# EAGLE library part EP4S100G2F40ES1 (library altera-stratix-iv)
EP4S100G2F40ES1 edit this description Auto generated by make-symbol-device-package-bsdl.ulp Rev. 29 Source: EP4S100G2F40ES1.bsd

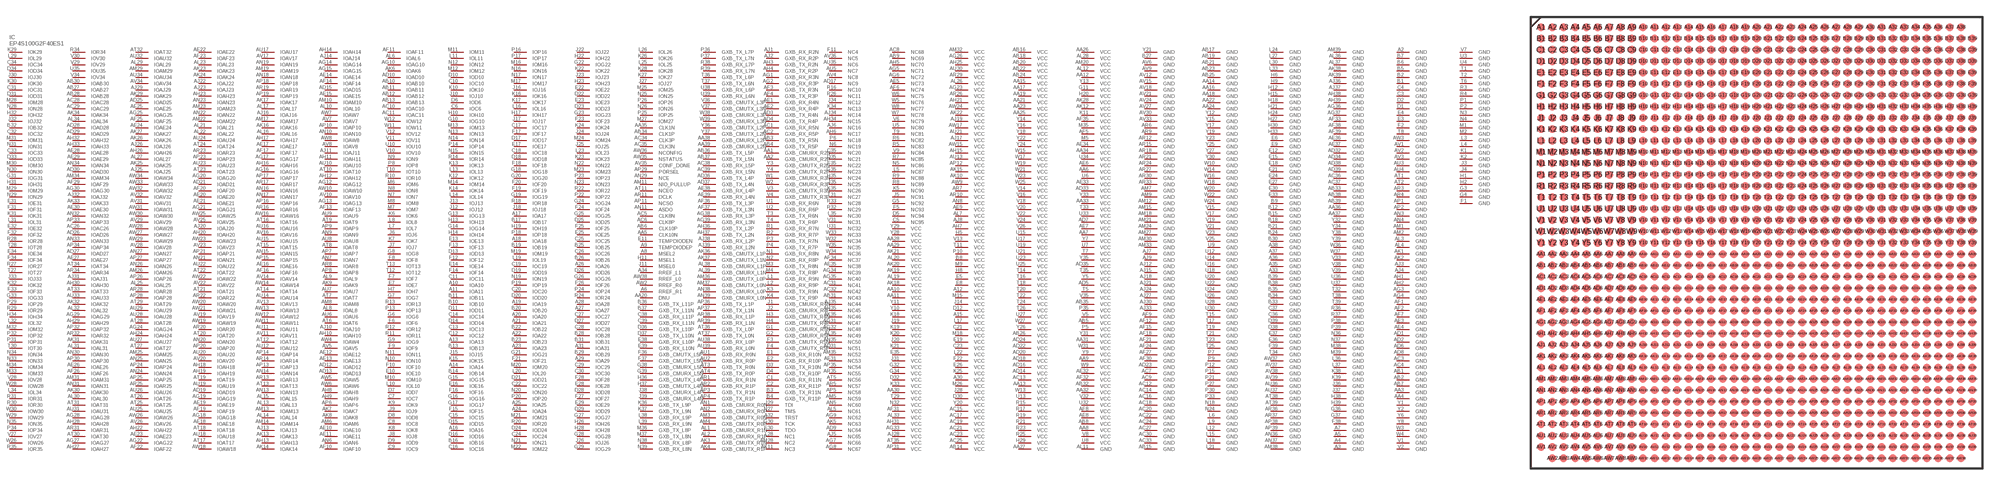
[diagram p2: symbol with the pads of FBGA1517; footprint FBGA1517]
Designator prefix IC

## EP4S100G2F40ES1 (MPN: EP4S100G2F40C2ES1; OC_FARNELL: unknown; OC_NEWARK: 52R2079)  [FBGA1517]
A2  GND  pwr
A3  GND  pwr
A4  GND  pwr
A5  GND  pwr
A6  RREF_R1  pas
A7  GND  pwr
A8  MSEL2  in
A9  TEMPDIODEP  in
A10  IOA10
A11  IOA11
A12  VCC  pwr
A13  IOA13
A14  IOA14
A15  VCC  pwr
A16  IOA16
A17  IOA17
A18  IOA18
A19  IOA19
A20  IOA20
A21  IOA21
A22  IOA22
A23  IOA23
A24  IOA24
A25  IOA25
A26  IOA26
A27  IOA27
A28  IOA28
A29  IOA29
A30  VCC  pwr
A31  IOA31
A32  TRST  in
A33  GND  pwr
A34  RREF_L1  pas
A35  GND  pwr
A36  GND  pwr
A37  GND  pwr
A38  GND  pwr
AA1  GXB_CMURX_R2N  pas
AA2  GXB_CMURX_R2P  pas
AA3  GND  pwr
AA4  GND  pwr
AA5  CLK10N  in
AA6  VCC  pwr
AA7  VCC  pwr
AA8  VCC  pwr
AA9  VCC  pwr
AA10  VCC  pwr
AA11  VCC  pwr
AA12  VCC  pwr
AA13  VCC  pwr
AA14  GND  pwr
AA15  VCC  pwr
AA16  GND  pwr
AA17  VCC  pwr
AA18  GND  pwr
AA19  VCC  pwr
AA20  DNU  pas
AA21  VCC  pwr
AA22  GND  pwr
AA23  VCC  pwr
AA24  GND  pwr
AA25  VCC  pwr
AA26  VCC  pwr
AA27  VCC  pwr
AA28  VCC  pwr
AA29  VCC  pwr
AA30  VCC  pwr
AA31  VCC  pwr
AA32  VCC  pwr
AA33  VCC  pwr
AA34  VCC  pwr
AA35  CLK1N  in
AA36  GND  pwr
AA37  GND  pwr
AA38  GXB_CMURX_L2P  pas
AA39  GXB_CMURX_L2N  pas
AB1  GND  pwr
AB2  GND  pwr
AB3  GXB_TX_R5N  pas
AB4  GXB_TX_R5P  pas
AB5  VCC  pwr
AB6  CLK10P  in
AB7  GND  pwr
AB8  VCC  pwr
AB9  NC69  pas
AB10  IOAB10
AB11  IOAB11
AB12  IOAB12
AB13  IOAB13
AB14  VCC  pwr
AB15  GND  pwr
AB16  VCC  pwr
AB17  GND  pwr
AB18  VCC  pwr
AB19  GND  pwr
AB20  VCC  pwr
AB21  GND  pwr
AB22  VCC  pwr
AB23  GND  pwr
AB24  VCC  pwr
AB25  GND  pwr
AB26  VCC  pwr
AB27  IOAB27
AB28  IOAB28
AB30  IOAB30
AB31  NC43  pas
AB32  VCC  pwr
AB33  GND  pwr
AB34  CLK1P  in
AB35  VCC  pwr
AB36  GXB_TX_L5P  pas
AB37  GXB_TX_L5N  pas
AB38  GND  pwr
AB39  GND  pwr
AC1  GXB_RX_R5N  pas
AC2  GXB_RX_R5P  pas
AC3  GND  pwr
AC4  GND  pwr
AC5  CLK8N  in
AC6  CLK8P  in
AC7  GND  pwr
AC8  NC68  pas
AC9  GND  pwr
AC10  IOAC10
AC11  IOAC11
AC12  GND  pwr
AC13  VCC  pwr
AC14  GND  pwr
AC15  VCC  pwr
AC16  GND  pwr
AC17  VCC  pwr
AC18  GND  pwr
AC19  VCC  pwr
AC20  GND  pwr
AC21  VCC  pwr
AC22  GND  pwr
AC23  VCC  pwr
AC24  GND  pwr
AC25  VCC  pwr
AC26  IOAC26
AC27  GND  pwr
AC28  IOAC28
AC29  IOAC29
AC30  GND  pwr
AC31  NC41  pas
AC32  NC42  pas
AC33  GND  pwr
AC34  CLK3P  in
AC35  CLK3N  in
AC36  GND  pwr
AC37  GND  pwr
AC38  GXB_RX_L5P  pas
AC39  GXB_RX_L5N  pas
AD1  GND  pwr
AD2  GND  pwr
AD3  GXB_TX_R4N  pas
AD4  GXB_TX_R4P  pas
AD5  VCC  pwr
AD6  GND  pwr
AD7  VCC  pwr
AD8  GND  pwr
AD9  NC64  pas
AD10  IOAD10
AD12  IOAD12
AD13  IOAD13
AD14  VCC  pwr
AD15  IOAD15
AD16  VCC  pwr
AD17  NC9  pas
AD18  VCC  pwr
AD19  IOAD19
AD20  VCC  pwr
AD21  IOAD21
AD22  VCC  pwr
AD23  GND  pwr
AD24  VCC  pwr
AD25  IOAD25
AD26  IOAD26
AD27  IOAD27
AD28  IOAD28
AD29  IOAD29
AD30  IOAD30
AD31  NC51  pas
AD32  GND  pwr
AD33  VCC  pwr
AD34  GND  pwr
AD35  VCC  pwr
AD36  GXB_TX_L4P  pas
AD37  GXB_TX_L4N  pas
AD38  GND  pwr
AD39  GND  pwr
AE1  GXB_RX_R4N  pas
AE2  GXB_RX_R4P  pas
AE3  GND  pwr
AE4  GND  pwr
AE5  NC73  pas
AE6  VCC  pwr
AE7  VCC  pwr
AE8  VCC  pwr
AE9  VCC  pwr
AE10  IOAE10
AE11  IOAE11
AE12  IOAE12
AE13  IOAE13
AE14  IOAE14
AE15  IOAE15
AE16  IOAE16
AE17  IOAE17
AE18  IOAE18
AE19  IOAE19
AE20  IOAE20
AE21  IOAE21
AE22  IOAE22
AE23  IOAE23
AE24  IOAE24
AE25  IOAE25
AE26  IOAE26
AE27  IOAE27
AE28  IOAE28
AE29  IOAE29
AE30  IOAE30
AE31  NC53  pas
AE32  VCC  pwr
AE33  VCC  pwr
AE34  VCC  pwr
AE35  NC38  pas
AE36  GND  pwr
AE37  GND  pwr
AE38  GXB_RX_L4P  pas
AE39  GXB_RX_L4N  pas
AF1  GND  pwr
AF2  GND  pwr
AF3  GXB_TX_R3N  pas
AF4  GXB_TX_R3P  pas
AF5  VCC  pwr
AF6  NC74  pas
AF7  GND  pwr
AF8  VCC  pwr
AF9  GND  pwr
AF10  IOAF10
AF11  IOAF11
AF12  GND  pwr
AF13  IOAF13
AF14  IOAF14
AF15  GND  pwr
AF16  IOAF16
AF17  IOAF17
AF18  GND  pwr
AF19  IOAF19
AF20  IOAF20
AF21  GND  pwr
AF22  IOAF22
AF23  IOAF23
AF24  GND  pwr
AF25  IOAF25
AF26  IOAF26
AF27  GND  pwr
AF29  IOAF29
AF30  GND  pwr
AF31  VCC  pwr
AF32  VCC  pwr
AF33  GND  pwr
AF34  NC37  pas
AF35  VCC  pwr
AF36  GXB_TX_L3P  pas
AF37  GXB_TX_L3N  pas
AF38  GND  pwr
AF39  GND  pwr
AG1  GXB_RX_R3N  pas
AG2  GXB_RX_R3P  pas
AG3  GND  pwr
AG4  GND  pwr
AG5  NC71  pas
AG6  NC72  pas
AG7  NC66  pas
AG8  NC67  pas
AG9  NC62  pas
AG10  IOAG10
AG12  IOAG12
AG13  IOAG13
AG14  IOAG14
AG15  IOAG15
AG16  IOAG16
AG17  IOAG17
AG18  IOAG18
AG19  IOAG19
AG20  IOAG20
AG21  IOAG21
AG22  IOAG22
AG23  VCC  pwr
AG24  IOAG24
AG25  IOAG25
AG26  VCC  pwr
AG27  IOAG27
AG28  IOAG28
AG29  IOAG29
AG30  IOAG30
AG31  NC47  pas
AG32  NC48  pas
AG33  VCC  pwr
AG34  NC39  pas
AG35  NC40  pas
AG36  GND  pwr
AG37  GND  pwr
AG38  GXB_RX_L3P  pas
AG39  GXB_RX_L3N  pas
AH1  GND  pwr
AH2  GND  pwr
AH3  GXB_TX_R2N  pas
AH4  GXB_TX_R2P  pas
AH5  NC70  pas
AH6  NC17  pas
AH7  VCC  pwr
AH8  IOAH8
AH9  IOAH9
AH10  IOAH10
AH11  IOAH11
AH12  IOAH12
AH13  IOAH13
AH14  IOAH14
AH15  VCC  pwr
AH16  IOAH16
AH17  IOAH17
AH18  IOAH18
AH19  IOAH19
AH20  IOAH20
AH21  VCC  pwr
AH22  IOAH22
AH23  IOAH23
AH24  IOAH24
AH25  VCC  pwr
AH26  IOAH26
AH27  IOAH27
AH28  IOAH28
AH29  IOAH29
AH30  IOAH30
AH31  VCC  pwr
AH32  IOAH32
AH33  IOAH33
AH34  NC15  pas
AH35  NC45  pas
AH36  GXB_TX_L2P  pas
AH37  GXB_TX_L2N  pas
AH38  GND  pwr
AH39  GND  pwr
AJ1  GXB_RX_R2N  pas
AJ2  GXB_RX_R2P  pas
AJ3  GND  pwr
AJ4  GND  pwr
AJ5  NC65  pas
AJ6  NC16  pas
AJ7  GND  pwr
AJ8  VCC  pwr
AJ9  GND  pwr
AJ10  IOAJ10
AJ11  IOAJ11
AJ12  GND  pwr
AJ13  IOAJ13
AJ14  IOAJ14
AJ15  GND  pwr
AJ16  IOAJ16
AJ17  VCC  pwr
AJ18  GND  pwr
AJ19  VCC  pwr
AJ20  IOAJ20
AJ21  GND  pwr
AJ22  IOAJ22
AJ23  IOAJ23
AJ24  GND  pwr
AJ25  IOAJ25
AJ26  IOAJ26
AJ27  GND  pwr
AJ28  VCC  pwr
AJ29  IOAJ29
AJ30  GND  pwr
AJ31  IOAJ31
AJ32  IOAJ32
AJ33  GND  pwr
AJ34  NC14  pas
AJ35  NC44  pas
AJ36  GND  pwr
AJ37  GND  pwr
AJ38  GXB_RX_L2P  pas
AJ39  GXB_RX_L2N  pas
AK1  GND  pwr
AK2  GND  pwr
AK3  GXB_CMUTX_R1N  pas
AK4  GXB_CMUTX_R1P  pas
AK5  NC63  pas
AK6  IOAK6
AK7  IOAK7
AK8  IOAK8
AK9  IOAK9
AK10  VCC  pwr
AK11  NC3  pas
AK12  VCC  pwr
AK13  IOAK13
AK14  IOAK14
AK15  VCC  pwr
AK16  IOAK16
AK17  IOAK17
AK18  VCC  pwr
AK19  VCC  pwr
AK20  VCC  pwr
AK21  VCC  pwr
AK22  VCC  pwr
AK23  IOAK23
AK24  IOAK24
AK25  IOAK25
AK26  IOAK26
AK27  IOAK27
AK28  VCC  pwr
AK29  IOAK29
AK30  IOAK30
AK31  IOAK31
AK32  IOAK32
AK33  IOAK33
AK34  IOAK34
AK35  NC46  pas
AK36  GXB_CMUTX_L1P  pas
AK37  GXB_CMUTX_L1N  pas
AK38  GND  pwr
AK39  GND  pwr
AL1  GXB_CMURX_R1N  pas
AL2  GXB_CMURX_R1P  pas
AL3  GND  pwr
AL4  GND  pwr
AL5  NC61  pas
AL6  IOAL6
AL7  VCC  pwr
AL8  IOAL8
AL9  IOAL9
AL10  IOAL10
AL11  GND  pwr
AL12  VCC  pwr
AL13  IOAL13
AL14  IOAL14
AL15  IOAL15
AL16  IOAL16
AL17  IOAL17
AL19  VCC  pwr
AL20  VCC  pwr
AL21  IOAL21
AL22  IOAL22
AL23  IOAL23
AL25  IOAL25
AL26  VCC  pwr
AL27  IOAL27
AL28  VCC  pwr
AL29  IOAL29
AL30  IOAL30
AL31  IOAL31
AL32  IOAL32
AL33  VCC  pwr
AL34  IOAL34
AL35  NC49  pas
AL36  GND  pwr
AL37  GND  pwr
AL38  GXB_CMURX_L1P  pas
AL39  GXB_CMURX_L1N  pas
AM1  GND  pwr
AM2  GND  pwr
AM3  GXB_CMUTX_R0N  pas
AM4  GXB_CMUTX_R0P  pas
AM5  NC59  pas
AM6  IOAM6
AM7  GND  pwr
AM8  IOAM8
AM9  GND  pwr
AM10  IOAM10
AM11  NIO_PULLUP  in
AM12  GND  pwr
AM13  IOAM13
AM14  IOAM14
AM15  GND  pwr
AM17  IOAM17
AM18  GND  pwr
AM19  IOAM19
AM20  VCC  pwr
AM21  GND  pwr
AM22  IOAM22
AM23  IOAM23
AM24  GND  pwr
AM25  IOAM25
AM26  IOAM26
AM27  GND  pwr
AM28  NC2  pas
AM29  IOAM29
AM30  GND  pwr
AM31  IOAM31
AM32  VCC  pwr
AM33  GND  pwr
AM34  IOAM34
AM35  NC52  pas
AM36  GXB_CMUTX_L0P  pas
AM37  GXB_CMUTX_L0N  pas
AM38  GND  pwr
AM39  GND  pwr
AN1  GXB_CMURX_R0N  pas
AN2  GXB_CMURX_R0P  pas
AN3  GND  pwr
AN4  GND  pwr
AN5  NC60  pas
AN6  IOAN6
AN7  IOAN7
AN8  VCC  pwr
AN9  IOAN9
AN10  IOAN10
AN11  ASDO  in
AN13  IOAN13
AN14  IOAN14
AN15  IOAN15
AN16  IOAN16
AN17  IOAN17
AN18  IOAN18
AN19  IOAN19
AN20  IOAN20
AN21  IOAN21
AN22  IOAN22
AN23  IOAN23
AN24  IOAN24
AN25  IOAN25
AN26  IOAN26
AN27  IOAN27
AN29  NCE  in
AN30  IOAN30
AN31  IOAN31
AN32  IOAN32
AN33  IOAN33
AN34  IOAN34
AN35  NC50  pas
AN36  GND  pwr
AN37  GND  pwr
AN38  GXB_CMURX_L0P  pas
AN39  GXB_CMURX_L0N  pas
AP1  GND  pwr
AP2  GND  pwr
AP3  GXB_TX_R1N  pas
AP4  GXB_TX_R1P  pas
AP5  NC58  pas
AP6  IOAP6
AP7  IOAP7
AP8  IOAP8
AP9  IOAP9
AP10  IOAP10
AP11  NCSO  in
AP12  VCC  pwr
AP13  IOAP13
AP14  IOAP14
AP15  IOAP15
AP16  IOAP16
AP17  IOAP17
AP18  IOAP18
AP19  IOAP19
AP20  IOAP20
AP21  IOAP21
AP23  IOAP23
AP24  IOAP24
AP25  IOAP25
AP26  IOAP26
AP27  IOAP27
AP28  IOAP28
AP29  PORSEL  in
AP30  IOAP30
AP31  VCC  pwr
AP32  IOAP32
AP33  IOAP33
AP34  IOAP34
AP35  NC54  pas
AP36  GXB_TX_L1P  pas
AP37  GXB_TX_L1N  pas
AP38  GND  pwr
AP39  GND  pwr
AR1  GXB_RX_R1N  pas
AR2  GXB_RX_R1P  pas
AR3  GND  pwr
AR4  GND  pwr
AR5  NC57  pas
AR6  GND  pwr
AR7  VCC  pwr
AR8  IOAR8
AR9  GND  pwr
AR10  VCC  pwr
AR11  DCLK  in
AR12  GND  pwr
AR13  IOAR13
AR14  IOAR14
AR15  GND  pwr
AR16  IOAR16
AR17  IOAR17
AR18  GND  pwr
AR19  IOAR19
AR20  IOAR20
AR21  GND  pwr
AR22  IOAR22
AR23  IOAR23
AR24  GND  pwr
AR25  IOAR25
AR26  VCC  pwr
AR27  GND  pwr
AR28  IOAR28
AR29  VCC  pwr
AR30  GND  pwr
AR31  IOAR31
AR32  IOAR32
AR33  GND  pwr
AR34  IOAR34
AR35  NC55  pas
AR36  GND  pwr
AR37  GND  pwr
AR38  GXB_RX_L1P  pas
AR39  GXB_RX_L1N  pas
AT1  GND  pwr
AT2  GND  pwr
AT3  GXB_TX_R0N  pas
AT4  GXB_TX_R0P  pas
AT5  NC56  pas
AT6  IOAT6
AT7  IOAT7
AT8  IOAT8
AT9  IOAT9
AT10  IOAT10
AT11  NCEO  in
AT12  IOAT12
AT13  IOAT13
AT14  IOAT14
AT15  IOAT15
AT16  IOAT16
AT17  IOAT17
AT18  IOAT18
AT19  IOAT19
AT20  IOAT20
AT21  IOAT21
AT22  IOAT22
AT23  IOAT23
AT24  IOAT24
AT25  IOAT25
AT26  IOAT26
AT27  IOAT27
AT28  IOAT28
AT29  IOAT29
AT30  IOAT30
AT31  IOAT31
AT32  IOAT32
AT33  IOAT33
AT34  IOAT34
AT35  VCC  pwr
AT36  GXB_TX_L0P  pas
AT37  GXB_TX_L0N  pas
AT38  GND  pwr
AT39  GND  pwr
AU1  GXB_RX_R0N  pas
AU2  GXB_RX_R0P  pas
AU3  GND  pwr
AU4  GND  pwr
AU5  NC7  pas
AU6  IOAU6
AU7  IOAU7
AU8  IOAU8
AU9  IOAU9
AU10  IOAU10
AU11  IOAU11
AU12  IOAU12
AU13  VCC  pwr
AU14  IOAU14
AU15  IOAU15
AU16  IOAU16
AU17  IOAU17
AU18  IOAU18
AU19  IOAU19
AU20  IOAU20
AU21  VCC  pwr
AU22  IOAU22
AU23  IOAU23
AU24  IOAU24
AU25  IOAU25
AU26  IOAU26
AU27  IOAU27
AU28  IOAU28
AU29  IOAU29
AU30  VCC  pwr
AU31  IOAU31
AU32  IOAU32
AU33  IOAU33
AU34  IOAU34
AU35  NC6  pas
AU36  GND  pwr
AU37  GND  pwr
AU38  GXB_RX_L0P  pas
AU39  GXB_RX_L0N  pas
AV1  GND  pwr
AV2  GND  pwr
AV3  GND  pwr
AV4  NC8  pas
AV5  IOAV5
AV6  GND  pwr
AV7  IOAV7
AV8  IOAV8
AV9  GND  pwr
AV10  IOAV10
AV11  IOAV11
AV12  GND  pwr
AV13  IOAV13
AV14  IOAV14
AV15  GND  pwr
AV16  IOAV16
AV17  IOAV17
AV18  GND  pwr
AV19  IOAV19
AV20  IOAV20
AV21  GND  pwr
AV22  IOAV22
AV23  IOAV23
AV24  GND  pwr
AV25  IOAV25
AV26  IOAV26
AV27  GND  pwr
AV28  IOAV28
AV29  IOAV29
AV30  GND  pwr
AV31  IOAV31
AV32  IOAV32
AV33  GND  pwr
AV34  IOAV34
AV35  CONF_DONE  in
AV36  NC5  pas
AV37  GND  pwr
AV38  GND  pwr
AV39  GND  pwr
AW2  RREF_R0  pas
AW3  GND  pwr
AW4  IOAW4
AW5  IOAW5
AW6  IOAW6
AW7  IOAW7
AW8  IOAW8
AW9  VCC  pwr
AW10  IOAW10
AW11  IOAW11
AW12  IOAW12
AW13  IOAW13
AW14  IOAW14
AW15  VCC  pwr
AW16  IOAW16
AW17  VCC  pwr
AW18  IOAW18
AW19  IOAW19
AW20  IOAW20
AW21  IOAW21
AW22  IOAW22
AW23  IOAW23
AW24  VCC  pwr
AW25  IOAW25
AW26  IOAW26
AW27  IOAW27
AW28  IOAW28
AW29  IOAW29
AW30  IOAW30
AW31  IOAW31
AW32  IOAW32
AW33  IOAW33
AW34  IOAW34
AW35  NSTATUS  in
AW36  NCONFIG  in
AW37  GND  pwr
AW38  RREF_L0  pas
B1  GND  pwr
B2  GND  pwr
B3  GXB_TX_R11N  pas
B4  GXB_TX_R11P  pas
B5  GND  pwr
B6  GND  pwr
B7  GND  pwr
B8  VCC  pwr
B9  GND  pwr
B10  IOB10
B11  IOB11
B12  GND  pwr
B13  IOB13
B14  IOB14
B15  GND  pwr
B16  IOB16
B17  IOB17
B18  GND  pwr
B19  IOB19
B20  IOB20
B21  GND  pwr
B22  IOB22
B23  IOB23
B24  GND  pwr
B25  IOB25
B26  IOB26
B27  GND  pwr
B28  IOB28
B29  IOB29
B30  GND  pwr
B31  IOB31
B32  IOB32
B33  GND  pwr
B34  GND  pwr
B35  GND  pwr
B36  GXB_TX_L11P  pas
B37  GXB_TX_L11N  pas
B38  GND  pwr
B39  GND  pwr
C1  GXB_RX_R11N  pas
C2  GXB_RX_R11P  pas
C3  GND  pwr
C4  GND  pwr
C5  NC95  pas
C6  IOC6
C7  IOC7
C8  IOC8
C9  IOC9
C10  IOC10
C11  IOC11
C12  IOC12
C13  IOC13
C14  IOC14
C15  IOC15
C16  IOC16
C17  IOC17
C18  IOC18
C19  IOC19
C20  IOC20
C21  VCC  pwr
C22  IOC22
C23  VCC  pwr
C24  IOC24
C25  IOC25
C26  IOC26
C27  IOC27
C28  IOC28
C29  IOC29
C30  IOC30
C31  IOC31
C32  IOC32
C33  IOC33
C34  IOC34
C35  NC20  pas
C36  GND  pwr
C37  GND  pwr
C38  GXB_RX_L11P  pas
C39  GXB_RX_L11N  pas
D1  GND  pwr
D2  GND  pwr
D3  GXB_TX_R10N  pas
D4  GXB_TX_R10P  pas
D5  NC94  pas
D6  IOD6
D7  IOD7
D8  IOD8
D9  IOD9
D10  IOD10
D11  IOD11
D12  VCC  pwr
D13  IOD13
D14  IOD14
D15  IOD15
D16  IOD16
D17  IOD17
D18  IOD18
D19  IOD19
D20  IOD20
D21  IOD21
D22  IOD22
D23  IOD23
D24  IOD24
D25  IOD25
D26  IOD26
D27  IOD27
D28  IOD28
D29  IOD29
D30  VCC  pwr
D31  IOD31
D32  VCC  pwr
D33  IOD33
D34  IOD34
D35  NC21  pas
D36  GXB_TX_L10P  pas
D37  GXB_TX_L10N  pas
D38  GND  pwr
D39  GND  pwr
E1  GXB_RX_R10N  pas
E2  GXB_RX_R10P  pas
E3  GND  pwr
E4  GND  pwr
E5  VCC  pwr
E6  GND  pwr
E7  IOE7
E8  VCC  pwr
E9  GND  pwr
E10  IOE10
E11  TEMPDIODEN  in
E12  GND  pwr
E13  IOE13
E14  IOE14
E15  GND  pwr
E16  IOE16
E17  IOE17
E18  GND  pwr
E19  VCC  pwr
E21  GND  pwr
E22  IOE22
E23  IOE23
E24  GND  pwr
E25  IOE25
E26  VCC  pwr
E27  GND  pwr
E28  IOE28
E29  IOE29
E30  GND  pwr
E31  IOE31
E32  IOE32
E33  GND  pwr
E34  IOE34
E35  VCC  pwr
E36  GND  pwr
E37  GND  pwr
E38  GXB_RX_L10P  pas
E39  GXB_RX_L10N  pas
F1  GND  pwr
F2  GND  pwr
F3  GXB_CMUTX_R5N  pas
F4  GXB_CMUTX_R5P  pas
F5  NC93  pas
F6  IOF6
F7  IOF7
F8  IOF8
F9  IOF9
F10  IOF10
F11  NC4  pas
F12  IOF12
F13  IOF13
F14  IOF14
F15  IOF15
F16  IOF16
F17  IOF17
F18  IOF18
F19  IOF19
F20  IOF20
F21  IOF21
F22  VCC  pwr
F23  IOF23
F24  IOF24
F25  IOF25
F26  IOF26
F27  IOF27
F28  IOF28
F30  TDO  out
F31  IOF31
F32  IOF32
F33  IOF33
F34  IOF34
F35  NC22  pas
F36  GXB_CMUTX_L5P  pas
F37  GXB_CMUTX_L5N  pas
F38  GND  pwr
F39  GND  pwr
G1  GXB_CMURX_R5N  pas
G2  GXB_CMURX_R5P  pas
G3  GND  pwr
G4  GND  pwr
G5  NC92  pas
G6  IOG6
G7  IOG7
G8  IOG8
G9  IOG9
G10  IOG10
G11  VCC  pwr
G13  IOG13
G14  IOG14
G15  IOG15
G16  IOG16
G17  IOG17
G18  IOG18
G19  IOG19
G20  IOG20
G21  IOG21
G22  IOG22
G23  IOG23
G24  IOG24
G25  IOG25
G26  IOG26
G27  IOG27
G28  IOG28
G29  IOG29
G30  TCK  in
G31  IOG31
G32  VCC  pwr
G33  IOG33
G34  VCC  pwr
G35  NC23  pas
G36  GND  pwr
G37  GND  pwr
G38  GXB_CMURX_L5P  pas
G39  GXB_CMURX_L5N  pas
H1  GND  pwr
H2  GND  pwr
H3  GXB_CMUTX_R4N  pas
H4  GXB_CMUTX_R4P  pas
H5  VCC  pwr
H6  GND  pwr
H7  IOH7
H8  VCC  pwr
H9  GND  pwr
H10  IOH10
H11  MSEL1  in
H12  GND  pwr
H13  IOH13
H14  IOH14
H15  GND  pwr
H17  IOH17
H18  GND  pwr
H19  IOH19
H20  VCC  pwr
H21  GND  pwr
H22  IOH22
H23  IOH23
H24  GND  pwr
H26  IOH26
H27  GND  pwr
H28  IOH28
H29  VCC  pwr
H30  GND  pwr
H31  IOH31
H32  IOH32
H33  GND  pwr
H34  IOH34
H35  NC24  pas
H36  GXB_CMUTX_L4P  pas
H37  GXB_CMUTX_L4N  pas
H38  GND  pwr
H39  GND  pwr
J1  GXB_CMURX_R4N  pas
J2  GXB_CMURX_R4P  pas
J3  GND  pwr
J4  GND  pwr
J5  NC91  pas
J6  IOJ6
J7  IOJ7
J8  IOJ8
J9  IOJ9
J10  IOJ10
J11  MSEL0  in
J12  IOJ12
J13  IOJ13
J14  VCC  pwr
J15  IOJ15
J16  IOJ16
J17  IOJ17
J18  IOJ18
J19  VCC  pwr
J20  VCC  pwr
J22  IOJ22
J23  IOJ23
J24  IOJ24
J25  IOJ25
J26  IOJ26
J27  IOJ27
J28  VCC  pwr
J29  TDI  in
J30  IOJ30
J31  VCC  pwr
J32  IOJ32
J33  IOJ33
J34  NC12  pas
J35  NC25  pas
J36  GND  pwr
J37  GND  pwr
J38  GXB_CMURX_L4P  pas
J39  GXB_CMURX_L4N  pas
K1  GND  pwr
K2  GND  pwr
K3  GXB_TX_R9N  pas
K4  GXB_TX_R9P  pas
K5  NC90  pas
K6  IOK6
K7  IOK7
K8  IOK8
K9  IOK9
K10  IOK10
K11  VCC  pwr
K12  IOK12
K13  IOK13
K14  IOK14
K15  IOK15
K16  IOK16
K17  IOK17
K18  VCC  pwr
K19  VCC  pwr
K20  VCC  pwr
K21  VCC  pwr
K22  IOK22
K23  IOK23
K24  IOK24
K25  VCC  pwr
K26  IOK26
K27  IOK27
K28  IOK28
K29  IOK29
K30  IOK30
K31  IOK31
K32  IOK32
K33  VCC  pwr
K34  NC13  pas
K35  NC26  pas
K36  GXB_TX_L9P  pas
K37  GXB_TX_L9N  pas
K38  GND  pwr
K39  GND  pwr
L1  GXB_RX_R9N  pas
L2  GXB_RX_R9P  pas
L3  GND  pwr
L4  GND  pwr
L5  NC87  pas
L6  GND  pwr
L7  IOL7
L8  IOL8
L9  GND  pwr
L10  IOL10
L11  IOL11
L12  GND  pwr
L13  IOL13
L14  IOL14
L15  GND  pwr
L16  IOL16
L17  VCC  pwr
L18  GND  pwr
L19  IOL19
L20  IOL20
L21  GND  pwr
L22  VCC  pwr
L23  IOL23
L24  GND  pwr
L25  IOL25
L26  IOL26
L27  GND  pwr
L28  NC1  pas
L29  IOL29
L30  GND  pwr
L31  IOL31
L32  IOL32
L33  GND  pwr
L34  IOL34
L35  NC30  pas
L36  GND  pwr
L37  GND  pwr
L38  GXB_RX_L9P  pas
L39  GXB_RX_L9N  pas
M1  GND  pwr
M2  GND  pwr
M3  GXB_TX_R8N  pas
M4  GXB_TX_R8P  pas
M5  VCC  pwr
M6  IOM6
M7  IOM7
M8  IOM8
M9  VCC  pwr
M10  IOM10
M11  IOM11
M12  IOM12
M13  IOM13
M14  IOM14
M15  VCC  pwr
M16  IOM16
M17  IOM17
M18  VCC  pwr
M19  IOM19
M20  IOM20
M21  IOM21
M22  IOM22
M23  IOM23
M24  IOM24
M25  IOM25
M26  VCC  pwr
M27  IOM27
M28  IOM28
M29  IOM29
M30  IOM30
M31  IOM31
M32  IOM32
M33  IOM33
M34  IOM34
M35  VCC  pwr
M36  GXB_TX_L8P  pas
M37  GXB_TX_L8N  pas
M38  GND  pwr
M39  GND  pwr
N1  GXB_RX_R8N  pas
N2  GXB_RX_R8P  pas
N3  GND  pwr
N4  GND  pwr
N5  NC86  pas
N6  NC19  pas
N7  ION7
N8  ION8
N9  ION9
N10  ION10
N11  ION11
N12  ION12
N13  ION13
N14  ION14
N15  ION15
N16  ION16
N17  ION17
N18  GND  pwr
N19  ION19
N20  ION20
N21  ION21
N22  ION22
N23  ION23
N24  GND  pwr
N25  ION25
N26  ION26
N27  TMS  in
N28  ION28
N29  ION29
N30  ION30
N31  ION31
N32  VCC  pwr
N33  ION33
N34  ION34
N35  ION35
N36  GND  pwr
N37  GND  pwr
N38  GXB_RX_L8P  pas
N39  GXB_RX_L8N  pas
P1  GND  pwr
P2  GND  pwr
P3  GXB_TX_R7N  pas
P4  GXB_TX_R7P  pas
P5  VCC  pwr
P6  NC18  pas
P7  GND  pwr
P8  IOP8
P9  GND  pwr
P10  VCC  pwr
P12  GND  pwr
P13  IOP13
P14  IOP14
P15  GND  pwr
P16  IOP16
P17  IOP17
P18  IOP18
P19  IOP19
P20  IOP20
P21  GND  pwr
P22  IOP22
P23  IOP23
P24  IOP24
P25  IOP25
P26  IOP26
P27  GND  pwr
P29  IOP29
P30  GND  pwr
P31  IOP31
P32  IOP32
P33  GND  pwr
P34  IOP34
P35  VCC  pwr
P36  GXB_TX_L7P  pas
P37  GXB_TX_L7N  pas
P38  GND  pwr
P39  GND  pwr
R1  GXB_RX_R7N  pas
R2  GXB_RX_R7P  pas
R3  GND  pwr
R4  GND  pwr
R5  NC83  pas
R6  NC82  pas
R7  NC85  pas
R8  NC89  pas
R9  NC88  pas
R10  IOR10
R11  IOR11
R12  IOR12
R13  IOR13
R14  IOR14
R15  VCC  pwr
R16  NC10  pas
R17  VCC  pwr
R18  IOR18
R19  VCC  pwr
R20  IOR20
R21  VCC  pwr
R22  IOR22
R23  VCC  pwr
R24  IOR24
R25  VCC  pwr
R26  NC11  pas
R27  IOR27
R28  IOR28
R29  IOR29
R30  IOR30
R31  IOR31
R32  NC29  pas
R33  NC28  pas
R34  IOR34
R35  IOR35
R36  GND  pwr
R37  GND  pwr
R38  GXB_RX_L7P  pas
R39  GXB_RX_L7N  pas
T1  GND  pwr
T2  GND  pwr
T3  GXB_TX_R6N  pas
T4  GXB_TX_R6P  pas
T5  VCC  pwr
T6  GND  pwr
T7  VCC  pwr
T8  GND  pwr
T9  NC81  pas
T10  IOT10
T11  VCC  pwr
T12  IOT12
T13  IOT13
T14  VCC  pwr
T15  GND  pwr
T16  VCC  pwr
T17  GND  pwr
T18  VCC  pwr
T19  GND  pwr
T20  VCC  pwr
T21  GND  pwr
T22  VCC  pwr
T23  GND  pwr
T24  VCC  pwr
T25  GND  pwr
T26  VCC  pwr
T27  IOT27
T28  IOT28
T29  VCC  pwr
T30  IOT30
T31  NC27  pas
T32  GND  pwr
T33  VCC  pwr
T34  GND  pwr
T35  VCC  pwr
T36  GXB_TX_L6P  pas
T37  GXB_TX_L6N  pas
T38  GND  pwr
T39  GND  pwr
U1  GXB_RX_R6N  pas
U2  GXB_RX_R6P  pas
U3  GND  pwr
U4  GND  pwr
U5  NC80  pas
U6  VCC  pwr
U7  VCC  pwr
U8  VCC  pwr
U9  GND  pwr
U10  IOU10
U12  GND  pwr
U13  VCC  pwr
U14  GND  pwr
U15  VCC  pwr
U16  GND  pwr
U17  VCC  pwr
U18  GND  pwr
U19  VCC  pwr
U20  GND  pwr
U21  VCC  pwr
U22  GND  pwr
U23  VCC  pwr
U24  GND  pwr
U25  VCC  pwr
U26  GND  pwr
U27  VCC  pwr
U28  GND  pwr
U30  GND  pwr
U31  NC32  pas
U32  VCC  pwr
U33  VCC  pwr
U34  VCC  pwr
U35  IOU35
U36  GND  pwr
U37  GND  pwr
U38  GXB_RX_L6P  pas
U39  GXB_RX_L6N  pas
V1  GND  pwr
V2  GND  pwr
V3  GXB_CMUTX_R3N  pas
V4  GXB_CMUTX_R3P  pas
V5  VCC  pwr
V6  NC79  pas
V7  GND  pwr
V8  VCC  pwr
V9  NC84  pas
V10  IOV10
V11  IOV11
V12  IOV12
V13  VCC  pwr
V14  VCC  pwr
V15  GND  pwr
V16  VCC  pwr
V17  GND  pwr
V18  VCC  pwr
V19  GND  pwr
V20  VCC  pwr
V21  GND  pwr
V22  VCC  pwr
V23  GND  pwr
V24  VCC  pwr
V25  GND  pwr
V26  VCC  pwr
V27  IOV27
V28  IOV28
V29  IOV29
V30  IOV30
V31  NC31  pas
V32  VCC  pwr
V33  GND  pwr
V34  IOV34
V35  VCC  pwr
V36  GXB_CMUTX_L3P  pas
V37  GXB_CMUTX_L3N  pas
V38  GND  pwr
V39  GND  pwr
W1  GXB_CMURX_R3N  pas
W2  GXB_CMURX_R3P  pas
W3  GND  pwr
W4  GND  pwr
W5  NC76  pas
W6  NC75  pas
W7  NC78  pas
W8  NC77  pas
W9  VCC  pwr
W10  GND  pwr
W11  IOW11
W12  IOW12
W13  VCC  pwr
W14  GND  pwr
W15  VCC  pwr
W16  GND  pwr
W17  VCC  pwr
W18  GND  pwr
W19  VCC  pwr
W20  GND  pwr
W21  VCC  pwr
W22  GND  pwr
W23  VCC  pwr
W24  GND  pwr
W25  VCC  pwr
W26  IOW26
W27  VCC  pwr
W28  IOW28
W29  IOW29
W30  IOW30
W31  VCC  pwr
W32  NC34  pas
W33  NC33  pas
W34  NC36  pas
W35  NC35  pas
W36  GND  pwr
W37  GND  pwr
W38  GXB_CMURX_L3P  pas
W39  GXB_CMURX_L3N  pas
Y1  GND  pwr
Y2  GND  pwr
Y3  GXB_CMUTX_R2N  pas
Y4  GXB_CMUTX_R2P  pas
Y5  VCC  pwr
Y6  GND  pwr
Y7  VCC  pwr
Y8  GND  pwr
Y9  VCC  pwr
Y10  VCC  pwr
Y11  VCC  pwr
Y12  GND  pwr
Y13  VCC  pwr
Y14  VCC  pwr
Y15  GND  pwr
Y16  VCC  pwr
Y17  GND  pwr
Y18  VCC  pwr
Y19  GND  pwr
Y20  VCC  pwr
Y21  GND  pwr
Y22  VCC  pwr
Y23  GND  pwr
Y24  VCC  pwr
Y25  GND  pwr
Y26  VCC  pwr
Y27  GND  pwr
Y28  VCC  pwr
Y29  VCC  pwr
Y30  GND  pwr
Y31  VCC  pwr
Y32  GND  pwr
Y33  VCC  pwr
Y34  GND  pwr
Y35  VCC  pwr
Y36  GXB_CMUTX_L2P  pas
Y37  GXB_CMUTX_L2N  pas
Y38  GND  pwr
Y39  GND  pwr

## Footprint FBGA1517 (pad centres in mm)
1517-Pin FineLine Ball-Grid Array (FBGA), Option 1 ? Flip Chip Auto generated by make-symbol-device-package-bsdl.ulp Rev. 29 Source: EP4S40G2F40ES1.bsd http://www.altera.com .. dspkg.pdf
smd 0.7 x 0.7: A1 -19,19; A2 -18,19; A3 -17,19; A4 -16,19; A5 -15,19; A6 -14,19; A7 -13,19; A8 -12,19; A9 -11,19; A10 -10,19; A11 -9,19; A12 -8,19; A13 -7,19; A14 -6,19; A15 -5,19; A16 -4,19; A17 -3,19; A18 -2,19; A19 -1,19; A20 0,19; A21 1,19; A22 2,19; A23 3,19; A24 4,19; A25 5,19; A26 6,19; A27 7,19; A28 8,19; A29 9,19; A30 10,19; A31 11,19; A32 12,19; A33 13,19; A34 14,19; A35 15,19; A36 16,19; A37 17,19; A38 18,19; AA1 -19,-1; AA2 -18,-1; AA3 -17,-1; AA4 -16,-1; AA5 -15,-1; AA6 -14,-1; AA7 -13,-1; AA8 -12,-1; AA9 -11,-1; AA10 -10,-1; AA11 -9,-1; AA12 -8,-1; AA13 -7,-1; AA14 -6,-1; AA15 -5,-1; AA16 -4,-1; AA17 -3,-1; AA18 -2,-1; AA19 -1,-1; AA20 0,-1; AA21 1,-1; AA22 2,-1; AA23 3,-1; AA24 4,-1; AA25 5,-1; AA26 6,-1; AA27 7,-1; AA28 8,-1; AA29 9,-1; AA30 10,-1; AA31 11,-1; AA32 12,-1; AA33 13,-1; AA34 14,-1; AA35 15,-1; AA36 16,-1; AA37 17,-1; AA38 18,-1; AA39 19,-1; AB1 -19,-2; AB2 -18,-2; AB3 -17,-2; AB4 -16,-2; AB5 -15,-2; AB6 -14,-2; AB7 -13,-2; AB8 -12,-2; AB9 -11,-2; AB10 -10,-2; AB11 -9,-2; AB12 -8,-2; AB13 -7,-2; AB14 -6,-2; AB15 -5,-2; AB16 -4,-2; AB17 -3,-2; AB18 -2,-2; AB19 -1,-2; AB20 0,-2; AB21 1,-2; AB22 2,-2; AB23 3,-2; AB24 4,-2; AB25 5,-2; AB26 6,-2; AB27 7,-2; AB28 8,-2; AB29 9,-2; AB30 10,-2; AB31 11,-2; AB32 12,-2; AB33 13,-2; AB34 14,-2; AB35 15,-2; AB36 16,-2; AB37 17,-2; AB38 18,-2; AB39 19,-2; AC1 -19,-3; AC2 -18,-3; AC3 -17,-3; AC4 -16,-3; AC5 -15,-3; AC6 -14,-3; AC7 -13,-3; AC8 -12,-3; AC9 -11,-3; AC10 -10,-3; AC11 -9,-3; AC12 -8,-3; AC13 -7,-3; AC14 -6,-3; AC15 -5,-3; AC16 -4,-3; AC17 -3,-3; AC18 -2,-3; AC19 -1,-3; AC20 0,-3; AC21 1,-3; AC22 2,-3; AC23 3,-3; AC24 4,-3; AC25 5,-3; AC26 6,-3; AC27 7,-3; AC28 8,-3; AC29 9,-3; AC30 10,-3; AC31 11,-3; AC32 12,-3; AC33 13,-3; AC34 14,-3; AC35 15,-3; AC36 16,-3; AC37 17,-3; AC38 18,-3; AC39 19,-3; AD1 -19,-4; AD2 -18,-4; AD3 -17,-4; AD4 -16,-4; AD5 -15,-4; AD6 -14,-4; AD7 -13,-4; AD8 -12,-4; AD9 -11,-4; AD10 -10,-4; AD11 -9,-4; AD12 -8,-4; AD13 -7,-4; AD14 -6,-4; AD15 -5,-4; AD16 -4,-4; AD17 -3,-4; AD18 -2,-4; AD19 -1,-4; AD20 0,-4; AD21 1,-4; AD22 2,-4; AD23 3,-4; AD24 4,-4; AD25 5,-4; AD26 6,-4; AD27 7,-4; AD28 8,-4; AD29 9,-4; AD30 10,-4; AD31 11,-4; AD32 12,-4; AD33 13,-4; AD34 14,-4; AD35 15,-4; AD36 16,-4; AD37 17,-4; AD38 18,-4; AD39 19,-4; AE1 -19,-5; AE2 -18,-5; AE3 -17,-5; AE4 -16,-5; AE5 -15,-5; AE6 -14,-5; AE7 -13,-5; AE8 -12,-5; AE9 -11,-5; AE10 -10,-5; AE11 -9,-5; AE12 -8,-5; AE13 -7,-5; AE14 -6,-5; AE15 -5,-5; AE16 -4,-5; AE17 -3,-5; AE18 -2,-5; AE19 -1,-5; AE20 0,-5; AE21 1,-5; AE22 2,-5; AE23 3,-5; AE24 4,-5; AE25 5,-5; AE26 6,-5; AE27 7,-5; AE28 8,-5; AE29 9,-5; AE30 10,-5; AE31 11,-5; AE32 12,-5; AE33 13,-5; AE34 14,-5; AE35 15,-5; AE36 16,-5; AE37 17,-5; AE38 18,-5; AE39 19,-5; AF1 -19,-6; AF2 -18,-6; AF3 -17,-6; AF4 -16,-6; AF5 -15,-6; AF6 -14,-6; AF7 -13,-6; AF8 -12,-6; AF9 -11,-6; AF10 -10,-6; AF11 -9,-6; AF12 -8,-6; AF13 -7,-6; AF14 -6,-6; AF15 -5,-6; AF16 -4,-6; AF17 -3,-6; AF18 -2,-6; AF19 -1,-6; AF20 0,-6; AF21 1,-6; AF22 2,-6; AF23 3,-6; AF24 4,-6; AF25 5,-6; AF26 6,-6; AF27 7,-6; AF28 8,-6; AF29 9,-6; AF30 10,-6; AF31 11,-6; AF32 12,-6; AF33 13,-6; AF34 14,-6; AF35 15,-6; AF36 16,-6; AF37 17,-6; AF38 18,-6; AF39 19,-6; AG1 -19,-7; AG2 -18,-7; AG3 -17,-7; AG4 -16,-7; AG5 -15,-7; AG6 -14,-7; AG7 -13,-7; AG8 -12,-7; AG9 -11,-7; AG10 -10,-7; AG11 -9,-7; AG12 -8,-7; AG13 -7,-7; AG14 -6,-7; AG15 -5,-7; AG16 -4,-7; AG17 -3,-7; AG18 -2,-7; AG19 -1,-7; AG20 0,-7; AG21 1,-7; AG22 2,-7; AG23 3,-7; AG24 4,-7; AG25 5,-7; AG26 6,-7; AG27 7,-7; AG28 8,-7; AG29 9,-7; AG30 10,-7; AG31 11,-7; AG32 12,-7; AG33 13,-7; AG34 14,-7; AG35 15,-7; AG36 16,-7; AG37 17,-7; AG38 18,-7; AG39 19,-7; AH1 -19,-8; AH2 -18,-8; AH3 -17,-8; AH4 -16,-8; AH5 -15,-8; AH6 -14,-8; AH7 -13,-8; AH8 -12,-8; AH9 -11,-8; AH10 -10,-8; AH11 -9,-8; AH12 -8,-8; AH13 -7,-8; AH14 -6,-8; AH15 -5,-8; AH16 -4,-8; AH17 -3,-8; AH18 -2,-8; AH19 -1,-8; AH20 0,-8; AH21 1,-8; AH22 2,-8; AH23 3,-8; AH24 4,-8; AH25 5,-8; AH26 6,-8; AH27 7,-8; AH28 8,-8; AH29 9,-8; AH30 10,-8; AH31 11,-8; AH32 12,-8; AH33 13,-8; AH34 14,-8; AH35 15,-8; AH36 16,-8; AH37 17,-8; AH38 18,-8; AH39 19,-8; AJ1 -19,-9; AJ2 -18,-9; AJ3 -17,-9; AJ4 -16,-9; AJ5 -15,-9; AJ6 -14,-9; AJ7 -13,-9; AJ8 -12,-9; AJ9 -11,-9; AJ10 -10,-9; AJ11 -9,-9; AJ12 -8,-9; AJ13 -7,-9; AJ14 -6,-9; AJ15 -5,-9; AJ16 -4,-9; AJ17 -3,-9; AJ18 -2,-9; AJ19 -1,-9; AJ20 0,-9; AJ21 1,-9; AJ22 2,-9; AJ23 3,-9; AJ24 4,-9; AJ25 5,-9; AJ26 6,-9; AJ27 7,-9; AJ28 8,-9; AJ29 9,-9; AJ30 10,-9; AJ31 11,-9; AJ32 12,-9; AJ33 13,-9; AJ34 14,-9; AJ35 15,-9; AJ36 16,-9; AJ37 17,-9; AJ38 18,-9; AJ39 19,-9; AK1 -19,-10; AK2 -18,-10; AK3 -17,-10; AK4 -16,-10; AK5 -15,-10; AK6 -14,-10; AK7 -13,-10; AK8 -12,-10; AK9 -11,-10; AK10 -10,-10; AK11 -9,-10; AK12 -8,-10; AK13 -7,-10; AK14 -6,-10; AK15 -5,-10; AK16 -4,-10; AK17 -3,-10; AK18 -2,-10; AK19 -1,-10; AK20 0,-10; AK21 1,-10; AK22 2,-10; AK23 3,-10; AK24 4,-10; AK25 5,-10; AK26 6,-10; AK27 7,-10; AK28 8,-10; AK29 9,-10; AK30 10,-10; AK31 11,-10; AK32 12,-10; AK33 13,-10; AK34 14,-10; AK35 15,-10; AK36 16,-10; AK37 17,-10; AK38 18,-10; AK39 19,-10; AL1 -19,-11; AL2 -18,-11; AL3 -17,-11; AL4 -16,-11; AL5 -15,-11; AL6 -14,-11; AL7 -13,-11; AL8 -12,-11; AL9 -11,-11; AL10 -10,-11; AL11 -9,-11; AL12 -8,-11; AL13 -7,-11; AL14 -6,-11; AL15 -5,-11; AL16 -4,-11; AL17 -3,-11; AL18 -2,-11; AL19 -1,-11; AL20 0,-11; AL21 1,-11; AL22 2,-11; AL23 3,-11; AL24 4,-11; AL25 5,-11; AL26 6,-11; AL27 7,-11; AL28 8,-11; AL29 9,-11; AL30 10,-11; AL31 11,-11; AL32 12,-11; AL33 13,-11; AL34 14,-11; AL35 15,-11; AL36 16,-11; AL37 17,-11; AL38 18,-11; AL39 19,-11; AM1 -19,-12; AM2 -18,-12; AM3 -17,-12; AM4 -16,-12; AM5 -15,-12; AM6 -14,-12; AM7 -13,-12; AM8 -12,-12; AM9 -11,-12; AM10 -10,-12; AM11 -9,-12; AM12 -8,-12; AM13 -7,-12; AM14 -6,-12; AM15 -5,-12; AM16 -4,-12; AM17 -3,-12; AM18 -2,-12; AM19 -1,-12; AM20 0,-12; AM21 1,-12; AM22 2,-12; AM23 3,-12; AM24 4,-12; AM25 5,-12; AM26 6,-12; AM27 7,-12; AM28 8,-12; AM29 9,-12; AM30 10,-12; AM31 11,-12; AM32 12,-12; AM33 13,-12; AM34 14,-12; AM35 15,-12; AM36 16,-12; AM37 17,-12; AM38 18,-12; AM39 19,-12; AN1 -19,-13; AN2 -18,-13; AN3 -17,-13; AN4 -16,-13; AN5 -15,-13; AN6 -14,-13; AN7 -13,-13; AN8 -12,-13; AN9 -11,-13; AN10 -10,-13; AN11 -9,-13; AN12 -8,-13; AN13 -7,-13; AN14 -6,-13; AN15 -5,-13; AN16 -4,-13; AN17 -3,-13; AN18 -2,-13; AN19 -1,-13; AN20 0,-13; AN21 1,-13; AN22 2,-13; AN23 3,-13; AN24 4,-13; AN25 5,-13; AN26 6,-13; AN27 7,-13; AN28 8,-13; AN29 9,-13; AN30 10,-13; AN31 11,-13; AN32 12,-13; AN33 13,-13; AN34 14,-13; AN35 15,-13; AN36 16,-13; AN37 17,-13; AN38 18,-13; AN39 19,-13; AP1 -19,-14; AP2 -18,-14; AP3 -17,-14; AP4 -16,-14; AP5 -15,-14; AP6 -14,-14; AP7 -13,-14; AP8 -12,-14; AP9 -11,-14; AP10 -10,-14; AP11 -9,-14; AP12 -8,-14; AP13 -7,-14; AP14 -6,-14; AP15 -5,-14; AP16 -4,-14; AP17 -3,-14; AP18 -2,-14; AP19 -1,-14; AP20 0,-14; AP21 1,-14; AP22 2,-14; AP23 3,-14; AP24 4,-14; AP25 5,-14; AP26 6,-14; AP27 7,-14; AP28 8,-14; AP29 9,-14; AP30 10,-14; AP31 11,-14; AP32 12,-14; AP33 13,-14; AP34 14,-14; AP35 15,-14; AP36 16,-14; AP37 17,-14; AP38 18,-14; AP39 19,-14; AR1 -19,-15; AR2 -18,-15; AR3 -17,-15; AR4 -16,-15; AR5 -15,-15; AR6 -14,-15; AR7 -13,-15; AR8 -12,-15; AR9 -11,-15; AR10 -10,-15; AR11 -9,-15; AR12 -8,-15; AR13 -7,-15; AR14 -6,-15; AR15 -5,-15; AR16 -4,-15; AR17 -3,-15; AR18 -2,-15; AR19 -1,-15; AR20 0,-15; AR21 1,-15; AR22 2,-15; AR23 3,-15; AR24 4,-15; AR25 5,-15; AR26 6,-15; AR27 7,-15; AR28 8,-15; AR29 9,-15; AR30 10,-15; AR31 11,-15; AR32 12,-15; AR33 13,-15; AR34 14,-15; AR35 15,-15; AR36 16,-15; AR37 17,-15; AR38 18,-15; AR39 19,-15; AT1 -19,-16; AT2 -18,-16; AT3 -17,-16; AT4 -16,-16; AT5 -15,-16; AT6 -14,-16; AT7 -13,-16; AT8 -12,-16; AT9 -11,-16; AT10 -10,-16; AT11 -9,-16; AT12 -8,-16; AT13 -7,-16; AT14 -6,-16; AT15 -5,-16; AT16 -4,-16; AT17 -3,-16; AT18 -2,-16; AT19 -1,-16; AT20 0,-16; AT21 1,-16; AT22 2,-16; AT23 3,-16; AT24 4,-16; AT25 5,-16; AT26 6,-16; AT27 7,-16; AT28 8,-16; AT29 9,-16; AT30 10,-16; AT31 11,-16; AT32 12,-16; AT33 13,-16; AT34 14,-16; AT35 15,-16; AT36 16,-16; AT37 17,-16; AT38 18,-16; AT39 19,-16; AU1 -19,-17; AU2 -18,-17; AU3 -17,-17; AU4 -16,-17; AU5 -15,-17; AU6 -14,-17; AU7 -13,-17; AU8 -12,-17; AU9 -11,-17; AU10 -10,-17; AU11 -9,-17; AU12 -8,-17; AU13 -7,-17; AU14 -6,-17; AU15 -5,-17; AU16 -4,-17; AU17 -3,-17; AU18 -2,-17; AU19 -1,-17; AU20 0,-17; AU21 1,-17; AU22 2,-17; AU23 3,-17; AU24 4,-17; AU25 5,-17; AU26 6,-17; AU27 7,-17; AU28 8,-17; AU29 9,-17; AU30 10,-17; AU31 11,-17; AU32 12,-17; AU33 13,-17; AU34 14,-17; AU35 15,-17; AU36 16,-17; AU37 17,-17; AU38 18,-17; AU39 19,-17; AV1 -19,-18; AV2 -18,-18; AV3 -17,-18; AV4 -16,-18; AV5 -15,-18; AV6 -14,-18; AV7 -13,-18; AV8 -12,-18; AV9 -11,-18; AV10 -10,-18; AV11 -9,-18; AV12 -8,-18; AV13 -7,-18; AV14 -6,-18; AV15 -5,-18; AV16 -4,-18; AV17 -3,-18; AV18 -2,-18; AV19 -1,-18; AV20 0,-18; AV21 1,-18; AV22 2,-18; AV23 3,-18; AV24 4,-18; AV25 5,-18; AV26 6,-18; AV27 7,-18; AV28 8,-18; AV29 9,-18; AV30 10,-18; AV31 11,-18; AV32 12,-18; AV33 13,-18; AV34 14,-18; AV35 15,-18; AV36 16,-18; AV37 17,-18; AV38 18,-18; AV39 19,-18; AW2 -18,-19; AW3 -17,-19; AW4 -16,-19; AW5 -15,-19; AW6 -14,-19; AW7 -13,-19; AW8 -12,-19; AW9 -11,-19; AW10 -10,-19; AW11 -9,-19; AW12 -8,-19; AW13 -7,-19; AW14 -6,-19; AW15 -5,-19; AW16 -4,-19; AW17 -3,-19; AW18 -2,-19; AW19 -1,-19; AW20 0,-19; AW21 1,-19; AW22 2,-19; AW23 3,-19; AW24 4,-19; AW25 5,-19; AW26 6,-19; AW27 7,-19; AW28 8,-19; AW29 9,-19; AW30 10,-19; AW31 11,-19; AW32 12,-19; AW33 13,-19; AW34 14,-19; AW35 15,-19; AW36 16,-19; AW37 17,-19; AW38 18,-19; B1 -19,18; B2 -18,18; B3 -17,18; B4 -16,18; B5 -15,18; B6 -14,18; B7 -13,18; B8 -12,18; B9 -11,18; B10 -10,18; B11 -9,18; B12 -8,18; B13 -7,18; B14 -6,18; B15 -5,18; B16 -4,18; B17 -3,18; B18 -2,18; B19 -1,18; B20 0,18; B21 1,18; B22 2,18; B23 3,18; B24 4,18; B25 5,18; B26 6,18; B27 7,18; B28 8,18; B29 9,18; B30 10,18; B31 11,18; B32 12,18; B33 13,18; B34 14,18; B35 15,18; B36 16,18; B37 17,18; B38 18,18; B39 19,18; C1 -19,17; C2 -18,17; C3 -17,17; C4 -16,17; C5 -15,17; C6 -14,17; C7 -13,17; C8 -12,17; C9 -11,17; C10 -10,17; C11 -9,17; C12 -8,17; C13 -7,17; C14 -6,17; C15 -5,17; C16 -4,17; C17 -3,17; C18 -2,17; C19 -1,17; C20 0,17; C21 1,17; C22 2,17; C23 3,17; C24 4,17; C25 5,17; C26 6,17; C27 7,17; C28 8,17; C29 9,17; C30 10,17; C31 11,17; C32 12,17; C33 13,17; C34 14,17; C35 15,17; C36 16,17; C37 17,17; C38 18,17; C39 19,17; D1 -19,16; D2 -18,16; D3 -17,16; D4 -16,16; D5 -15,16; D6 -14,16; D7 -13,16; D8 -12,16; D9 -11,16; D10 -10,16; D11 -9,16; D12 -8,16; D13 -7,16; D14 -6,16; D15 -5,16; D16 -4,16; D17 -3,16; D18 -2,16; D19 -1,16; D20 0,16; D21 1,16; D22 2,16; D23 3,16; D24 4,16; D25 5,16; D26 6,16; D27 7,16; D28 8,16; D29 9,16; D30 10,16; D31 11,16; D32 12,16; D33 13,16; D34 14,16; D35 15,16; D36 16,16; D37 17,16; D38 18,16; D39 19,16; E1 -19,15; E2 -18,15; E3 -17,15; E4 -16,15; E5 -15,15; E6 -14,15; E7 -13,15; E8 -12,15; E9 -11,15; E10 -10,15; E11 -9,15; E12 -8,15; E13 -7,15; E14 -6,15; E15 -5,15; E16 -4,15; E17 -3,15; E18 -2,15; E19 -1,15; E20 0,15; E21 1,15; E22 2,15; E23 3,15; E24 4,15; E25 5,15; E26 6,15; E27 7,15; E28 8,15; E29 9,15; E30 10,15; E31 11,15; E32 12,15; E33 13,15; E34 14,15; E35 15,15; E36 16,15; E37 17,15; E38 18,15; E39 19,15; F1 -19,14; F2 -18,14; F3 -17,14; F4 -16,14; F5 -15,14; F6 -14,14; F7 -13,14; F8 -12,14; F9 -11,14; F10 -10,14; F11 -9,14; F12 -8,14; F13 -7,14; F14 -6,14; F15 -5,14; F16 -4,14; F17 -3,14; F18 -2,14; F19 -1,14; F20 0,14; F21 1,14; F22 2,14; F23 3,14; F24 4,14; F25 5,14; F26 6,14; F27 7,14; F28 8,14; F29 9,14; F30 10,14; F31 11,14; F32 12,14; F33 13,14; F34 14,14; F35 15,14; F36 16,14; F37 17,14; F38 18,14; F39 19,14; G1 -19,13; G2 -18,13; G3 -17,13; G4 -16,13; G5 -15,13; G6 -14,13; G7 -13,13; G8 -12,13; G9 -11,13; G10 -10,13; G11 -9,13; G12 -8,13; G13 -7,13; G14 -6,13; G15 -5,13; G16 -4,13; G17 -3,13; G18 -2,13; G19 -1,13; G20 0,13; G21 1,13; G22 2,13; G23 3,13; G24 4,13; G25 5,13; G26 6,13; G27 7,13; G28 8,13; G29 9,13; G30 10,13; G31 11,13; G32 12,13; G33 13,13; G34 14,13; G35 15,13; G36 16,13; G37 17,13; G38 18,13; G39 19,13; H1 -19,12; H2 -18,12; H3 -17,12; H4 -16,12; H5 -15,12; H6 -14,12; H7 -13,12; H8 -12,12; H9 -11,12; H10 -10,12; H11 -9,12; H12 -8,12; H13 -7,12; H14 -6,12; H15 -5,12; H16 -4,12; H17 -3,12; H18 -2,12; H19 -1,12; H20 0,12; H21 1,12; H22 2,12; H23 3,12; H24 4,12; H25 5,12; H26 6,12; H27 7,12; H28 8,12; H29 9,12; H30 10,12; H31 11,12; H32 12,12; H33 13,12; H34 14,12; H35 15,12; H36 16,12; H37 17,12; H38 18,12; H39 19,12; J1 -19,11; J2 -18,11; J3 -17,11; J4 -16,11; J5 -15,11; J6 -14,11; J7 -13,11; J8 -12,11; J9 -11,11; J10 -10,11; J11 -9,11; J12 -8,11; J13 -7,11; J14 -6,11; J15 -5,11; J16 -4,11; J17 -3,11; J18 -2,11; J19 -1,11; J20 0,11; J21 1,11; J22 2,11; J23 3,11; J24 4,11; J25 5,11; J26 6,11; J27 7,11; J28 8,11; J29 9,11; J30 10,11; J31 11,11; J32 12,11; J33 13,11; J34 14,11; J35 15,11; J36 16,11; J37 17,11; J38 18,11; J39 19,11; K1 -19,10; K2 -18,10; K3 -17,10; K4 -16,10; K5 -15,10; K6 -14,10; K7 -13,10; K8 -12,10; K9 -11,10; K10 -10,10; K11 -9,10; K12 -8,10; K13 -7,10; K14 -6,10; K15 -5,10; K16 -4,10; K17 -3,10; K18 -2,10; K19 -1,10; K20 0,10; K21 1,10; K22 2,10; K23 3,10; K24 4,10; K25 5,10; K26 6,10; K27 7,10; K28 8,10; K29 9,10; K30 10,10; K31 11,10; K32 12,10; K33 13,10; K34 14,10; K35 15,10; K36 16,10; K37 17,10; K38 18,10; K39 19,10; L1 -19,9; L2 -18,9; L3 -17,9; L4 -16,9; L5 -15,9; L6 -14,9; L7 -13,9; L8 -12,9; L9 -11,9; L10 -10,9; L11 -9,9; L12 -8,9; L13 -7,9; L14 -6,9; L15 -5,9; L16 -4,9; L17 -3,9; L18 -2,9; L19 -1,9; L20 0,9; L21 1,9; L22 2,9; L23 3,9; L24 4,9; L25 5,9; L26 6,9; L27 7,9; L28 8,9; L29 9,9; L30 10,9; L31 11,9; L32 12,9; L33 13,9; L34 14,9; L35 15,9; L36 16,9; L37 17,9; L38 18,9; L39 19,9; M1 -19,8; M2 -18,8; M3 -17,8; M4 -16,8; M5 -15,8; M6 -14,8; M7 -13,8; M8 -12,8; M9 -11,8; M10 -10,8; M11 -9,8; M12 -8,8; M13 -7,8; M14 -6,8; M15 -5,8; M16 -4,8; M17 -3,8; M18 -2,8; M19 -1,8; M20 0,8; M21 1,8; M22 2,8; M23 3,8; M24 4,8; M25 5,8; M26 6,8; M27 7,8; M28 8,8; M29 9,8; M30 10,8; M31 11,8; M32 12,8; M33 13,8; M34 14,8; M35 15,8; M36 16,8; M37 17,8; M38 18,8; M39 19,8; N1 -19,7; N2 -18,7; N3 -17,7; N4 -16,7; N5 -15,7; N6 -14,7; N7 -13,7; N8 -12,7; N9 -11,7; N10 -10,7; N11 -9,7; N12 -8,7; N13 -7,7; N14 -6,7; N15 -5,7; N16 -4,7; N17 -3,7; N18 -2,7; N19 -1,7; N20 0,7; N21 1,7; N22 2,7; N23 3,7; N24 4,7; N25 5,7; N26 6,7; N27 7,7; N28 8,7; N29 9,7; N30 10,7; N31 11,7; N32 12,7; N33 13,7; N34 14,7; N35 15,7; N36 16,7; N37 17,7; N38 18,7; N39 19,7; P1 -19,6; P2 -18,6; P3 -17,6; P4 -16,6; P5 -15,6; P6 -14,6; P7 -13,6; P8 -12,6; P9 -11,6; P10 -10,6; P11 -9,6; P12 -8,6; P13 -7,6; P14 -6,6; P15 -5,6; P16 -4,6; P17 -3,6; P18 -2,6; P19 -1,6; P20 0,6; P21 1,6; P22 2,6; P23 3,6; P24 4,6; P25 5,6; P26 6,6; P27 7,6; P28 8,6; P29 9,6; P30 10,6; P31 11,6; P32 12,6; P33 13,6; P34 14,6; P35 15,6; P36 16,6; P37 17,6; P38 18,6; P39 19,6; R1 -19,5; R2 -18,5; R3 -17,5; R4 -16,5; R5 -15,5; R6 -14,5; R7 -13,5; R8 -12,5; R9 -11,5; R10 -10,5; R11 -9,5; R12 -8,5; R13 -7,5; R14 -6,5; R15 -5,5; R16 -4,5; R17 -3,5; R18 -2,5; R19 -1,5; R20 0,5; R21 1,5; R22 2,5; R23 3,5; R24 4,5; R25 5,5; R26 6,5; R27 7,5; R28 8,5; R29 9,5; R30 10,5; R31 11,5; R32 12,5; R33 13,5; R34 14,5; R35 15,5; R36 16,5; R37 17,5; R38 18,5; R39 19,5; T1 -19,4; T2 -18,4; T3 -17,4; T4 -16,4; T5 -15,4; T6 -14,4; T7 -13,4; T8 -12,4; T9 -11,4; T10 -10,4; T11 -9,4; T12 -8,4; T13 -7,4; T14 -6,4; T15 -5,4; T16 -4,4; T17 -3,4; T18 -2,4; T19 -1,4; T20 0,4; T21 1,4; T22 2,4; T23 3,4; T24 4,4; T25 5,4; T26 6,4; T27 7,4; T28 8,4; T29 9,4; T30 10,4; T31 11,4; T32 12,4; T33 13,4; T34 14,4; T35 15,4; T36 16,4; T37 17,4; T38 18,4; T39 19,4; U1 -19,3; U2 -18,3; U3 -17,3; U4 -16,3; U5 -15,3; U6 -14,3; U7 -13,3; U8 -12,3; U9 -11,3; U10 -10,3; U11 -9,3; U12 -8,3; U13 -7,3; U14 -6,3; U15 -5,3; U16 -4,3; U17 -3,3; U18 -2,3; U19 -1,3; U20 0,3; U21 1,3; U22 2,3; U23 3,3; U24 4,3; U25 5,3; U26 6,3; U27 7,3; U28 8,3; U29 9,3; U30 10,3; U31 11,3; U32 12,3; U33 13,3; U34 14,3; U35 15,3; U36 16,3; U37 17,3; U38 18,3; U39 19,3; V1 -19,2; V2 -18,2; V3 -17,2; V4 -16,2; V5 -15,2; V6 -14,2; V7 -13,2; V8 -12,2; V9 -11,2; V10 -10,2; V11 -9,2; V12 -8,2; V13 -7,2; V14 -6,2; V15 -5,2; V16 -4,2; V17 -3,2; V18 -2,2; V19 -1,2; V20 0,2; V21 1,2; V22 2,2; V23 3,2; V24 4,2; V25 5,2; V26 6,2; V27 7,2; V28 8,2; V29 9,2; V30 10,2; V31 11,2; V32 12,2; V33 13,2; V34 14,2; V35 15,2; V36 16,2; V37 17,2; V38 18,2; V39 19,2; W1 -19,1; W2 -18,1; W3 -17,1; W4 -16,1; W5 -15,1; W6 -14,1; W7 -13,1; W8 -12,1; W9 -11,1; W10 -10,1; W11 -9,1; W12 -8,1; W13 -7,1; W14 -6,1; W15 -5,1; W16 -4,1; W17 -3,1; W18 -2,1; W19 -1,1; W20 0,1; W21 1,1; W22 2,1; W23 3,1; W24 4,1; W25 5,1; W26 6,1; W27 7,1; W28 8,1; W29 9,1; W30 10,1; W31 11,1; W32 12,1; W33 13,1; W34 14,1; W35 15,1; W36 16,1; W37 17,1; W38 18,1; W39 19,1; Y1 -19,0; Y2 -18,0; Y3 -17,0; Y4 -16,0; Y5 -15,0; Y6 -14,0; Y7 -13,0; Y8 -12,0; Y9 -11,0; Y10 -10,0; Y11 -9,0; Y12 -8,0; Y13 -7,0; Y14 -6,0; Y15 -5,0; Y16 -4,0; Y17 -3,0; Y18 -2,0; Y19 -1,0; Y20 0,0; Y21 1,0; Y22 2,0; Y23 3,0; Y24 4,0; Y25 5,0; Y26 6,0; Y27 7,0; Y28 8,0; Y29 9,0; Y30 10,0; Y31 11,0; Y32 12,0; Y33 13,0; Y34 14,0; Y35 15,0; Y36 16,0; Y37 17,0; Y38 18,0; Y39 19,0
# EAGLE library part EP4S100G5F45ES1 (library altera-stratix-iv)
EP4S100G5F45ES1 Auto generated by make-symbol-device-package-bsdl.ulp Rev. 29 Source: EP4S100G5F45ES1.bsd

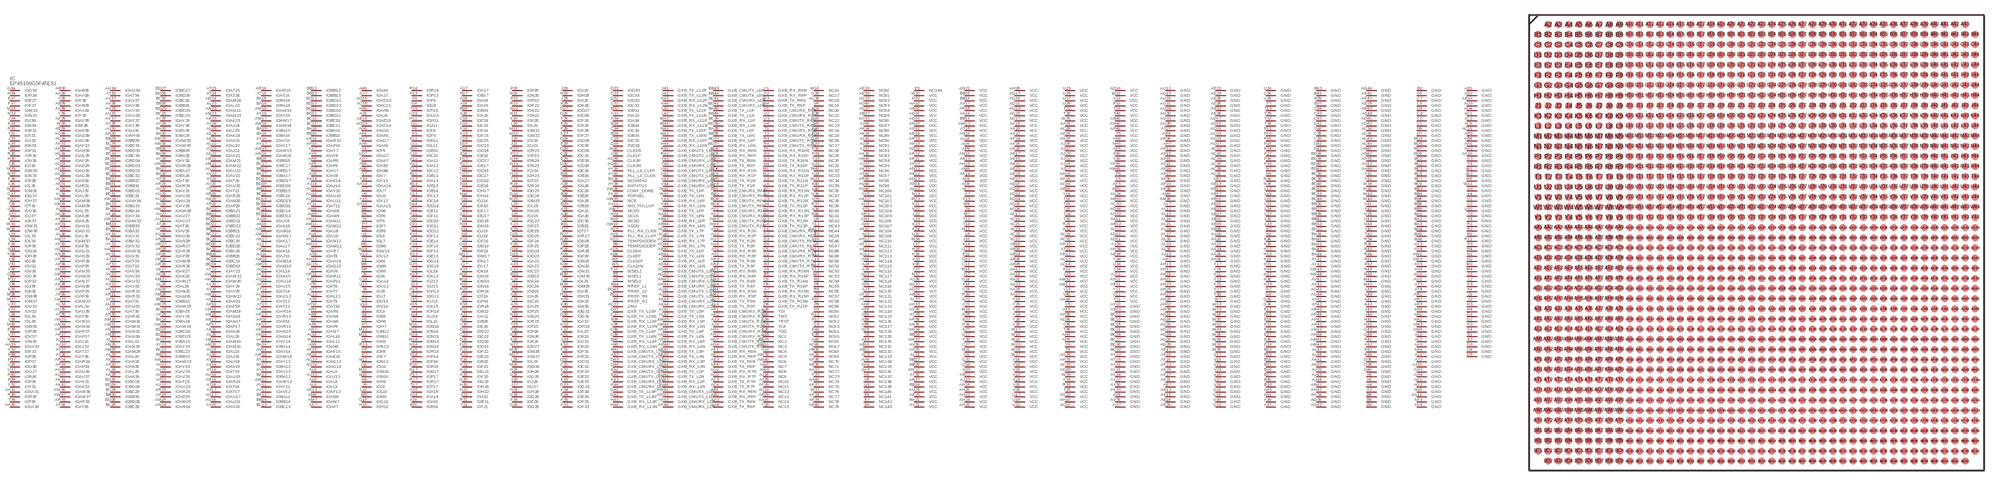
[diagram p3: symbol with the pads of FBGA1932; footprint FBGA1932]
Designator prefix IC

## EP4S100G5F45ES1 (OC_FARNELL: unknown; OC_NEWARK: unknown)  [FBGA1932]
A2  GND  pwr
A3  GXB_CMUTX_R7N  pas
A4  GND  pwr
A5  GXB_RX_R14N  pas
A6  GND  pwr
A7  GXB_RX_R15N  pas
A8  GND  pwr
A9  MSEL0  in
A10  NC4  pas
A11  IOA11
A12  IOA12
A13  IOA13
A14  IOA14
A15  IOA15
A16  IOA16
A17  IOA17
A18  IOA18
A19  IOA19
A20  IOA20
A21  IOA21
A22  IOA22
A23  IOA23
A24  IOA24
A25  IOA25
A26  IOA26
A27  IOA27
A28  IOA28
A29  IOA29
A30  IOA30
A31  IOA31
A32  IOA32
A33  VCC  pwr
A34  IOA34
A35  NC1  pas
A36  TDI  in
A37  GND  pwr
A38  GXB_RX_L15N  pas
A39  GND  pwr
A40  GXB_RX_L14N  pas
A41  GND  pwr
A42  GXB_CMUTX_L7N  pas
A43  GND  pwr
AA1  GND  pwr
AA2  GND  pwr
AA3  GXB_TX_R8N  pas
AA4  GXB_TX_R8P  pas
AA5  NC136  pas
AA6  IOAA6
AA7  IOAA7
AA8  NC134  pas
AA9  NC135  pas
AA10  GND  pwr
AA11  VCC  pwr
AA12  NC44  pas
AA13  VCC  pwr
AA14  IOAA14
AA15  IOAA15
AA16  NC14  pas
AA17  VCC  pwr
AA18  GND  pwr
AA19  VCC  pwr
AA20  GND  pwr
AA21  VCC  pwr
AA22  GND  pwr
AA23  VCC  pwr
AA24  GND  pwr
AA25  VCC  pwr
AA26  GND  pwr
AA27  VCC  pwr
AA28  GND  pwr
AA29  VCC  pwr
AA30  IOAA30
AA31  IOAA31
AA32  VCC  pwr
AA33  IOAA33
AA34  VCC  pwr
AA35  GND  pwr
AA36  NC69  pas
AA37  NC72  pas
AA38  IOAA38
AA39  IOAA39
AA40  NC74  pas
AA41  GXB_TX_L8P  pas
AA42  GXB_TX_L8N  pas
AA43  GND  pwr
AA44  GND  pwr
AB1  GXB_RX_R8N  pas
AB2  GXB_RX_R8P  pas
AB3  GND  pwr
AB4  GND  pwr
AB5  VCC  pwr
AB6  IOAB6
AB7  GND  pwr
AB8  NC126  pas
AB9  NC127  pas
AB10  NC131  pas
AB11  NC132  pas
AB12  VCC  pwr
AB13  GND  pwr
AB14  VCC  pwr
AB15  GND  pwr
AB16  VCC  pwr
AB17  GND  pwr
AB18  VCC  pwr
AB19  GND  pwr
AB20  VCC  pwr
AB21  GND  pwr
AB22  VCC  pwr
AB23  GND  pwr
AB24  VCC  pwr
AB25  GND  pwr
AB26  VCC  pwr
AB27  GND  pwr
AB28  VCC  pwr
AB29  NC13  pas
AB30  IOAB30
AB31  VCC  pwr
AB32  GND  pwr
AB33  VCC  pwr
AB34  VCC  pwr
AB35  GND  pwr
AB36  NC68  pas
AB37  NC85  pas
AB38  GND  pwr
AB39  IOAB39
AB40  VCC  pwr
AB41  GND  pwr
AB42  GND  pwr
AB43  GXB_RX_L8P  pas
AB44  GXB_RX_L8N  pas
AC1  GND  pwr
AC2  GND  pwr
AC3  GXB_TX_R7N  pas
AC4  GXB_TX_R7P  pas
AC5  NC133  pas
AC6  NC20  pas
AC7  VCC  pwr
AC8  NC128  pas
AC9  GND  pwr
AC10  VCC  pwr
AC11  GND  pwr
AC12  VCC  pwr
AC13  VCC  pwr
AC14  VCC  pwr
AC15  IOAC15
AC16  NC12  pas
AC17  VCC  pwr
AC18  GND  pwr
AC19  VCC  pwr
AC20  GND  pwr
AC21  VCC  pwr
AC22  DNU  pas
AC23  VCC  pwr
AC24  GND  pwr
AC25  VCC  pwr
AC26  GND  pwr
AC27  VCC  pwr
AC28  GND  pwr
AC29  VCC  pwr
AC30  GND  pwr
AC31  VCC  pwr
AC32  VCC  pwr
AC33  VCC  pwr
AC34  GND  pwr
AC35  VCC  pwr
AC36  GND  pwr
AC37  NC84  pas
AC38  IOAC38
AC39  NC18  pas
AC40  NC67  pas
AC41  GXB_TX_L7P  pas
AC42  GXB_TX_L7N  pas
AC43  GND  pwr
AC44  GND  pwr
AD1  GXB_RX_R7N  pas
AD2  GXB_RX_R7P  pas
AD3  GND  pwr
AD4  GND  pwr
AD5  CLK8N  in
AD6  CLK8P  in
AD7  IOAD7
AD8  VCC  pwr
AD9  VCC  pwr
AD10  VCC  pwr
AD11  VCC  pwr
AD12  VCC  pwr
AD13  VCC  pwr
AD14  IOAD14
AD15  IOAD15
AD16  VCC  pwr
AD17  GND  pwr
AD18  VCC  pwr
AD19  GND  pwr
AD20  VCC  pwr
AD21  GND  pwr
AD22  VCC  pwr
AD23  GND  pwr
AD24  VCC  pwr
AD25  GND  pwr
AD26  VCC  pwr
AD27  GND  pwr
AD28  VCC  pwr
AD29  IOAD29
AD30  IOAD30
AD31  VCC  pwr
AD32  VCC  pwr
AD33  VCC  pwr
AD34  VCC  pwr
AD35  VCC  pwr
AD36  VCC  pwr
AD37  VCC  pwr
AD38  IOAD38
AD39  CLK3P  in
AD40  CLK3N  in
AD41  GND  pwr
AD42  GND  pwr
AD43  GXB_RX_L7P  pas
AD44  GXB_RX_L7N  pas
AE1  GND  pwr
AE2  GND  pwr
AE3  GXB_TX_R6N  pas
AE4  GXB_TX_R6P  pas
AE5  NC130  pas
AE6  IOAE6
AE7  GND  pwr
AE8  NC124  pas
AE9  NC125  pas
AE10  GND  pwr
AE11  VCC  pwr
AE12  VCC  pwr
AE13  GND  pwr
AE14  IOAE14
AE15  GND  pwr
AE16  IOAE16
AE17  VCC  pwr
AE18  GND  pwr
AE19  VCC  pwr
AE20  GND  pwr
AE21  VCC  pwr
AE22  GND  pwr
AE23  VCC  pwr
AE24  GND  pwr
AE25  VCC  pwr
AE26  GND  pwr
AE27  VCC  pwr
AE28  GND  pwr
AE29  VCC  pwr
AE30  IOAE30
AE31  IOAE31
AE32  GND  pwr
AE33  NC81  pas
AE34  VCC  pwr
AE35  GND  pwr
AE36  NC71  pas
AE38  GND  pwr
AE39  IOAE39
AE40  NC79  pas
AE41  GXB_TX_L6P  pas
AE42  GXB_TX_L6N  pas
AE43  GND  pwr
AE44  GND  pwr
AF1  GXB_RX_R6N  pas
AF2  GXB_RX_R6P  pas
AF3  GND  pwr
AF4  GND  pwr
AF5  VCC  pwr
AF6  IOAF6
AF8  VCC  pwr
AF9  NC119  pas
AF10  NC121  pas
AF11  NC122  pas
AF12  NC111  pas
AF13  IOAF13
AF14  VCC  pwr
AF15  IOAF15
AF16  VCC  pwr
AF17  GND  pwr
AF18  VCC  pwr
AF19  GND  pwr
AF20  VCC  pwr
AF21  GND  pwr
AF22  VCC  pwr
AF23  GND  pwr
AF24  VCC  pwr
AF25  GND  pwr
AF26  VCC  pwr
AF27  GND  pwr
AF28  VCC  pwr
AF29  NC11  pas
AF30  IOAF30
AF31  GND  pwr
AF32  IOAF32
AF33  NC80  pas
AF34  NC77  pas
AF35  NC78  pas
AF36  NC70  pas
AF37  NC75  pas
AF38  IOAF38
AF39  IOAF39
AF40  VCC  pwr
AF41  GND  pwr
AF42  GND  pwr
AF43  GXB_RX_L6P  pas
AF44  GXB_RX_L6N  pas
AG1  GND  pwr
AG2  GND  pwr
AG3  GXB_CMUTX_R3N  pas
AG4  GXB_CMUTX_R3P  pas
AG5  NC117  pas
AG6  IOAG6
AG7  IOAG7
AG8  NC118  pas
AG9  GND  pwr
AG10  VCC  pwr
AG11  GND  pwr
AG13  IOAG13
AG14  IOAG14
AG15  IOAG15
AG16  GND  pwr
AG17  VCC  pwr
AG18  GND  pwr
AG19  VCC  pwr
AG20  GND  pwr
AG21  VCC  pwr
AG22  GND  pwr
AG23  VCC  pwr
AG24  GND  pwr
AG25  VCC  pwr
AG26  GND  pwr
AG27  VCC  pwr
AG28  GND  pwr
AG29  VCC  pwr
AG31  IOAG31
AG32  IOAG32
AG33  NC82  pas
AG34  GND  pwr
AG35  VCC  pwr
AG36  GND  pwr
AG37  VCC  pwr
AG38  IOAG38
AG39  IOAG39
AG40  NC83  pas
AG41  GXB_CMUTX_L3P  pas
AG42  GXB_CMUTX_L3N  pas
AG43  GND  pwr
AG44  GND  pwr
AH1  GXB_CMURX_R3N  pas
AH2  GXB_CMURX_R3P  pas
AH3  GND  pwr
AH4  GND  pwr
AH5  VCC  pwr
AH6  IOAH6
AH7  GND  pwr
AH8  NC123  pas
AH9  VCC  pwr
AH10  VCC  pwr
AH11  VCC  pwr
AH12  NC110  pas
AH13  GND  pwr
AH14  IOAH14
AH15  VCC  pwr
AH16  VCC  pwr
AH17  GND  pwr
AH18  VCC  pwr
AH19  GND  pwr
AH20  VCC  pwr
AH21  GND  pwr
AH22  VCC  pwr
AH23  GND  pwr
AH24  VCC  pwr
AH25  GND  pwr
AH26  VCC  pwr
AH27  GND  pwr
AH28  VCC  pwr
AH29  GND  pwr
AH30  IOAH30
AH31  IOAH31
AH32  GND  pwr
AH33  VCC  pwr
AH34  VCC  pwr
AH35  VCC  pwr
AH36  VCC  pwr
AH37  NC86  pas
AH38  GND  pwr
AH39  IOAH39
AH40  VCC  pwr
AH41  GND  pwr
AH42  GND  pwr
AH43  GXB_CMURX_L3P  pas
AH44  GXB_CMURX_L3N  pas
AJ1  GND  pwr
AJ2  GND  pwr
AJ3  GXB_CMUTX_R2N  pas
AJ4  GXB_CMUTX_R2P  pas
AJ5  NC120  pas
AJ6  IOAJ6
AJ7  IOAJ7
AJ8  NC115  pas
AJ9  NC116  pas
AJ10  GND  pwr
AJ11  VCC  pwr
AJ12  NC113  pas
AJ13  IOAJ13
AJ14  IOAJ14
AJ15  GND  pwr
AJ16  IOAJ16
AJ17  VCC  pwr
AJ18  IOAJ18
AJ19  VCC  pwr
AJ20  IOAJ20
AJ21  VCC  pwr
AJ22  IOAJ22
AJ23  VCC  pwr
AJ24  IOAJ24
AJ25  VCC  pwr
AJ26  NC9  pas
AJ27  VCC  pwr
AJ28  NC10  pas
AJ29  VCC  pwr
AJ30  IOAJ30
AJ31  IOAJ31
AJ32  IOAJ32
AJ33  NC95  pas
AJ34  VCC  pwr
AJ35  GND  pwr
AJ36  NC91  pas
AJ37  NC92  pas
AJ38  VCC  pwr
AJ39  IOAJ39
AJ40  NC87  pas
AJ41  GXB_CMUTX_L2P  pas
AJ42  GXB_CMUTX_L2N  pas
AJ43  GND  pwr
AJ44  GND  pwr
AK1  GXB_CMURX_R2N  pas
AK2  GXB_CMURX_R2P  pas
AK3  GND  pwr
AK4  GND  pwr
AK5  VCC  pwr
AK6  IOAK6
AK7  IOAK7
AK8  NC114  pas
AK9  NC107  pas
AK10  NC108  pas
AK11  NC112  pas
AK12  NC102  pas
AK13  VCC  pwr
AK14  IOAK14
AK15  IOAK15
AK16  IOAK16
AK17  IOAK17
AK18  IOAK18
AK19  VCC  pwr
AK20  IOAK20
AK21  IOAK21
AK22  IOAK22
AK23  IOAK23
AK24  IOAK24
AK25  VCC  pwr
AK26  IOAK26
AK27  IOAK27
AK28  IOAK28
AK29  IOAK29
AK30  IOAK30
AK31  IOAK31
AK32  IOAK32
AK33  NC96  pas
AK34  NC88  pas
AK35  NC89  pas
AK36  NC93  pas
AK38  IOAK38
AK39  IOAK39
AK40  VCC  pwr
AK41  GND  pwr
AK42  GND  pwr
AK43  GXB_CMURX_L2P  pas
AK44  GXB_CMURX_L2N  pas
AL1  GND  pwr
AL2  GND  pwr
AL3  GXB_TX_R5N  pas
AL4  GXB_TX_R5P  pas
AL5  NC109  pas
AL6  IOAL6
AL7  GND  pwr
AL8  IOAL8
AL9  IOAL9
AL10  IOAL10
AL11  IOAL11
AL12  GND  pwr
AL13  IOAL13
AL14  IOAL14
AL15  GND  pwr
AL16  VCC  pwr
AL17  IOAL17
AL18  GND  pwr
AL19  IOAL19
AL20  IOAL20
AL21  GND  pwr
AL22  IOAL22
AL23  IOAL23
AL24  GND  pwr
AL25  IOAL25
AL26  IOAL26
AL27  GND  pwr
AL28  IOAL28
AL29  IOAL29
AL30  GND  pwr
AL31  VCC  pwr
AL32  IOAL32
AL33  GND  pwr
AL34  IOAL34
AL35  IOAL35
AL36  IOAL36
AL37  VCC  pwr
AL38  GND  pwr
AL39  IOAL39
AL40  NC90  pas
AL41  GXB_TX_L5P  pas
AL42  GXB_TX_L5N  pas
AL43  GND  pwr
AL44  GND  pwr
AM1  GXB_RX_R5N  pas
AM2  GXB_RX_R5P  pas
AM3  GND  pwr
AM4  GND  pwr
AM5  VCC  pwr
AM6  IOAM6
AM7  IOAM7
AM8  VCC  pwr
AM9  GND  pwr
AM11  IOAM11
AM12  IOAM12
AM13  VCC  pwr
AM14  IOAM14
AM15  IOAM15
AM16  IOAM16
AM17  IOAM17
AM18  IOAM18
AM19  IOAM19
AM20  IOAM20
AM21  IOAM21
AM22  IOAM22
AM23  IOAM23
AM24  IOAM24
AM25  IOAM25
AM26  IOAM26
AM27  IOAM27
AM28  IOAM28
AM29  IOAM29
AM30  IOAM30
AM31  IOAM31
AM32  VCC  pwr
AM33  IOAM33
AM34  VCC  pwr
AM35  IOAM35
AM36  GND  pwr
AM37  IOAM37
AM38  IOAM38
AM39  IOAM39
AM40  VCC  pwr
AM41  GND  pwr
AM42  GND  pwr
AM43  GXB_RX_L5P  pas
AM44  GXB_RX_L5N  pas
AN1  GND  pwr
AN2  GND  pwr
AN3  GXB_TX_R4N  pas
AN4  GXB_TX_R4P  pas
AN5  NC106  pas
AN6  IOAN6
AN7  IOAN7
AN8  IOAN8
AN9  IOAN9
AN10  VCC  pwr
AN11  IOAN11
AN12  IOAN12
AN13  VCC  pwr
AN14  IOAN14
AN15  IOAN15
AN16  VCC  pwr
AN17  IOAN17
AN18  IOAN18
AN19  IOAN19
AN20  IOAN20
AN21  VCC  pwr
AN23  IOAN23
AN24  IOAN24
AN26  IOAN26
AN27  VCC  pwr
AN28  IOAN28
AN29  IOAN29
AN30  IOAN30
AN31  IOAN31
AN32  VCC  pwr
AN33  IOAN33
AN34  IOAN34
AN35  IOAN35
AN36  VCC  pwr
AN37  IOAN37
AN38  IOAN38
AN39  IOAN39
AN40  NC94  pas
AN41  GXB_TX_L4P  pas
AN42  GXB_TX_L4N  pas
AN43  GND  pwr
AN44  GND  pwr
AP1  GXB_RX_R4N  pas
AP2  GXB_RX_R4P  pas
AP3  GND  pwr
AP4  GND  pwr
AP5  VCC  pwr
AP6  IOAP6
AP7  GND  pwr
AP8  VCC  pwr
AP9  IOAP9
AP10  IOAP10
AP11  IOAP11
AP12  GND  pwr
AP13  VCC  pwr
AP15  GND  pwr
AP16  IOAP16
AP17  IOAP17
AP18  GND  pwr
AP19  IOAP19
AP20  IOAP20
AP21  GND  pwr
AP22  VCC  pwr
AP23  VCC  pwr
AP24  GND  pwr
AP25  IOAP25
AP27  GND  pwr
AP28  IOAP28
AP29  VCC  pwr
AP30  GND  pwr
AP32  VCC  pwr
AP33  GND  pwr
AP34  IOAP34
AP35  IOAP35
AP36  IOAP36
AP37  IOAP37
AP38  GND  pwr
AP39  IOAP39
AP40  VCC  pwr
AP41  GND  pwr
AP42  GND  pwr
AP43  GXB_RX_L4P  pas
AP44  GXB_RX_L4N  pas
AR1  GND  pwr
AR2  GND  pwr
AR3  GXB_TX_R3N  pas
AR4  GXB_TX_R3P  pas
AR5  NC105  pas
AR6  IOAR6
AR7  IOAR7
AR8  IOAR8
AR9  GND  pwr
AR10  IOAR10
AR11  IOAR11
AR12  VCC  pwr
AR13  IOAR13
AR14  IOAR14
AR15  IOAR15
AR16  IOAR16
AR18  VCC  pwr
AR19  IOAR19
AR20  IOAR20
AR21  VCC  pwr
AR22  VCC  pwr
AR23  VCC  pwr
AR24  VCC  pwr
AR25  IOAR25
AR26  IOAR26
AR27  IOAR27
AR28  IOAR28
AR29  IOAR29
AR30  IOAR30
AR31  IOAR31
AR32  IOAR32
AR33  VCC  pwr
AR34  IOAR34
AR35  IOAR35
AR36  GND  pwr
AR37  IOAR37
AR38  VCC  pwr
AR39  IOAR39
AR40  NC98  pas
AR41  GXB_TX_L3P  pas
AR42  GXB_TX_L3N  pas
AR43  GND  pwr
AR44  GND  pwr
AT1  GXB_RX_R3N  pas
AT2  GXB_RX_R3P  pas
AT3  GND  pwr
AT4  GND  pwr
AT5  NC104  pas
AT6  IOAT6
AT7  IOAT7
AT8  IOAT8
AT9  IOAT9
AT10  IOAT10
AT11  IOAT11
AT12  IOAT12
AT13  IOAT13
AT14  IOAT14
AT15  VCC  pwr
AT16  IOAT16
AT17  IOAT17
AT18  IOAT18
AT19  IOAT19
AT20  IOAT20
AT21  IOAT21
AT22  VCC  pwr
AT23  IOAT23
AT24  IOAT24
AT25  IOAT25
AT26  IOAT26
AT27  GND  pwr
AT28  VCC  pwr
AT29  IOAT29
AT30  IOAT30
AT31  IOAT31
AT32  IOAT32
AT33  IOAT33
AT34  IOAT34
AT35  VCC  pwr
AT36  IOAT36
AT37  IOAT37
AT38  IOAT38
AT39  IOAT39
AT40  NC97  pas
AT41  GND  pwr
AT42  GND  pwr
AT43  GXB_RX_L3P  pas
AT44  GXB_RX_L3N  pas
AU1  GND  pwr
AU2  GND  pwr
AU3  GXB_TX_R2N  pas
AU4  GXB_TX_R2P  pas
AU5  NC103  pas
AU6  VCC  pwr
AU7  GND  pwr
AU8  IOAU8
AU9  IOAU9
AU10  IOAU10
AU11  IOAU11
AU12  GND  pwr
AU13  IOAU13
AU14  IOAU14
AU15  GND  pwr
AU16  IOAU16
AU17  IOAU17
AU18  GND  pwr
AU19  IOAU19
AU20  IOAU20
AU21  GND  pwr
AU22  IOAU22
AU23  IOAU23
AU24  GND  pwr
AU25  VCC  pwr
AU26  IOAU26
AU27  IOAU27
AU28  IOAU28
AU29  IOAU29
AU30  GND  pwr
AU31  IOAU31
AU32  IOAU32
AU33  GND  pwr
AU34  IOAU34
AU35  IOAU35
AU36  IOAU36
AU37  IOAU37
AU38  GND  pwr
AU39  IOAU39
AU40  NC100  pas
AU41  GXB_TX_L2P  pas
AU42  GXB_TX_L2N  pas
AU43  GND  pwr
AU44  GND  pwr
AV1  GXB_RX_R2N  pas
AV2  GXB_RX_R2P  pas
AV3  GND  pwr
AV4  GND  pwr
AV5  NC101  pas
AV6  IOAV6
AV7  IOAV7
AV8  IOAV8
AV9  GND  pwr
AV10  IOAV10
AV11  NIO_PULLUP  in
AV12  IOAV12
AV13  IOAV13
AV14  IOAV14
AV15  IOAV15
AV16  IOAV16
AV17  VCC  pwr
AV18  IOAV18
AV19  IOAV19
AV20  IOAV20
AV21  VCC  pwr
AV22  IOAV22
AV23  IOAV23
AV24  IOAV24
AV25  IOAV25
AV26  IOAV26
AV27  IOAV27
AV28  IOAV28
AV29  IOAV29
AV30  VCC  pwr
AV31  IOAV31
AV32  IOAV32
AV33  IOAV33
AV34  IOAV34
AV35  IOAV35
AV36  GND  pwr
AV37  IOAV37
AV38  IOAV38
AV39  VCC  pwr
AV40  NC99  pas
AV41  GND  pwr
AV42  GND  pwr
AV43  GXB_RX_L2P  pas
AV44  GXB_RX_L2N  pas
AW1  GND  pwr
AW2  GND  pwr
AW3  GXB_CMUTX_R1N  pas
AW4  GXB_CMUTX_R1P  pas
AW5  NC8  pas
AW6  NC7  pas
AW7  NCEO  in
AW8  IOAW8
AW9  IOAW9
AW10  ASDO  in
AW11  NC3  pas
AW12  IOAW12
AW13  VCC  pwr
AW14  IOAW14
AW15  IOAW15
AW16  IOAW16
AW17  IOAW17
AW18  IOAW18
AW19  IOAW19
AW20  IOAW20
AW21  IOAW21
AW22  IOAW22
AW23  IOAW23
AW24  IOAW24
AW25  IOAW25
AW26  IOAW26
AW27  VCC  pwr
AW28  IOAW28
AW29  IOAW29
AW30  IOAW30
AW31  IOAW31
AW32  VCC  pwr
AW33  IOAW33
AW34  IOAW34
AW35  NCE  in
AW36  IOAW36
AW37  IOAW37
AW38  CONF_DONE  in
AW39  NC5  pas
AW40  NC6  pas
AW41  GXB_CMUTX_L1P  pas
AW42  GXB_CMUTX_L1N  pas
AW43  GND  pwr
AW44  GND  pwr
AY1  GXB_CMURX_R1N  pas
AY2  GXB_CMURX_R1P  pas
AY3  GND  pwr
AY4  GND  pwr
AY5  PLL_R4_CLKN  in
AY6  PLL_R4_CLKP  in
AY7  IOAY7
AY8  IOAY8
AY9  DCLK  in
AY10  GND  pwr
AY11  IOAY11
AY12  GND  pwr
AY13  IOAY13
AY14  IOAY14
AY15  GND  pwr
AY16  IOAY16
AY17  IOAY17
AY18  GND  pwr
AY19  IOAY19
AY20  IOAY20
AY21  GND  pwr
AY22  IOAY22
AY23  IOAY23
AY24  GND  pwr
AY25  IOAY25
AY26  IOAY26
AY27  GND  pwr
AY28  IOAY28
AY29  IOAY29
AY30  GND  pwr
AY31  IOAY31
AY32  IOAY32
AY33  GND  pwr
AY34  IOAY34
AY35  PORSEL  in
AY36  NSTATUS  in
AY37  IOAY37
AY38  IOAY38
AY39  PLL_L4_CLKP  in
AY40  PLL_L4_CLKN  in
AY41  GND  pwr
AY42  GND  pwr
AY43  GXB_CMURX_L1P  pas
AY44  GXB_CMURX_L1N  pas
B1  RREF_R1  pas
B2  GND  pwr
B3  GXB_CMUTX_R7P  pas
B4  GND  pwr
B5  GXB_RX_R14P  pas
B6  GND  pwr
B7  GXB_RX_R15P  pas
B8  GND  pwr
B9  TEMPDIODEP  in
B10  IOB10
B11  IOB11
B12  GND  pwr
B13  IOB13
B14  IOB14
B15  GND  pwr
B16  IOB16
B17  IOB17
B18  GND  pwr
B19  IOB19
B20  IOB20
B21  GND  pwr
B22  IOB22
B23  IOB23
B24  GND  pwr
B25  IOB25
B26  IOB26
B27  GND  pwr
B28  IOB28
B29  IOB29
B30  GND  pwr
B31  IOB31
B32  IOB32
B33  GND  pwr
B34  IOB34
B35  IOB35
B36  TMS  in
B37  GND  pwr
B38  GXB_RX_L15P  pas
B39  GND  pwr
B40  GXB_RX_L14P  pas
B41  GND  pwr
B42  GXB_CMUTX_L7P  pas
B43  GND  pwr
B44  RREF_L1  pas
BA1  GND  pwr
BA2  GND  pwr
BA3  GND  pwr
BA4  GND  pwr
BA5  GXB_TX_R1P  pas
BA6  GND  pwr
BA7  GXB_TX_R0P  pas
BA8  GND  pwr
BA9  NCSO  in
BA10  IOBA10
BA11  IOBA11
BA12  IOBA12
BA13  IOBA13
BA14  IOBA14
BA15  IOBA15
BA16  IOBA16
BA17  IOBA17
BA18  IOBA18
BA19  IOBA19
BA20  IOBA20
BA21  VCC  pwr
BA22  IOBA22
BA23  IOBA23
BA24  IOBA24
BA25  IOBA25
BA26  IOBA26
BA27  IOBA27
BA28  IOBA28
BA29  IOBA29
BA30  IOBA30
BA31  IOBA31
BA32  IOBA32
BA33  IOBA33
BA34  IOBA34
BA35  NC2  pas
BA36  NCONFIG  in
BA37  GND  pwr
BA38  GXB_TX_L0P  pas
BA39  GND  pwr
BA40  GXB_TX_L1P  pas
BA41  GND  pwr
BA42  GND  pwr
BA43  GND  pwr
BA44  GND  pwr
BB1  GXB_CMURX_R0N  pas
BB2  GXB_CMURX_R0P  pas
BB3  GND  pwr
BB4  GND  pwr
BB5  GXB_TX_R1N  pas
BB6  GND  pwr
BB7  GXB_TX_R0N  pas
BB8  GND  pwr
BB9  GND  pwr
BB10  IOBB10
BB11  VCC  pwr
BB12  IOBB12
BB13  IOBB13
BB14  IOBB14
BB15  IOBB15
BB16  VCC  pwr
BB17  IOBB17
BB18  IOBB18
BB19  VCC  pwr
BB20  IOBB20
BB21  IOBB21
BB22  IOBB22
BB23  IOBB23
BB24  VCC  pwr
BB25  IOBB25
BB26  IOBB26
BB27  VCC  pwr
BB28  IOBB28
BB29  VCC  pwr
BB30  IOBB30
BB31  IOBB31
BB32  IOBB32
BB33  IOBB33
BB34  VCC  pwr
BB35  IOBB35
BB36  GND  pwr
BB37  GND  pwr
BB38  GXB_TX_L0N  pas
BB39  GND  pwr
BB40  GXB_TX_L1N  pas
BB41  GND  pwr
BB42  GND  pwr
BB43  GXB_CMUTX_L0P  pas
BB44  GXB_CMUTX_L0N  pas
BC1  GND  pwr
BC2  GND  pwr
BC3  GND  pwr
BC4  GXB_CMUTX_R0P  pas
BC5  GND  pwr
BC6  GXB_RX_R1P  pas
BC7  GND  pwr
BC8  GXB_RX_R0P  pas
BC9  GND  pwr
BC10  IOBC10
BC11  IOBC11
BC12  GND  pwr
BC13  IOBC13
BC14  IOBC14
BC15  GND  pwr
BC16  IOBC16
BC17  IOBC17
BC18  GND  pwr
BC19  IOBC19
BC20  IOBC20
BC21  GND  pwr
BC22  IOBC22
BC23  IOBC23
BC24  GND  pwr
BC25  IOBC25
BC26  IOBC26
BC27  GND  pwr
BC28  IOBC28
BC29  IOBC29
BC30  GND  pwr
BC31  IOBC31
BC32  IOBC32
BC33  GND  pwr
BC34  IOBC34
BC35  IOBC35
BC36  GND  pwr
BC37  GXB_RX_L0P  pas
BC38  GND  pwr
BC39  GXB_RX_L1P  pas
BC40  GND  pwr
BC41  GXB_CMURX_L0P  pas
BC42  GND  pwr
BC43  GND  pwr
BC44  GND  pwr
BD2  RREF_R0  pas
BD3  GND  pwr
BD4  GXB_CMUTX_R0N  pas
BD5  GND  pwr
BD6  GXB_RX_R1N  pas
BD7  GND  pwr
BD8  GXB_RX_R0N  pas
BD9  GND  pwr
BD10  IOBD10
BD11  IOBD11
BD12  IOBD12
BD13  IOBD13
BD14  IOBD14
BD15  IOBD15
BD16  IOBD16
BD17  IOBD17
BD18  IOBD18
BD19  IOBD19
BD20  IOBD20
BD21  IOBD21
BD22  IOBD22
BD23  IOBD23
BD24  IOBD24
BD25  IOBD25
BD26  IOBD26
BD27  IOBD27
BD28  IOBD28
BD29  IOBD29
BD30  IOBD30
BD31  IOBD31
BD32  IOBD32
BD33  IOBD33
BD34  IOBD34
BD35  IOBD35
BD36  GND  pwr
BD37  GXB_RX_L0N  pas
BD38  GND  pwr
BD39  GXB_RX_L1N  pas
BD40  GND  pwr
BD41  GXB_CMURX_L0N  pas
BD42  GND  pwr
BD43  RREF_L0  pas
C1  GND  pwr
C2  GND  pwr
C3  GND  pwr
C4  GND  pwr
C5  GND  pwr
C6  GXB_TX_R14N  pas
C7  GND  pwr
C8  GXB_TX_R15N  pas
C9  GND  pwr
C10  IOC10
C11  VCC  pwr
C12  IOC12
C13  IOC13
C14  IOC14
C15  IOC15
C16  VCC  pwr
C17  IOC17
C18  IOC18
C19  IOC19
C20  IOC20
C21  VCC  pwr
C22  IOC22
C23  IOC23
C24  IOC24
C25  IOC25
C26  IOC26
C27  VCC  pwr
C28  IOC28
C29  IOC29
C30  IOC30
C31  IOC31
C32  IOC32
C33  IOC33
C34  IOC34
C35  IOC35
C36  GND  pwr
C37  GXB_TX_L15N  pas
C38  GND  pwr
C39  GXB_TX_L14N  pas
C40  GND  pwr
C41  GND  pwr
C42  GND  pwr
C43  GND  pwr
C44  GND  pwr
D1  GXB_CMURX_R7N  pas
D2  GXB_CMURX_R7P  pas
D3  GND  pwr
D4  GND  pwr
D5  GND  pwr
D6  GXB_TX_R14P  pas
D7  GND  pwr
D8  GXB_TX_R15P  pas
D9  GND  pwr
D10  IOD10
D11  IOD11
D12  IOD12
D13  VCC  pwr
D14  IOD14
D15  IOD15
D16  IOD16
D17  IOD17
D18  IOD18
D19  IOD19
D20  IOD20
D21  IOD21
D22  IOD22
D23  IOD23
D24  IOD24
D25  IOD25
D26  IOD26
D27  IOD27
D28  IOD28
D29  IOD29
D30  IOD30
D31  IOD31
D32  IOD32
D33  IOD33
D34  VCC  pwr
D35  IOD35
D36  GND  pwr
D37  GXB_TX_L15P  pas
D38  GND  pwr
D39  GXB_TX_L14P  pas
D40  GND  pwr
D41  GND  pwr
D42  GND  pwr
D43  GXB_CMURX_L7P  pas
D44  GXB_CMURX_L7N  pas
E1  GND  pwr
E2  GND  pwr
E3  GXB_CMUTX_R6N  pas
E4  GXB_CMUTX_R6P  pas
E5  NC144  pas
E6  NC143  pas
E7  NC142  pas
E8  NC141  pas
E9  MSEL1  in
E10  VCC  pwr
E11  IOE11
E12  GND  pwr
E13  IOE13
E14  IOE14
E15  GND  pwr
E16  IOE16
E17  IOE17
E18  GND  pwr
E19  IOE19
E20  IOE20
E21  GND  pwr
E22  IOE22
E23  VCC  pwr
E24  GND  pwr
E25  IOE25
E26  IOE26
E27  GND  pwr
E28  IOE28
E29  IOE29
E30  GND  pwr
E31  IOE31
E32  IOE32
E33  GND  pwr
E34  IOE34
E35  IOE35
E36  TDO  out
E37  IOE37
E38  NC21  pas
E39  NC65  pas
E40  NC64  pas
E41  GXB_CMUTX_L6P  pas
E42  GXB_CMUTX_L6N  pas
E43  GND  pwr
E44  GND  pwr
F1  GXB_CMURX_R6N  pas
F2  GXB_CMURX_R6P  pas
F3  GND  pwr
F4  GND  pwr
F5  IOF5
F6  IOF6
F7  IOF7
F8  IOF8
F9  IOF9
F10  MSEL2  in
F11  IOF11
F12  IOF12
F13  IOF13
F14  IOF14
F15  IOF15
F16  IOF16
F17  IOF17
F18  VCC  pwr
F19  IOF19
F20  IOF20
F21  IOF21
F22  IOF22
F23  IOF23
F24  IOF24
F25  IOF25
F26  IOF26
F27  IOF27
F28  IOF28
F29  IOF29
F30  VCC  pwr
F31  IOF31
F32  IOF32
F33  IOF33
F34  IOF34
F35  IOF35
F36  TRST  in
F37  IOF37
F38  IOF38
F39  IOF39
F40  NC24  pas
F41  GND  pwr
F42  GND  pwr
F43  GXB_CMURX_L6P  pas
F44  GXB_CMURX_L6N  pas
G1  GND  pwr
G2  GND  pwr
G3  GXB_TX_R13N  pas
G4  GXB_TX_R13P  pas
G5  NC63  pas
G6  IOG6
G7  GND  pwr
G8  IOG8
G9  GND  pwr
G10  IOG10
G11  TEMPDIODEN  in
G12  IOG12
G13  VCC  pwr
G14  IOG14
G15  IOG15
G16  VCC  pwr
G17  IOG17
G18  IOG18
G19  IOG19
G20  IOG20
G21  IOG21
G22  VCC  pwr
G23  IOG23
G24  IOG24
G25  IOG25
G26  IOG26
G27  VCC  pwr
G28  IOG28
G29  IOG29
G30  IOG30
G31  IOG31
G32  VCC  pwr
G33  IOG33
G34  IOG34
G35  TCK  in
G36  GND  pwr
G37  IOG37
G38  GND  pwr
G39  IOG39
G40  NC26  pas
G41  GXB_TX_L13P  pas
G42  GXB_TX_L13N  pas
G43  GND  pwr
G44  GND  pwr
H1  GXB_RX_R13N  pas
H2  GXB_RX_R13P  pas
H3  GND  pwr
H4  GND  pwr
H5  NC60  pas
H6  IOH6
H7  IOH7
H8  IOH8
H9  IOH9
H10  IOH10
H11  IOH11
H12  GND  pwr
H13  IOH13
H14  IOH14
H15  GND  pwr
H16  IOH16
H17  IOH17
H18  GND  pwr
H19  IOH19
H20  IOH20
H21  GND  pwr
H22  IOH22
H23  IOH23
H24  GND  pwr
H25  VCC  pwr
H26  IOH26
H27  GND  pwr
H28  IOH28
H29  IOH29
H30  GND  pwr
H31  IOH31
H32  IOH32
H33  GND  pwr
H34  IOH34
H35  VCC  pwr
H36  IOH36
H37  IOH37
H38  IOH38
H39  VCC  pwr
H40  NC22  pas
H41  GND  pwr
H42  GND  pwr
H43  GXB_RX_L13P  pas
H44  GXB_RX_L13N  pas
J1  GND  pwr
J2  GND  pwr
J3  GXB_TX_R12N  pas
J4  GXB_TX_R12P  pas
J5  NC57  pas
J6  IOJ6
J7  IOJ7
J8  IOJ8
J9  IOJ9
J10  VCC  pwr
J11  IOJ11
J12  IOJ12
J13  IOJ13
J14  IOJ14
J15  IOJ15
J16  IOJ16
J17  VCC  pwr
J18  IOJ18
J19  IOJ19
J20  IOJ20
J21  IOJ21
J22  IOJ22
J23  VCC  pwr
J24  IOJ24
J25  IOJ25
J26  IOJ26
J27  IOJ27
J28  IOJ28
J29  IOJ29
J30  IOJ30
J31  VCC  pwr
J32  IOJ32
J33  IOJ33
J34  IOJ34
J35  IOJ35
J36  IOJ36
J37  IOJ37
J38  IOJ38
J39  IOJ39
J40  NC23  pas
J41  GXB_TX_L12P  pas
J42  GXB_TX_L12N  pas
J43  GND  pwr
J44  GND  pwr
K1  GXB_RX_R12N  pas
K2  GXB_RX_R12P  pas
K3  GND  pwr
K4  GND  pwr
K5  NC140  pas
K6  IOK6
K7  GND  pwr
K8  IOK8
K9  GND  pwr
K11  IOK11
K12  VCC  pwr
K13  IOK13
K14  VCC  pwr
K15  IOK15
K16  IOK16
K17  IOK17
K18  IOK18
K19  IOK19
K20  IOK20
K21  VCC  pwr
K22  VCC  pwr
K23  VCC  pwr
K24  VCC  pwr
K25  IOK25
K26  IOK26
K27  VCC  pwr
K28  IOK28
K29  IOK29
K30  IOK30
K31  IOK31
K32  IOK32
K33  VCC  pwr
K34  IOK34
K35  IOK35
K36  GND  pwr
K37  IOK37
K38  GND  pwr
K39  IOK39
K40  NC35  pas
K41  GND  pwr
K42  GND  pwr
K43  GXB_RX_L12P  pas
K44  GXB_RX_L12N  pas
L1  GND  pwr
L2  GND  pwr
L3  GXB_TX_R11N  pas
L4  GXB_TX_R11P  pas
L5  NC50  pas
L6  IOL6
L7  IOL7
L8  VCC  pwr
L9  IOL9
L10  IOL10
L11  IOL11
L12  GND  pwr
L13  VCC  pwr
L14  IOL14
L15  GND  pwr
L16  IOL16
L17  IOL17
L18  GND  pwr
L20  IOL20
L21  GND  pwr
L22  VCC  pwr
L23  VCC  pwr
L24  GND  pwr
L25  IOL25
L26  IOL26
L27  GND  pwr
L29  IOL29
L30  GND  pwr
L32  IOL32
L33  GND  pwr
L34  IOL34
L35  IOL35
L36  IOL36
L37  VCC  pwr
L38  IOL38
L39  IOL39
L40  NC36  pas
L41  GXB_TX_L11P  pas
L42  GXB_TX_L11N  pas
L43  GND  pwr
L44  GND  pwr
M1  GXB_RX_R11N  pas
M2  GXB_RX_R11P  pas
M3  GND  pwr
M4  GND  pwr
M5  NC53  pas
M6  IOM6
M7  VCC  pwr
M8  IOM8
M9  IOM9
M10  IOM10
M11  IOM11
M12  IOM12
M13  VCC  pwr
M14  IOM14
M16  IOM16
M17  IOM17
M18  VCC  pwr
M19  IOM19
M21  IOM21
M22  IOM22
M24  VCC  pwr
M25  IOM25
M26  IOM26
M27  IOM27
M28  IOM28
M29  IOM29
M30  IOM30
M31  VCC  pwr
M32  VCC  pwr
M33  IOM33
M34  VCC  pwr
M35  IOM35
M36  IOM36
M37  IOM37
M38  IOM38
M39  IOM39
M40  NC32  pas
M41  GND  pwr
M42  GND  pwr
M43  GXB_RX_L11P  pas
M44  GXB_RX_L11N  pas
N1  GND  pwr
N2  GND  pwr
N3  GXB_TX_R10N  pas
N4  GXB_TX_R10P  pas
N5  NC54  pas
N6  ION6
N7  GND  pwr
N8  ION8
N9  GND  pwr
N10  ION10
N11  VCC  pwr
N12  ION12
N13  VCC  pwr
N14  ION14
N15  ION15
N16  ION16
N17  ION17
N18  ION18
N19  ION19
N20  ION20
N21  ION21
N22  ION22
N23  ION23
N24  ION24
N25  ION25
N26  ION26
N27  ION27
N28  ION28
N29  ION29
N30  ION30
N31  ION31
N32  VCC  pwr
N33  ION33
N34  ION34
N35  ION35
N36  GND  pwr
N37  VCC  pwr
N38  GND  pwr
N39  ION39
N40  NC41  pas
N41  GXB_TX_L10P  pas
N42  GXB_TX_L10N  pas
N43  GND  pwr
N44  GND  pwr
P1  GXB_RX_R10N  pas
P2  GXB_RX_R10P  pas
P3  GND  pwr
P4  GND  pwr
P5  VCC  pwr
P6  IOP6
P7  IOP7
P8  NC55  pas
P9  NC59  pas
P10  NC58  pas
P11  NC62  pas
P12  GND  pwr
P13  IOP13
P14  IOP14
P15  GND  pwr
P16  IOP16
P17  IOP17
P18  GND  pwr
P19  IOP19
P20  IOP20
P21  GND  pwr
P22  IOP22
P23  IOP23
P24  GND  pwr
P25  IOP25
P26  IOP26
P27  GND  pwr
P28  IOP28
P29  IOP29
P30  GND  pwr
P31  IOP31
P32  IOP32
P33  GND  pwr
P34  NC25  pas
P35  NC29  pas
P36  NC28  pas
P37  IOP37
P38  IOP38
P39  IOP39
P40  VCC  pwr
P41  GND  pwr
P42  GND  pwr
P43  GXB_RX_L10P  pas
P44  GXB_RX_L10N  pas
R1  GND  pwr
R2  GND  pwr
R3  GXB_CMUTX_R5N  pas
R4  GXB_CMUTX_R5P  pas
R5  NC45  pas
R6  IOR6
R8  NC56  pas
R9  GND  pwr
R10  VCC  pwr
R11  GND  pwr
R12  NC61  pas
R13  IOR13
R14  IOR14
R15  IOR15
R16  IOR16
R17  IOR17
R18  IOR18
R19  IOR19
R20  VCC  pwr
R21  IOR21
R22  IOR22
R23  IOR23
R24  IOR24
R25  IOR25
R26  VCC  pwr
R27  IOR27
R28  IOR28
R29  VCC  pwr
R30  IOR30
R31  IOR31
R33  NC27  pas
R34  GND  pwr
R35  VCC  pwr
R36  GND  pwr
R37  NC39  pas
R38  IOR38
R39  IOR39
R40  IOR40
R41  GXB_CMUTX_L5P  pas
R42  GXB_CMUTX_L5N  pas
R43  GND  pwr
R44  GND  pwr
T1  GXB_CMURX_R5N  pas
T2  GXB_CMURX_R5P  pas
T3  GND  pwr
T4  GND  pwr
T5  VCC  pwr
T6  IOT6
T7  GND  pwr
T8  VCC  pwr
T9  VCC  pwr
T10  VCC  pwr
T11  VCC  pwr
T12  VCC  pwr
T13  GND  pwr
T14  VCC  pwr
T15  IOT15
T16  VCC  pwr
T17  IOT17
T18  VCC  pwr
T19  IOT19
T20  VCC  pwr
T21  IOT21
T22  VCC  pwr
T23  IOT23
T24  VCC  pwr
T25  IOT25
T26  VCC  pwr
T27  IOT27
T28  VCC  pwr
T29  GND  pwr
T30  IOT30
T31  IOT31
T32  GND  pwr
T33  NC30  pas
T34  VCC  pwr
T35  VCC  pwr
T36  VCC  pwr
T37  VCC  pwr
T38  GND  pwr
T39  IOT39
T40  VCC  pwr
T41  GND  pwr
T42  GND  pwr
T43  GXB_CMURX_L5P  pas
T44  GXB_CMURX_L5N  pas
U1  GND  pwr
U2  GND  pwr
U3  GXB_CMUTX_R4N  pas
U4  GXB_CMUTX_R4P  pas
U5  NC139  pas
U6  IOU6
U7  IOU7
U8  NC42  pas
U9  NC137  pas
U10  GND  pwr
U11  VCC  pwr
U12  NC51  pas
U13  IOU13
U14  IOU14
U15  IOU15
U16  GND  pwr
U17  VCC  pwr
U18  GND  pwr
U19  VCC  pwr
U20  GND  pwr
U21  VCC  pwr
U22  GND  pwr
U23  VCC  pwr
U24  GND  pwr
U25  VCC  pwr
U26  GND  pwr
U27  VCC  pwr
U28  GND  pwr
U29  VCC  pwr
U30  IOU30
U31  VCC  pwr
U32  IOU32
U33  NC31  pas
U34  VCC  pwr
U35  GND  pwr
U36  NC37  pas
U37  IOU37
U38  IOU38
U39  NC17  pas
U40  NC66  pas
U41  GXB_CMUTX_L4P  pas
U42  GXB_CMUTX_L4N  pas
U43  GND  pwr
U44  GND  pwr
V1  GXB_CMURX_R4N  pas
V2  GXB_CMURX_R4P  pas
V3  GND  pwr
V4  GND  pwr
V5  VCC  pwr
V6  NC19  pas
V7  IOV7
V8  NC138  pas
V9  NC47  pas
V10  NC46  pas
V11  NC49  pas
V12  NC52  pas
V13  IOV13
V14  IOV14
V15  IOV15
V16  VCC  pwr
V17  GND  pwr
V18  VCC  pwr
V19  GND  pwr
V20  VCC  pwr
V21  GND  pwr
V22  VCC  pwr
V23  GND  pwr
V24  VCC  pwr
V25  GND  pwr
V26  VCC  pwr
V27  GND  pwr
V28  VCC  pwr
V29  GND  pwr
V30  IOV30
V31  IOV31
V32  IOV32
V33  VCC  pwr
V34  NC33  pas
V35  NC38  pas
V36  NC40  pas
V37  IOV37
V38  VCC  pwr
V39  CLK1P  in
V40  VCC  pwr
V41  GND  pwr
V42  GND  pwr
V43  GXB_CMURX_L4P  pas
V44  GXB_CMURX_L4N  pas
W1  GND  pwr
W2  GND  pwr
W3  GXB_TX_R9N  pas
W4  GXB_TX_R9P  pas
W5  CLK10N  in
W6  CLK10P  in
W7  GND  pwr
W8  VCC  pwr
W9  GND  pwr
W10  VCC  pwr
W11  GND  pwr
W12  NC48  pas
W13  GND  pwr
W14  IOW14
W15  GND  pwr
W16  NC16  pas
W17  VCC  pwr
W18  GND  pwr
W19  VCC  pwr
W20  GND  pwr
W21  VCC  pwr
W22  GND  pwr
W23  VCC  pwr
W24  GND  pwr
W25  VCC  pwr
W26  GND  pwr
W27  VCC  pwr
W28  GND  pwr
W29  VCC  pwr
W30  IOW30
W31  IOW31
W32  GND  pwr
W33  NC34  pas
W34  GND  pwr
W35  VCC  pwr
W36  GND  pwr
W37  NC76  pas
W38  IOW38
W39  GND  pwr
W40  CLK1N  in
W41  GXB_TX_L9P  pas
W42  GXB_TX_L9N  pas
W43  GND  pwr
W44  GND  pwr
Y1  GXB_RX_R9N  pas
Y2  GXB_RX_R9P  pas
Y3  GND  pwr
Y4  GND  pwr
Y5  VCC  pwr
Y6  IOY6
Y7  VCC  pwr
Y8  NC129  pas
Y9  VCC  pwr
Y10  VCC  pwr
Y11  VCC  pwr
Y12  NC43  pas
Y13  VCC  pwr
Y14  IOY14
Y15  IOY15
Y16  VCC  pwr
Y17  GND  pwr
Y18  VCC  pwr
Y19  GND  pwr
Y20  VCC  pwr
Y21  GND  pwr
Y22  VCC  pwr
Y23  GND  pwr
Y24  VCC  pwr
Y25  GND  pwr
Y26  VCC  pwr
Y27  GND  pwr
Y28  VCC  pwr
Y29  NC15  pas
Y30  GND  pwr
Y31  IOY31
Y32  IOY32
Y34  VCC  pwr
Y35  VCC  pwr
Y36  VCC  pwr
Y37  NC73  pas
Y38  IOY38
Y39  IOY39
Y40  VCC  pwr
Y41  GND  pwr
Y42  GND  pwr
Y43  GXB_RX_L9P  pas
Y44  GXB_RX_L9N  pas

## Footprint FBGA1932 (pad centres in mm)
1932-Pin FineLine Ball-Grid Array (FBGA) - Flip Chip Auto generated by make-symbol-device-package-bsdl.ulp Rev. 29 Source: EP4S100G5F45ES1.bsd http://www.altera.com .. dspkg.pdf
smd 0.7 x 0.7: A2 -20.5,21.5; A3 -19.5,21.5; A4 -18.5,21.5; A5 -17.5,21.5; A6 -16.5,21.5; A7 -15.5,21.5; A8 -14.5,21.5; A9 -13.5,21.5; A10 -12.5,21.5; A11 -11.5,21.5; A12 -10.5,21.5; A13 -9.5,21.5; A14 -8.5,21.5; A15 -7.5,21.5; A16 -6.5,21.5; A17 -5.5,21.5; A18 -4.5,21.5; A19 -3.5,21.5; A20 -2.5,21.5; A21 -1.5,21.5; A22 -0.5,21.5; A23 0.5,21.5; A24 1.5,21.5; A25 2.5,21.5; A26 3.5,21.5; A27 4.5,21.5; A28 5.5,21.5; A29 6.5,21.5; A30 7.5,21.5; A31 8.5,21.5; A32 9.5,21.5; A33 10.5,21.5; A34 11.5,21.5; A35 12.5,21.5; A36 13.5,21.5; A37 14.5,21.5; A38 15.5,21.5; A39 16.5,21.5; A40 17.5,21.5; A41 18.5,21.5; A42 19.5,21.5; A43 20.5,21.5; AA1 -21.5,1.5; AA2 -20.5,1.5; AA3 -19.5,1.5; AA4 -18.5,1.5; AA5 -17.5,1.5; AA6 -16.5,1.5; AA7 -15.5,1.5; AA8 -14.5,1.5; AA9 -13.5,1.5; AA10 -12.5,1.5; AA11 -11.5,1.5; AA12 -10.5,1.5; AA13 -9.5,1.5; AA14 -8.5,1.5; AA15 -7.5,1.5; AA16 -6.5,1.5; AA17 -5.5,1.5; AA18 -4.5,1.5; AA19 -3.5,1.5; AA20 -2.5,1.5; AA21 -1.5,1.5; AA22 -0.5,1.5; AA23 0.5,1.5; AA24 1.5,1.5; AA25 2.5,1.5; AA26 3.5,1.5; AA27 4.5,1.5; AA28 5.5,1.5; AA29 6.5,1.5; AA30 7.5,1.5; AA31 8.5,1.5; AA32 9.5,1.5; AA33 10.5,1.5; AA34 11.5,1.5; AA35 12.5,1.5; AA36 13.5,1.5; AA37 14.5,1.5; AA38 15.5,1.5; AA39 16.5,1.5; AA40 17.5,1.5; AA41 18.5,1.5; AA42 19.5,1.5; AA43 20.5,1.5; AA44 21.5,1.5; AB1 -21.5,0.5; AB2 -20.5,0.5; AB3 -19.5,0.5; AB4 -18.5,0.5; AB5 -17.5,0.5; AB6 -16.5,0.5; AB7 -15.5,0.5; AB8 -14.5,0.5; AB9 -13.5,0.5; AB10 -12.5,0.5; AB11 -11.5,0.5; AB12 -10.5,0.5; AB13 -9.5,0.5; AB14 -8.5,0.5; AB15 -7.5,0.5; AB16 -6.5,0.5; AB17 -5.5,0.5; AB18 -4.5,0.5; AB19 -3.5,0.5; AB20 -2.5,0.5; AB21 -1.5,0.5; AB22 -0.5,0.5; AB23 0.5,0.5; AB24 1.5,0.5; AB25 2.5,0.5; AB26 3.5,0.5; AB27 4.5,0.5; AB28 5.5,0.5; AB29 6.5,0.5; AB30 7.5,0.5; AB31 8.5,0.5; AB32 9.5,0.5; AB33 10.5,0.5; AB34 11.5,0.5; AB35 12.5,0.5; AB36 13.5,0.5; AB37 14.5,0.5; AB38 15.5,0.5; AB39 16.5,0.5; AB40 17.5,0.5; AB41 18.5,0.5; AB42 19.5,0.5; AB43 20.5,0.5; AB44 21.5,0.5; AC1 -21.5,-0.5; AC2 -20.5,-0.5; AC3 -19.5,-0.5; AC4 -18.5,-0.5; AC5 -17.5,-0.5; AC6 -16.5,-0.5; AC7 -15.5,-0.5; AC8 -14.5,-0.5; AC9 -13.5,-0.5; AC10 -12.5,-0.5; AC11 -11.5,-0.5; AC12 -10.5,-0.5; AC13 -9.5,-0.5; AC14 -8.5,-0.5; AC15 -7.5,-0.5; AC16 -6.5,-0.5; AC17 -5.5,-0.5; AC18 -4.5,-0.5; AC19 -3.5,-0.5; AC20 -2.5,-0.5; AC21 -1.5,-0.5; AC22 -0.5,-0.5; AC23 0.5,-0.5; AC24 1.5,-0.5; AC25 2.5,-0.5; AC26 3.5,-0.5; AC27 4.5,-0.5; AC28 5.5,-0.5; AC29 6.5,-0.5; AC30 7.5,-0.5; AC31 8.5,-0.5; AC32 9.5,-0.5; AC33 10.5,-0.5; AC34 11.5,-0.5; AC35 12.5,-0.5; AC36 13.5,-0.5; AC37 14.5,-0.5; AC38 15.5,-0.5; AC39 16.5,-0.5; AC40 17.5,-0.5; AC41 18.5,-0.5; AC42 19.5,-0.5; AC43 20.5,-0.5; AC44 21.5,-0.5; AD1 -21.5,-1.5; AD2 -20.5,-1.5; AD3 -19.5,-1.5; AD4 -18.5,-1.5; AD5 -17.5,-1.5; AD6 -16.5,-1.5; AD7 -15.5,-1.5; AD8 -14.5,-1.5; AD9 -13.5,-1.5; AD10 -12.5,-1.5; AD11 -11.5,-1.5; AD12 -10.5,-1.5; AD13 -9.5,-1.5; AD14 -8.5,-1.5; AD15 -7.5,-1.5; AD16 -6.5,-1.5; AD17 -5.5,-1.5; AD18 -4.5,-1.5; AD19 -3.5,-1.5; AD20 -2.5,-1.5; AD21 -1.5,-1.5; AD22 -0.5,-1.5; AD23 0.5,-1.5; AD24 1.5,-1.5; AD25 2.5,-1.5; AD26 3.5,-1.5; AD27 4.5,-1.5; AD28 5.5,-1.5; AD29 6.5,-1.5; AD30 7.5,-1.5; AD31 8.5,-1.5; AD32 9.5,-1.5; AD33 10.5,-1.5; AD34 11.5,-1.5; AD35 12.5,-1.5; AD36 13.5,-1.5; AD37 14.5,-1.5; AD38 15.5,-1.5; AD39 16.5,-1.5; AD40 17.5,-1.5; AD41 18.5,-1.5; AD42 19.5,-1.5; AD43 20.5,-1.5; AD44 21.5,-1.5; AE1 -21.5,-2.5; AE2 -20.5,-2.5; AE3 -19.5,-2.5; AE4 -18.5,-2.5; AE5 -17.5,-2.5; AE6 -16.5,-2.5; AE7 -15.5,-2.5; AE8 -14.5,-2.5; AE9 -13.5,-2.5; AE10 -12.5,-2.5; AE11 -11.5,-2.5; AE12 -10.5,-2.5; AE13 -9.5,-2.5; AE14 -8.5,-2.5; AE15 -7.5,-2.5; AE16 -6.5,-2.5; AE17 -5.5,-2.5; AE18 -4.5,-2.5; AE19 -3.5,-2.5; AE20 -2.5,-2.5; AE21 -1.5,-2.5; AE22 -0.5,-2.5; AE23 0.5,-2.5; AE24 1.5,-2.5; AE25 2.5,-2.5; AE26 3.5,-2.5; AE27 4.5,-2.5; AE28 5.5,-2.5; AE29 6.5,-2.5; AE30 7.5,-2.5; AE31 8.5,-2.5; AE32 9.5,-2.5; AE33 10.5,-2.5; AE34 11.5,-2.5; AE35 12.5,-2.5; AE36 13.5,-2.5; AE37 14.5,-2.5; AE38 15.5,-2.5; AE39 16.5,-2.5; AE40 17.5,-2.5; AE41 18.5,-2.5; AE42 19.5,-2.5; AE43 20.5,-2.5; AE44 21.5,-2.5; AF1 -21.5,-3.5; AF2 -20.5,-3.5; AF3 -19.5,-3.5; AF4 -18.5,-3.5; AF5 -17.5,-3.5; AF6 -16.5,-3.5; AF7 -15.5,-3.5; AF8 -14.5,-3.5; AF9 -13.5,-3.5; AF10 -12.5,-3.5; AF11 -11.5,-3.5; AF12 -10.5,-3.5; AF13 -9.5,-3.5; AF14 -8.5,-3.5; AF15 -7.5,-3.5; AF16 -6.5,-3.5; AF17 -5.5,-3.5; AF18 -4.5,-3.5; AF19 -3.5,-3.5; AF20 -2.5,-3.5; AF21 -1.5,-3.5; AF22 -0.5,-3.5; AF23 0.5,-3.5; AF24 1.5,-3.5; AF25 2.5,-3.5; AF26 3.5,-3.5; AF27 4.5,-3.5; AF28 5.5,-3.5; AF29 6.5,-3.5; AF30 7.5,-3.5; AF31 8.5,-3.5; AF32 9.5,-3.5; AF33 10.5,-3.5; AF34 11.5,-3.5; AF35 12.5,-3.5; AF36 13.5,-3.5; AF37 14.5,-3.5; AF38 15.5,-3.5; AF39 16.5,-3.5; AF40 17.5,-3.5; AF41 18.5,-3.5; AF42 19.5,-3.5; AF43 20.5,-3.5; AF44 21.5,-3.5; AG1 -21.5,-4.5; AG2 -20.5,-4.5; AG3 -19.5,-4.5; AG4 -18.5,-4.5; AG5 -17.5,-4.5; AG6 -16.5,-4.5; AG7 -15.5,-4.5; AG8 -14.5,-4.5; AG9 -13.5,-4.5; AG10 -12.5,-4.5; AG11 -11.5,-4.5; AG12 -10.5,-4.5; AG13 -9.5,-4.5; AG14 -8.5,-4.5; AG15 -7.5,-4.5; AG16 -6.5,-4.5; AG17 -5.5,-4.5; AG18 -4.5,-4.5; AG19 -3.5,-4.5; AG20 -2.5,-4.5; AG21 -1.5,-4.5; AG22 -0.5,-4.5; AG23 0.5,-4.5; AG24 1.5,-4.5; AG25 2.5,-4.5; AG26 3.5,-4.5; AG27 4.5,-4.5; AG28 5.5,-4.5; AG29 6.5,-4.5; AG30 7.5,-4.5; AG31 8.5,-4.5; AG32 9.5,-4.5; AG33 10.5,-4.5; AG34 11.5,-4.5; AG35 12.5,-4.5; AG36 13.5,-4.5; AG37 14.5,-4.5; AG38 15.5,-4.5; AG39 16.5,-4.5; AG40 17.5,-4.5; AG41 18.5,-4.5; AG42 19.5,-4.5; AG43 20.5,-4.5; AG44 21.5,-4.5; AH1 -21.5,-5.5; AH2 -20.5,-5.5; AH3 -19.5,-5.5; AH4 -18.5,-5.5; AH5 -17.5,-5.5; AH6 -16.5,-5.5; AH7 -15.5,-5.5; AH8 -14.5,-5.5; AH9 -13.5,-5.5; AH10 -12.5,-5.5; AH11 -11.5,-5.5; AH12 -10.5,-5.5; AH13 -9.5,-5.5; AH14 -8.5,-5.5; AH15 -7.5,-5.5; AH16 -6.5,-5.5; AH17 -5.5,-5.5; AH18 -4.5,-5.5; AH19 -3.5,-5.5; AH20 -2.5,-5.5; AH21 -1.5,-5.5; AH22 -0.5,-5.5; AH23 0.5,-5.5; AH24 1.5,-5.5; AH25 2.5,-5.5; AH26 3.5,-5.5; AH27 4.5,-5.5; AH28 5.5,-5.5; AH29 6.5,-5.5; AH30 7.5,-5.5; AH31 8.5,-5.5; AH32 9.5,-5.5; AH33 10.5,-5.5; AH34 11.5,-5.5; AH35 12.5,-5.5; AH36 13.5,-5.5; AH37 14.5,-5.5; AH38 15.5,-5.5; AH39 16.5,-5.5; AH40 17.5,-5.5; AH41 18.5,-5.5; AH42 19.5,-5.5; AH43 20.5,-5.5; AH44 21.5,-5.5; AJ1 -21.5,-6.5; AJ2 -20.5,-6.5; AJ3 -19.5,-6.5; AJ4 -18.5,-6.5; AJ5 -17.5,-6.5; AJ6 -16.5,-6.5; AJ7 -15.5,-6.5; AJ8 -14.5,-6.5; AJ9 -13.5,-6.5; AJ10 -12.5,-6.5; AJ11 -11.5,-6.5; AJ12 -10.5,-6.5; AJ13 -9.5,-6.5; AJ14 -8.5,-6.5; AJ15 -7.5,-6.5; AJ16 -6.5,-6.5; AJ17 -5.5,-6.5; AJ18 -4.5,-6.5; AJ19 -3.5,-6.5; AJ20 -2.5,-6.5; AJ21 -1.5,-6.5; AJ22 -0.5,-6.5; AJ23 0.5,-6.5; AJ24 1.5,-6.5; AJ25 2.5,-6.5; AJ26 3.5,-6.5; AJ27 4.5,-6.5; AJ28 5.5,-6.5; AJ29 6.5,-6.5; AJ30 7.5,-6.5; AJ31 8.5,-6.5; AJ32 9.5,-6.5; AJ33 10.5,-6.5; AJ34 11.5,-6.5; AJ35 12.5,-6.5; AJ36 13.5,-6.5; AJ37 14.5,-6.5; AJ38 15.5,-6.5; AJ39 16.5,-6.5; AJ40 17.5,-6.5; AJ41 18.5,-6.5; AJ42 19.5,-6.5; AJ43 20.5,-6.5; AJ44 21.5,-6.5; AK1 -21.5,-7.5; AK2 -20.5,-7.5; AK3 -19.5,-7.5; AK4 -18.5,-7.5; AK5 -17.5,-7.5; AK6 -16.5,-7.5; AK7 -15.5,-7.5; AK8 -14.5,-7.5; AK9 -13.5,-7.5; AK10 -12.5,-7.5; AK11 -11.5,-7.5; AK12 -10.5,-7.5; AK13 -9.5,-7.5; AK14 -8.5,-7.5; AK15 -7.5,-7.5; AK16 -6.5,-7.5; AK17 -5.5,-7.5; AK18 -4.5,-7.5; AK19 -3.5,-7.5; AK20 -2.5,-7.5; AK21 -1.5,-7.5; AK22 -0.5,-7.5; AK23 0.5,-7.5; AK24 1.5,-7.5; AK25 2.5,-7.5; AK26 3.5,-7.5; AK27 4.5,-7.5; AK28 5.5,-7.5; AK29 6.5,-7.5; AK30 7.5,-7.5; AK31 8.5,-7.5; AK32 9.5,-7.5; AK33 10.5,-7.5; AK34 11.5,-7.5; AK35 12.5,-7.5; AK36 13.5,-7.5; AK37 14.5,-7.5; AK38 15.5,-7.5; AK39 16.5,-7.5; AK40 17.5,-7.5; AK41 18.5,-7.5; AK42 19.5,-7.5; AK43 20.5,-7.5; AK44 21.5,-7.5; AL1 -21.5,-8.5; AL2 -20.5,-8.5; AL3 -19.5,-8.5; AL4 -18.5,-8.5; AL5 -17.5,-8.5; AL6 -16.5,-8.5; AL7 -15.5,-8.5; AL8 -14.5,-8.5; AL9 -13.5,-8.5; AL10 -12.5,-8.5; AL11 -11.5,-8.5; AL12 -10.5,-8.5; AL13 -9.5,-8.5; AL14 -8.5,-8.5; AL15 -7.5,-8.5; AL16 -6.5,-8.5; AL17 -5.5,-8.5; AL18 -4.5,-8.5; AL19 -3.5,-8.5; AL20 -2.5,-8.5; AL21 -1.5,-8.5; AL22 -0.5,-8.5; AL23 0.5,-8.5; AL24 1.5,-8.5; AL25 2.5,-8.5; AL26 3.5,-8.5; AL27 4.5,-8.5; AL28 5.5,-8.5; AL29 6.5,-8.5; AL30 7.5,-8.5; AL31 8.5,-8.5; AL32 9.5,-8.5; AL33 10.5,-8.5; AL34 11.5,-8.5; AL35 12.5,-8.5; AL36 13.5,-8.5; AL37 14.5,-8.5; AL38 15.5,-8.5; AL39 16.5,-8.5; AL40 17.5,-8.5; AL41 18.5,-8.5; AL42 19.5,-8.5; AL43 20.5,-8.5; AL44 21.5,-8.5; AM1 -21.5,-9.5; AM2 -20.5,-9.5; AM3 -19.5,-9.5; AM4 -18.5,-9.5; AM5 -17.5,-9.5; AM6 -16.5,-9.5; AM7 -15.5,-9.5; AM8 -14.5,-9.5; AM9 -13.5,-9.5; AM10 -12.5,-9.5; AM11 -11.5,-9.5; AM12 -10.5,-9.5; AM13 -9.5,-9.5; AM14 -8.5,-9.5; AM15 -7.5,-9.5; AM16 -6.5,-9.5; AM17 -5.5,-9.5; AM18 -4.5,-9.5; AM19 -3.5,-9.5; AM20 -2.5,-9.5; AM21 -1.5,-9.5; AM22 -0.5,-9.5; AM23 0.5,-9.5; AM24 1.5,-9.5; AM25 2.5,-9.5; AM26 3.5,-9.5; AM27 4.5,-9.5; AM28 5.5,-9.5; AM29 6.5,-9.5; AM30 7.5,-9.5; AM31 8.5,-9.5; AM32 9.5,-9.5; AM33 10.5,-9.5; AM34 11.5,-9.5; AM35 12.5,-9.5; AM36 13.5,-9.5; AM37 14.5,-9.5; AM38 15.5,-9.5; AM39 16.5,-9.5; AM40 17.5,-9.5; AM41 18.5,-9.5; AM42 19.5,-9.5; AM43 20.5,-9.5; AM44 21.5,-9.5; AN1 -21.5,-10.5; AN2 -20.5,-10.5; AN3 -19.5,-10.5; AN4 -18.5,-10.5; AN5 -17.5,-10.5; AN6 -16.5,-10.5; AN7 -15.5,-10.5; AN8 -14.5,-10.5; AN9 -13.5,-10.5; AN10 -12.5,-10.5; AN11 -11.5,-10.5; AN12 -10.5,-10.5; AN13 -9.5,-10.5; AN14 -8.5,-10.5; AN15 -7.5,-10.5; AN16 -6.5,-10.5; AN17 -5.5,-10.5; AN18 -4.5,-10.5; AN19 -3.5,-10.5; AN20 -2.5,-10.5; AN21 -1.5,-10.5; AN22 -0.5,-10.5; AN23 0.5,-10.5; AN24 1.5,-10.5; AN25 2.5,-10.5; AN26 3.5,-10.5; AN27 4.5,-10.5; AN28 5.5,-10.5; AN29 6.5,-10.5; AN30 7.5,-10.5; AN31 8.5,-10.5; AN32 9.5,-10.5; AN33 10.5,-10.5; AN34 11.5,-10.5; AN35 12.5,-10.5; AN36 13.5,-10.5; AN37 14.5,-10.5; AN38 15.5,-10.5; AN39 16.5,-10.5; AN40 17.5,-10.5; AN41 18.5,-10.5; AN42 19.5,-10.5; AN43 20.5,-10.5; AN44 21.5,-10.5; AP1 -21.5,-11.5; AP2 -20.5,-11.5; AP3 -19.5,-11.5; AP4 -18.5,-11.5; AP5 -17.5,-11.5; AP6 -16.5,-11.5; AP7 -15.5,-11.5; AP8 -14.5,-11.5; AP9 -13.5,-11.5; AP10 -12.5,-11.5; AP11 -11.5,-11.5; AP12 -10.5,-11.5; AP13 -9.5,-11.5; AP14 -8.5,-11.5; AP15 -7.5,-11.5; AP16 -6.5,-11.5; AP17 -5.5,-11.5; AP18 -4.5,-11.5; AP19 -3.5,-11.5; AP20 -2.5,-11.5; AP21 -1.5,-11.5; AP22 -0.5,-11.5; AP23 0.5,-11.5; AP24 1.5,-11.5; AP25 2.5,-11.5; AP26 3.5,-11.5; AP27 4.5,-11.5; AP28 5.5,-11.5; AP29 6.5,-11.5; AP30 7.5,-11.5; AP31 8.5,-11.5; AP32 9.5,-11.5; AP33 10.5,-11.5; AP34 11.5,-11.5; AP35 12.5,-11.5; AP36 13.5,-11.5; AP37 14.5,-11.5; AP38 15.5,-11.5; AP39 16.5,-11.5; AP40 17.5,-11.5; AP41 18.5,-11.5; AP42 19.5,-11.5; AP43 20.5,-11.5; AP44 21.5,-11.5; AR1 -21.5,-12.5; AR2 -20.5,-12.5; AR3 -19.5,-12.5; AR4 -18.5,-12.5; AR5 -17.5,-12.5; AR6 -16.5,-12.5; AR7 -15.5,-12.5; AR8 -14.5,-12.5; AR9 -13.5,-12.5; AR10 -12.5,-12.5; AR11 -11.5,-12.5; AR12 -10.5,-12.5; AR13 -9.5,-12.5; AR14 -8.5,-12.5; AR15 -7.5,-12.5; AR16 -6.5,-12.5; AR17 -5.5,-12.5; AR18 -4.5,-12.5; AR19 -3.5,-12.5; AR20 -2.5,-12.5; AR21 -1.5,-12.5; AR22 -0.5,-12.5; AR23 0.5,-12.5; AR24 1.5,-12.5; AR25 2.5,-12.5; AR26 3.5,-12.5; AR27 4.5,-12.5; AR28 5.5,-12.5; AR29 6.5,-12.5; AR30 7.5,-12.5; AR31 8.5,-12.5; AR32 9.5,-12.5; AR33 10.5,-12.5; AR34 11.5,-12.5; AR35 12.5,-12.5; AR36 13.5,-12.5; AR37 14.5,-12.5; AR38 15.5,-12.5; AR39 16.5,-12.5; AR40 17.5,-12.5; AR41 18.5,-12.5; AR42 19.5,-12.5; AR43 20.5,-12.5; AR44 21.5,-12.5; AT1 -21.5,-13.5; AT2 -20.5,-13.5; AT3 -19.5,-13.5; AT4 -18.5,-13.5; AT5 -17.5,-13.5; AT6 -16.5,-13.5; AT7 -15.5,-13.5; AT8 -14.5,-13.5; AT9 -13.5,-13.5; AT10 -12.5,-13.5; AT11 -11.5,-13.5; AT12 -10.5,-13.5; AT13 -9.5,-13.5; AT14 -8.5,-13.5; AT15 -7.5,-13.5; AT16 -6.5,-13.5; AT17 -5.5,-13.5; AT18 -4.5,-13.5; AT19 -3.5,-13.5; AT20 -2.5,-13.5; AT21 -1.5,-13.5; AT22 -0.5,-13.5; AT23 0.5,-13.5; AT24 1.5,-13.5; AT25 2.5,-13.5; AT26 3.5,-13.5; AT27 4.5,-13.5; AT28 5.5,-13.5; AT29 6.5,-13.5; AT30 7.5,-13.5; AT31 8.5,-13.5; AT32 9.5,-13.5; AT33 10.5,-13.5; AT34 11.5,-13.5; AT35 12.5,-13.5; AT36 13.5,-13.5; AT37 14.5,-13.5; AT38 15.5,-13.5; AT39 16.5,-13.5; AT40 17.5,-13.5; AT41 18.5,-13.5; AT42 19.5,-13.5; AT43 20.5,-13.5; AT44 21.5,-13.5; AU1 -21.5,-14.5; AU2 -20.5,-14.5; AU3 -19.5,-14.5; AU4 -18.5,-14.5; AU5 -17.5,-14.5; AU6 -16.5,-14.5; AU7 -15.5,-14.5; AU8 -14.5,-14.5; AU9 -13.5,-14.5; AU10 -12.5,-14.5; AU11 -11.5,-14.5; AU12 -10.5,-14.5; AU13 -9.5,-14.5; AU14 -8.5,-14.5; AU15 -7.5,-14.5; AU16 -6.5,-14.5; AU17 -5.5,-14.5; AU18 -4.5,-14.5; AU19 -3.5,-14.5; AU20 -2.5,-14.5; AU21 -1.5,-14.5; AU22 -0.5,-14.5; AU23 0.5,-14.5; AU24 1.5,-14.5; AU25 2.5,-14.5; AU26 3.5,-14.5; AU27 4.5,-14.5; AU28 5.5,-14.5; AU29 6.5,-14.5; AU30 7.5,-14.5; AU31 8.5,-14.5; AU32 9.5,-14.5; AU33 10.5,-14.5; AU34 11.5,-14.5; AU35 12.5,-14.5; AU36 13.5,-14.5; AU37 14.5,-14.5; AU38 15.5,-14.5; AU39 16.5,-14.5; AU40 17.5,-14.5; AU41 18.5,-14.5; AU42 19.5,-14.5; AU43 20.5,-14.5; AU44 21.5,-14.5; AV1 -21.5,-15.5; AV2 -20.5,-15.5; AV3 -19.5,-15.5; AV4 -18.5,-15.5; AV5 -17.5,-15.5; AV6 -16.5,-15.5; AV7 -15.5,-15.5; AV8 -14.5,-15.5; AV9 -13.5,-15.5; AV10 -12.5,-15.5; AV11 -11.5,-15.5; AV12 -10.5,-15.5; AV13 -9.5,-15.5; AV14 -8.5,-15.5; AV15 -7.5,-15.5; AV16 -6.5,-15.5; AV17 -5.5,-15.5; AV18 -4.5,-15.5; AV19 -3.5,-15.5; AV20 -2.5,-15.5; AV21 -1.5,-15.5; AV22 -0.5,-15.5; AV23 0.5,-15.5; AV24 1.5,-15.5; AV25 2.5,-15.5; AV26 3.5,-15.5; AV27 4.5,-15.5; AV28 5.5,-15.5; AV29 6.5,-15.5; AV30 7.5,-15.5; AV31 8.5,-15.5; AV32 9.5,-15.5; AV33 10.5,-15.5; AV34 11.5,-15.5; AV35 12.5,-15.5; AV36 13.5,-15.5; AV37 14.5,-15.5; AV38 15.5,-15.5; AV39 16.5,-15.5; AV40 17.5,-15.5; AV41 18.5,-15.5; AV42 19.5,-15.5; AV43 20.5,-15.5; AV44 21.5,-15.5; AW1 -21.5,-16.5; AW2 -20.5,-16.5; AW3 -19.5,-16.5; AW4 -18.5,-16.5; AW5 -17.5,-16.5; AW6 -16.5,-16.5; AW7 -15.5,-16.5; AW8 -14.5,-16.5; AW9 -13.5,-16.5; AW10 -12.5,-16.5; AW11 -11.5,-16.5; AW12 -10.5,-16.5; AW13 -9.5,-16.5; AW14 -8.5,-16.5; AW15 -7.5,-16.5; AW16 -6.5,-16.5; AW17 -5.5,-16.5; AW18 -4.5,-16.5; AW19 -3.5,-16.5; AW20 -2.5,-16.5; AW21 -1.5,-16.5; AW22 -0.5,-16.5; AW23 0.5,-16.5; AW24 1.5,-16.5; AW25 2.5,-16.5; AW26 3.5,-16.5; AW27 4.5,-16.5; AW28 5.5,-16.5; AW29 6.5,-16.5; AW30 7.5,-16.5; AW31 8.5,-16.5; AW32 9.5,-16.5; AW33 10.5,-16.5; AW34 11.5,-16.5; AW35 12.5,-16.5; AW36 13.5,-16.5; AW37 14.5,-16.5; AW38 15.5,-16.5; AW39 16.5,-16.5; AW40 17.5,-16.5; AW41 18.5,-16.5; AW42 19.5,-16.5; AW43 20.5,-16.5; AW44 21.5,-16.5; AY1 -21.5,-17.5; AY2 -20.5,-17.5; AY3 -19.5,-17.5; AY4 -18.5,-17.5; AY5 -17.5,-17.5; AY6 -16.5,-17.5; AY7 -15.5,-17.5; AY8 -14.5,-17.5; AY9 -13.5,-17.5; AY10 -12.5,-17.5; AY11 -11.5,-17.5; AY12 -10.5,-17.5; AY13 -9.5,-17.5; AY14 -8.5,-17.5; AY15 -7.5,-17.5; AY16 -6.5,-17.5; AY17 -5.5,-17.5; AY18 -4.5,-17.5; AY19 -3.5,-17.5; AY20 -2.5,-17.5; AY21 -1.5,-17.5; AY22 -0.5,-17.5; AY23 0.5,-17.5; AY24 1.5,-17.5; AY25 2.5,-17.5; AY26 3.5,-17.5; AY27 4.5,-17.5; AY28 5.5,-17.5; AY29 6.5,-17.5; AY30 7.5,-17.5; AY31 8.5,-17.5; AY32 9.5,-17.5; AY33 10.5,-17.5; AY34 11.5,-17.5; AY35 12.5,-17.5; AY36 13.5,-17.5; AY37 14.5,-17.5; AY38 15.5,-17.5; AY39 16.5,-17.5; AY40 17.5,-17.5; AY41 18.5,-17.5; AY42 19.5,-17.5; AY43 20.5,-17.5; AY44 21.5,-17.5; B1 -21.5,20.5; B2 -20.5,20.5; B3 -19.5,20.5; B4 -18.5,20.5; B5 -17.5,20.5; B6 -16.5,20.5; B7 -15.5,20.5; B8 -14.5,20.5; B9 -13.5,20.5; B10 -12.5,20.5; B11 -11.5,20.5; B12 -10.5,20.5; B13 -9.5,20.5; B14 -8.5,20.5; B15 -7.5,20.5; B16 -6.5,20.5; B17 -5.5,20.5; B18 -4.5,20.5; B19 -3.5,20.5; B20 -2.5,20.5; B21 -1.5,20.5; B22 -0.5,20.5; B23 0.5,20.5; B24 1.5,20.5; B25 2.5,20.5; B26 3.5,20.5; B27 4.5,20.5; B28 5.5,20.5; B29 6.5,20.5; B30 7.5,20.5; B31 8.5,20.5; B32 9.5,20.5; B33 10.5,20.5; B34 11.5,20.5; B35 12.5,20.5; B36 13.5,20.5; B37 14.5,20.5; B38 15.5,20.5; B39 16.5,20.5; B40 17.5,20.5; B41 18.5,20.5; B42 19.5,20.5; B43 20.5,20.5; B44 21.5,20.5; BA1 -21.5,-18.5; BA2 -20.5,-18.5; BA3 -19.5,-18.5; BA4 -18.5,-18.5; BA5 -17.5,-18.5; BA6 -16.5,-18.5; BA7 -15.5,-18.5; BA8 -14.5,-18.5; BA9 -13.5,-18.5; BA10 -12.5,-18.5; BA11 -11.5,-18.5; BA12 -10.5,-18.5; BA13 -9.5,-18.5; BA14 -8.5,-18.5; BA15 -7.5,-18.5; BA16 -6.5,-18.5; BA17 -5.5,-18.5; BA18 -4.5,-18.5; BA19 -3.5,-18.5; BA20 -2.5,-18.5; BA21 -1.5,-18.5; BA22 -0.5,-18.5; BA23 0.5,-18.5; BA24 1.5,-18.5; BA25 2.5,-18.5; BA26 3.5,-18.5; BA27 4.5,-18.5; BA28 5.5,-18.5; BA29 6.5,-18.5; BA30 7.5,-18.5; BA31 8.5,-18.5; BA32 9.5,-18.5; BA33 10.5,-18.5; BA34 11.5,-18.5; BA35 12.5,-18.5; BA36 13.5,-18.5; BA37 14.5,-18.5; BA38 15.5,-18.5; BA39 16.5,-18.5; BA40 17.5,-18.5; BA41 18.5,-18.5; BA42 19.5,-18.5; BA43 20.5,-18.5; BA44 21.5,-18.5; BB1 -21.5,-19.5; BB2 -20.5,-19.5; BB3 -19.5,-19.5; BB4 -18.5,-19.5; BB5 -17.5,-19.5; BB6 -16.5,-19.5; BB7 -15.5,-19.5; BB8 -14.5,-19.5; BB9 -13.5,-19.5; BB10 -12.5,-19.5; BB11 -11.5,-19.5; BB12 -10.5,-19.5; BB13 -9.5,-19.5; BB14 -8.5,-19.5; BB15 -7.5,-19.5; BB16 -6.5,-19.5; BB17 -5.5,-19.5; BB18 -4.5,-19.5; BB19 -3.5,-19.5; BB20 -2.5,-19.5; BB21 -1.5,-19.5; BB22 -0.5,-19.5; BB23 0.5,-19.5; BB24 1.5,-19.5; BB25 2.5,-19.5; BB26 3.5,-19.5; BB27 4.5,-19.5; BB28 5.5,-19.5; BB29 6.5,-19.5; BB30 7.5,-19.5; BB31 8.5,-19.5; BB32 9.5,-19.5; BB33 10.5,-19.5; BB34 11.5,-19.5; BB35 12.5,-19.5; BB36 13.5,-19.5; BB37 14.5,-19.5; BB38 15.5,-19.5; BB39 16.5,-19.5; BB40 17.5,-19.5; BB41 18.5,-19.5; BB42 19.5,-19.5; BB43 20.5,-19.5; BB44 21.5,-19.5; BC1 -21.5,-20.5; BC2 -20.5,-20.5; BC3 -19.5,-20.5; BC4 -18.5,-20.5; BC5 -17.5,-20.5; BC6 -16.5,-20.5; BC7 -15.5,-20.5; BC8 -14.5,-20.5; BC9 -13.5,-20.5; BC10 -12.5,-20.5; BC11 -11.5,-20.5; BC12 -10.5,-20.5; BC13 -9.5,-20.5; BC14 -8.5,-20.5; BC15 -7.5,-20.5; BC16 -6.5,-20.5; BC17 -5.5,-20.5; BC18 -4.5,-20.5; BC19 -3.5,-20.5; BC20 -2.5,-20.5; BC21 -1.5,-20.5; BC22 -0.5,-20.5; BC23 0.5,-20.5; BC24 1.5,-20.5; BC25 2.5,-20.5; BC26 3.5,-20.5; BC27 4.5,-20.5; BC28 5.5,-20.5; BC29 6.5,-20.5; BC30 7.5,-20.5; BC31 8.5,-20.5; BC32 9.5,-20.5; BC33 10.5,-20.5; BC34 11.5,-20.5; BC35 12.5,-20.5; BC36 13.5,-20.5; BC37 14.5,-20.5; BC38 15.5,-20.5; BC39 16.5,-20.5; BC40 17.5,-20.5; BC41 18.5,-20.5; BC42 19.5,-20.5; BC43 20.5,-20.5; BC44 21.5,-20.5; BD2 -20.5,-21.5; BD3 -19.5,-21.5; BD4 -18.5,-21.5; BD5 -17.5,-21.5; BD6 -16.5,-21.5; BD7 -15.5,-21.5; BD8 -14.5,-21.5; BD9 -13.5,-21.5; BD10 -12.5,-21.5; BD11 -11.5,-21.5; BD12 -10.5,-21.5; BD13 -9.5,-21.5; BD14 -8.5,-21.5; BD15 -7.5,-21.5; BD16 -6.5,-21.5; BD17 -5.5,-21.5; BD18 -4.5,-21.5; BD19 -3.5,-21.5; BD20 -2.5,-21.5; BD21 -1.5,-21.5; BD22 -0.5,-21.5; BD23 0.5,-21.5; BD24 1.5,-21.5; BD25 2.5,-21.5; BD26 3.5,-21.5; BD27 4.5,-21.5; BD28 5.5,-21.5; BD29 6.5,-21.5; BD30 7.5,-21.5; BD31 8.5,-21.5; BD32 9.5,-21.5; BD33 10.5,-21.5; BD34 11.5,-21.5; BD35 12.5,-21.5; BD36 13.5,-21.5; BD37 14.5,-21.5; BD38 15.5,-21.5; BD39 16.5,-21.5; BD40 17.5,-21.5; BD41 18.5,-21.5; BD42 19.5,-21.5; BD43 20.5,-21.5; C1 -21.5,19.5; C2 -20.5,19.5; C3 -19.5,19.5; C4 -18.5,19.5; C5 -17.5,19.5; C6 -16.5,19.5; C7 -15.5,19.5; C8 -14.5,19.5; C9 -13.5,19.5; C10 -12.5,19.5; C11 -11.5,19.5; C12 -10.5,19.5; C13 -9.5,19.5; C14 -8.5,19.5; C15 -7.5,19.5; C16 -6.5,19.5; C17 -5.5,19.5; C18 -4.5,19.5; C19 -3.5,19.5; C20 -2.5,19.5; C21 -1.5,19.5; C22 -0.5,19.5; C23 0.5,19.5; C24 1.5,19.5; C25 2.5,19.5; C26 3.5,19.5; C27 4.5,19.5; C28 5.5,19.5; C29 6.5,19.5; C30 7.5,19.5; C31 8.5,19.5; C32 9.5,19.5; C33 10.5,19.5; C34 11.5,19.5; C35 12.5,19.5; C36 13.5,19.5; C37 14.5,19.5; C38 15.5,19.5; C39 16.5,19.5; C40 17.5,19.5; C41 18.5,19.5; C42 19.5,19.5; C43 20.5,19.5; C44 21.5,19.5; D1 -21.5,18.5; D2 -20.5,18.5; D3 -19.5,18.5; D4 -18.5,18.5; D5 -17.5,18.5; D6 -16.5,18.5; D7 -15.5,18.5; D8 -14.5,18.5; D9 -13.5,18.5; D10 -12.5,18.5; D11 -11.5,18.5; D12 -10.5,18.5; D13 -9.5,18.5; D14 -8.5,18.5; D15 -7.5,18.5; D16 -6.5,18.5; D17 -5.5,18.5; D18 -4.5,18.5; D19 -3.5,18.5; D20 -2.5,18.5; D21 -1.5,18.5; D22 -0.5,18.5; D23 0.5,18.5; D24 1.5,18.5; D25 2.5,18.5; D26 3.5,18.5; D27 4.5,18.5; D28 5.5,18.5; D29 6.5,18.5; D30 7.5,18.5; D31 8.5,18.5; D32 9.5,18.5; D33 10.5,18.5; D34 11.5,18.5; D35 12.5,18.5; D36 13.5,18.5; D37 14.5,18.5; D38 15.5,18.5; D39 16.5,18.5; D40 17.5,18.5; D41 18.5,18.5; D42 19.5,18.5; D43 20.5,18.5; D44 21.5,18.5; E1 -21.5,17.5; E2 -20.5,17.5; E3 -19.5,17.5; E4 -18.5,17.5; E5 -17.5,17.5; E6 -16.5,17.5; E7 -15.5,17.5; E8 -14.5,17.5; E9 -13.5,17.5; E10 -12.5,17.5; E11 -11.5,17.5; E12 -10.5,17.5; E13 -9.5,17.5; E14 -8.5,17.5; E15 -7.5,17.5; E16 -6.5,17.5; E17 -5.5,17.5; E18 -4.5,17.5; E19 -3.5,17.5; E20 -2.5,17.5; E21 -1.5,17.5; E22 -0.5,17.5; E23 0.5,17.5; E24 1.5,17.5; E25 2.5,17.5; E26 3.5,17.5; E27 4.5,17.5; E28 5.5,17.5; E29 6.5,17.5; E30 7.5,17.5; E31 8.5,17.5; E32 9.5,17.5; E33 10.5,17.5; E34 11.5,17.5; E35 12.5,17.5; E36 13.5,17.5; E37 14.5,17.5; E38 15.5,17.5; E39 16.5,17.5; E40 17.5,17.5; E41 18.5,17.5; E42 19.5,17.5; E43 20.5,17.5; E44 21.5,17.5; F1 -21.5,16.5; F2 -20.5,16.5; F3 -19.5,16.5; F4 -18.5,16.5; F5 -17.5,16.5; F6 -16.5,16.5; F7 -15.5,16.5; F8 -14.5,16.5; F9 -13.5,16.5; F10 -12.5,16.5; F11 -11.5,16.5; F12 -10.5,16.5; F13 -9.5,16.5; F14 -8.5,16.5; F15 -7.5,16.5; F16 -6.5,16.5; F17 -5.5,16.5; F18 -4.5,16.5; F19 -3.5,16.5; F20 -2.5,16.5; F21 -1.5,16.5; F22 -0.5,16.5; F23 0.5,16.5; F24 1.5,16.5; F25 2.5,16.5; F26 3.5,16.5; F27 4.5,16.5; F28 5.5,16.5; F29 6.5,16.5; F30 7.5,16.5; F31 8.5,16.5; F32 9.5,16.5; F33 10.5,16.5; F34 11.5,16.5; F35 12.5,16.5; F36 13.5,16.5; F37 14.5,16.5; F38 15.5,16.5; F39 16.5,16.5; F40 17.5,16.5; F41 18.5,16.5; F42 19.5,16.5; F43 20.5,16.5; F44 21.5,16.5; G1 -21.5,15.5; G2 -20.5,15.5; G3 -19.5,15.5; G4 -18.5,15.5; G5 -17.5,15.5; G6 -16.5,15.5; G7 -15.5,15.5; G8 -14.5,15.5; G9 -13.5,15.5; G10 -12.5,15.5; G11 -11.5,15.5; G12 -10.5,15.5; G13 -9.5,15.5; G14 -8.5,15.5; G15 -7.5,15.5; G16 -6.5,15.5; G17 -5.5,15.5; G18 -4.5,15.5; G19 -3.5,15.5; G20 -2.5,15.5; G21 -1.5,15.5; G22 -0.5,15.5; G23 0.5,15.5; G24 1.5,15.5; G25 2.5,15.5; G26 3.5,15.5; G27 4.5,15.5; G28 5.5,15.5; G29 6.5,15.5; G30 7.5,15.5; G31 8.5,15.5; G32 9.5,15.5; G33 10.5,15.5; G34 11.5,15.5; G35 12.5,15.5; G36 13.5,15.5; G37 14.5,15.5; G38 15.5,15.5; G39 16.5,15.5; G40 17.5,15.5; G41 18.5,15.5; G42 19.5,15.5; G43 20.5,15.5; G44 21.5,15.5; H1 -21.5,14.5; H2 -20.5,14.5; H3 -19.5,14.5; H4 -18.5,14.5; H5 -17.5,14.5; H6 -16.5,14.5; H7 -15.5,14.5; H8 -14.5,14.5; H9 -13.5,14.5; H10 -12.5,14.5; H11 -11.5,14.5; H12 -10.5,14.5; H13 -9.5,14.5; H14 -8.5,14.5; H15 -7.5,14.5; H16 -6.5,14.5; H17 -5.5,14.5; H18 -4.5,14.5; H19 -3.5,14.5; H20 -2.5,14.5; H21 -1.5,14.5; H22 -0.5,14.5; H23 0.5,14.5; H24 1.5,14.5; H25 2.5,14.5; H26 3.5,14.5; H27 4.5,14.5; H28 5.5,14.5; H29 6.5,14.5; H30 7.5,14.5; H31 8.5,14.5; H32 9.5,14.5; H33 10.5,14.5; H34 11.5,14.5; H35 12.5,14.5; H36 13.5,14.5; H37 14.5,14.5; H38 15.5,14.5; H39 16.5,14.5; H40 17.5,14.5; H41 18.5,14.5; H42 19.5,14.5; H43 20.5,14.5; H44 21.5,14.5; J1 -21.5,13.5; J2 -20.5,13.5; J3 -19.5,13.5; J4 -18.5,13.5; J5 -17.5,13.5; J6 -16.5,13.5; J7 -15.5,13.5; J8 -14.5,13.5; J9 -13.5,13.5; J10 -12.5,13.5; J11 -11.5,13.5; J12 -10.5,13.5; J13 -9.5,13.5; J14 -8.5,13.5; J15 -7.5,13.5; J16 -6.5,13.5; J17 -5.5,13.5; J18 -4.5,13.5; J19 -3.5,13.5; J20 -2.5,13.5; J21 -1.5,13.5; J22 -0.5,13.5; J23 0.5,13.5; J24 1.5,13.5; J25 2.5,13.5; J26 3.5,13.5; J27 4.5,13.5; J28 5.5,13.5; J29 6.5,13.5; J30 7.5,13.5; J31 8.5,13.5; J32 9.5,13.5; J33 10.5,13.5; J34 11.5,13.5; J35 12.5,13.5; J36 13.5,13.5; J37 14.5,13.5; J38 15.5,13.5; J39 16.5,13.5; J40 17.5,13.5; J41 18.5,13.5; J42 19.5,13.5; J43 20.5,13.5; J44 21.5,13.5; K1 -21.5,12.5; K2 -20.5,12.5; K3 -19.5,12.5; K4 -18.5,12.5; K5 -17.5,12.5; K6 -16.5,12.5; K7 -15.5,12.5; K8 -14.5,12.5; K9 -13.5,12.5; K10 -12.5,12.5; K11 -11.5,12.5; K12 -10.5,12.5; K13 -9.5,12.5; K14 -8.5,12.5; K15 -7.5,12.5; K16 -6.5,12.5; K17 -5.5,12.5; K18 -4.5,12.5; K19 -3.5,12.5; K20 -2.5,12.5; K21 -1.5,12.5; K22 -0.5,12.5; K23 0.5,12.5; K24 1.5,12.5; K25 2.5,12.5; K26 3.5,12.5; K27 4.5,12.5; K28 5.5,12.5; K29 6.5,12.5; K30 7.5,12.5; K31 8.5,12.5; K32 9.5,12.5; K33 10.5,12.5; K34 11.5,12.5; K35 12.5,12.5; K36 13.5,12.5; K37 14.5,12.5; K38 15.5,12.5; K39 16.5,12.5; K40 17.5,12.5; K41 18.5,12.5; K42 19.5,12.5; K43 20.5,12.5; K44 21.5,12.5; L1 -21.5,11.5; L2 -20.5,11.5; L3 -19.5,11.5; L4 -18.5,11.5; L5 -17.5,11.5; L6 -16.5,11.5; L7 -15.5,11.5; L8 -14.5,11.5; L9 -13.5,11.5; L10 -12.5,11.5; L11 -11.5,11.5; L12 -10.5,11.5; L13 -9.5,11.5; L14 -8.5,11.5; L15 -7.5,11.5; L16 -6.5,11.5; L17 -5.5,11.5; L18 -4.5,11.5; L19 -3.5,11.5; L20 -2.5,11.5; L21 -1.5,11.5; L22 -0.5,11.5; L23 0.5,11.5; L24 1.5,11.5; L25 2.5,11.5; L26 3.5,11.5; L27 4.5,11.5; L28 5.5,11.5; L29 6.5,11.5; L30 7.5,11.5; L31 8.5,11.5; L32 9.5,11.5; L33 10.5,11.5; L34 11.5,11.5; L35 12.5,11.5; L36 13.5,11.5; L37 14.5,11.5; L38 15.5,11.5; L39 16.5,11.5; L40 17.5,11.5; L41 18.5,11.5; L42 19.5,11.5; L43 20.5,11.5; L44 21.5,11.5; M1 -21.5,10.5; M2 -20.5,10.5; M3 -19.5,10.5; M4 -18.5,10.5; M5 -17.5,10.5; M6 -16.5,10.5; M7 -15.5,10.5; M8 -14.5,10.5; M9 -13.5,10.5; M10 -12.5,10.5; M11 -11.5,10.5; M12 -10.5,10.5; M13 -9.5,10.5; M14 -8.5,10.5; M15 -7.5,10.5; M16 -6.5,10.5; M17 -5.5,10.5; M18 -4.5,10.5; M19 -3.5,10.5; M20 -2.5,10.5; M21 -1.5,10.5; M22 -0.5,10.5; M23 0.5,10.5; M24 1.5,10.5; M25 2.5,10.5; M26 3.5,10.5; M27 4.5,10.5; M28 5.5,10.5; M29 6.5,10.5; M30 7.5,10.5; M31 8.5,10.5; M32 9.5,10.5; M33 10.5,10.5; M34 11.5,10.5; M35 12.5,10.5; M36 13.5,10.5; M37 14.5,10.5; M38 15.5,10.5; M39 16.5,10.5; M40 17.5,10.5; M41 18.5,10.5; M42 19.5,10.5; M43 20.5,10.5; M44 21.5,10.5; N1 -21.5,9.5; N2 -20.5,9.5; N3 -19.5,9.5; N4 -18.5,9.5; N5 -17.5,9.5; N6 -16.5,9.5; N7 -15.5,9.5; N8 -14.5,9.5; N9 -13.5,9.5; N10 -12.5,9.5; N11 -11.5,9.5; N12 -10.5,9.5; N13 -9.5,9.5; N14 -8.5,9.5; N15 -7.5,9.5; N16 -6.5,9.5; N17 -5.5,9.5; N18 -4.5,9.5; N19 -3.5,9.5; N20 -2.5,9.5; N21 -1.5,9.5; N22 -0.5,9.5; N23 0.5,9.5; N24 1.5,9.5; N25 2.5,9.5; N26 3.5,9.5; N27 4.5,9.5; N28 5.5,9.5; N29 6.5,9.5; N30 7.5,9.5; N31 8.5,9.5; N32 9.5,9.5; N33 10.5,9.5; N34 11.5,9.5; N35 12.5,9.5; N36 13.5,9.5; N37 14.5,9.5; N38 15.5,9.5; N39 16.5,9.5; N40 17.5,9.5; N41 18.5,9.5; N42 19.5,9.5; N43 20.5,9.5; N44 21.5,9.5; P1 -21.5,8.5; P2 -20.5,8.5; P3 -19.5,8.5; P4 -18.5,8.5; P5 -17.5,8.5; P6 -16.5,8.5; P7 -15.5,8.5; P8 -14.5,8.5; P9 -13.5,8.5; P10 -12.5,8.5; P11 -11.5,8.5; P12 -10.5,8.5; P13 -9.5,8.5; P14 -8.5,8.5; P15 -7.5,8.5; P16 -6.5,8.5; P17 -5.5,8.5; P18 -4.5,8.5; P19 -3.5,8.5; P20 -2.5,8.5; P21 -1.5,8.5; P22 -0.5,8.5; P23 0.5,8.5; P24 1.5,8.5; P25 2.5,8.5; P26 3.5,8.5; P27 4.5,8.5; P28 5.5,8.5; P29 6.5,8.5; P30 7.5,8.5; P31 8.5,8.5; P32 9.5,8.5; P33 10.5,8.5; P34 11.5,8.5; P35 12.5,8.5; P36 13.5,8.5; P37 14.5,8.5; P38 15.5,8.5; P39 16.5,8.5; P40 17.5,8.5; P41 18.5,8.5; P42 19.5,8.5; P43 20.5,8.5; P44 21.5,8.5; R1 -21.5,7.5; R2 -20.5,7.5; R3 -19.5,7.5; R4 -18.5,7.5; R5 -17.5,7.5; R6 -16.5,7.5; R7 -15.5,7.5; R8 -14.5,7.5; R9 -13.5,7.5; R10 -12.5,7.5; R11 -11.5,7.5; R12 -10.5,7.5; R13 -9.5,7.5; R14 -8.5,7.5; R15 -7.5,7.5; R16 -6.5,7.5; R17 -5.5,7.5; R18 -4.5,7.5; R19 -3.5,7.5; R20 -2.5,7.5; R21 -1.5,7.5; R22 -0.5,7.5; R23 0.5,7.5; R24 1.5,7.5; R25 2.5,7.5; R26 3.5,7.5; R27 4.5,7.5; R28 5.5,7.5; R29 6.5,7.5; R30 7.5,7.5; R31 8.5,7.5; R32 9.5,7.5; R33 10.5,7.5; R34 11.5,7.5; R35 12.5,7.5; R36 13.5,7.5; R37 14.5,7.5; R38 15.5,7.5; R39 16.5,7.5; R40 17.5,7.5; R41 18.5,7.5; R42 19.5,7.5; R43 20.5,7.5; R44 21.5,7.5; T1 -21.5,6.5; T2 -20.5,6.5; T3 -19.5,6.5; T4 -18.5,6.5; T5 -17.5,6.5; T6 -16.5,6.5; T7 -15.5,6.5; T8 -14.5,6.5; T9 -13.5,6.5; T10 -12.5,6.5; T11 -11.5,6.5; T12 -10.5,6.5; T13 -9.5,6.5; T14 -8.5,6.5; T15 -7.5,6.5; T16 -6.5,6.5; T17 -5.5,6.5; T18 -4.5,6.5; T19 -3.5,6.5; T20 -2.5,6.5; T21 -1.5,6.5; T22 -0.5,6.5; T23 0.5,6.5; T24 1.5,6.5; T25 2.5,6.5; T26 3.5,6.5; T27 4.5,6.5; T28 5.5,6.5; T29 6.5,6.5; T30 7.5,6.5; T31 8.5,6.5; T32 9.5,6.5; T33 10.5,6.5; T34 11.5,6.5; T35 12.5,6.5; T36 13.5,6.5; T37 14.5,6.5; T38 15.5,6.5; T39 16.5,6.5; T40 17.5,6.5; T41 18.5,6.5; T42 19.5,6.5; T43 20.5,6.5; T44 21.5,6.5; U1 -21.5,5.5; U2 -20.5,5.5; U3 -19.5,5.5; U4 -18.5,5.5; U5 -17.5,5.5; U6 -16.5,5.5; U7 -15.5,5.5; U8 -14.5,5.5; U9 -13.5,5.5; U10 -12.5,5.5; U11 -11.5,5.5; U12 -10.5,5.5; U13 -9.5,5.5; U14 -8.5,5.5; U15 -7.5,5.5; U16 -6.5,5.5; U17 -5.5,5.5; U18 -4.5,5.5; U19 -3.5,5.5; U20 -2.5,5.5; U21 -1.5,5.5; U22 -0.5,5.5; U23 0.5,5.5; U24 1.5,5.5; U25 2.5,5.5; U26 3.5,5.5; U27 4.5,5.5; U28 5.5,5.5; U29 6.5,5.5; U30 7.5,5.5; U31 8.5,5.5; U32 9.5,5.5; U33 10.5,5.5; U34 11.5,5.5; U35 12.5,5.5; U36 13.5,5.5; U37 14.5,5.5; U38 15.5,5.5; U39 16.5,5.5; U40 17.5,5.5; U41 18.5,5.5; U42 19.5,5.5; U43 20.5,5.5; U44 21.5,5.5; V1 -21.5,4.5; V2 -20.5,4.5; V3 -19.5,4.5; V4 -18.5,4.5; V5 -17.5,4.5; V6 -16.5,4.5; V7 -15.5,4.5; V8 -14.5,4.5; V9 -13.5,4.5; V10 -12.5,4.5; V11 -11.5,4.5; V12 -10.5,4.5; V13 -9.5,4.5; V14 -8.5,4.5; V15 -7.5,4.5; V16 -6.5,4.5; V17 -5.5,4.5; V18 -4.5,4.5; V19 -3.5,4.5; V20 -2.5,4.5; V21 -1.5,4.5; V22 -0.5,4.5; V23 0.5,4.5; V24 1.5,4.5; V25 2.5,4.5; V26 3.5,4.5; V27 4.5,4.5; V28 5.5,4.5; V29 6.5,4.5; V30 7.5,4.5; V31 8.5,4.5; V32 9.5,4.5; V33 10.5,4.5; V34 11.5,4.5; V35 12.5,4.5; V36 13.5,4.5; V37 14.5,4.5; V38 15.5,4.5; V39 16.5,4.5; V40 17.5,4.5; V41 18.5,4.5; V42 19.5,4.5; V43 20.5,4.5; V44 21.5,4.5; W1 -21.5,3.5; W2 -20.5,3.5; W3 -19.5,3.5; W4 -18.5,3.5; W5 -17.5,3.5; W6 -16.5,3.5; W7 -15.5,3.5; W8 -14.5,3.5; W9 -13.5,3.5; W10 -12.5,3.5; W11 -11.5,3.5; W12 -10.5,3.5; W13 -9.5,3.5; W14 -8.5,3.5; W15 -7.5,3.5; W16 -6.5,3.5; W17 -5.5,3.5; W18 -4.5,3.5; W19 -3.5,3.5; W20 -2.5,3.5; W21 -1.5,3.5; W22 -0.5,3.5; W23 0.5,3.5; W24 1.5,3.5; W25 2.5,3.5; W26 3.5,3.5; W27 4.5,3.5; W28 5.5,3.5; W29 6.5,3.5; W30 7.5,3.5; W31 8.5,3.5; W32 9.5,3.5; W33 10.5,3.5; W34 11.5,3.5; W35 12.5,3.5; W36 13.5,3.5; W37 14.5,3.5; W38 15.5,3.5; W39 16.5,3.5; W40 17.5,3.5; W41 18.5,3.5; W42 19.5,3.5; W43 20.5,3.5; W44 21.5,3.5; Y1 -21.5,2.5; Y2 -20.5,2.5; Y3 -19.5,2.5; Y4 -18.5,2.5; Y5 -17.5,2.5; Y6 -16.5,2.5; Y7 -15.5,2.5; Y8 -14.5,2.5; Y9 -13.5,2.5; Y10 -12.5,2.5; Y11 -11.5,2.5; Y12 -10.5,2.5; Y13 -9.5,2.5; Y14 -8.5,2.5; Y15 -7.5,2.5; Y16 -6.5,2.5; Y17 -5.5,2.5; Y18 -4.5,2.5; Y19 -3.5,2.5; Y20 -2.5,2.5; Y21 -1.5,2.5; Y22 -0.5,2.5; Y23 0.5,2.5; Y24 1.5,2.5; Y25 2.5,2.5; Y26 3.5,2.5; Y27 4.5,2.5; Y28 5.5,2.5; Y29 6.5,2.5; Y30 7.5,2.5; Y31 8.5,2.5; Y32 9.5,2.5; Y33 10.5,2.5; Y34 11.5,2.5; Y35 12.5,2.5; Y36 13.5,2.5; Y37 14.5,2.5; Y38 15.5,2.5; Y39 16.5,2.5; Y40 17.5,2.5; Y41 18.5,2.5; Y42 19.5,2.5; Y43 20.5,2.5; Y44 21.5,2.5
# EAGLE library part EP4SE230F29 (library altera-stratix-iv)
EP4SE230F29 Auto generated by make-symbol-device-package-bsdl.ulp Rev. 29 Source: EP4SE230F29.bsd

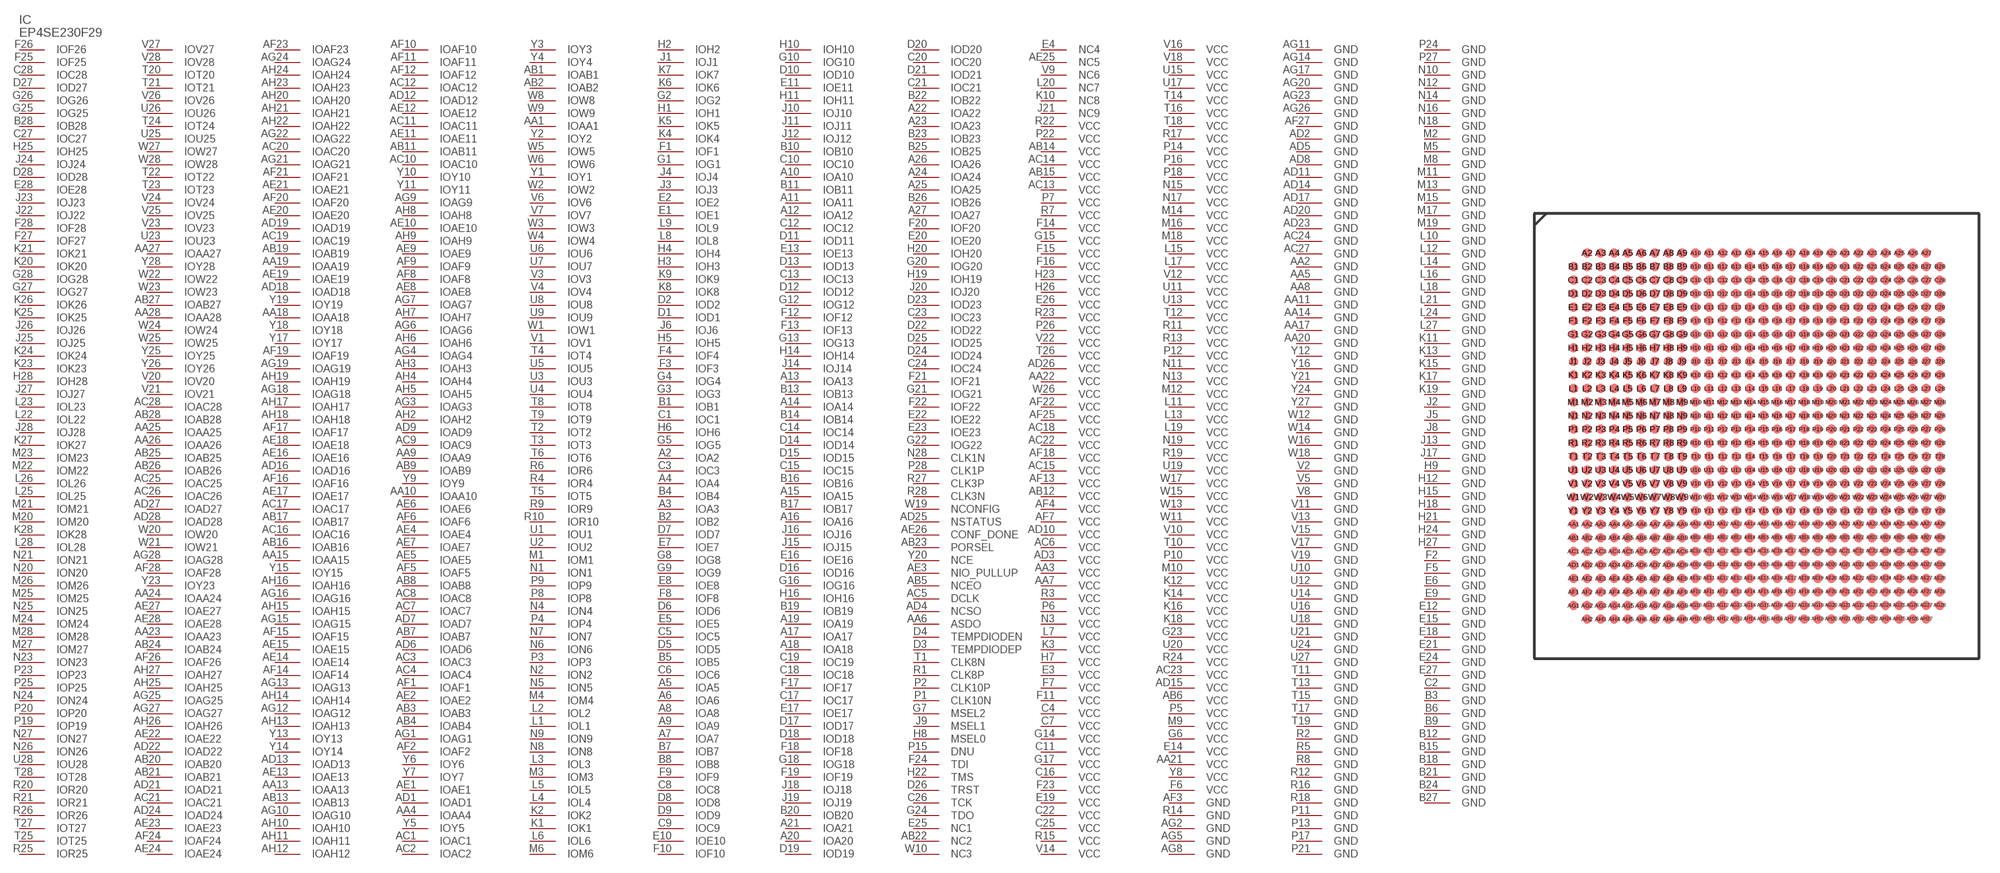
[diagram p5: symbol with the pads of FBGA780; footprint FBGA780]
Designator prefix IC

## EP4SE230F29 (MPN: EP4SE230F29C2; OC_FARNELL: unknown; OC_NEWARK: 52R1671)  [FBGA780]
A2  IOA2
A3  IOA3
A4  IOA4
A5  IOA5
A6  IOA6
A7  IOA7
A8  IOA8
A9  IOA9
A10  IOA10
A11  IOA11
A12  IOA12
A13  IOA13
A14  IOA14
A15  IOA15
A16  IOA16
A17  IOA17
A18  IOA18
A19  IOA19
A20  IOA20
A21  IOA21
A22  IOA22
A23  IOA23
A24  IOA24
A25  IOA25
A26  IOA26
A27  IOA27
AA1  IOAA1
AA2  GND  pwr
AA3  VCC  pwr
AA4  IOAA4
AA5  GND  pwr
AA6  ASDO  in
AA7  VCC  pwr
AA8  GND  pwr
AA9  IOAA9
AA10  IOAA10
AA11  GND  pwr
AA13  IOAA13
AA14  GND  pwr
AA15  IOAA15
AA17  GND  pwr
AA18  IOAA18
AA19  IOAA19
AA20  GND  pwr
AA21  VCC  pwr
AA22  VCC  pwr
AA23  IOAA23
AA24  IOAA24
AA25  IOAA25
AA26  IOAA26
AA27  IOAA27
AA28  IOAA28
AB1  IOAB1
AB2  IOAB2
AB3  IOAB3
AB4  IOAB4
AB5  NCEO  in
AB6  VCC  pwr
AB7  IOAB7
AB8  IOAB8
AB9  IOAB9
AB11  IOAB11
AB12  VCC  pwr
AB13  IOAB13
AB14  VCC  pwr
AB15  VCC  pwr
AB16  IOAB16
AB17  IOAB17
AB19  IOAB19
AB20  IOAB20
AB21  IOAB21
AB22  NC2  pas
AB23  PORSEL  in
AB24  IOAB24
AB25  IOAB25
AB26  IOAB26
AB27  IOAB27
AB28  IOAB28
AC1  IOAC1
AC2  IOAC2
AC3  IOAC3
AC4  IOAC4
AC5  DCLK  in
AC6  VCC  pwr
AC7  IOAC7
AC8  IOAC8
AC9  IOAC9
AC10  IOAC10
AC11  IOAC11
AC12  IOAC12
AC13  VCC  pwr
AC14  VCC  pwr
AC15  VCC  pwr
AC16  IOAC16
AC17  IOAC17
AC18  VCC  pwr
AC19  IOAC19
AC20  IOAC20
AC21  IOAC21
AC22  VCC  pwr
AC23  VCC  pwr
AC24  GND  pwr
AC25  IOAC25
AC26  IOAC26
AC27  GND  pwr
AC28  IOAC28
AD1  IOAD1
AD2  GND  pwr
AD3  VCC  pwr
AD4  NCSO  in
AD5  GND  pwr
AD6  IOAD6
AD7  IOAD7
AD8  GND  pwr
AD9  IOAD9
AD10  VCC  pwr
AD11  GND  pwr
AD12  IOAD12
AD13  IOAD13
AD14  GND  pwr
AD15  VCC  pwr
AD16  IOAD16
AD17  GND  pwr
AD18  IOAD18
AD19  IOAD19
AD20  GND  pwr
AD21  IOAD21
AD22  IOAD22
AD23  GND  pwr
AD24  IOAD24
AD25  NSTATUS  in
AD26  VCC  pwr
AD27  IOAD27
AD28  IOAD28
AE1  IOAE1
AE2  IOAE2
AE3  NIO_PULLUP  in
AE4  IOAE4
AE5  IOAE5
AE6  IOAE6
AE7  IOAE7
AE8  IOAE8
AE9  IOAE9
AE10  IOAE10
AE11  IOAE11
AE12  IOAE12
AE13  IOAE13
AE14  IOAE14
AE15  IOAE15
AE16  IOAE16
AE17  IOAE17
AE18  IOAE18
AE19  IOAE19
AE20  IOAE20
AE21  IOAE21
AE22  IOAE22
AE23  IOAE23
AE24  IOAE24
AE25  NC5  pas
AE26  CONF_DONE  in
AE27  IOAE27
AE28  IOAE28
AF1  IOAF1
AF2  IOAF2
AF3  GND  pwr
AF4  VCC  pwr
AF5  IOAF5
AF6  IOAF6
AF7  VCC  pwr
AF8  IOAF8
AF9  IOAF9
AF10  IOAF10
AF11  IOAF11
AF12  IOAF12
AF13  VCC  pwr
AF14  IOAF14
AF15  IOAF15
AF16  IOAF16
AF17  IOAF17
AF18  VCC  pwr
AF19  IOAF19
AF20  IOAF20
AF21  IOAF21
AF22  VCC  pwr
AF23  IOAF23
AF24  IOAF24
AF25  VCC  pwr
AF26  IOAF26
AF27  GND  pwr
AF28  IOAF28
AG1  IOAG1
AG2  GND  pwr
AG3  IOAG3
AG4  IOAG4
AG5  GND  pwr
AG6  IOAG6
AG7  IOAG7
AG8  GND  pwr
AG9  IOAG9
AG10  IOAG10
AG11  GND  pwr
AG12  IOAG12
AG13  IOAG13
AG14  GND  pwr
AG15  IOAG15
AG16  IOAG16
AG17  GND  pwr
AG18  IOAG18
AG19  IOAG19
AG20  GND  pwr
AG21  IOAG21
AG22  IOAG22
AG23  GND  pwr
AG24  IOAG24
AG25  IOAG25
AG26  GND  pwr
AG27  IOAG27
AG28  IOAG28
AH2  IOAH2
AH3  IOAH3
AH4  IOAH4
AH5  IOAH5
AH6  IOAH6
AH7  IOAH7
AH8  IOAH8
AH9  IOAH9
AH10  IOAH10
AH11  IOAH11
AH12  IOAH12
AH13  IOAH13
AH14  IOAH14
AH15  IOAH15
AH16  IOAH16
AH17  IOAH17
AH18  IOAH18
AH19  IOAH19
AH20  IOAH20
AH21  IOAH21
AH22  IOAH22
AH23  IOAH23
AH24  IOAH24
AH25  IOAH25
AH26  IOAH26
AH27  IOAH27
B1  IOB1
B2  IOB2
B3  GND  pwr
B4  IOB4
B5  IOB5
B6  GND  pwr
B7  IOB7
B8  IOB8
B9  GND  pwr
B10  IOB10
B11  IOB11
B12  GND  pwr
B13  IOB13
B14  IOB14
B15  GND  pwr
B16  IOB16
B17  IOB17
B18  GND  pwr
B19  IOB19
B20  IOB20
B21  GND  pwr
B22  IOB22
B23  IOB23
B24  GND  pwr
B25  IOB25
B26  IOB26
B27  GND  pwr
B28  IOB28
C1  IOC1
C2  GND  pwr
C3  IOC3
C4  VCC  pwr
C5  IOC5
C6  IOC6
C7  VCC  pwr
C8  IOC8
C9  IOC9
C10  IOC10
C11  VCC  pwr
C12  IOC12
C13  IOC13
C14  IOC14
C15  IOC15
C16  VCC  pwr
C17  IOC17
C18  IOC18
C19  IOC19
C20  IOC20
C21  IOC21
C22  VCC  pwr
C23  IOC23
C24  IOC24
C25  VCC  pwr
C26  TCK  in
C27  IOC27
C28  IOC28
D1  IOD1
D2  IOD2
D3  TEMPDIODEP  in
D4  TEMPDIODEN  in
D5  IOD5
D6  IOD6
D7  IOD7
D8  IOD8
D9  IOD9
D10  IOD10
D11  IOD11
D12  IOD12
D13  IOD13
D14  IOD14
D15  IOD15
D16  IOD16
D17  IOD17
D18  IOD18
D19  IOD19
D20  IOD20
D21  IOD21
D22  IOD22
D23  IOD23
D24  IOD24
D25  IOD25
D26  TRST  in
D27  IOD27
D28  IOD28
E1  IOE1
E2  IOE2
E3  VCC  pwr
E4  NC4  pas
E5  IOE5
E6  GND  pwr
E7  IOE7
E8  IOE8
E9  GND  pwr
E10  IOE10
E11  IOE11
E12  GND  pwr
E13  IOE13
E14  VCC  pwr
E15  GND  pwr
E16  IOE16
E17  IOE17
E18  GND  pwr
E19  VCC  pwr
E20  IOE20
E21  GND  pwr
E22  IOE22
E23  IOE23
E24  GND  pwr
E25  NC1  pas
E26  VCC  pwr
E27  GND  pwr
E28  IOE28
F1  IOF1
F2  GND  pwr
F3  IOF3
F4  IOF4
F5  GND  pwr
F6  VCC  pwr
F7  VCC  pwr
F8  IOF8
F9  IOF9
F10  IOF10
F11  VCC  pwr
F12  IOF12
F13  IOF13
F14  VCC  pwr
F15  VCC  pwr
F16  VCC  pwr
F17  IOF17
F18  IOF18
F19  IOF19
F20  IOF20
F21  IOF21
F22  IOF22
F23  VCC  pwr
F24  TDI  in
F25  IOF25
F26  IOF26
F27  IOF27
F28  IOF28
G1  IOG1
G2  IOG2
G3  IOG3
G4  IOG4
G5  IOG5
G6  VCC  pwr
G7  MSEL2  in
G8  IOG8
G9  IOG9
G10  IOG10
G12  IOG12
G13  IOG13
G14  VCC  pwr
G15  VCC  pwr
G16  IOG16
G17  VCC  pwr
G18  IOG18
G20  IOG20
G21  IOG21
G22  IOG22
G23  VCC  pwr
G24  TDO  out
G25  IOG25
G26  IOG26
G27  IOG27
G28  IOG28
H1  IOH1
H2  IOH2
H3  IOH3
H4  IOH4
H5  IOH5
H6  IOH6
H7  VCC  pwr
H8  MSEL0  in
H9  GND  pwr
H10  IOH10
H11  IOH11
H12  GND  pwr
H14  IOH14
H15  GND  pwr
H16  IOH16
H18  GND  pwr
H19  IOH19
H20  IOH20
H21  GND  pwr
H22  TMS  in
H23  VCC  pwr
H24  GND  pwr
H25  IOH25
H26  VCC  pwr
H27  GND  pwr
H28  IOH28
J1  IOJ1
J2  GND  pwr
J3  IOJ3
J4  IOJ4
J5  GND  pwr
J6  IOJ6
J8  GND  pwr
J9  MSEL1  in
J10  IOJ10
J11  IOJ11
J12  IOJ12
J13  GND  pwr
J14  IOJ14
J15  IOJ15
J16  IOJ16
J17  GND  pwr
J18  IOJ18
J19  IOJ19
J20  IOJ20
J21  NC9  pas
J22  IOJ22
J23  IOJ23
J24  IOJ24
J25  IOJ25
J26  IOJ26
J27  IOJ27
J28  IOJ28
K1  IOK1
K2  IOK2
K3  VCC  pwr
K4  IOK4
K5  IOK5
K6  IOK6
K7  IOK7
K8  IOK8
K9  IOK9
K10  NC8  pas
K11  GND  pwr
K12  VCC  pwr
K13  GND  pwr
K14  VCC  pwr
K15  GND  pwr
K16  VCC  pwr
K17  GND  pwr
K18  VCC  pwr
K19  GND  pwr
K20  IOK20
K21  IOK21
K23  IOK23
K24  IOK24
K25  IOK25
K26  IOK26
K27  IOK27
K28  IOK28
L1  IOL1
L2  IOL2
L3  IOL3
L4  IOL4
L5  IOL5
L6  IOL6
L7  VCC  pwr
L8  IOL8
L9  IOL9
L10  GND  pwr
L11  VCC  pwr
L12  GND  pwr
L13  VCC  pwr
L14  GND  pwr
L15  VCC  pwr
L16  GND  pwr
L17  VCC  pwr
L18  GND  pwr
L19  VCC  pwr
L20  NC7  pas
L21  GND  pwr
L22  IOL22
L23  IOL23
L24  GND  pwr
L25  IOL25
L26  IOL26
L27  GND  pwr
L28  IOL28
M1  IOM1
M2  GND  pwr
M3  IOM3
M4  IOM4
M5  GND  pwr
M6  IOM6
M8  GND  pwr
M9  VCC  pwr
M10  VCC  pwr
M11  GND  pwr
M12  VCC  pwr
M13  GND  pwr
M14  VCC  pwr
M15  GND  pwr
M16  VCC  pwr
M17  GND  pwr
M18  VCC  pwr
M19  GND  pwr
M20  IOM20
M21  IOM21
M22  IOM22
M23  IOM23
M24  IOM24
M25  IOM25
M26  IOM26
M27  IOM27
M28  IOM28
N1  ION1
N2  ION2
N3  VCC  pwr
N4  ION4
N5  ION5
N6  ION6
N7  ION7
N8  ION8
N9  ION9
N10  GND  pwr
N11  VCC  pwr
N12  GND  pwr
N13  VCC  pwr
N14  GND  pwr
N15  VCC  pwr
N16  GND  pwr
N17  VCC  pwr
N18  GND  pwr
N19  VCC  pwr
N20  ION20
N21  ION21
N23  ION23
N24  ION24
N25  ION25
N26  ION26
N27  ION27
N28  CLK1N  in
P1  CLK10N  in
P2  CLK10P  in
P3  IOP3
P4  IOP4
P5  VCC  pwr
P6  VCC  pwr
P7  VCC  pwr
P8  IOP8
P9  IOP9
P10  VCC  pwr
P11  GND  pwr
P12  VCC  pwr
P13  GND  pwr
P14  VCC  pwr
P15  DNU  pas
P16  VCC  pwr
P17  GND  pwr
P18  VCC  pwr
P19  IOP19
P20  IOP20
P21  GND  pwr
P22  VCC  pwr
P23  IOP23
P24  GND  pwr
P25  IOP25
P26  VCC  pwr
P27  GND  pwr
P28  CLK1P  in
R1  CLK8P  in
R2  GND  pwr
R3  VCC  pwr
R4  IOR4
R5  GND  pwr
R6  IOR6
R7  VCC  pwr
R8  GND  pwr
R9  IOR9
R10  IOR10
R11  VCC  pwr
R12  GND  pwr
R13  VCC  pwr
R14  GND  pwr
R15  VCC  pwr
R16  GND  pwr
R17  VCC  pwr
R18  GND  pwr
R19  VCC  pwr
R20  IOR20
R21  IOR21
R22  VCC  pwr
R23  VCC  pwr
R24  VCC  pwr
R25  IOR25
R26  IOR26
R27  CLK3P  in
R28  CLK3N  in
T1  CLK8N  in
T2  IOT2
T3  IOT3
T4  IOT4
T5  IOT5
T6  IOT6
T8  IOT8
T9  IOT9
T10  VCC  pwr
T11  GND  pwr
T12  VCC  pwr
T13  GND  pwr
T14  VCC  pwr
T15  GND  pwr
T16  VCC  pwr
T17  GND  pwr
T18  VCC  pwr
T19  GND  pwr
T20  IOT20
T21  IOT21
T22  IOT22
T23  IOT23
T24  IOT24
T25  IOT25
T26  VCC  pwr
T27  IOT27
T28  IOT28
U1  IOU1
U2  IOU2
U3  IOU3
U4  IOU4
U5  IOU5
U6  IOU6
U7  IOU7
U8  IOU8
U9  IOU9
U10  GND  pwr
U11  VCC  pwr
U12  GND  pwr
U13  VCC  pwr
U14  GND  pwr
U15  VCC  pwr
U16  GND  pwr
U17  VCC  pwr
U18  GND  pwr
U19  VCC  pwr
U20  VCC  pwr
U21  GND  pwr
U23  IOU23
U24  GND  pwr
U25  IOU25
U26  IOU26
U27  GND  pwr
U28  IOU28
V1  IOV1
V2  GND  pwr
V3  IOV3
V4  IOV4
V5  GND  pwr
V6  IOV6
V7  IOV7
V8  GND  pwr
V9  NC6  pas
V10  VCC  pwr
V11  GND  pwr
V12  VCC  pwr
V13  GND  pwr
V14  VCC  pwr
V15  GND  pwr
V16  VCC  pwr
V17  GND  pwr
V18  VCC  pwr
V19  GND  pwr
V20  IOV20
V21  IOV21
V22  VCC  pwr
V23  IOV23
V24  IOV24
V25  IOV25
V26  IOV26
V27  IOV27
V28  IOV28
W1  IOW1
W2  IOW2
W3  IOW3
W4  IOW4
W5  IOW5
W6  IOW6
W8  IOW8
W9  IOW9
W10  NC3  pas
W11  VCC  pwr
W12  GND  pwr
W13  VCC  pwr
W14  GND  pwr
W15  VCC  pwr
W16  GND  pwr
W17  VCC  pwr
W18  GND  pwr
W19  NCONFIG  in
W20  IOW20
W21  IOW21
W22  IOW22
W23  IOW23
W24  IOW24
W25  IOW25
W26  VCC  pwr
W27  IOW27
W28  IOW28
Y1  IOY1
Y2  IOY2
Y3  IOY3
Y4  IOY4
Y5  IOY5
Y6  IOY6
Y7  IOY7
Y8  VCC  pwr
Y9  IOY9
Y10  IOY10
Y11  IOY11
Y12  GND  pwr
Y13  IOY13
Y14  IOY14
Y15  IOY15
Y16  GND  pwr
Y17  IOY17
Y18  IOY18
Y19  IOY19
Y20  NCE  in
Y21  GND  pwr
Y23  IOY23
Y24  GND  pwr
Y25  IOY25
Y26  IOY26
Y27  GND  pwr
Y28  IOY28

## Footprint FBGA780 (pad centres in mm)
780-Pin Hybrid FineLine Ball-Grid Array (HBGA) ? Flip Chip Auto generated by make-symbol-device-package-bsdl.ulp Rev. 29 Source: EP4SE230F29.bsd http://www.altera.com .. dspkg.pdf
smd 0.7 x 0.7: A2 -12.5,13.5; A3 -11.5,13.5; A4 -10.5,13.5; A5 -9.5,13.5; A6 -8.5,13.5; A7 -7.5,13.5; A8 -6.5,13.5; A9 -5.5,13.5; A10 -4.5,13.5; A11 -3.5,13.5; A12 -2.5,13.5; A13 -1.5,13.5; A14 -0.5,13.5; A15 0.5,13.5; A16 1.5,13.5; A17 2.5,13.5; A18 3.5,13.5; A19 4.5,13.5; A20 5.5,13.5; A21 6.5,13.5; A22 7.5,13.5; A23 8.5,13.5; A24 9.5,13.5; A25 10.5,13.5; A26 11.5,13.5; A27 12.5,13.5; AA1 -13.5,-6.5; AA2 -12.5,-6.5; AA3 -11.5,-6.5; AA4 -10.5,-6.5; AA5 -9.5,-6.5; AA6 -8.5,-6.5; AA7 -7.5,-6.5; AA8 -6.5,-6.5; AA9 -5.5,-6.5; AA10 -4.5,-6.5; AA11 -3.5,-6.5; AA12 -2.5,-6.5; AA13 -1.5,-6.5; AA14 -0.5,-6.5; AA15 0.5,-6.5; AA16 1.5,-6.5; AA17 2.5,-6.5; AA18 3.5,-6.5; AA19 4.5,-6.5; AA20 5.5,-6.5; AA21 6.5,-6.5; AA22 7.5,-6.5; AA23 8.5,-6.5; AA24 9.5,-6.5; AA25 10.5,-6.5; AA26 11.5,-6.5; AA27 12.5,-6.5; AA28 13.5,-6.5; AB1 -13.5,-7.5; AB2 -12.5,-7.5; AB3 -11.5,-7.5; AB4 -10.5,-7.5; AB5 -9.5,-7.5; AB6 -8.5,-7.5; AB7 -7.5,-7.5; AB8 -6.5,-7.5; AB9 -5.5,-7.5; AB10 -4.5,-7.5; AB11 -3.5,-7.5; AB12 -2.5,-7.5; AB13 -1.5,-7.5; AB14 -0.5,-7.5; AB15 0.5,-7.5; AB16 1.5,-7.5; AB17 2.5,-7.5; AB18 3.5,-7.5; AB19 4.5,-7.5; AB20 5.5,-7.5; AB21 6.5,-7.5; AB22 7.5,-7.5; AB23 8.5,-7.5; AB24 9.5,-7.5; AB25 10.5,-7.5; AB26 11.5,-7.5; AB27 12.5,-7.5; AB28 13.5,-7.5; AC1 -13.5,-8.5; AC2 -12.5,-8.5; AC3 -11.5,-8.5; AC4 -10.5,-8.5; AC5 -9.5,-8.5; AC6 -8.5,-8.5; AC7 -7.5,-8.5; AC8 -6.5,-8.5; AC9 -5.5,-8.5; AC10 -4.5,-8.5; AC11 -3.5,-8.5; AC12 -2.5,-8.5; AC13 -1.5,-8.5; AC14 -0.5,-8.5; AC15 0.5,-8.5; AC16 1.5,-8.5; AC17 2.5,-8.5; AC18 3.5,-8.5; AC19 4.5,-8.5; AC20 5.5,-8.5; AC21 6.5,-8.5; AC22 7.5,-8.5; AC23 8.5,-8.5; AC24 9.5,-8.5; AC25 10.5,-8.5; AC26 11.5,-8.5; AC27 12.5,-8.5; AC28 13.5,-8.5; AD1 -13.5,-9.5; AD2 -12.5,-9.5; AD3 -11.5,-9.5; AD4 -10.5,-9.5; AD5 -9.5,-9.5; AD6 -8.5,-9.5; AD7 -7.5,-9.5; AD8 -6.5,-9.5; AD9 -5.5,-9.5; AD10 -4.5,-9.5; AD11 -3.5,-9.5; AD12 -2.5,-9.5; AD13 -1.5,-9.5; AD14 -0.5,-9.5; AD15 0.5,-9.5; AD16 1.5,-9.5; AD17 2.5,-9.5; AD18 3.5,-9.5; AD19 4.5,-9.5; AD20 5.5,-9.5; AD21 6.5,-9.5; AD22 7.5,-9.5; AD23 8.5,-9.5; AD24 9.5,-9.5; AD25 10.5,-9.5; AD26 11.5,-9.5; AD27 12.5,-9.5; AD28 13.5,-9.5; AE1 -13.5,-10.5; AE2 -12.5,-10.5; AE3 -11.5,-10.5; AE4 -10.5,-10.5; AE5 -9.5,-10.5; AE6 -8.5,-10.5; AE7 -7.5,-10.5; AE8 -6.5,-10.5; AE9 -5.5,-10.5; AE10 -4.5,-10.5; AE11 -3.5,-10.5; AE12 -2.5,-10.5; AE13 -1.5,-10.5; AE14 -0.5,-10.5; AE15 0.5,-10.5; AE16 1.5,-10.5; AE17 2.5,-10.5; AE18 3.5,-10.5; AE19 4.5,-10.5; AE20 5.5,-10.5; AE21 6.5,-10.5; AE22 7.5,-10.5; AE23 8.5,-10.5; AE24 9.5,-10.5; AE25 10.5,-10.5; AE26 11.5,-10.5; AE27 12.5,-10.5; AE28 13.5,-10.5; AF1 -13.5,-11.5; AF2 -12.5,-11.5; AF3 -11.5,-11.5; AF4 -10.5,-11.5; AF5 -9.5,-11.5; AF6 -8.5,-11.5; AF7 -7.5,-11.5; AF8 -6.5,-11.5; AF9 -5.5,-11.5; AF10 -4.5,-11.5; AF11 -3.5,-11.5; AF12 -2.5,-11.5; AF13 -1.5,-11.5; AF14 -0.5,-11.5; AF15 0.5,-11.5; AF16 1.5,-11.5; AF17 2.5,-11.5; AF18 3.5,-11.5; AF19 4.5,-11.5; AF20 5.5,-11.5; AF21 6.5,-11.5; AF22 7.5,-11.5; AF23 8.5,-11.5; AF24 9.5,-11.5; AF25 10.5,-11.5; AF26 11.5,-11.5; AF27 12.5,-11.5; AF28 13.5,-11.5; AG1 -13.5,-12.5; AG2 -12.5,-12.5; AG3 -11.5,-12.5; AG4 -10.5,-12.5; AG5 -9.5,-12.5; AG6 -8.5,-12.5; AG7 -7.5,-12.5; AG8 -6.5,-12.5; AG9 -5.5,-12.5; AG10 -4.5,-12.5; AG11 -3.5,-12.5; AG12 -2.5,-12.5; AG13 -1.5,-12.5; AG14 -0.5,-12.5; AG15 0.5,-12.5; AG16 1.5,-12.5; AG17 2.5,-12.5; AG18 3.5,-12.5; AG19 4.5,-12.5; AG20 5.5,-12.5; AG21 6.5,-12.5; AG22 7.5,-12.5; AG23 8.5,-12.5; AG24 9.5,-12.5; AG25 10.5,-12.5; AG26 11.5,-12.5; AG27 12.5,-12.5; AG28 13.5,-12.5; AH2 -12.5,-13.5; AH3 -11.5,-13.5; AH4 -10.5,-13.5; AH5 -9.5,-13.5; AH6 -8.5,-13.5; AH7 -7.5,-13.5; AH8 -6.5,-13.5; AH9 -5.5,-13.5; AH10 -4.5,-13.5; AH11 -3.5,-13.5; AH12 -2.5,-13.5; AH13 -1.5,-13.5; AH14 -0.5,-13.5; AH15 0.5,-13.5; AH16 1.5,-13.5; AH17 2.5,-13.5; AH18 3.5,-13.5; AH19 4.5,-13.5; AH20 5.5,-13.5; AH21 6.5,-13.5; AH22 7.5,-13.5; AH23 8.5,-13.5; AH24 9.5,-13.5; AH25 10.5,-13.5; AH26 11.5,-13.5; AH27 12.5,-13.5; B1 -13.5,12.5; B2 -12.5,12.5; B3 -11.5,12.5; B4 -10.5,12.5; B5 -9.5,12.5; B6 -8.5,12.5; B7 -7.5,12.5; B8 -6.5,12.5; B9 -5.5,12.5; B10 -4.5,12.5; B11 -3.5,12.5; B12 -2.5,12.5; B13 -1.5,12.5; B14 -0.5,12.5; B15 0.5,12.5; B16 1.5,12.5; B17 2.5,12.5; B18 3.5,12.5; B19 4.5,12.5; B20 5.5,12.5; B21 6.5,12.5; B22 7.5,12.5; B23 8.5,12.5; B24 9.5,12.5; B25 10.5,12.5; B26 11.5,12.5; B27 12.5,12.5; B28 13.5,12.5; C1 -13.5,11.5; C2 -12.5,11.5; C3 -11.5,11.5; C4 -10.5,11.5; C5 -9.5,11.5; C6 -8.5,11.5; C7 -7.5,11.5; C8 -6.5,11.5; C9 -5.5,11.5; C10 -4.5,11.5; C11 -3.5,11.5; C12 -2.5,11.5; C13 -1.5,11.5; C14 -0.5,11.5; C15 0.5,11.5; C16 1.5,11.5; C17 2.5,11.5; C18 3.5,11.5; C19 4.5,11.5; C20 5.5,11.5; C21 6.5,11.5; C22 7.5,11.5; C23 8.5,11.5; C24 9.5,11.5; C25 10.5,11.5; C26 11.5,11.5; C27 12.5,11.5; C28 13.5,11.5; D1 -13.5,10.5; D2 -12.5,10.5; D3 -11.5,10.5; D4 -10.5,10.5; D5 -9.5,10.5; D6 -8.5,10.5; D7 -7.5,10.5; D8 -6.5,10.5; D9 -5.5,10.5; D10 -4.5,10.5; D11 -3.5,10.5; D12 -2.5,10.5; D13 -1.5,10.5; D14 -0.5,10.5; D15 0.5,10.5; D16 1.5,10.5; D17 2.5,10.5; D18 3.5,10.5; D19 4.5,10.5; D20 5.5,10.5; D21 6.5,10.5; D22 7.5,10.5; D23 8.5,10.5; D24 9.5,10.5; D25 10.5,10.5; D26 11.5,10.5; D27 12.5,10.5; D28 13.5,10.5; E1 -13.5,9.5; E2 -12.5,9.5; E3 -11.5,9.5; E4 -10.5,9.5; E5 -9.5,9.5; E6 -8.5,9.5; E7 -7.5,9.5; E8 -6.5,9.5; E9 -5.5,9.5; E10 -4.5,9.5; E11 -3.5,9.5; E12 -2.5,9.5; E13 -1.5,9.5; E14 -0.5,9.5; E15 0.5,9.5; E16 1.5,9.5; E17 2.5,9.5; E18 3.5,9.5; E19 4.5,9.5; E20 5.5,9.5; E21 6.5,9.5; E22 7.5,9.5; E23 8.5,9.5; E24 9.5,9.5; E25 10.5,9.5; E26 11.5,9.5; E27 12.5,9.5; E28 13.5,9.5; F1 -13.5,8.5; F2 -12.5,8.5; F3 -11.5,8.5; F4 -10.5,8.5; F5 -9.5,8.5; F6 -8.5,8.5; F7 -7.5,8.5; F8 -6.5,8.5; F9 -5.5,8.5; F10 -4.5,8.5; F11 -3.5,8.5; F12 -2.5,8.5; F13 -1.5,8.5; F14 -0.5,8.5; F15 0.5,8.5; F16 1.5,8.5; F17 2.5,8.5; F18 3.5,8.5; F19 4.5,8.5; F20 5.5,8.5; F21 6.5,8.5; F22 7.5,8.5; F23 8.5,8.5; F24 9.5,8.5; F25 10.5,8.5; F26 11.5,8.5; F27 12.5,8.5; F28 13.5,8.5; G1 -13.5,7.5; G2 -12.5,7.5; G3 -11.5,7.5; G4 -10.5,7.5; G5 -9.5,7.5; G6 -8.5,7.5; G7 -7.5,7.5; G8 -6.5,7.5; G9 -5.5,7.5; G10 -4.5,7.5; G11 -3.5,7.5; G12 -2.5,7.5; G13 -1.5,7.5; G14 -0.5,7.5; G15 0.5,7.5; G16 1.5,7.5; G17 2.5,7.5; G18 3.5,7.5; G19 4.5,7.5; G20 5.5,7.5; G21 6.5,7.5; G22 7.5,7.5; G23 8.5,7.5; G24 9.5,7.5; G25 10.5,7.5; G26 11.5,7.5; G27 12.5,7.5; G28 13.5,7.5; H1 -13.5,6.5; H2 -12.5,6.5; H3 -11.5,6.5; H4 -10.5,6.5; H5 -9.5,6.5; H6 -8.5,6.5; H7 -7.5,6.5; H8 -6.5,6.5; H9 -5.5,6.5; H10 -4.5,6.5; H11 -3.5,6.5; H12 -2.5,6.5; H13 -1.5,6.5; H14 -0.5,6.5; H15 0.5,6.5; H16 1.5,6.5; H17 2.5,6.5; H18 3.5,6.5; H19 4.5,6.5; H20 5.5,6.5; H21 6.5,6.5; H22 7.5,6.5; H23 8.5,6.5; H24 9.5,6.5; H25 10.5,6.5; H26 11.5,6.5; H27 12.5,6.5; H28 13.5,6.5; J1 -13.5,5.5; J2 -12.5,5.5; J3 -11.5,5.5; J4 -10.5,5.5; J5 -9.5,5.5; J6 -8.5,5.5; J7 -7.5,5.5; J8 -6.5,5.5; J9 -5.5,5.5; J10 -4.5,5.5; J11 -3.5,5.5; J12 -2.5,5.5; J13 -1.5,5.5; J14 -0.5,5.5; J15 0.5,5.5; J16 1.5,5.5; J17 2.5,5.5; J18 3.5,5.5; J19 4.5,5.5; J20 5.5,5.5; J21 6.5,5.5; J22 7.5,5.5; J23 8.5,5.5; J24 9.5,5.5; J25 10.5,5.5; J26 11.5,5.5; J27 12.5,5.5; J28 13.5,5.5; K1 -13.5,4.5; K2 -12.5,4.5; K3 -11.5,4.5; K4 -10.5,4.5; K5 -9.5,4.5; K6 -8.5,4.5; K7 -7.5,4.5; K8 -6.5,4.5; K9 -5.5,4.5; K10 -4.5,4.5; K11 -3.5,4.5; K12 -2.5,4.5; K13 -1.5,4.5; K14 -0.5,4.5; K15 0.5,4.5; K16 1.5,4.5; K17 2.5,4.5; K18 3.5,4.5; K19 4.5,4.5; K20 5.5,4.5; K21 6.5,4.5; K22 7.5,4.5; K23 8.5,4.5; K24 9.5,4.5; K25 10.5,4.5; K26 11.5,4.5; K27 12.5,4.5; K28 13.5,4.5; L1 -13.5,3.5; L2 -12.5,3.5; L3 -11.5,3.5; L4 -10.5,3.5; L5 -9.5,3.5; L6 -8.5,3.5; L7 -7.5,3.5; L8 -6.5,3.5; L9 -5.5,3.5; L10 -4.5,3.5; L11 -3.5,3.5; L12 -2.5,3.5; L13 -1.5,3.5; L14 -0.5,3.5; L15 0.5,3.5; L16 1.5,3.5; L17 2.5,3.5; L18 3.5,3.5; L19 4.5,3.5; L20 5.5,3.5; L21 6.5,3.5; L22 7.5,3.5; L23 8.5,3.5; L24 9.5,3.5; L25 10.5,3.5; L26 11.5,3.5; L27 12.5,3.5; L28 13.5,3.5; M1 -13.5,2.5; M2 -12.5,2.5; M3 -11.5,2.5; M4 -10.5,2.5; M5 -9.5,2.5; M6 -8.5,2.5; M7 -7.5,2.5; M8 -6.5,2.5; M9 -5.5,2.5; M10 -4.5,2.5; M11 -3.5,2.5; M12 -2.5,2.5; M13 -1.5,2.5; M14 -0.5,2.5; M15 0.5,2.5; M16 1.5,2.5; M17 2.5,2.5; M18 3.5,2.5; M19 4.5,2.5; M20 5.5,2.5; M21 6.5,2.5; M22 7.5,2.5; M23 8.5,2.5; M24 9.5,2.5; M25 10.5,2.5; M26 11.5,2.5; M27 12.5,2.5; M28 13.5,2.5; N1 -13.5,1.5; N2 -12.5,1.5; N3 -11.5,1.5; N4 -10.5,1.5; N5 -9.5,1.5; N6 -8.5,1.5; N7 -7.5,1.5; N8 -6.5,1.5; N9 -5.5,1.5; N10 -4.5,1.5; N11 -3.5,1.5; N12 -2.5,1.5; N13 -1.5,1.5; N14 -0.5,1.5; N15 0.5,1.5; N16 1.5,1.5; N17 2.5,1.5; N18 3.5,1.5; N19 4.5,1.5; N20 5.5,1.5; N21 6.5,1.5; N22 7.5,1.5; N23 8.5,1.5; N24 9.5,1.5; N25 10.5,1.5; N26 11.5,1.5; N27 12.5,1.5; N28 13.5,1.5; P1 -13.5,0.5; P2 -12.5,0.5; P3 -11.5,0.5; P4 -10.5,0.5; P5 -9.5,0.5; P6 -8.5,0.5; P7 -7.5,0.5; P8 -6.5,0.5; P9 -5.5,0.5; P10 -4.5,0.5; P11 -3.5,0.5; P12 -2.5,0.5; P13 -1.5,0.5; P14 -0.5,0.5; P15 0.5,0.5; P16 1.5,0.5; P17 2.5,0.5; P18 3.5,0.5; P19 4.5,0.5; P20 5.5,0.5; P21 6.5,0.5; P22 7.5,0.5; P23 8.5,0.5; P24 9.5,0.5; P25 10.5,0.5; P26 11.5,0.5; P27 12.5,0.5; P28 13.5,0.5; R1 -13.5,-0.5; R2 -12.5,-0.5; R3 -11.5,-0.5; R4 -10.5,-0.5; R5 -9.5,-0.5; R6 -8.5,-0.5; R7 -7.5,-0.5; R8 -6.5,-0.5; R9 -5.5,-0.5; R10 -4.5,-0.5; R11 -3.5,-0.5; R12 -2.5,-0.5; R13 -1.5,-0.5; R14 -0.5,-0.5; R15 0.5,-0.5; R16 1.5,-0.5; R17 2.5,-0.5; R18 3.5,-0.5; R19 4.5,-0.5; R20 5.5,-0.5; R21 6.5,-0.5; R22 7.5,-0.5; R23 8.5,-0.5; R24 9.5,-0.5; R25 10.5,-0.5; R26 11.5,-0.5; R27 12.5,-0.5; R28 13.5,-0.5; T1 -13.5,-1.5; T2 -12.5,-1.5; T3 -11.5,-1.5; T4 -10.5,-1.5; T5 -9.5,-1.5; T6 -8.5,-1.5; T7 -7.5,-1.5; T8 -6.5,-1.5; T9 -5.5,-1.5; T10 -4.5,-1.5; T11 -3.5,-1.5; T12 -2.5,-1.5; T13 -1.5,-1.5; T14 -0.5,-1.5; T15 0.5,-1.5; T16 1.5,-1.5; T17 2.5,-1.5; T18 3.5,-1.5; T19 4.5,-1.5; T20 5.5,-1.5; T21 6.5,-1.5; T22 7.5,-1.5; T23 8.5,-1.5; T24 9.5,-1.5; T25 10.5,-1.5; T26 11.5,-1.5; T27 12.5,-1.5; T28 13.5,-1.5; U1 -13.5,-2.5; U2 -12.5,-2.5; U3 -11.5,-2.5; U4 -10.5,-2.5; U5 -9.5,-2.5; U6 -8.5,-2.5; U7 -7.5,-2.5; U8 -6.5,-2.5; U9 -5.5,-2.5; U10 -4.5,-2.5; U11 -3.5,-2.5; U12 -2.5,-2.5; U13 -1.5,-2.5; U14 -0.5,-2.5; U15 0.5,-2.5; U16 1.5,-2.5; U17 2.5,-2.5; U18 3.5,-2.5; U19 4.5,-2.5; U20 5.5,-2.5; U21 6.5,-2.5; U22 7.5,-2.5; U23 8.5,-2.5; U24 9.5,-2.5; U25 10.5,-2.5; U26 11.5,-2.5; U27 12.5,-2.5; U28 13.5,-2.5; V1 -13.5,-3.5; V2 -12.5,-3.5; V3 -11.5,-3.5; V4 -10.5,-3.5; V5 -9.5,-3.5; V6 -8.5,-3.5; V7 -7.5,-3.5; V8 -6.5,-3.5; V9 -5.5,-3.5; V10 -4.5,-3.5; V11 -3.5,-3.5; V12 -2.5,-3.5; V13 -1.5,-3.5; V14 -0.5,-3.5; V15 0.5,-3.5; V16 1.5,-3.5; V17 2.5,-3.5; V18 3.5,-3.5; V19 4.5,-3.5; V20 5.5,-3.5; V21 6.5,-3.5; V22 7.5,-3.5; V23 8.5,-3.5; V24 9.5,-3.5; V25 10.5,-3.5; V26 11.5,-3.5; V27 12.5,-3.5; V28 13.5,-3.5; W1 -13.5,-4.5; W2 -12.5,-4.5; W3 -11.5,-4.5; W4 -10.5,-4.5; W5 -9.5,-4.5; W6 -8.5,-4.5; W7 -7.5,-4.5; W8 -6.5,-4.5; W9 -5.5,-4.5; W10 -4.5,-4.5; W11 -3.5,-4.5; W12 -2.5,-4.5; W13 -1.5,-4.5; W14 -0.5,-4.5; W15 0.5,-4.5; W16 1.5,-4.5; W17 2.5,-4.5; W18 3.5,-4.5; W19 4.5,-4.5; W20 5.5,-4.5; W21 6.5,-4.5; W22 7.5,-4.5; W23 8.5,-4.5; W24 9.5,-4.5; W25 10.5,-4.5; W26 11.5,-4.5; W27 12.5,-4.5; W28 13.5,-4.5; Y1 -13.5,-5.5; Y2 -12.5,-5.5; Y3 -11.5,-5.5; Y4 -10.5,-5.5; Y5 -9.5,-5.5; Y6 -8.5,-5.5; Y7 -7.5,-5.5; Y8 -6.5,-5.5; Y9 -5.5,-5.5; Y10 -4.5,-5.5; Y11 -3.5,-5.5; Y12 -2.5,-5.5; Y13 -1.5,-5.5; Y14 -0.5,-5.5; Y15 0.5,-5.5; Y16 1.5,-5.5; Y17 2.5,-5.5; Y18 3.5,-5.5; Y19 4.5,-5.5; Y20 5.5,-5.5; Y21 6.5,-5.5; Y22 7.5,-5.5; Y23 8.5,-5.5; Y24 9.5,-5.5; Y25 10.5,-5.5; Y26 11.5,-5.5; Y27 12.5,-5.5; Y28 13.5,-5.5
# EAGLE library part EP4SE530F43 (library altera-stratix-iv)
EP4SE530F43 Auto generated by make-symbol-device-package-bsdl.ulp Rev. 29 Source: EP4SE530F43.bsd

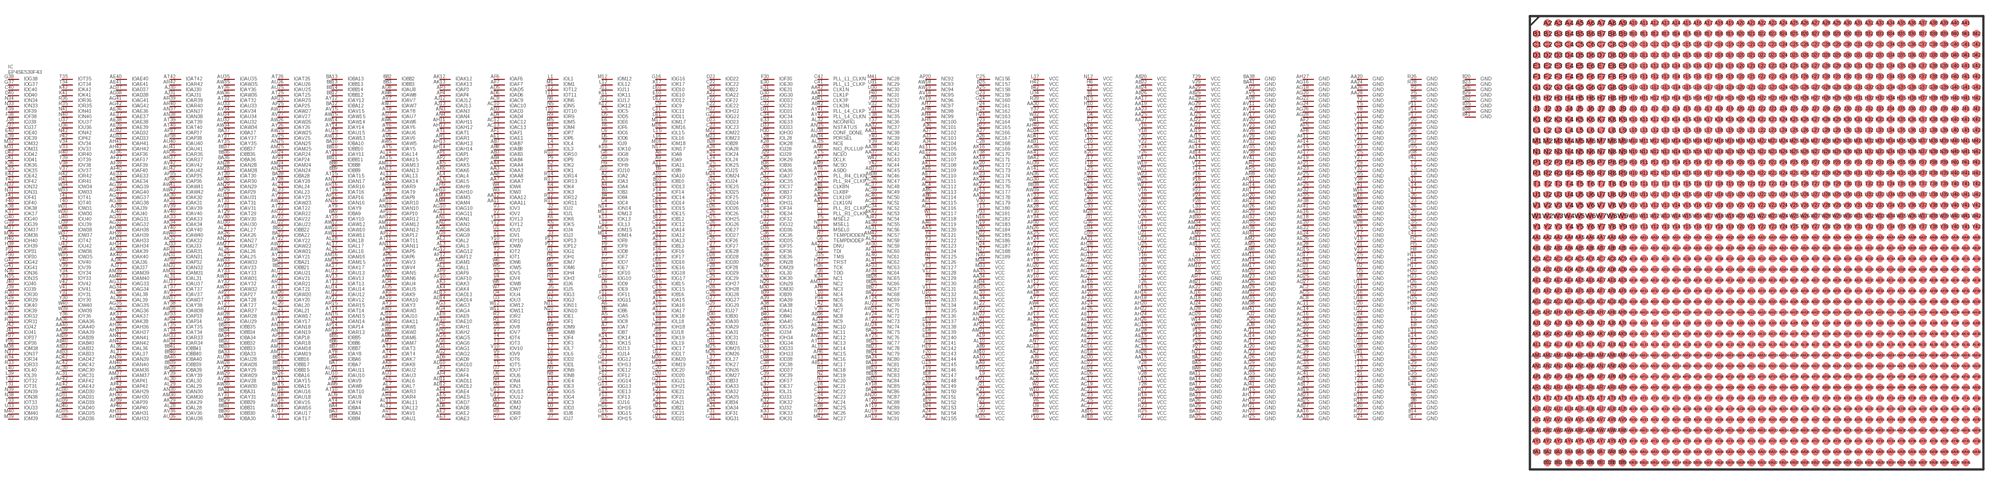
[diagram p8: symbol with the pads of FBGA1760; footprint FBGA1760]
Designator prefix IC

## EP4SE530F43 (MPN: EP4SE530F43C2; OC_FARNELL: unknown; OC_NEWARK: 52R1701)  [FBGA1760]
A2  IOA2
A3  IOA3
A4  IOA4
A5  IOA5
A6  IOA6
A7  IOA7
A8  IOA8
A9  IOA9
A10  IOA10
A11  IOA11
A12  IOA12
A13  IOA13
A14  IOA14
A15  IOA15
A16  IOA16
A17  IOA17
A18  NC150  pas
A19  NC151  pas
A20  NC149  pas
A21  IOA21
A22  IOA22
A23  NC155  pas
A24  NC154  pas
A25  NC158  pas
A26  NC167  pas
A27  NC166  pas
A28  IOA28
A29  IOA29
A30  IOA30
A31  IOA31
A32  IOA32
A33  IOA33
A34  IOA34
A35  IOA35
A36  IOA36
A37  IOA37
A38  IOA38
A39  IOA39
A40  IOA40
A41  IOA41
AA1  CLK10N  in
AA2  CLK10P  in
AA3  IOAA3
AA4  IOAA4
AA5  NC120  pas
AA6  NC119  pas
AA7  IOAA7
AA8  IOAA8
AA9  VCC  pwr
AA10  VCC  pwr
AA11  IOAA11
AA12  IOAA12
AA13  NC178  pas
AA14  VCC  pwr
AA15  VCC  pwr
AA16  GND  pwr
AA17  VCC  pwr
AA18  GND  pwr
AA19  VCC  pwr
AA20  GND  pwr
AA21  VCC  pwr
AA22  DNU  pas
AA23  VCC  pwr
AA24  GND  pwr
AA25  VCC  pwr
AA26  GND  pwr
AA27  VCC  pwr
AA28  GND  pwr
AA29  VCC  pwr
AA30  VCC  pwr
AA31  NC38  pas
AA32  NC37  pas
AA33  VCC  pwr
AA34  VCC  pwr
AA35  VCC  pwr
AA36  IOAA36
AA37  NC42  pas
AA38  NC41  pas
AA39  IOAA39
AA40  IOAA40
AA41  CLK1P  in
AA42  CLK1N  in
AB1  CLK8N  in
AB2  CLK8P  in
AB3  IOAB3
AB4  IOAB4
AB5  NC113  pas
AB6  NC114  pas
AB7  IOAB7
AB8  IOAB8
AB9  VCC  pwr
AB10  VCC  pwr
AB11  VCC  pwr
AB12  NC17  pas
AB13  VCC  pwr
AB14  VCC  pwr
AB15  GND  pwr
AB16  VCC  pwr
AB17  GND  pwr
AB18  VCC  pwr
AB19  GND  pwr
AB20  VCC  pwr
AB21  GND  pwr
AB22  VCC  pwr
AB23  GND  pwr
AB24  VCC  pwr
AB25  GND  pwr
AB26  VCC  pwr
AB27  GND  pwr
AB28  VCC  pwr
AB29  VCC  pwr
AB30  VCC  pwr
AB31  VCC  pwr
AB32  IOAB32
AB33  IOAB33
AB34  VCC  pwr
AB35  VCC  pwr
AB36  NC8  pas
AB37  NC45  pas
AB38  NC46  pas
AB39  IOAB39
AB40  IOAB40
AB41  CLK3P  in
AB42  CLK3N  in
AC1  NC116  pas
AC2  GND  pwr
AC3  NC111  pas
AC4  NC112  pas
AC5  GND  pwr
AC6  VCC  pwr
AC8  GND  pwr
AC9  IOAC9
AC10  IOAC10
AC11  GND  pwr
AC12  IOAC12
AC13  IOAC13
AC14  GND  pwr
AC15  VCC  pwr
AC16  GND  pwr
AC17  VCC  pwr
AC18  GND  pwr
AC19  VCC  pwr
AC20  GND  pwr
AC21  VCC  pwr
AC22  GND  pwr
AC23  VCC  pwr
AC24  GND  pwr
AC25  VCC  pwr
AC26  GND  pwr
AC27  VCC  pwr
AC28  GND  pwr
AC29  GND  pwr
AC30  IOAC30
AC31  IOAC31
AC32  GND  pwr
AC33  NC51  pas
AC34  NC52  pas
AC35  GND  pwr
AC36  NC47  pas
AC37  NC48  pas
AC38  GND  pwr
AC39  NC49  pas
AC40  NC50  pas
AC41  GND  pwr
AC42  IOAC42
AD1  NC115  pas
AD2  VCC  pwr
AD3  IOAD3
AD4  IOAD4
AD5  IOAD5
AD6  IOAD6
AD7  IOAD7
AD8  IOAD8
AD9  IOAD9
AD10  IOAD10
AD11  IOAD11
AD12  IOAD12
AD13  IOAD13
AD14  IOAD14
AD15  GND  pwr
AD16  VCC  pwr
AD17  GND  pwr
AD18  VCC  pwr
AD19  GND  pwr
AD20  VCC  pwr
AD21  GND  pwr
AD22  VCC  pwr
AD23  GND  pwr
AD24  VCC  pwr
AD25  GND  pwr
AD26  VCC  pwr
AD27  GND  pwr
AD28  VCC  pwr
AD29  GND  pwr
AD30  IOAD30
AD31  IOAD31
AD32  IOAD32
AD33  IOAD33
AD34  VCC  pwr
AD35  IOAD35
AD36  IOAD36
AD37  IOAD37
AD38  IOAD38
AD39  IOAD39
AD40  IOAD40
AD41  VCC  pwr
AD42  IOAD42
AE1  IOAE1
AE2  IOAE2
AE3  IOAE3
AE4  IOAE4
AE5  IOAE5
AE6  NC109  pas
AE7  NC110  pas
AE8  VCC  pwr
AE9  IOAE9
AE10  IOAE10
AE11  NC105  pas
AE12  NC106  pas
AE13  NC16  pas
AE14  VCC  pwr
AE15  VCC  pwr
AE16  GND  pwr
AE17  VCC  pwr
AE18  GND  pwr
AE19  VCC  pwr
AE20  GND  pwr
AE21  VCC  pwr
AE22  GND  pwr
AE23  VCC  pwr
AE24  GND  pwr
AE25  VCC  pwr
AE26  GND  pwr
AE27  VCC  pwr
AE28  GND  pwr
AE29  VCC  pwr
AE30  NC55  pas
AE31  NC56  pas
AE32  NC10  pas
AE33  IOAE33
AE34  IOAE34
AE36  IOAE36
AE37  IOAE37
AE38  IOAE38
AE39  IOAE39
AE40  IOAE40
AE41  IOAE41
AE42  IOAE42
AF1  IOAF1
AF2  GND  pwr
AF3  IOAF3
AF4  IOAF4
AF5  GND  pwr
AF6  IOAF6
AF7  IOAF7
AF8  GND  pwr
AF9  IOAF9
AF10  IOAF10
AF11  GND  pwr
AF12  IOAF12
AF13  NC177  pas
AF14  GND  pwr
AF15  GND  pwr
AF16  VCC  pwr
AF17  GND  pwr
AF18  VCC  pwr
AF19  GND  pwr
AF20  VCC  pwr
AF21  GND  pwr
AF22  VCC  pwr
AF23  GND  pwr
AF24  VCC  pwr
AF25  GND  pwr
AF26  VCC  pwr
AF27  GND  pwr
AF28  VCC  pwr
AF29  GND  pwr
AF30  NC59  pas
AF31  NC60  pas
AF32  GND  pwr
AF33  NC63  pas
AF34  NC64  pas
AF35  GND  pwr
AF36  IOAF36
AF37  IOAF37
AF38  GND  pwr
AF39  IOAF39
AF40  IOAF40
AF41  GND  pwr
AF42  IOAF42
AG1  IOAG1
AG2  IOAG2
AG3  IOAG3
AG4  IOAG4
AG5  IOAG5
AG6  IOAG6
AG8  IOAG8
AG9  IOAG9
AG10  IOAG10
AG11  IOAG11
AG12  IOAG12
AG13  VCC  pwr
AG14  VCC  pwr
AG15  VCC  pwr
AG16  GND  pwr
AG17  VCC  pwr
AG18  GND  pwr
AG19  VCC  pwr
AG20  GND  pwr
AG21  VCC  pwr
AG22  GND  pwr
AG23  VCC  pwr
AG24  GND  pwr
AG25  VCC  pwr
AG26  GND  pwr
AG27  VCC  pwr
AG28  GND  pwr
AG29  VCC  pwr
AG30  VCC  pwr
AG31  IOAG31
AG32  IOAG32
AG33  IOAG33
AG34  IOAG34
AG35  IOAG35
AG36  IOAG36
AG37  IOAG37
AG38  IOAG38
AG39  IOAG39
AG40  IOAG40
AG41  IOAG41
AG42  IOAG42
AH1  IOAH1
AH2  IOAH2
AH3  VCC  pwr
AH4  NC99  pas
AH5  NC100  pas
AH6  NC15  pas
AH7  NC97  pas
AH8  NC98  pas
AH9  IOAH9
AH10  IOAH10
AH11  IOAH11
AH12  IOAH12
AH13  IOAH13
AH14  IOAH14
AH15  GND  pwr
AH16  VCC  pwr
AH17  GND  pwr
AH18  VCC  pwr
AH19  GND  pwr
AH20  VCC  pwr
AH21  GND  pwr
AH22  VCC  pwr
AH23  GND  pwr
AH24  VCC  pwr
AH25  GND  pwr
AH26  VCC  pwr
AH27  GND  pwr
AH28  VCC  pwr
AH29  IOAH29
AH30  IOAH30
AH31  IOAH31
AH32  IOAH32
AH33  IOAH33
AH34  IOAH34
AH36  IOAH36
AH37  IOAH37
AH38  IOAH38
AH39  IOAH39
AH40  VCC  pwr
AH41  IOAH41
AH42  IOAH42
AJ1  NC107  pas
AJ2  GND  pwr
AJ3  NC103  pas
AJ4  NC104  pas
AJ5  GND  pwr
AJ6  NC101  pas
AJ7  NC102  pas
AJ8  GND  pwr
AJ9  VCC  pwr
AJ10  IOAJ10
AJ11  GND  pwr
AJ12  IOAJ12
AJ13  IOAJ13
AJ14  GND  pwr
AJ15  VCC  pwr
AJ16  GND  pwr
AJ17  GND  pwr
AJ18  GND  pwr
AJ19  VCC  pwr
AJ20  GND  pwr
AJ21  VCC  pwr
AJ22  VCC  pwr
AJ23  GND  pwr
AJ24  GND  pwr
AJ25  VCC  pwr
AJ26  GND  pwr
AJ27  VCC  pwr
AJ28  GND  pwr
AJ29  GND  pwr
AJ30  IOAJ30
AJ31  IOAJ31
AJ32  GND  pwr
AJ33  IOAJ33
AJ34  NC9  pas
AJ35  GND  pwr
AJ36  IOAJ36
AJ37  IOAJ37
AJ38  GND  pwr
AJ39  IOAJ39
AJ40  IOAJ40
AJ41  GND  pwr
AJ42  NC54  pas
AK1  NC108  pas
AK2  VCC  pwr
AK3  IOAK3
AK4  IOAK4
AK5  IOAK5
AK6  IOAK6
AK7  IOAK7
AK8  IOAK8
AK9  IOAK9
AK10  IOAK10
AK11  IOAK11
AK12  IOAK12
AK13  IOAK13
AK14  IOAK14
AK15  IOAK15
AK16  NC169  pas
AK17  IOAK17
AK18  VCC  pwr
AK19  NC171  pas
AK20  NC172  pas
AK21  NC173  pas
AK22  GND  pwr
AK23  NC174  pas
AK24  NC175  pas
AK25  VCC  pwr
AK26  IOAK26
AK27  NC176  pas
AK28  VCC  pwr
AK29  IOAK29
AK30  IOAK30
AK31  IOAK31
AK32  IOAK32
AK33  IOAK33
AK34  IOAK34
AK36  VCC  pwr
AK37  IOAK37
AK38  IOAK38
AK39  IOAK39
AK40  IOAK40
AK41  VCC  pwr
AK42  NC53  pas
AL1  IOAL1
AL2  IOAL2
AL3  IOAL3
AL4  IOAL4
AL5  IOAL5
AL6  IOAL6
AL7  IOAL7
AL9  VCC  pwr
AL10  VCC  pwr
AL11  IOAL11
AL12  IOAL12
AL13  IOAL13
AL14  IOAL14
AL15  VCC  pwr
AL16  IOAL16
AL17  IOAL17
AL18  IOAL18
AL19  NC14  pas
AL20  IOAL20
AL21  IOAL21
AL22  VCC  pwr
AL23  IOAL23
AL24  IOAL24
AL25  IOAL25
AL26  IOAL26
AL27  IOAL27
AL28  IOAL28
AL29  IOAL29
AL30  IOAL30
AL31  IOAL31
AL32  NCONFIG  in
AL33  VCC  pwr
AL34  VCC  pwr
AL35  NCE  in
AL36  IOAL36
AL37  IOAL37
AL38  IOAL38
AL39  IOAL39
AL40  NC61  pas
AL41  NC62  pas
AL42  NC58  pas
AM1  IOAM1
AM2  GND  pwr
AM3  IOAM3
AM4  IOAM4
AM5  GND  pwr
AM6  IOAM6
AM7  IOAM7
AM8  GND  pwr
AM9  NCSO  in
AM10  VCC  pwr
AM11  GND  pwr
AM12  IOAM12
AM13  IOAM13
AM14  GND  pwr
AM15  IOAM15
AM16  IOAM16
AM17  GND  pwr
AM18  IOAM18
AM19  IOAM19
AM20  GND  pwr
AM21  VCC  pwr
AM22  VCC  pwr
AM23  GND  pwr
AM24  IOAM24
AM25  IOAM25
AM26  GND  pwr
AM27  IOAM27
AM28  IOAM28
AM29  GND  pwr
AM30  IOAM30
AM31  IOAM31
AM32  GND  pwr
AM33  NC2  pas
AM34  VCC  pwr
AM35  GND  pwr
AM36  IOAM36
AM37  IOAM37
AM38  GND  pwr
AM39  IOAM39
AM40  IOAM40
AM41  GND  pwr
AM42  NC57  pas
AN1  IOAN1
AN2  IOAN2
AN3  IOAN3
AN4  IOAN4
AN5  IOAN5
AN6  IOAN6
AN7  VCC  pwr
AN8  NIO_PULLUP  in
AN9  VCC  pwr
AN10  IOAN10
AN11  IOAN11
AN12  IOAN12
AN13  IOAN13
AN14  IOAN14
AN15  IOAN15
AN16  IOAN16
AN17  IOAN17
AN18  IOAN18
AN19  IOAN19
AN20  NC87  pas
AN21  VCC  pwr
AN22  VCC  pwr
AN23  NC12  pas
AN24  IOAN24
AN25  IOAN25
AN26  VCC  pwr
AN27  IOAN27
AN28  IOAN28
AN29  IOAN29
AN30  IOAN30
AN31  IOAN31
AN32  IOAN32
AN33  VCC  pwr
AN34  PORSEL  in
AN35  NSTATUS  in
AN36  VCC  pwr
AN37  IOAN37
AN38  IOAN38
AN39  IOAN39
AN40  IOAN40
AN41  IOAN41
AN42  IOAN42
AP1  IOAP1
AP2  IOAP2
AP3  IOAP3
AP4  IOAP4
AP5  IOAP5
AP6  IOAP6
AP7  DCLK  in
AP8  NC3  pas
AP9  IOAP9
AP10  IOAP10
AP12  IOAP12
AP13  VCC  pwr
AP14  IOAP14
AP16  IOAP16
AP17  VCC  pwr
AP18  IOAP18
AP20  NC92  pas
AP21  VCC  pwr
AP22  VCC  pwr
AP24  IOAP24
AP25  IOAP25
AP26  NC11  pas
AP27  IOAP27
AP29  IOAP29
AP30  VCC  pwr
AP32  IOAP32
AP33  IOAP33
AP34  IOAP34
AP35  IOAP35
AP36  IOAP36
AP37  IOAP37
AP38  IOAP38
AP39  IOAP39
AP40  IOAP40
AP41  IOAP41
AP42  IOAP42
AR1  IOAR1
AR2  GND  pwr
AR3  IOAR3
AR4  IOAR4
AR5  GND  pwr
AR6  VCC  pwr
AR7  GND  pwr
AR8  GND  pwr
AR9  IOAR9
AR10  IOAR10
AR11  GND  pwr
AR12  IOAR12
AR13  IOAR13
AR14  GND  pwr
AR15  IOAR15
AR16  IOAR16
AR17  GND  pwr
AR18  IOAR18
AR19  NC91  pas
AR20  GND  pwr
AR21  IOAR21
AR22  IOAR22
AR23  GND  pwr
AR24  IOAR24
AR25  IOAR25
AR26  GND  pwr
AR27  IOAR27
AR28  IOAR28
AR29  GND  pwr
AR30  IOAR30
AR31  IOAR31
AR32  GND  pwr
AR33  IOAR33
AR34  IOAR34
AR35  GND  pwr
AR36  IOAR36
AR37  IOAR37
AR38  GND  pwr
AR39  IOAR39
AR40  IOAR40
AR41  GND  pwr
AR42  IOAR42
AT1  IOAT1
AT2  VCC  pwr
AT3  IOAT3
AT4  IOAT4
AT5  NCEO  in
AT6  ASDO  in
AT7  VCC  pwr
AT8  IOAT8
AT9  IOAT9
AT10  IOAT10
AT11  IOAT11
AT12  VCC  pwr
AT13  IOAT13
AT14  IOAT14
AT15  IOAT15
AT16  IOAT16
AT17  IOAT17
AT18  NC13  pas
AT19  NC89  pas
AT20  NC88  pas
AT21  IOAT21
AT22  IOAT22
AT23  NC73  pas
AT24  NC69  pas
AT25  IOAT25
AT26  IOAT26
AT27  IOAT27
AT28  IOAT28
AT29  IOAT29
AT30  IOAT30
AT31  IOAT31
AT32  IOAT32
AT33  VCC  pwr
AT34  IOAT34
AT35  IOAT35
AT36  VCC  pwr
AT37  IOAT37
AT38  NC170  pas
AT39  IOAT39
AT40  IOAT40
AT41  VCC  pwr
AT42  IOAT42
AU1  IOAU1
AU2  IOAU2
AU3  IOAU3
AU4  IOAU4
AU5  IOAU5
AU6  IOAU6
AU7  IOAU7
AU8  IOAU8
AU9  IOAU9
AU10  IOAU10
AU11  IOAU11
AU12  IOAU12
AU13  IOAU13
AU14  IOAU14
AU15  IOAU15
AU16  IOAU16
AU17  IOAU17
AU18  IOAU18
AU19  NC90  pas
AU20  VCC  pwr
AU21  IOAU21
AU22  IOAU22
AU23  NC70  pas
AU24  NC74  pas
AU25  IOAU25
AU26  IOAU26
AU27  VCC  pwr
AU28  IOAU28
AU29  IOAU29
AU30  IOAU30
AU31  IOAU31
AU32  IOAU32
AU33  IOAU33
AU34  IOAU34
AU35  IOAU35
AU36  IOAU36
AU37  IOAU37
AU38  CONF_DONE  in
AU39  VCC  pwr
AU40  IOAU40
AU41  IOAU41
AU42  IOAU42
AV1  IOAV1
AV2  GND  pwr
AV3  IOAV3
AV4  IOAV4
AV5  GND  pwr
AV6  IOAV6
AV7  IOAV7
AV8  GND  pwr
AV9  IOAV9
AV10  VCC  pwr
AV11  GND  pwr
AV12  IOAV12
AV13  IOAV13
AV14  GND  pwr
AV15  IOAV15
AV16  IOAV16
AV17  GND  pwr
AV18  NC95  pas
AV19  NC96  pas
AV20  GND  pwr
AV21  IOAV21
AV22  IOAV22
AV23  GND  pwr
AV24  NC72  pas
AV25  IOAV25
AV26  GND  pwr
AV27  IOAV27
AV28  IOAV28
AV29  GND  pwr
AV30  IOAV30
AV31  IOAV31
AV32  GND  pwr
AV33  IOAV33
AV34  IOAV34
AV35  GND  pwr
AV36  IOAV36
AV37  IOAV37
AV38  GND  pwr
AV39  IOAV39
AV40  IOAV40
AV41  GND  pwr
AV42  IOAV42
AW1  IOAW1
AW2  IOAW2
AW3  IOAW3
AW4  VCC  pwr
AW5  IOAW5
AW6  IOAW6
AW7  IOAW7
AW8  IOAW8
AW9  IOAW9
AW10  IOAW10
AW11  IOAW11
AW12  IOAW12
AW13  IOAW13
AW14  IOAW14
AW15  IOAW15
AW16  IOAW16
AW17  IOAW17
AW18  NC93  pas
AW19  NC94  pas
AW20  IOAW20
AW21  IOAW21
AW22  IOAW22
AW23  IOAW23
AW24  NC71  pas
AW25  IOAW25
AW26  IOAW26
AW27  IOAW27
AW28  IOAW28
AW29  IOAW29
AW30  IOAW30
AW31  IOAW31
AW32  IOAW32
AW33  IOAW33
AW34  IOAW34
AW35  IOAW35
AW36  IOAW36
AW37  IOAW37
AW38  IOAW38
AW39  VCC  pwr
AW40  IOAW40
AW41  IOAW41
AW42  IOAW42
AY1  PLL_R4_CLKN  in
AY2  PLL_R4_CLKP  in
AY3  IOAY3
AY4  IOAY4
AY5  IOAY5
AY6  IOAY6
AY7  VCC  pwr
AY8  IOAY8
AY9  IOAY9
AY10  IOAY10
AY11  IOAY11
AY12  IOAY12
AY13  VCC  pwr
AY14  IOAY14
AY15  IOAY15
AY16  VCC  pwr
AY17  IOAY17
AY18  NC85  pas
AY19  VCC  pwr
AY20  IOAY20
AY21  IOAY21
AY22  IOAY22
AY23  IOAY23
AY24  VCC  pwr
AY25  NC76  pas
AY26  IOAY26
AY27  VCC  pwr
AY28  IOAY28
AY29  IOAY29
AY30  VCC  pwr
AY31  IOAY31
AY32  IOAY32
AY33  IOAY33
AY34  VCC  pwr
AY35  IOAY35
AY36  IOAY36
AY37  IOAY37
AY38  IOAY38
AY39  IOAY39
AY40  IOAY40
AY41  PLL_L4_CLKP  in
AY42  PLL_L4_CLKN  in
B1  VCC  pwr
B2  GND  pwr
B3  IOB3
B4  IOB4
B5  GND  pwr
B6  IOB6
B7  IOB7
B8  GND  pwr
B9  IOB9
B10  IOB10
B11  GND  pwr
B12  IOB12
B13  IOB13
B14  GND  pwr
B15  IOB15
B16  IOB16
B17  GND  pwr
B18  NC147  pas
B19  NC152  pas
B20  GND  pwr
B21  IOB21
B22  IOB22
B23  GND  pwr
B24  NC153  pas
B25  NC157  pas
B26  GND  pwr
B27  NC165  pas
B28  IOB28
B29  GND  pwr
B30  IOB30
B31  IOB31
B32  GND  pwr
B33  IOB33
B34  IOB34
B35  GND  pwr
B36  IOB36
B37  IOB37
B38  GND  pwr
B39  IOB39
B40  IOB40
B41  GND  pwr
B42  VCC  pwr
BA1  VCC  pwr
BA2  GND  pwr
BA3  IOBA3
BA4  IOBA4
BA5  GND  pwr
BA6  IOBA6
BA7  IOBA7
BA8  GND  pwr
BA9  IOBA9
BA10  IOBA10
BA11  GND  pwr
BA12  IOBA12
BA13  IOBA13
BA14  GND  pwr
BA15  IOBA15
BA16  IOBA16
BA17  GND  pwr
BA18  NC86  pas
BA19  NC81  pas
BA20  GND  pwr
BA21  IOBA21
BA22  IOBA22
BA23  GND  pwr
BA24  NC80  pas
BA25  NC75  pas
BA26  GND  pwr
BA27  NC68  pas
BA28  IOBA28
BA29  GND  pwr
BA30  IOBA30
BA31  IOBA31
BA32  GND  pwr
BA33  IOBA33
BA34  IOBA34
BA35  GND  pwr
BA36  IOBA36
BA37  IOBA37
BA38  GND  pwr
BA39  IOBA39
BA40  IOBA40
BA41  GND  pwr
BA42  VCC  pwr
BB2  IOBB2
BB3  IOBB3
BB4  IOBB4
BB5  IOBB5
BB6  IOBB6
BB7  IOBB7
BB8  IOBB8
BB9  IOBB9
BB10  IOBB10
BB11  IOBB11
BB12  IOBB12
BB13  IOBB13
BB14  IOBB14
BB15  IOBB15
BB16  IOBB16
BB17  IOBB17
BB18  NC83  pas
BB19  NC82  pas
BB20  NC84  pas
BB21  IOBB21
BB22  IOBB22
BB23  NC78  pas
BB24  NC79  pas
BB25  NC77  pas
BB26  NC66  pas
BB27  NC67  pas
BB28  NC65  pas
BB29  IOBB29
BB30  IOBB30
BB31  IOBB31
BB32  IOBB32
BB33  IOBB33
BB34  IOBB34
BB35  IOBB35
BB36  IOBB36
BB37  IOBB37
BB38  VCC  pwr
BB39  IOBB39
BB40  IOBB40
BB41  IOBB41
C1  PLL_R1_CLKN  in
C2  PLL_R1_CLKP  in
C3  IOC3
C4  IOC4
C5  IOC5
C6  IOC6
C7  VCC  pwr
C8  IOC8
C9  IOC9
C10  VCC  pwr
C11  IOC11
C12  IOC12
C13  VCC  pwr
C14  IOC14
C15  IOC15
C16  NC21  pas
C17  IOC17
C18  NC148  pas
C19  NC22  pas
C20  IOC20
C21  IOC21
C22  IOC22
C23  IOC23
C24  NC23  pas
C25  NC156  pas
C26  IOC26
C27  NC24  pas
C28  NC168  pas
C29  IOC29
C30  VCC  pwr
C31  IOC31
C32  IOC32
C33  VCC  pwr
C34  IOC34
C35  IOC35
C36  IOC36
C37  IOC37
C38  IOC38
C39  IOC39
C40  IOC40
C41  PLL_L1_CLKP  in
C42  PLL_L1_CLKN  in
D1  IOD1
D2  IOD2
D3  IOD3
D4  VCC  pwr
D5  IOD5
D6  IOD6
D7  IOD7
D8  IOD8
D9  IOD9
D10  IOD10
D11  IOD11
D12  IOD12
D13  IOD13
D14  IOD14
D15  IOD15
D16  IOD16
D17  IOD17
D18  NC139  pas
D19  NC137  pas
D20  IOD20
D21  IOD21
D22  IOD22
D23  IOD23
D24  IOD24
D25  IOD25
D26  IOD26
D27  IOD27
D28  IOD28
D29  IOD29
D30  IOD30
D31  IOD31
D32  IOD32
D33  IOD33
D34  VCC  pwr
D35  IOD35
D36  IOD36
D37  IOD37
D38  IOD38
D39  VCC  pwr
D40  IOD40
D41  IOD41
D42  IOD42
E1  IOE1
E2  GND  pwr
E3  IOE3
E4  IOE4
E5  GND  pwr
E6  IOE6
E7  IOE7
E8  GND  pwr
E9  IOE9
E10  IOE10
E11  GND  pwr
E12  IOE12
E13  IOE13
E14  GND  pwr
E15  IOE15
E16  IOE16
E17  GND  pwr
E18  NC140  pas
E19  NC138  pas
E20  GND  pwr
E21  IOE21
E22  IOE22
E23  GND  pwr
E24  NC162  pas
E25  IOE25
E26  GND  pwr
E27  IOE27
E28  IOE28
E29  GND  pwr
E30  IOE30
E31  IOE31
E32  GND  pwr
E33  IOE33
E34  IOE34
E35  GND  pwr
E36  IOE36
E37  IOE37
E38  GND  pwr
E39  IOE39
E40  IOE40
E41  GND  pwr
E42  IOE42
F1  IOF1
F2  VCC  pwr
F3  IOF3
F4  IOF4
F5  MSEL2  in
F6  IOF6
F7  IOF7
F8  IOF8
F9  IOF9
F10  IOF10
F11  IOF11
F12  IOF12
F13  IOF13
F14  IOF14
F15  VCC  pwr
F16  IOF16
F17  IOF17
F18  VCC  pwr
F19  NC146  pas
F20  NC143  pas
F21  IOF21
F22  IOF22
F23  NC164  pas
F24  NC161  pas
F25  IOF25
F26  IOF26
F27  IOF27
F28  IOF28
F29  VCC  pwr
F30  IOF30
F31  IOF31
F32  IOF32
F33  IOF33
F34  IOF34
F35  IOF35
F36  IOF36
F37  IOF37
F38  IOF38
F39  IOF39
F40  IOF40
F41  IOF41
F42  IOF42
G1  IOG1
G2  IOG2
G3  IOG3
G4  IOG4
G5  IOG5
G6  TEMPDIODEP  pas
G7  VCC  pwr
G8  IOG8
G9  IOG9
G10  IOG10
G11  IOG11
G12  IOG12
G13  IOG13
G14  IOG14
G15  IOG15
G16  IOG16
G17  IOG17
G18  IOG18
G19  NC145  pas
G20  NC144  pas
G21  IOG21
G22  IOG22
G23  NC159  pas
G24  NC160  pas
G25  VCC  pwr
G26  IOG26
G27  IOG27
G28  IOG28
G29  IOG29
G30  IOG30
G31  IOG31
G32  IOG32
G33  IOG33
G34  IOG34
G35  IOG35
G36  VCC  pwr
G37  IOG37
G38  IOG38
G39  IOG39
G40  IOG40
G41  IOG41
G42  IOG42
H1  IOH1
H2  GND  pwr
H3  IOH3
H4  IOH4
H5  GND  pwr
H6  VCC  pwr
H7  TEMPDIODEN  pas
H8  GND  pwr
H9  IOH9
H10  VCC  pwr
H11  GND  pwr
H13  IOH13
H14  GND  pwr
H15  IOH15
H16  IOH16
H17  GND  pwr
H18  IOH18
H19  NC142  pas
H20  GND  pwr
H21  IOH21
H22  IOH22
H23  GND  pwr
H24  NC163  pas
H25  IOH25
H26  GND  pwr
H27  IOH27
H28  IOH28
H29  GND  pwr
H30  IOH30
H31  IOH31
H32  GND  pwr
H33  IOH33
H34  IOH34
H35  GND  pwr
H36  TCK  in
H37  TRST  in
H38  GND  pwr
H39  IOH39
H40  IOH40
H41  GND  pwr
H42  VCC  pwr
J1  IOJ1
J2  IOJ2
J3  IOJ3
J4  IOJ4
J5  IOJ5
J6  IOJ6
J7  IOJ7
J8  IOJ8
J9  IOJ9
J10  IOJ10
J11  IOJ11
J12  IOJ12
J13  IOJ13
J14  IOJ14
J16  IOJ16
J17  VCC  pwr
J18  IOJ18
J19  NC141  pas
J21  VCC  pwr
J22  VCC  pwr
J24  IOJ24
J25  IOJ25
J27  IOJ27
J28  IOJ28
J29  IOJ29
J31  VCC  pwr
J32  IOJ32
J33  IOJ33
J34  IOJ34
J35  TMS  in
J36  TDO  out
J37  IOJ37
J38  IOJ38
J39  IOJ39
J40  IOJ40
J41  IOJ41
J42  IOJ42
K1  IOK1
K2  IOK2
K3  IOK3
K4  IOK4
K5  IOK5
K6  IOK6
K8  VCC  pwr
K9  VCC  pwr
K10  IOK10
K11  IOK11
K12  IOK12
K13  IOK13
K14  IOK14
K15  IOK15
K16  VCC  pwr
K17  IOK17
K18  IOK18
K19  IOK19
K20  VCC  pwr
K21  VCC  pwr
K22  VCC  pwr
K23  VCC  pwr
K24  IOK24
K25  IOK25
K26  VCC  pwr
K27  IOK27
K28  IOK28
K29  IOK29
K30  IOK30
K31  IOK31
K32  IOK32
K33  IOK33
K34  NC1  pas
K35  IOK35
K36  IOK36
K37  IOK37
K38  IOK38
K39  IOK39
K40  IOK40
K41  IOK41
K42  IOK42
L1  IOL1
L2  GND  pwr
L3  IOL3
L4  IOL4
L5  GND  pwr
L6  IOL6
L7  IOL7
L8  GND  pwr
L9  VCC  pwr
L10  NC4  pas
L11  GND  pwr
L12  IOL12
L13  IOL13
L14  GND  pwr
L15  IOL15
L16  IOL16
L17  GND  pwr
L18  IOL18
L19  IOL19
L20  GND  pwr
L21  VCC  pwr
L22  VCC  pwr
L23  GND  pwr
L24  IOL24
L25  VCC  pwr
L26  GND  pwr
L27  IOL27
L28  IOL28
L29  GND  pwr
L30  IOL30
L31  IOL31
L32  GND  pwr
L33  VCC  pwr
L34  TDI  in
L35  GND  pwr
L37  VCC  pwr
L38  GND  pwr
L39  IOL39
L40  IOL40
L41  GND  pwr
L42  NC6  pas
M1  IOM1
M2  IOM2
M3  IOM3
M4  IOM4
M5  IOM5
M6  IOM6
M7  IOM7
M8  IOM8
M9  IOM9
M10  VCC  pwr
M11  MSEL0  in
M12  IOM12
M13  IOM13
M14  IOM14
M15  IOM15
M16  IOM16
M17  IOM17
M18  IOM18
M19  IOM19
M20  IOM20
M21  VCC  pwr
M22  IOM22
M23  IOM23
M24  IOM24
M25  IOM25
M26  IOM26
M27  IOM27
M28  VCC  pwr
M29  IOM29
M30  IOM30
M31  IOM31
M32  IOM32
M33  VCC  pwr
M34  VCC  pwr
M35  VCC  pwr
M36  IOM36
M37  IOM37
M38  IOM38
M39  IOM39
M40  IOM40
M41  NC28  pas
M42  NC27  pas
N1  NC125  pas
N2  NC19  pas
N3  ION3
N4  ION4
N5  ION5
N6  ION6
N7  NC20  pas
N8  ION8
N9  ION9
N10  ION10
N11  ION11
N12  VCC  pwr
N13  MSEL1  in
N14  ION14
N15  VCC  pwr
N16  NC182  pas
N17  ION17
N18  VCC  pwr
N19  NC183  pas
N20  NC184  pas
N21  GND  pwr
N22  NC185  pas
N23  NC186  pas
N24  NC187  pas
N25  VCC  pwr
N26  ION26
N27  NC188  pas
N28  ION28
N29  ION29
N30  NC189  pas
N31  ION31
N32  ION32
N33  ION33
N34  ION34
N35  ION35
N36  ION36
N37  ION37
N38  ION38
N39  ION39
N40  ION40
N41  ION41
N42  ION42
P1  NC126  pas
P2  GND  pwr
P3  NC130  pas
P4  NC129  pas
P5  GND  pwr
P6  IOP6
P7  IOP7
P8  GND  pwr
P9  IOP9
P10  VCC  pwr
P11  GND  pwr
P12  IOP12
P13  IOP13
P14  GND  pwr
P15  GND  pwr
P16  VCC  pwr
P17  GND  pwr
P18  VCC  pwr
P19  GND  pwr
P20  GND  pwr
P21  VCC  pwr
P22  VCC  pwr
P23  GND  pwr
P24  VCC  pwr
P25  GND  pwr
P26  GND  pwr
P27  GND  pwr
P28  VCC  pwr
P29  GND  pwr
P30  IOP30
P31  IOP31
P32  GND  pwr
P33  NC181  pas
P34  NC5  pas
P35  GND  pwr
P36  IOP36
P37  IOP37
P38  GND  pwr
P39  NC32  pas
P40  NC31  pas
P41  GND  pwr
P42  IOP42
R1  IOR1
R2  IOR2
R3  NC18  pas
R4  NC134  pas
R5  NC133  pas
R6  VCC  pwr
R7  IOR7
R8  IOR8
R9  IOR9
R10  IOR10
R11  IOR11
R12  IOR12
R13  IOR13
R14  IOR14
R15  VCC  pwr
R16  GND  pwr
R17  VCC  pwr
R18  GND  pwr
R19  VCC  pwr
R20  GND  pwr
R21  VCC  pwr
R22  GND  pwr
R23  VCC  pwr
R24  GND  pwr
R25  VCC  pwr
R26  GND  pwr
R27  VCC  pwr
R28  GND  pwr
R29  IOR29
R30  IOR30
R31  IOR31
R32  IOR32
R33  IOR33
R34  IOR34
R35  IOR35
R36  IOR36
R37  NC26  pas
R38  NC25  pas
R39  VCC  pwr
R40  IOR40
R41  IOR41
R42  IOR42
T1  IOT1
T2  IOT2
T3  IOT3
T4  IOT4
T5  IOT5
T6  IOT6
T7  NC136  pas
T8  NC135  pas
T10  IOT10
T11  IOT11
T12  IOT12
T13  NC180  pas
T14  VCC  pwr
T15  GND  pwr
T16  VCC  pwr
T17  GND  pwr
T18  VCC  pwr
T19  GND  pwr
T20  VCC  pwr
T21  GND  pwr
T22  VCC  pwr
T23  GND  pwr
T24  VCC  pwr
T25  GND  pwr
T26  VCC  pwr
T27  GND  pwr
T28  VCC  pwr
T29  VCC  pwr
T30  VCC  pwr
T31  IOT31
T32  IOT32
T33  IOT33
T34  IOT34
T35  IOT35
T37  NC36  pas
T38  NC35  pas
T39  IOT39
T40  IOT40
T41  IOT41
T42  IOT42
U1  IOU1
U2  GND  pwr
U3  IOU3
U4  IOU4
U5  GND  pwr
U6  IOU6
U7  IOU7
U8  GND  pwr
U9  VCC  pwr
U10  NC132  pas
U11  GND  pwr
U12  IOU12
U13  IOU13
U14  GND  pwr
U15  VCC  pwr
U16  GND  pwr
U17  VCC  pwr
U18  GND  pwr
U19  VCC  pwr
U20  GND  pwr
U21  VCC  pwr
U22  GND  pwr
U23  VCC  pwr
U24  GND  pwr
U25  VCC  pwr
U26  GND  pwr
U27  VCC  pwr
U28  GND  pwr
U29  GND  pwr
U30  NC30  pas
U31  NC29  pas
U32  GND  pwr
U33  IOU33
U34  VCC  pwr
U35  GND  pwr
U36  IOU36
U37  IOU37
U38  GND  pwr
U39  IOU39
U40  IOU40
U41  GND  pwr
U42  IOU42
V1  IOV1
V2  IOV2
V3  IOV3
V4  IOV4
V5  IOV5
V6  VCC  pwr
V7  IOV7
V8  IOV8
V9  IOV9
V10  IOV10
V11  NC131  pas
V12  NC128  pas
V13  NC127  pas
V14  VCC  pwr
V15  GND  pwr
V16  VCC  pwr
V17  GND  pwr
V18  VCC  pwr
V19  GND  pwr
V20  VCC  pwr
V21  GND  pwr
V22  VCC  pwr
V23  GND  pwr
V24  VCC  pwr
V25  GND  pwr
V26  VCC  pwr
V27  GND  pwr
V28  VCC  pwr
V29  VCC  pwr
V30  NC179  pas
V31  NC34  pas
V32  NC33  pas
V33  IOV33
V34  IOV34
V36  NC7  pas
V37  IOV37
V38  IOV38
V39  IOV39
V40  IOV40
V41  IOV41
V42  IOV42
W1  NC117  pas
W2  VCC  pwr
W3  IOW3
W4  IOW4
W5  IOW5
W6  IOW6
W7  IOW7
W8  IOW8
W9  IOW9
W10  VCC  pwr
W11  IOW11
W12  IOW12
W13  VCC  pwr
W14  GND  pwr
W15  VCC  pwr
W16  GND  pwr
W17  VCC  pwr
W18  GND  pwr
W19  VCC  pwr
W20  GND  pwr
W21  VCC  pwr
W22  GND  pwr
W23  VCC  pwr
W24  GND  pwr
W25  VCC  pwr
W26  GND  pwr
W27  VCC  pwr
W28  GND  pwr
W29  GND  pwr
W30  IOW30
W31  IOW31
W32  VCC  pwr
W33  IOW33
W34  IOW34
W35  IOW35
W36  IOW36
W37  IOW37
W38  IOW38
W39  IOW39
W40  IOW40
W41  VCC  pwr
W42  NC43  pas
Y1  NC118  pas
Y2  GND  pwr
Y3  NC122  pas
Y4  NC121  pas
Y5  GND  pwr
Y6  NC124  pas
Y7  NC123  pas
Y8  GND  pwr
Y10  IOY10
Y11  GND  pwr
Y12  IOY12
Y13  IOY13
Y14  GND  pwr
Y15  GND  pwr
Y16  VCC  pwr
Y17  GND  pwr
Y18  VCC  pwr
Y19  GND  pwr
Y20  VCC  pwr
Y21  GND  pwr
Y22  VCC  pwr
Y23  GND  pwr
Y24  VCC  pwr
Y25  GND  pwr
Y26  VCC  pwr
Y27  GND  pwr
Y28  VCC  pwr
Y29  GND  pwr
Y30  IOY30
Y31  IOY31
Y32  GND  pwr
Y33  IOY33
Y34  IOY34
Y35  GND  pwr
Y36  IOY36
Y37  VCC  pwr
Y38  GND  pwr
Y39  NC40  pas
Y40  NC39  pas
Y41  GND  pwr
Y42  NC44  pas

## Footprint FBGA1760 (pad centres in mm)
1760-Pin FineLine Ball-Grid Array (FBGA) - Flip Chip Auto generated by make-symbol-device-package-bsdl.ulp Rev. 29 Source: EP4SE530F43.bsd http://www.altera.com .. dspkg.pdf
smd 0.7 x 0.7: A2 -19.5,20.5; A3 -18.5,20.5; A4 -17.5,20.5; A5 -16.5,20.5; A6 -15.5,20.5; A7 -14.5,20.5; A8 -13.5,20.5; A9 -12.5,20.5; A10 -11.5,20.5; A11 -10.5,20.5; A12 -9.5,20.5; A13 -8.5,20.5; A14 -7.5,20.5; A15 -6.5,20.5; A16 -5.5,20.5; A17 -4.5,20.5; A18 -3.5,20.5; A19 -2.5,20.5; A20 -1.5,20.5; A21 -0.5,20.5; A22 0.5,20.5; A23 1.5,20.5; A24 2.5,20.5; A25 3.5,20.5; A26 4.5,20.5; A27 5.5,20.5; A28 6.5,20.5; A29 7.5,20.5; A30 8.5,20.5; A31 9.5,20.5; A32 10.5,20.5; A33 11.5,20.5; A34 12.5,20.5; A35 13.5,20.5; A36 14.5,20.5; A37 15.5,20.5; A38 16.5,20.5; A39 17.5,20.5; A40 18.5,20.5; A41 19.5,20.5; AA1 -20.5,0.5; AA2 -19.5,0.5; AA3 -18.5,0.5; AA4 -17.5,0.5; AA5 -16.5,0.5; AA6 -15.5,0.5; AA7 -14.5,0.5; AA8 -13.5,0.5; AA9 -12.5,0.5; AA10 -11.5,0.5; AA11 -10.5,0.5; AA12 -9.5,0.5; AA13 -8.5,0.5; AA14 -7.5,0.5; AA15 -6.5,0.5; AA16 -5.5,0.5; AA17 -4.5,0.5; AA18 -3.5,0.5; AA19 -2.5,0.5; AA20 -1.5,0.5; AA21 -0.5,0.5; AA22 0.5,0.5; AA23 1.5,0.5; AA24 2.5,0.5; AA25 3.5,0.5; AA26 4.5,0.5; AA27 5.5,0.5; AA28 6.5,0.5; AA29 7.5,0.5; AA30 8.5,0.5; AA31 9.5,0.5; AA32 10.5,0.5; AA33 11.5,0.5; AA34 12.5,0.5; AA35 13.5,0.5; AA36 14.5,0.5; AA37 15.5,0.5; AA38 16.5,0.5; AA39 17.5,0.5; AA40 18.5,0.5; AA41 19.5,0.5; AA42 20.5,0.5; AB1 -20.5,-0.5; AB2 -19.5,-0.5; AB3 -18.5,-0.5; AB4 -17.5,-0.5; AB5 -16.5,-0.5; AB6 -15.5,-0.5; AB7 -14.5,-0.5; AB8 -13.5,-0.5; AB9 -12.5,-0.5; AB10 -11.5,-0.5; AB11 -10.5,-0.5; AB12 -9.5,-0.5; AB13 -8.5,-0.5; AB14 -7.5,-0.5; AB15 -6.5,-0.5; AB16 -5.5,-0.5; AB17 -4.5,-0.5; AB18 -3.5,-0.5; AB19 -2.5,-0.5; AB20 -1.5,-0.5; AB21 -0.5,-0.5; AB22 0.5,-0.5; AB23 1.5,-0.5; AB24 2.5,-0.5; AB25 3.5,-0.5; AB26 4.5,-0.5; AB27 5.5,-0.5; AB28 6.5,-0.5; AB29 7.5,-0.5; AB30 8.5,-0.5; AB31 9.5,-0.5; AB32 10.5,-0.5; AB33 11.5,-0.5; AB34 12.5,-0.5; AB35 13.5,-0.5; AB36 14.5,-0.5; AB37 15.5,-0.5; AB38 16.5,-0.5; AB39 17.5,-0.5; AB40 18.5,-0.5; AB41 19.5,-0.5; AB42 20.5,-0.5; AC1 -20.5,-1.5; AC2 -19.5,-1.5; AC3 -18.5,-1.5; AC4 -17.5,-1.5; AC5 -16.5,-1.5; AC6 -15.5,-1.5; AC7 -14.5,-1.5; AC8 -13.5,-1.5; AC9 -12.5,-1.5; AC10 -11.5,-1.5; AC11 -10.5,-1.5; AC12 -9.5,-1.5; AC13 -8.5,-1.5; AC14 -7.5,-1.5; AC15 -6.5,-1.5; AC16 -5.5,-1.5; AC17 -4.5,-1.5; AC18 -3.5,-1.5; AC19 -2.5,-1.5; AC20 -1.5,-1.5; AC21 -0.5,-1.5; AC22 0.5,-1.5; AC23 1.5,-1.5; AC24 2.5,-1.5; AC25 3.5,-1.5; AC26 4.5,-1.5; AC27 5.5,-1.5; AC28 6.5,-1.5; AC29 7.5,-1.5; AC30 8.5,-1.5; AC31 9.5,-1.5; AC32 10.5,-1.5; AC33 11.5,-1.5; AC34 12.5,-1.5; AC35 13.5,-1.5; AC36 14.5,-1.5; AC37 15.5,-1.5; AC38 16.5,-1.5; AC39 17.5,-1.5; AC40 18.5,-1.5; AC41 19.5,-1.5; AC42 20.5,-1.5; AD1 -20.5,-2.5; AD2 -19.5,-2.5; AD3 -18.5,-2.5; AD4 -17.5,-2.5; AD5 -16.5,-2.5; AD6 -15.5,-2.5; AD7 -14.5,-2.5; AD8 -13.5,-2.5; AD9 -12.5,-2.5; AD10 -11.5,-2.5; AD11 -10.5,-2.5; AD12 -9.5,-2.5; AD13 -8.5,-2.5; AD14 -7.5,-2.5; AD15 -6.5,-2.5; AD16 -5.5,-2.5; AD17 -4.5,-2.5; AD18 -3.5,-2.5; AD19 -2.5,-2.5; AD20 -1.5,-2.5; AD21 -0.5,-2.5; AD22 0.5,-2.5; AD23 1.5,-2.5; AD24 2.5,-2.5; AD25 3.5,-2.5; AD26 4.5,-2.5; AD27 5.5,-2.5; AD28 6.5,-2.5; AD29 7.5,-2.5; AD30 8.5,-2.5; AD31 9.5,-2.5; AD32 10.5,-2.5; AD33 11.5,-2.5; AD34 12.5,-2.5; AD35 13.5,-2.5; AD36 14.5,-2.5; AD37 15.5,-2.5; AD38 16.5,-2.5; AD39 17.5,-2.5; AD40 18.5,-2.5; AD41 19.5,-2.5; AD42 20.5,-2.5; AE1 -20.5,-3.5; AE2 -19.5,-3.5; AE3 -18.5,-3.5; AE4 -17.5,-3.5; AE5 -16.5,-3.5; AE6 -15.5,-3.5; AE7 -14.5,-3.5; AE8 -13.5,-3.5; AE9 -12.5,-3.5; AE10 -11.5,-3.5; AE11 -10.5,-3.5; AE12 -9.5,-3.5; AE13 -8.5,-3.5; AE14 -7.5,-3.5; AE15 -6.5,-3.5; AE16 -5.5,-3.5; AE17 -4.5,-3.5; AE18 -3.5,-3.5; AE19 -2.5,-3.5; AE20 -1.5,-3.5; AE21 -0.5,-3.5; AE22 0.5,-3.5; AE23 1.5,-3.5; AE24 2.5,-3.5; AE25 3.5,-3.5; AE26 4.5,-3.5; AE27 5.5,-3.5; AE28 6.5,-3.5; AE29 7.5,-3.5; AE30 8.5,-3.5; AE31 9.5,-3.5; AE32 10.5,-3.5; AE33 11.5,-3.5; AE34 12.5,-3.5; AE35 13.5,-3.5; AE36 14.5,-3.5; AE37 15.5,-3.5; AE38 16.5,-3.5; AE39 17.5,-3.5; AE40 18.5,-3.5; AE41 19.5,-3.5; AE42 20.5,-3.5; AF1 -20.5,-4.5; AF2 -19.5,-4.5; AF3 -18.5,-4.5; AF4 -17.5,-4.5; AF5 -16.5,-4.5; AF6 -15.5,-4.5; AF7 -14.5,-4.5; AF8 -13.5,-4.5; AF9 -12.5,-4.5; AF10 -11.5,-4.5; AF11 -10.5,-4.5; AF12 -9.5,-4.5; AF13 -8.5,-4.5; AF14 -7.5,-4.5; AF15 -6.5,-4.5; AF16 -5.5,-4.5; AF17 -4.5,-4.5; AF18 -3.5,-4.5; AF19 -2.5,-4.5; AF20 -1.5,-4.5; AF21 -0.5,-4.5; AF22 0.5,-4.5; AF23 1.5,-4.5; AF24 2.5,-4.5; AF25 3.5,-4.5; AF26 4.5,-4.5; AF27 5.5,-4.5; AF28 6.5,-4.5; AF29 7.5,-4.5; AF30 8.5,-4.5; AF31 9.5,-4.5; AF32 10.5,-4.5; AF33 11.5,-4.5; AF34 12.5,-4.5; AF35 13.5,-4.5; AF36 14.5,-4.5; AF37 15.5,-4.5; AF38 16.5,-4.5; AF39 17.5,-4.5; AF40 18.5,-4.5; AF41 19.5,-4.5; AF42 20.5,-4.5; AG1 -20.5,-5.5; AG2 -19.5,-5.5; AG3 -18.5,-5.5; AG4 -17.5,-5.5; AG5 -16.5,-5.5; AG6 -15.5,-5.5; AG7 -14.5,-5.5; AG8 -13.5,-5.5; AG9 -12.5,-5.5; AG10 -11.5,-5.5; AG11 -10.5,-5.5; AG12 -9.5,-5.5; AG13 -8.5,-5.5; AG14 -7.5,-5.5; AG15 -6.5,-5.5; AG16 -5.5,-5.5; AG17 -4.5,-5.5; AG18 -3.5,-5.5; AG19 -2.5,-5.5; AG20 -1.5,-5.5; AG21 -0.5,-5.5; AG22 0.5,-5.5; AG23 1.5,-5.5; AG24 2.5,-5.5; AG25 3.5,-5.5; AG26 4.5,-5.5; AG27 5.5,-5.5; AG28 6.5,-5.5; AG29 7.5,-5.5; AG30 8.5,-5.5; AG31 9.5,-5.5; AG32 10.5,-5.5; AG33 11.5,-5.5; AG34 12.5,-5.5; AG35 13.5,-5.5; AG36 14.5,-5.5; AG37 15.5,-5.5; AG38 16.5,-5.5; AG39 17.5,-5.5; AG40 18.5,-5.5; AG41 19.5,-5.5; AG42 20.5,-5.5; AH1 -20.5,-6.5; AH2 -19.5,-6.5; AH3 -18.5,-6.5; AH4 -17.5,-6.5; AH5 -16.5,-6.5; AH6 -15.5,-6.5; AH7 -14.5,-6.5; AH8 -13.5,-6.5; AH9 -12.5,-6.5; AH10 -11.5,-6.5; AH11 -10.5,-6.5; AH12 -9.5,-6.5; AH13 -8.5,-6.5; AH14 -7.5,-6.5; AH15 -6.5,-6.5; AH16 -5.5,-6.5; AH17 -4.5,-6.5; AH18 -3.5,-6.5; AH19 -2.5,-6.5; AH20 -1.5,-6.5; AH21 -0.5,-6.5; AH22 0.5,-6.5; AH23 1.5,-6.5; AH24 2.5,-6.5; AH25 3.5,-6.5; AH26 4.5,-6.5; AH27 5.5,-6.5; AH28 6.5,-6.5; AH29 7.5,-6.5; AH30 8.5,-6.5; AH31 9.5,-6.5; AH32 10.5,-6.5; AH33 11.5,-6.5; AH34 12.5,-6.5; AH35 13.5,-6.5; AH36 14.5,-6.5; AH37 15.5,-6.5; AH38 16.5,-6.5; AH39 17.5,-6.5; AH40 18.5,-6.5; AH41 19.5,-6.5; AH42 20.5,-6.5; AJ1 -20.5,-7.5; AJ2 -19.5,-7.5; AJ3 -18.5,-7.5; AJ4 -17.5,-7.5; AJ5 -16.5,-7.5; AJ6 -15.5,-7.5; AJ7 -14.5,-7.5; AJ8 -13.5,-7.5; AJ9 -12.5,-7.5; AJ10 -11.5,-7.5; AJ11 -10.5,-7.5; AJ12 -9.5,-7.5; AJ13 -8.5,-7.5; AJ14 -7.5,-7.5; AJ15 -6.5,-7.5; AJ16 -5.5,-7.5; AJ17 -4.5,-7.5; AJ18 -3.5,-7.5; AJ19 -2.5,-7.5; AJ20 -1.5,-7.5; AJ21 -0.5,-7.5; AJ22 0.5,-7.5; AJ23 1.5,-7.5; AJ24 2.5,-7.5; AJ25 3.5,-7.5; AJ26 4.5,-7.5; AJ27 5.5,-7.5; AJ28 6.5,-7.5; AJ29 7.5,-7.5; AJ30 8.5,-7.5; AJ31 9.5,-7.5; AJ32 10.5,-7.5; AJ33 11.5,-7.5; AJ34 12.5,-7.5; AJ35 13.5,-7.5; AJ36 14.5,-7.5; AJ37 15.5,-7.5; AJ38 16.5,-7.5; AJ39 17.5,-7.5; AJ40 18.5,-7.5; AJ41 19.5,-7.5; AJ42 20.5,-7.5; AK1 -20.5,-8.5; AK2 -19.5,-8.5; AK3 -18.5,-8.5; AK4 -17.5,-8.5; AK5 -16.5,-8.5; AK6 -15.5,-8.5; AK7 -14.5,-8.5; AK8 -13.5,-8.5; AK9 -12.5,-8.5; AK10 -11.5,-8.5; AK11 -10.5,-8.5; AK12 -9.5,-8.5; AK13 -8.5,-8.5; AK14 -7.5,-8.5; AK15 -6.5,-8.5; AK16 -5.5,-8.5; AK17 -4.5,-8.5; AK18 -3.5,-8.5; AK19 -2.5,-8.5; AK20 -1.5,-8.5; AK21 -0.5,-8.5; AK22 0.5,-8.5; AK23 1.5,-8.5; AK24 2.5,-8.5; AK25 3.5,-8.5; AK26 4.5,-8.5; AK27 5.5,-8.5; AK28 6.5,-8.5; AK29 7.5,-8.5; AK30 8.5,-8.5; AK31 9.5,-8.5; AK32 10.5,-8.5; AK33 11.5,-8.5; AK34 12.5,-8.5; AK35 13.5,-8.5; AK36 14.5,-8.5; AK37 15.5,-8.5; AK38 16.5,-8.5; AK39 17.5,-8.5; AK40 18.5,-8.5; AK41 19.5,-8.5; AK42 20.5,-8.5; AL1 -20.5,-9.5; AL2 -19.5,-9.5; AL3 -18.5,-9.5; AL4 -17.5,-9.5; AL5 -16.5,-9.5; AL6 -15.5,-9.5; AL7 -14.5,-9.5; AL8 -13.5,-9.5; AL9 -12.5,-9.5; AL10 -11.5,-9.5; AL11 -10.5,-9.5; AL12 -9.5,-9.5; AL13 -8.5,-9.5; AL14 -7.5,-9.5; AL15 -6.5,-9.5; AL16 -5.5,-9.5; AL17 -4.5,-9.5; AL18 -3.5,-9.5; AL19 -2.5,-9.5; AL20 -1.5,-9.5; AL21 -0.5,-9.5; AL22 0.5,-9.5; AL23 1.5,-9.5; AL24 2.5,-9.5; AL25 3.5,-9.5; AL26 4.5,-9.5; AL27 5.5,-9.5; AL28 6.5,-9.5; AL29 7.5,-9.5; AL30 8.5,-9.5; AL31 9.5,-9.5; AL32 10.5,-9.5; AL33 11.5,-9.5; AL34 12.5,-9.5; AL35 13.5,-9.5; AL36 14.5,-9.5; AL37 15.5,-9.5; AL38 16.5,-9.5; AL39 17.5,-9.5; AL40 18.5,-9.5; AL41 19.5,-9.5; AL42 20.5,-9.5; AM1 -20.5,-10.5; AM2 -19.5,-10.5; AM3 -18.5,-10.5; AM4 -17.5,-10.5; AM5 -16.5,-10.5; AM6 -15.5,-10.5; AM7 -14.5,-10.5; AM8 -13.5,-10.5; AM9 -12.5,-10.5; AM10 -11.5,-10.5; AM11 -10.5,-10.5; AM12 -9.5,-10.5; AM13 -8.5,-10.5; AM14 -7.5,-10.5; AM15 -6.5,-10.5; AM16 -5.5,-10.5; AM17 -4.5,-10.5; AM18 -3.5,-10.5; AM19 -2.5,-10.5; AM20 -1.5,-10.5; AM21 -0.5,-10.5; AM22 0.5,-10.5; AM23 1.5,-10.5; AM24 2.5,-10.5; AM25 3.5,-10.5; AM26 4.5,-10.5; AM27 5.5,-10.5; AM28 6.5,-10.5; AM29 7.5,-10.5; AM30 8.5,-10.5; AM31 9.5,-10.5; AM32 10.5,-10.5; AM33 11.5,-10.5; AM34 12.5,-10.5; AM35 13.5,-10.5; AM36 14.5,-10.5; AM37 15.5,-10.5; AM38 16.5,-10.5; AM39 17.5,-10.5; AM40 18.5,-10.5; AM41 19.5,-10.5; AM42 20.5,-10.5; AN1 -20.5,-11.5; AN2 -19.5,-11.5; AN3 -18.5,-11.5; AN4 -17.5,-11.5; AN5 -16.5,-11.5; AN6 -15.5,-11.5; AN7 -14.5,-11.5; AN8 -13.5,-11.5; AN9 -12.5,-11.5; AN10 -11.5,-11.5; AN11 -10.5,-11.5; AN12 -9.5,-11.5; AN13 -8.5,-11.5; AN14 -7.5,-11.5; AN15 -6.5,-11.5; AN16 -5.5,-11.5; AN17 -4.5,-11.5; AN18 -3.5,-11.5; AN19 -2.5,-11.5; AN20 -1.5,-11.5; AN21 -0.5,-11.5; AN22 0.5,-11.5; AN23 1.5,-11.5; AN24 2.5,-11.5; AN25 3.5,-11.5; AN26 4.5,-11.5; AN27 5.5,-11.5; AN28 6.5,-11.5; AN29 7.5,-11.5; AN30 8.5,-11.5; AN31 9.5,-11.5; AN32 10.5,-11.5; AN33 11.5,-11.5; AN34 12.5,-11.5; AN35 13.5,-11.5; AN36 14.5,-11.5; AN37 15.5,-11.5; AN38 16.5,-11.5; AN39 17.5,-11.5; AN40 18.5,-11.5; AN41 19.5,-11.5; AN42 20.5,-11.5; AP1 -20.5,-12.5; AP2 -19.5,-12.5; AP3 -18.5,-12.5; AP4 -17.5,-12.5; AP5 -16.5,-12.5; AP6 -15.5,-12.5; AP7 -14.5,-12.5; AP8 -13.5,-12.5; AP9 -12.5,-12.5; AP10 -11.5,-12.5; AP11 -10.5,-12.5; AP12 -9.5,-12.5; AP13 -8.5,-12.5; AP14 -7.5,-12.5; AP15 -6.5,-12.5; AP16 -5.5,-12.5; AP17 -4.5,-12.5; AP18 -3.5,-12.5; AP19 -2.5,-12.5; AP20 -1.5,-12.5; AP21 -0.5,-12.5; AP22 0.5,-12.5; AP23 1.5,-12.5; AP24 2.5,-12.5; AP25 3.5,-12.5; AP26 4.5,-12.5; AP27 5.5,-12.5; AP28 6.5,-12.5; AP29 7.5,-12.5; AP30 8.5,-12.5; AP31 9.5,-12.5; AP32 10.5,-12.5; AP33 11.5,-12.5; AP34 12.5,-12.5; AP35 13.5,-12.5; AP36 14.5,-12.5; AP37 15.5,-12.5; AP38 16.5,-12.5; AP39 17.5,-12.5; AP40 18.5,-12.5; AP41 19.5,-12.5; AP42 20.5,-12.5; AR1 -20.5,-13.5; AR2 -19.5,-13.5; AR3 -18.5,-13.5; AR4 -17.5,-13.5; AR5 -16.5,-13.5; AR6 -15.5,-13.5; AR7 -14.5,-13.5; AR8 -13.5,-13.5; AR9 -12.5,-13.5; AR10 -11.5,-13.5; AR11 -10.5,-13.5; AR12 -9.5,-13.5; AR13 -8.5,-13.5; AR14 -7.5,-13.5; AR15 -6.5,-13.5; AR16 -5.5,-13.5; AR17 -4.5,-13.5; AR18 -3.5,-13.5; AR19 -2.5,-13.5; AR20 -1.5,-13.5; AR21 -0.5,-13.5; AR22 0.5,-13.5; AR23 1.5,-13.5; AR24 2.5,-13.5; AR25 3.5,-13.5; AR26 4.5,-13.5; AR27 5.5,-13.5; AR28 6.5,-13.5; AR29 7.5,-13.5; AR30 8.5,-13.5; AR31 9.5,-13.5; AR32 10.5,-13.5; AR33 11.5,-13.5; AR34 12.5,-13.5; AR35 13.5,-13.5; AR36 14.5,-13.5; AR37 15.5,-13.5; AR38 16.5,-13.5; AR39 17.5,-13.5; AR40 18.5,-13.5; AR41 19.5,-13.5; AR42 20.5,-13.5; AT1 -20.5,-14.5; AT2 -19.5,-14.5; AT3 -18.5,-14.5; AT4 -17.5,-14.5; AT5 -16.5,-14.5; AT6 -15.5,-14.5; AT7 -14.5,-14.5; AT8 -13.5,-14.5; AT9 -12.5,-14.5; AT10 -11.5,-14.5; AT11 -10.5,-14.5; AT12 -9.5,-14.5; AT13 -8.5,-14.5; AT14 -7.5,-14.5; AT15 -6.5,-14.5; AT16 -5.5,-14.5; AT17 -4.5,-14.5; AT18 -3.5,-14.5; AT19 -2.5,-14.5; AT20 -1.5,-14.5; AT21 -0.5,-14.5; AT22 0.5,-14.5; AT23 1.5,-14.5; AT24 2.5,-14.5; AT25 3.5,-14.5; AT26 4.5,-14.5; AT27 5.5,-14.5; AT28 6.5,-14.5; AT29 7.5,-14.5; AT30 8.5,-14.5; AT31 9.5,-14.5; AT32 10.5,-14.5; AT33 11.5,-14.5; AT34 12.5,-14.5; AT35 13.5,-14.5; AT36 14.5,-14.5; AT37 15.5,-14.5; AT38 16.5,-14.5; AT39 17.5,-14.5; AT40 18.5,-14.5; AT41 19.5,-14.5; AT42 20.5,-14.5; AU1 -20.5,-15.5; AU2 -19.5,-15.5; AU3 -18.5,-15.5; AU4 -17.5,-15.5; AU5 -16.5,-15.5; AU6 -15.5,-15.5; AU7 -14.5,-15.5; AU8 -13.5,-15.5; AU9 -12.5,-15.5; AU10 -11.5,-15.5; AU11 -10.5,-15.5; AU12 -9.5,-15.5; AU13 -8.5,-15.5; AU14 -7.5,-15.5; AU15 -6.5,-15.5; AU16 -5.5,-15.5; AU17 -4.5,-15.5; AU18 -3.5,-15.5; AU19 -2.5,-15.5; AU20 -1.5,-15.5; AU21 -0.5,-15.5; AU22 0.5,-15.5; AU23 1.5,-15.5; AU24 2.5,-15.5; AU25 3.5,-15.5; AU26 4.5,-15.5; AU27 5.5,-15.5; AU28 6.5,-15.5; AU29 7.5,-15.5; AU30 8.5,-15.5; AU31 9.5,-15.5; AU32 10.5,-15.5; AU33 11.5,-15.5; AU34 12.5,-15.5; AU35 13.5,-15.5; AU36 14.5,-15.5; AU37 15.5,-15.5; AU38 16.5,-15.5; AU39 17.5,-15.5; AU40 18.5,-15.5; AU41 19.5,-15.5; AU42 20.5,-15.5; AV1 -20.5,-16.5; AV2 -19.5,-16.5; AV3 -18.5,-16.5; AV4 -17.5,-16.5; AV5 -16.5,-16.5; AV6 -15.5,-16.5; AV7 -14.5,-16.5; AV8 -13.5,-16.5; AV9 -12.5,-16.5; AV10 -11.5,-16.5; AV11 -10.5,-16.5; AV12 -9.5,-16.5; AV13 -8.5,-16.5; AV14 -7.5,-16.5; AV15 -6.5,-16.5; AV16 -5.5,-16.5; AV17 -4.5,-16.5; AV18 -3.5,-16.5; AV19 -2.5,-16.5; AV20 -1.5,-16.5; AV21 -0.5,-16.5; AV22 0.5,-16.5; AV23 1.5,-16.5; AV24 2.5,-16.5; AV25 3.5,-16.5; AV26 4.5,-16.5; AV27 5.5,-16.5; AV28 6.5,-16.5; AV29 7.5,-16.5; AV30 8.5,-16.5; AV31 9.5,-16.5; AV32 10.5,-16.5; AV33 11.5,-16.5; AV34 12.5,-16.5; AV35 13.5,-16.5; AV36 14.5,-16.5; AV37 15.5,-16.5; AV38 16.5,-16.5; AV39 17.5,-16.5; AV40 18.5,-16.5; AV41 19.5,-16.5; AV42 20.5,-16.5; AW1 -20.5,-17.5; AW2 -19.5,-17.5; AW3 -18.5,-17.5; AW4 -17.5,-17.5; AW5 -16.5,-17.5; AW6 -15.5,-17.5; AW7 -14.5,-17.5; AW8 -13.5,-17.5; AW9 -12.5,-17.5; AW10 -11.5,-17.5; AW11 -10.5,-17.5; AW12 -9.5,-17.5; AW13 -8.5,-17.5; AW14 -7.5,-17.5; AW15 -6.5,-17.5; AW16 -5.5,-17.5; AW17 -4.5,-17.5; AW18 -3.5,-17.5; AW19 -2.5,-17.5; AW20 -1.5,-17.5; AW21 -0.5,-17.5; AW22 0.5,-17.5; AW23 1.5,-17.5; AW24 2.5,-17.5; AW25 3.5,-17.5; AW26 4.5,-17.5; AW27 5.5,-17.5; AW28 6.5,-17.5; AW29 7.5,-17.5; AW30 8.5,-17.5; AW31 9.5,-17.5; AW32 10.5,-17.5; AW33 11.5,-17.5; AW34 12.5,-17.5; AW35 13.5,-17.5; AW36 14.5,-17.5; AW37 15.5,-17.5; AW38 16.5,-17.5; AW39 17.5,-17.5; AW40 18.5,-17.5; AW41 19.5,-17.5; AW42 20.5,-17.5; AY1 -20.5,-18.5; AY2 -19.5,-18.5; AY3 -18.5,-18.5; AY4 -17.5,-18.5; AY5 -16.5,-18.5; AY6 -15.5,-18.5; AY7 -14.5,-18.5; AY8 -13.5,-18.5; AY9 -12.5,-18.5; AY10 -11.5,-18.5; AY11 -10.5,-18.5; AY12 -9.5,-18.5; AY13 -8.5,-18.5; AY14 -7.5,-18.5; AY15 -6.5,-18.5; AY16 -5.5,-18.5; AY17 -4.5,-18.5; AY18 -3.5,-18.5; AY19 -2.5,-18.5; AY20 -1.5,-18.5; AY21 -0.5,-18.5; AY22 0.5,-18.5; AY23 1.5,-18.5; AY24 2.5,-18.5; AY25 3.5,-18.5; AY26 4.5,-18.5; AY27 5.5,-18.5; AY28 6.5,-18.5; AY29 7.5,-18.5; AY30 8.5,-18.5; AY31 9.5,-18.5; AY32 10.5,-18.5; AY33 11.5,-18.5; AY34 12.5,-18.5; AY35 13.5,-18.5; AY36 14.5,-18.5; AY37 15.5,-18.5; AY38 16.5,-18.5; AY39 17.5,-18.5; AY40 18.5,-18.5; AY41 19.5,-18.5; AY42 20.5,-18.5; B1 -20.5,19.5; B2 -19.5,19.5; B3 -18.5,19.5; B4 -17.5,19.5; B5 -16.5,19.5; B6 -15.5,19.5; B7 -14.5,19.5; B8 -13.5,19.5; B9 -12.5,19.5; B10 -11.5,19.5; B11 -10.5,19.5; B12 -9.5,19.5; B13 -8.5,19.5; B14 -7.5,19.5; B15 -6.5,19.5; B16 -5.5,19.5; B17 -4.5,19.5; B18 -3.5,19.5; B19 -2.5,19.5; B20 -1.5,19.5; B21 -0.5,19.5; B22 0.5,19.5; B23 1.5,19.5; B24 2.5,19.5; B25 3.5,19.5; B26 4.5,19.5; B27 5.5,19.5; B28 6.5,19.5; B29 7.5,19.5; B30 8.5,19.5; B31 9.5,19.5; B32 10.5,19.5; B33 11.5,19.5; B34 12.5,19.5; B35 13.5,19.5; B36 14.5,19.5; B37 15.5,19.5; B38 16.5,19.5; B39 17.5,19.5; B40 18.5,19.5; B41 19.5,19.5; B42 20.5,19.5; BA1 -20.5,-19.5; BA2 -19.5,-19.5; BA3 -18.5,-19.5; BA4 -17.5,-19.5; BA5 -16.5,-19.5; BA6 -15.5,-19.5; BA7 -14.5,-19.5; BA8 -13.5,-19.5; BA9 -12.5,-19.5; BA10 -11.5,-19.5; BA11 -10.5,-19.5; BA12 -9.5,-19.5; BA13 -8.5,-19.5; BA14 -7.5,-19.5; BA15 -6.5,-19.5; BA16 -5.5,-19.5; BA17 -4.5,-19.5; BA18 -3.5,-19.5; BA19 -2.5,-19.5; BA20 -1.5,-19.5; BA21 -0.5,-19.5; BA22 0.5,-19.5; BA23 1.5,-19.5; BA24 2.5,-19.5; BA25 3.5,-19.5; BA26 4.5,-19.5; BA27 5.5,-19.5; BA28 6.5,-19.5; BA29 7.5,-19.5; BA30 8.5,-19.5; BA31 9.5,-19.5; BA32 10.5,-19.5; BA33 11.5,-19.5; BA34 12.5,-19.5; BA35 13.5,-19.5; BA36 14.5,-19.5; BA37 15.5,-19.5; BA38 16.5,-19.5; BA39 17.5,-19.5; BA40 18.5,-19.5; BA41 19.5,-19.5; BA42 20.5,-19.5; BB2 -19.5,-20.5; BB3 -18.5,-20.5; BB4 -17.5,-20.5; BB5 -16.5,-20.5; BB6 -15.5,-20.5; BB7 -14.5,-20.5; BB8 -13.5,-20.5; BB9 -12.5,-20.5; BB10 -11.5,-20.5; BB11 -10.5,-20.5; BB12 -9.5,-20.5; BB13 -8.5,-20.5; BB14 -7.5,-20.5; BB15 -6.5,-20.5; BB16 -5.5,-20.5; BB17 -4.5,-20.5; BB18 -3.5,-20.5; BB19 -2.5,-20.5; BB20 -1.5,-20.5; BB21 -0.5,-20.5; BB22 0.5,-20.5; BB23 1.5,-20.5; BB24 2.5,-20.5; BB25 3.5,-20.5; BB26 4.5,-20.5; BB27 5.5,-20.5; BB28 6.5,-20.5; BB29 7.5,-20.5; BB30 8.5,-20.5; BB31 9.5,-20.5; BB32 10.5,-20.5; BB33 11.5,-20.5; BB34 12.5,-20.5; BB35 13.5,-20.5; BB36 14.5,-20.5; BB37 15.5,-20.5; BB38 16.5,-20.5; BB39 17.5,-20.5; BB40 18.5,-20.5; BB41 19.5,-20.5; C1 -20.5,18.5; C2 -19.5,18.5; C3 -18.5,18.5; C4 -17.5,18.5; C5 -16.5,18.5; C6 -15.5,18.5; C7 -14.5,18.5; C8 -13.5,18.5; C9 -12.5,18.5; C10 -11.5,18.5; C11 -10.5,18.5; C12 -9.5,18.5; C13 -8.5,18.5; C14 -7.5,18.5; C15 -6.5,18.5; C16 -5.5,18.5; C17 -4.5,18.5; C18 -3.5,18.5; C19 -2.5,18.5; C20 -1.5,18.5; C21 -0.5,18.5; C22 0.5,18.5; C23 1.5,18.5; C24 2.5,18.5; C25 3.5,18.5; C26 4.5,18.5; C27 5.5,18.5; C28 6.5,18.5; C29 7.5,18.5; C30 8.5,18.5; C31 9.5,18.5; C32 10.5,18.5; C33 11.5,18.5; C34 12.5,18.5; C35 13.5,18.5; C36 14.5,18.5; C37 15.5,18.5; C38 16.5,18.5; C39 17.5,18.5; C40 18.5,18.5; C41 19.5,18.5; C42 20.5,18.5; D1 -20.5,17.5; D2 -19.5,17.5; D3 -18.5,17.5; D4 -17.5,17.5; D5 -16.5,17.5; D6 -15.5,17.5; D7 -14.5,17.5; D8 -13.5,17.5; D9 -12.5,17.5; D10 -11.5,17.5; D11 -10.5,17.5; D12 -9.5,17.5; D13 -8.5,17.5; D14 -7.5,17.5; D15 -6.5,17.5; D16 -5.5,17.5; D17 -4.5,17.5; D18 -3.5,17.5; D19 -2.5,17.5; D20 -1.5,17.5; D21 -0.5,17.5; D22 0.5,17.5; D23 1.5,17.5; D24 2.5,17.5; D25 3.5,17.5; D26 4.5,17.5; D27 5.5,17.5; D28 6.5,17.5; D29 7.5,17.5; D30 8.5,17.5; D31 9.5,17.5; D32 10.5,17.5; D33 11.5,17.5; D34 12.5,17.5; D35 13.5,17.5; D36 14.5,17.5; D37 15.5,17.5; D38 16.5,17.5; D39 17.5,17.5; D40 18.5,17.5; D41 19.5,17.5; D42 20.5,17.5; E1 -20.5,16.5; E2 -19.5,16.5; E3 -18.5,16.5; E4 -17.5,16.5; E5 -16.5,16.5; E6 -15.5,16.5; E7 -14.5,16.5; E8 -13.5,16.5; E9 -12.5,16.5; E10 -11.5,16.5; E11 -10.5,16.5; E12 -9.5,16.5; E13 -8.5,16.5; E14 -7.5,16.5; E15 -6.5,16.5; E16 -5.5,16.5; E17 -4.5,16.5; E18 -3.5,16.5; E19 -2.5,16.5; E20 -1.5,16.5; E21 -0.5,16.5; E22 0.5,16.5; E23 1.5,16.5; E24 2.5,16.5; E25 3.5,16.5; E26 4.5,16.5; E27 5.5,16.5; E28 6.5,16.5; E29 7.5,16.5; E30 8.5,16.5; E31 9.5,16.5; E32 10.5,16.5; E33 11.5,16.5; E34 12.5,16.5; E35 13.5,16.5; E36 14.5,16.5; E37 15.5,16.5; E38 16.5,16.5; E39 17.5,16.5; E40 18.5,16.5; E41 19.5,16.5; E42 20.5,16.5; F1 -20.5,15.5; F2 -19.5,15.5; F3 -18.5,15.5; F4 -17.5,15.5; F5 -16.5,15.5; F6 -15.5,15.5; F7 -14.5,15.5; F8 -13.5,15.5; F9 -12.5,15.5; F10 -11.5,15.5; F11 -10.5,15.5; F12 -9.5,15.5; F13 -8.5,15.5; F14 -7.5,15.5; F15 -6.5,15.5; F16 -5.5,15.5; F17 -4.5,15.5; F18 -3.5,15.5; F19 -2.5,15.5; F20 -1.5,15.5; F21 -0.5,15.5; F22 0.5,15.5; F23 1.5,15.5; F24 2.5,15.5; F25 3.5,15.5; F26 4.5,15.5; F27 5.5,15.5; F28 6.5,15.5; F29 7.5,15.5; F30 8.5,15.5; F31 9.5,15.5; F32 10.5,15.5; F33 11.5,15.5; F34 12.5,15.5; F35 13.5,15.5; F36 14.5,15.5; F37 15.5,15.5; F38 16.5,15.5; F39 17.5,15.5; F40 18.5,15.5; F41 19.5,15.5; F42 20.5,15.5; G1 -20.5,14.5; G2 -19.5,14.5; G3 -18.5,14.5; G4 -17.5,14.5; G5 -16.5,14.5; G6 -15.5,14.5; G7 -14.5,14.5; G8 -13.5,14.5; G9 -12.5,14.5; G10 -11.5,14.5; G11 -10.5,14.5; G12 -9.5,14.5; G13 -8.5,14.5; G14 -7.5,14.5; G15 -6.5,14.5; G16 -5.5,14.5; G17 -4.5,14.5; G18 -3.5,14.5; G19 -2.5,14.5; G20 -1.5,14.5; G21 -0.5,14.5; G22 0.5,14.5; G23 1.5,14.5; G24 2.5,14.5; G25 3.5,14.5; G26 4.5,14.5; G27 5.5,14.5; G28 6.5,14.5; G29 7.5,14.5; G30 8.5,14.5; G31 9.5,14.5; G32 10.5,14.5; G33 11.5,14.5; G34 12.5,14.5; G35 13.5,14.5; G36 14.5,14.5; G37 15.5,14.5; G38 16.5,14.5; G39 17.5,14.5; G40 18.5,14.5; G41 19.5,14.5; G42 20.5,14.5; H1 -20.5,13.5; H2 -19.5,13.5; H3 -18.5,13.5; H4 -17.5,13.5; H5 -16.5,13.5; H6 -15.5,13.5; H7 -14.5,13.5; H8 -13.5,13.5; H9 -12.5,13.5; H10 -11.5,13.5; H11 -10.5,13.5; H12 -9.5,13.5; H13 -8.5,13.5; H14 -7.5,13.5; H15 -6.5,13.5; H16 -5.5,13.5; H17 -4.5,13.5; H18 -3.5,13.5; H19 -2.5,13.5; H20 -1.5,13.5; H21 -0.5,13.5; H22 0.5,13.5; H23 1.5,13.5; H24 2.5,13.5; H25 3.5,13.5; H26 4.5,13.5; H27 5.5,13.5; H28 6.5,13.5; H29 7.5,13.5; H30 8.5,13.5; H31 9.5,13.5; H32 10.5,13.5; H33 11.5,13.5; H34 12.5,13.5; H35 13.5,13.5; H36 14.5,13.5; H37 15.5,13.5; H38 16.5,13.5; H39 17.5,13.5; H40 18.5,13.5; H41 19.5,13.5; H42 20.5,13.5; J1 -20.5,12.5; J2 -19.5,12.5; J3 -18.5,12.5; J4 -17.5,12.5; J5 -16.5,12.5; J6 -15.5,12.5; J7 -14.5,12.5; J8 -13.5,12.5; J9 -12.5,12.5; J10 -11.5,12.5; J11 -10.5,12.5; J12 -9.5,12.5; J13 -8.5,12.5; J14 -7.5,12.5; J15 -6.5,12.5; J16 -5.5,12.5; J17 -4.5,12.5; J18 -3.5,12.5; J19 -2.5,12.5; J20 -1.5,12.5; J21 -0.5,12.5; J22 0.5,12.5; J23 1.5,12.5; J24 2.5,12.5; J25 3.5,12.5; J26 4.5,12.5; J27 5.5,12.5; J28 6.5,12.5; J29 7.5,12.5; J30 8.5,12.5; J31 9.5,12.5; J32 10.5,12.5; J33 11.5,12.5; J34 12.5,12.5; J35 13.5,12.5; J36 14.5,12.5; J37 15.5,12.5; J38 16.5,12.5; J39 17.5,12.5; J40 18.5,12.5; J41 19.5,12.5; J42 20.5,12.5; K1 -20.5,11.5; K2 -19.5,11.5; K3 -18.5,11.5; K4 -17.5,11.5; K5 -16.5,11.5; K6 -15.5,11.5; K7 -14.5,11.5; K8 -13.5,11.5; K9 -12.5,11.5; K10 -11.5,11.5; K11 -10.5,11.5; K12 -9.5,11.5; K13 -8.5,11.5; K14 -7.5,11.5; K15 -6.5,11.5; K16 -5.5,11.5; K17 -4.5,11.5; K18 -3.5,11.5; K19 -2.5,11.5; K20 -1.5,11.5; K21 -0.5,11.5; K22 0.5,11.5; K23 1.5,11.5; K24 2.5,11.5; K25 3.5,11.5; K26 4.5,11.5; K27 5.5,11.5; K28 6.5,11.5; K29 7.5,11.5; K30 8.5,11.5; K31 9.5,11.5; K32 10.5,11.5; K33 11.5,11.5; K34 12.5,11.5; K35 13.5,11.5; K36 14.5,11.5; K37 15.5,11.5; K38 16.5,11.5; K39 17.5,11.5; K40 18.5,11.5; K41 19.5,11.5; K42 20.5,11.5; L1 -20.5,10.5; L2 -19.5,10.5; L3 -18.5,10.5; L4 -17.5,10.5; L5 -16.5,10.5; L6 -15.5,10.5; L7 -14.5,10.5; L8 -13.5,10.5; L9 -12.5,10.5; L10 -11.5,10.5; L11 -10.5,10.5; L12 -9.5,10.5; L13 -8.5,10.5; L14 -7.5,10.5; L15 -6.5,10.5; L16 -5.5,10.5; L17 -4.5,10.5; L18 -3.5,10.5; L19 -2.5,10.5; L20 -1.5,10.5; L21 -0.5,10.5; L22 0.5,10.5; L23 1.5,10.5; L24 2.5,10.5; L25 3.5,10.5; L26 4.5,10.5; L27 5.5,10.5; L28 6.5,10.5; L29 7.5,10.5; L30 8.5,10.5; L31 9.5,10.5; L32 10.5,10.5; L33 11.5,10.5; L34 12.5,10.5; L35 13.5,10.5; L36 14.5,10.5; L37 15.5,10.5; L38 16.5,10.5; L39 17.5,10.5; L40 18.5,10.5; L41 19.5,10.5; L42 20.5,10.5; M1 -20.5,9.5; M2 -19.5,9.5; M3 -18.5,9.5; M4 -17.5,9.5; M5 -16.5,9.5; M6 -15.5,9.5; M7 -14.5,9.5; M8 -13.5,9.5; M9 -12.5,9.5; M10 -11.5,9.5; M11 -10.5,9.5; M12 -9.5,9.5; M13 -8.5,9.5; M14 -7.5,9.5; M15 -6.5,9.5; M16 -5.5,9.5; M17 -4.5,9.5; M18 -3.5,9.5; M19 -2.5,9.5; M20 -1.5,9.5; M21 -0.5,9.5; M22 0.5,9.5; M23 1.5,9.5; M24 2.5,9.5; M25 3.5,9.5; M26 4.5,9.5; M27 5.5,9.5; M28 6.5,9.5; M29 7.5,9.5; M30 8.5,9.5; M31 9.5,9.5; M32 10.5,9.5; M33 11.5,9.5; M34 12.5,9.5; M35 13.5,9.5; M36 14.5,9.5; M37 15.5,9.5; M38 16.5,9.5; M39 17.5,9.5; M40 18.5,9.5; M41 19.5,9.5; M42 20.5,9.5; N1 -20.5,8.5; N2 -19.5,8.5; N3 -18.5,8.5; N4 -17.5,8.5; N5 -16.5,8.5; N6 -15.5,8.5; N7 -14.5,8.5; N8 -13.5,8.5; N9 -12.5,8.5; N10 -11.5,8.5; N11 -10.5,8.5; N12 -9.5,8.5; N13 -8.5,8.5; N14 -7.5,8.5; N15 -6.5,8.5; N16 -5.5,8.5; N17 -4.5,8.5; N18 -3.5,8.5; N19 -2.5,8.5; N20 -1.5,8.5; N21 -0.5,8.5; N22 0.5,8.5; N23 1.5,8.5; N24 2.5,8.5; N25 3.5,8.5; N26 4.5,8.5; N27 5.5,8.5; N28 6.5,8.5; N29 7.5,8.5; N30 8.5,8.5; N31 9.5,8.5; N32 10.5,8.5; N33 11.5,8.5; N34 12.5,8.5; N35 13.5,8.5; N36 14.5,8.5; N37 15.5,8.5; N38 16.5,8.5; N39 17.5,8.5; N40 18.5,8.5; N41 19.5,8.5; N42 20.5,8.5; P1 -20.5,7.5; P2 -19.5,7.5; P3 -18.5,7.5; P4 -17.5,7.5; P5 -16.5,7.5; P6 -15.5,7.5; P7 -14.5,7.5; P8 -13.5,7.5; P9 -12.5,7.5; P10 -11.5,7.5; P11 -10.5,7.5; P12 -9.5,7.5; P13 -8.5,7.5; P14 -7.5,7.5; P15 -6.5,7.5; P16 -5.5,7.5; P17 -4.5,7.5; P18 -3.5,7.5; P19 -2.5,7.5; P20 -1.5,7.5; P21 -0.5,7.5; P22 0.5,7.5; P23 1.5,7.5; P24 2.5,7.5; P25 3.5,7.5; P26 4.5,7.5; P27 5.5,7.5; P28 6.5,7.5; P29 7.5,7.5; P30 8.5,7.5; P31 9.5,7.5; P32 10.5,7.5; P33 11.5,7.5; P34 12.5,7.5; P35 13.5,7.5; P36 14.5,7.5; P37 15.5,7.5; P38 16.5,7.5; P39 17.5,7.5; P40 18.5,7.5; P41 19.5,7.5; P42 20.5,7.5; R1 -20.5,6.5; R2 -19.5,6.5; R3 -18.5,6.5; R4 -17.5,6.5; R5 -16.5,6.5; R6 -15.5,6.5; R7 -14.5,6.5; R8 -13.5,6.5; R9 -12.5,6.5; R10 -11.5,6.5; R11 -10.5,6.5; R12 -9.5,6.5; R13 -8.5,6.5; R14 -7.5,6.5; R15 -6.5,6.5; R16 -5.5,6.5; R17 -4.5,6.5; R18 -3.5,6.5; R19 -2.5,6.5; R20 -1.5,6.5; R21 -0.5,6.5; R22 0.5,6.5; R23 1.5,6.5; R24 2.5,6.5; R25 3.5,6.5; R26 4.5,6.5; R27 5.5,6.5; R28 6.5,6.5; R29 7.5,6.5; R30 8.5,6.5; R31 9.5,6.5; R32 10.5,6.5; R33 11.5,6.5; R34 12.5,6.5; R35 13.5,6.5; R36 14.5,6.5; R37 15.5,6.5; R38 16.5,6.5; R39 17.5,6.5; R40 18.5,6.5; R41 19.5,6.5; R42 20.5,6.5; T1 -20.5,5.5; T2 -19.5,5.5; T3 -18.5,5.5; T4 -17.5,5.5; T5 -16.5,5.5; T6 -15.5,5.5; T7 -14.5,5.5; T8 -13.5,5.5; T9 -12.5,5.5; T10 -11.5,5.5; T11 -10.5,5.5; T12 -9.5,5.5; T13 -8.5,5.5; T14 -7.5,5.5; T15 -6.5,5.5; T16 -5.5,5.5; T17 -4.5,5.5; T18 -3.5,5.5; T19 -2.5,5.5; T20 -1.5,5.5; T21 -0.5,5.5; T22 0.5,5.5; T23 1.5,5.5; T24 2.5,5.5; T25 3.5,5.5; T26 4.5,5.5; T27 5.5,5.5; T28 6.5,5.5; T29 7.5,5.5; T30 8.5,5.5; T31 9.5,5.5; T32 10.5,5.5; T33 11.5,5.5; T34 12.5,5.5; T35 13.5,5.5; T36 14.5,5.5; T37 15.5,5.5; T38 16.5,5.5; T39 17.5,5.5; T40 18.5,5.5; T41 19.5,5.5; T42 20.5,5.5; U1 -20.5,4.5; U2 -19.5,4.5; U3 -18.5,4.5; U4 -17.5,4.5; U5 -16.5,4.5; U6 -15.5,4.5; U7 -14.5,4.5; U8 -13.5,4.5; U9 -12.5,4.5; U10 -11.5,4.5; U11 -10.5,4.5; U12 -9.5,4.5; U13 -8.5,4.5; U14 -7.5,4.5; U15 -6.5,4.5; U16 -5.5,4.5; U17 -4.5,4.5; U18 -3.5,4.5; U19 -2.5,4.5; U20 -1.5,4.5; U21 -0.5,4.5; U22 0.5,4.5; U23 1.5,4.5; U24 2.5,4.5; U25 3.5,4.5; U26 4.5,4.5; U27 5.5,4.5; U28 6.5,4.5; U29 7.5,4.5; U30 8.5,4.5; U31 9.5,4.5; U32 10.5,4.5; U33 11.5,4.5; U34 12.5,4.5; U35 13.5,4.5; U36 14.5,4.5; U37 15.5,4.5; U38 16.5,4.5; U39 17.5,4.5; U40 18.5,4.5; U41 19.5,4.5; U42 20.5,4.5; V1 -20.5,3.5; V2 -19.5,3.5; V3 -18.5,3.5; V4 -17.5,3.5; V5 -16.5,3.5; V6 -15.5,3.5; V7 -14.5,3.5; V8 -13.5,3.5; V9 -12.5,3.5; V10 -11.5,3.5; V11 -10.5,3.5; V12 -9.5,3.5; V13 -8.5,3.5; V14 -7.5,3.5; V15 -6.5,3.5; V16 -5.5,3.5; V17 -4.5,3.5; V18 -3.5,3.5; V19 -2.5,3.5; V20 -1.5,3.5; V21 -0.5,3.5; V22 0.5,3.5; V23 1.5,3.5; V24 2.5,3.5; V25 3.5,3.5; V26 4.5,3.5; V27 5.5,3.5; V28 6.5,3.5; V29 7.5,3.5; V30 8.5,3.5; V31 9.5,3.5; V32 10.5,3.5; V33 11.5,3.5; V34 12.5,3.5; V35 13.5,3.5; V36 14.5,3.5; V37 15.5,3.5; V38 16.5,3.5; V39 17.5,3.5; V40 18.5,3.5; V41 19.5,3.5; V42 20.5,3.5; W1 -20.5,2.5; W2 -19.5,2.5; W3 -18.5,2.5; W4 -17.5,2.5; W5 -16.5,2.5; W6 -15.5,2.5; W7 -14.5,2.5; W8 -13.5,2.5; W9 -12.5,2.5; W10 -11.5,2.5; W11 -10.5,2.5; W12 -9.5,2.5; W13 -8.5,2.5; W14 -7.5,2.5; W15 -6.5,2.5; W16 -5.5,2.5; W17 -4.5,2.5; W18 -3.5,2.5; W19 -2.5,2.5; W20 -1.5,2.5; W21 -0.5,2.5; W22 0.5,2.5; W23 1.5,2.5; W24 2.5,2.5; W25 3.5,2.5; W26 4.5,2.5; W27 5.5,2.5; W28 6.5,2.5; W29 7.5,2.5; W30 8.5,2.5; W31 9.5,2.5; W32 10.5,2.5; W33 11.5,2.5; W34 12.5,2.5; W35 13.5,2.5; W36 14.5,2.5; W37 15.5,2.5; W38 16.5,2.5; W39 17.5,2.5; W40 18.5,2.5; W41 19.5,2.5; W42 20.5,2.5; Y1 -20.5,1.5; Y2 -19.5,1.5; Y3 -18.5,1.5; Y4 -17.5,1.5; Y5 -16.5,1.5; Y6 -15.5,1.5; Y7 -14.5,1.5; Y8 -13.5,1.5; Y9 -12.5,1.5; Y10 -11.5,1.5; Y11 -10.5,1.5; Y12 -9.5,1.5; Y13 -8.5,1.5; Y14 -7.5,1.5; Y15 -6.5,1.5; Y16 -5.5,1.5; Y17 -4.5,1.5; Y18 -3.5,1.5; Y19 -2.5,1.5; Y20 -1.5,1.5; Y21 -0.5,1.5; Y22 0.5,1.5; Y23 1.5,1.5; Y24 2.5,1.5; Y25 3.5,1.5; Y26 4.5,1.5; Y27 5.5,1.5; Y28 6.5,1.5; Y29 7.5,1.5; Y30 8.5,1.5; Y31 9.5,1.5; Y32 10.5,1.5; Y33 11.5,1.5; Y34 12.5,1.5; Y35 13.5,1.5; Y36 14.5,1.5; Y37 15.5,1.5; Y38 16.5,1.5; Y39 17.5,1.5; Y40 18.5,1.5; Y41 19.5,1.5; Y42 20.5,1.5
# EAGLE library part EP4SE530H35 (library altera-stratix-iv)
EP4SE530H35 Auto generated by make-symbol-device-package-bsdl.ulp Rev. 29 Source: EP4SE530H35.bsd

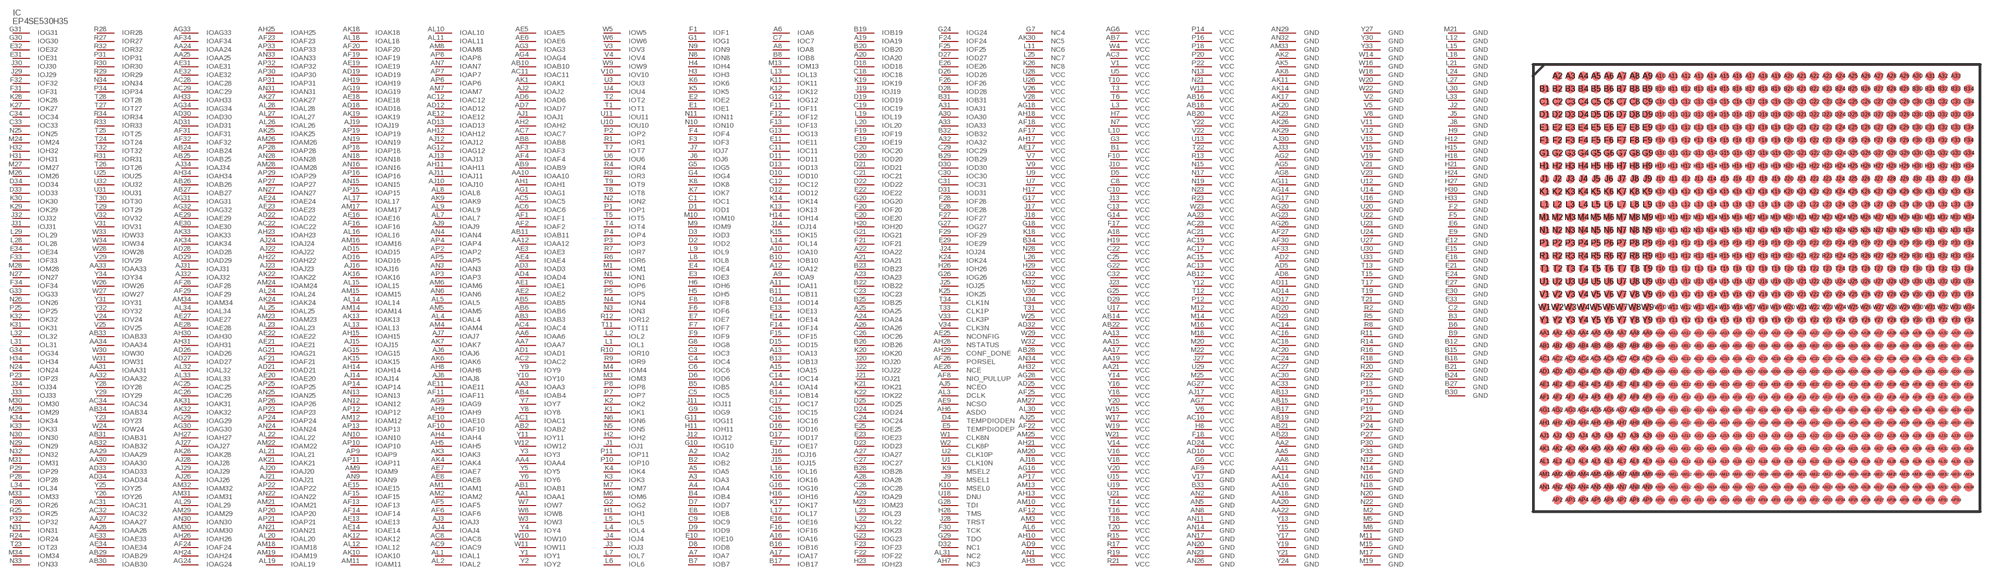
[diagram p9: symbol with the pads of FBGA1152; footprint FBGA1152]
Designator prefix IC

## EP4SE530H35 (MPN: EP4SE530H35C3N; OC_FARNELL: unknown; OC_NEWARK: 52R1723)  [FBGA1152]
A2  IOA2
A3  IOA3
A4  IOA4
A5  IOA5
A6  IOA6
A7  IOA7
A8  IOA8
A9  IOA9
A10  IOA10
A11  IOA11
A12  IOA12
A13  IOA13
A14  IOA14
A15  IOA15
A16  IOA16
A17  IOA17
A18  VCC  pwr
A19  IOA19
A20  IOA20
A21  IOA21
A22  IOA22
A23  IOA23
A24  IOA24
A25  IOA25
A26  IOA26
A27  IOA27
A28  IOA28
A29  IOA29
A30  IOA30
A31  IOA31
A32  IOA32
A33  IOA33
AA1  IOAA1
AA2  GND  pwr
AA3  IOAA3
AA4  IOAA4
AA5  GND  pwr
AA6  IOAA6
AA7  IOAA7
AA8  GND  pwr
AA10  IOAA10
AA11  GND  pwr
AA12  IOAA12
AA13  VCC  pwr
AA14  GND  pwr
AA15  VCC  pwr
AA16  GND  pwr
AA17  VCC  pwr
AA18  GND  pwr
AA19  VCC  pwr
AA20  GND  pwr
AA21  VCC  pwr
AA22  GND  pwr
AA23  VCC  pwr
AA24  IOAA24
AA25  IOAA25
AA27  IOAA27
AA28  IOAA28
AA29  IOAA29
AA30  IOAA30
AA31  IOAA31
AA32  IOAA32
AA33  IOAA33
AA34  IOAA34
AB1  IOAB1
AB2  IOAB2
AB3  IOAB3
AB4  IOAB4
AB5  IOAB5
AB6  IOAB6
AB7  VCC  pwr
AB8  IOAB8
AB9  IOAB9
AB10  IOAB10
AB11  IOAB11
AB12  VCC  pwr
AB13  GND  pwr
AB14  VCC  pwr
AB15  GND  pwr
AB16  VCC  pwr
AB17  GND  pwr
AB18  VCC  pwr
AB19  GND  pwr
AB20  VCC  pwr
AB21  GND  pwr
AB22  VCC  pwr
AB23  GND  pwr
AB24  IOAB24
AB25  IOAB25
AB26  IOAB26
AB27  IOAB27
AB28  VCC  pwr
AB29  IOAB29
AB30  IOAB30
AB31  IOAB31
AB32  IOAB32
AB33  IOAB33
AB34  IOAB34
AC1  IOAC1
AC2  IOAC2
AC3  VCC  pwr
AC4  IOAC4
AC5  IOAC5
AC6  IOAC6
AC7  IOAC7
AC8  IOAC8
AC9  IOAC9
AC10  VCC  pwr
AC11  IOAC11
AC12  IOAC12
AC13  VCC  pwr
AC14  GND  pwr
AC15  VCC  pwr
AC16  GND  pwr
AC17  VCC  pwr
AC18  GND  pwr
AC19  VCC  pwr
AC20  GND  pwr
AC21  VCC  pwr
AC22  IOAC22
AC23  VCC  pwr
AC24  GND  pwr
AC25  IOAC25
AC26  IOAC26
AC27  GND  pwr
AC28  IOAC28
AC29  IOAC29
AC30  GND  pwr
AC31  IOAC31
AC32  IOAC32
AC33  GND  pwr
AC34  IOAC34
AD1  IOAD1
AD2  GND  pwr
AD3  IOAD3
AD4  IOAD4
AD5  GND  pwr
AD6  IOAD6
AD7  IOAD7
AD8  GND  pwr
AD9  VCC  pwr
AD10  VCC  pwr
AD11  GND  pwr
AD12  IOAD12
AD13  IOAD13
AD14  GND  pwr
AD15  IOAD15
AD16  IOAD16
AD17  GND  pwr
AD18  IOAD18
AD19  IOAD19
AD20  GND  pwr
AD21  IOAD21
AD22  IOAD22
AD23  GND  pwr
AD24  VCC  pwr
AD25  VCC  pwr
AD26  IOAD26
AD27  IOAD27
AD28  IOAD28
AD29  IOAD29
AD30  IOAD30
AD31  IOAD31
AD32  VCC  pwr
AD33  IOAD33
AD34  IOAD34
AE1  IOAE1
AE2  IOAE2
AE3  IOAE3
AE4  IOAE4
AE5  IOAE5
AE6  IOAE6
AE7  IOAE7
AE8  IOAE8
AE9  NCSO  in
AE10  IOAE10
AE11  IOAE11
AE12  IOAE12
AE13  IOAE13
AE14  IOAE14
AE15  IOAE15
AE16  IOAE16
AE17  VCC  pwr
AE18  IOAE18
AE19  IOAE19
AE20  IOAE20
AE21  IOAE21
AE22  IOAE22
AE23  IOAE23
AE24  IOAE24
AE25  NCONFIG  in
AE26  NCE  in
AE27  IOAE27
AE28  IOAE28
AE29  IOAE29
AE30  IOAE30
AE31  IOAE31
AE32  IOAE32
AE33  IOAE33
AE34  IOAE34
AF1  IOAF1
AF2  IOAF2
AF3  IOAF3
AF4  IOAF4
AF5  IOAF5
AF6  IOAF6
AF8  NIO_PULLUP  in
AF9  GND  pwr
AF10  IOAF10
AF11  IOAF11
AF12  VCC  pwr
AF13  IOAF13
AF14  IOAF14
AF15  IOAF15
AF16  IOAF16
AF17  VCC  pwr
AF18  VCC  pwr
AF19  IOAF19
AF20  IOAF20
AF21  IOAF21
AF22  VCC  pwr
AF23  IOAF23
AF24  IOAF24
AF25  VCC  pwr
AF26  PORSEL  in
AF27  GND  pwr
AF28  IOAF28
AF29  IOAF29
AF30  GND  pwr
AF31  IOAF31
AF32  IOAF32
AF33  GND  pwr
AF34  IOAF34
AG1  IOAG1
AG2  GND  pwr
AG3  IOAG3
AG4  IOAG4
AG5  GND  pwr
AG6  VCC  pwr
AG7  VCC  pwr
AG8  GND  pwr
AG9  IOAG9
AG11  GND  pwr
AG12  IOAG12
AG14  GND  pwr
AG15  IOAG15
AG16  VCC  pwr
AG17  GND  pwr
AG18  VCC  pwr
AG19  IOAG19
AG20  GND  pwr
AG21  IOAG21
AG23  GND  pwr
AG24  IOAG24
AG26  GND  pwr
AG27  VCC  pwr
AG28  VCC  pwr
AG29  IOAG29
AG30  IOAG30
AG31  IOAG31
AG32  IOAG32
AG33  IOAG33
AG34  IOAG34
AH1  IOAH1
AH2  IOAH2
AH3  VCC  pwr
AH4  IOAH4
AH5  IOAH5
AH6  ASDO  in
AH7  NC3  pas
AH8  IOAH8
AH9  IOAH9
AH10  VCC  pwr
AH11  IOAH11
AH12  IOAH12
AH13  VCC  pwr
AH14  IOAH14
AH15  IOAH15
AH17  VCC  pwr
AH18  VCC  pwr
AH19  IOAH19
AH21  VCC  pwr
AH22  IOAH22
AH23  IOAH23
AH24  IOAH24
AH25  IOAH25
AH26  IOAH26
AH27  IOAH27
AH28  NSTATUS  in
AH29  CONF_DONE  in
AH30  IOAH30
AH31  IOAH31
AH32  VCC  pwr
AH33  IOAH33
AH34  IOAH34
AJ1  IOAJ1
AJ2  IOAJ2
AJ3  IOAJ3
AJ4  IOAJ4
AJ5  NCEO  in
AJ6  IOAJ6
AJ7  IOAJ7
AJ8  IOAJ8
AJ9  IOAJ9
AJ10  IOAJ10
AJ11  IOAJ11
AJ12  IOAJ12
AJ13  IOAJ13
AJ14  IOAJ14
AJ15  IOAJ15
AJ16  IOAJ16
AJ17  VCC  pwr
AJ18  VCC  pwr
AJ19  IOAJ19
AJ20  IOAJ20
AJ21  IOAJ21
AJ22  IOAJ22
AJ23  IOAJ23
AJ24  IOAJ24
AJ25  VCC  pwr
AJ26  IOAJ26
AJ27  IOAJ27
AJ28  IOAJ28
AJ29  IOAJ29
AJ30  GND  pwr
AJ31  IOAJ31
AJ32  IOAJ32
AJ33  GND  pwr
AJ34  IOAJ34
AK1  IOAK1
AK2  GND  pwr
AK3  IOAK3
AK4  IOAK4
AK5  GND  pwr
AK6  IOAK6
AK7  IOAK7
AK8  GND  pwr
AK9  IOAK9
AK10  IOAK10
AK11  GND  pwr
AK12  IOAK12
AK13  IOAK13
AK14  GND  pwr
AK15  IOAK15
AK16  IOAK16
AK17  GND  pwr
AK18  IOAK18
AK19  IOAK19
AK20  GND  pwr
AK21  IOAK21
AK22  IOAK22
AK23  GND  pwr
AK24  IOAK24
AK25  IOAK25
AK26  GND  pwr
AK27  IOAK27
AK28  IOAK28
AK29  GND  pwr
AK30  NC5  pas
AK31  IOAK31
AK32  IOAK32
AK33  IOAK33
AK34  IOAK34
AL1  IOAL1
AL2  IOAL2
AL3  DCLK  in
AL4  IOAL4
AL5  IOAL5
AL6  VCC  pwr
AL7  IOAL7
AL8  IOAL8
AL9  IOAL9
AL10  IOAL10
AL11  IOAL11
AL12  IOAL12
AL13  IOAL13
AL14  IOAL14
AL15  IOAL15
AL16  IOAL16
AL17  IOAL17
AL18  IOAL18
AL19  IOAL19
AL20  IOAL20
AL21  IOAL21
AL22  IOAL22
AL23  IOAL23
AL24  IOAL24
AL25  IOAL25
AL26  IOAL26
AL27  IOAL27
AL28  IOAL28
AL29  IOAL29
AL30  VCC  pwr
AL31  NC2  pas
AL32  IOAL32
AL33  IOAL33
AL34  IOAL34
AM1  IOAM1
AM2  IOAM2
AM3  VCC  pwr
AM4  IOAM4
AM5  IOAM5
AM6  IOAM6
AM7  IOAM7
AM8  IOAM8
AM9  IOAM9
AM10  VCC  pwr
AM11  IOAM11
AM12  IOAM12
AM13  VCC  pwr
AM14  IOAM14
AM15  IOAM15
AM16  IOAM16
AM17  IOAM17
AM18  IOAM18
AM19  IOAM19
AM20  VCC  pwr
AM21  IOAM21
AM22  IOAM22
AM23  IOAM23
AM24  IOAM24
AM25  VCC  pwr
AM26  IOAM26
AM27  VCC  pwr
AM28  IOAM28
AM29  IOAM29
AM30  IOAM30
AM31  IOAM31
AM32  IOAM32
AM33  GND  pwr
AM34  IOAM34
AN1  VCC  pwr
AN2  GND  pwr
AN3  IOAN3
AN4  IOAN4
AN5  GND  pwr
AN6  IOAN6
AN7  IOAN7
AN8  GND  pwr
AN9  IOAN9
AN10  IOAN10
AN11  GND  pwr
AN12  IOAN12
AN13  IOAN13
AN14  GND  pwr
AN15  IOAN15
AN16  IOAN16
AN17  GND  pwr
AN18  IOAN18
AN19  IOAN19
AN20  GND  pwr
AN21  IOAN21
AN22  IOAN22
AN23  GND  pwr
AN24  IOAN24
AN25  IOAN25
AN26  GND  pwr
AN27  IOAN27
AN28  IOAN28
AN29  GND  pwr
AN30  IOAN30
AN31  IOAN31
AN32  GND  pwr
AN33  IOAN33
AN34  VCC  pwr
AP2  IOAP2
AP3  IOAP3
AP4  IOAP4
AP5  IOAP5
AP6  IOAP6
AP7  IOAP7
AP8  IOAP8
AP9  IOAP9
AP10  IOAP10
AP11  IOAP11
AP12  IOAP12
AP13  IOAP13
AP14  IOAP14
AP15  IOAP15
AP16  IOAP16
AP17  VCC  pwr
AP18  IOAP18
AP19  IOAP19
AP20  IOAP20
AP21  IOAP21
AP22  IOAP22
AP23  IOAP23
AP24  IOAP24
AP25  IOAP25
AP26  IOAP26
AP27  IOAP27
AP28  IOAP28
AP29  IOAP29
AP30  IOAP30
AP31  IOAP31
AP32  IOAP32
AP33  IOAP33
B1  VCC  pwr
B2  IOB2
B3  GND  pwr
B4  IOB4
B5  IOB5
B6  GND  pwr
B7  IOB7
B8  IOB8
B9  GND  pwr
B10  IOB10
B11  IOB11
B12  GND  pwr
B13  IOB13
B14  IOB14
B15  GND  pwr
B16  IOB16
B17  IOB17
B18  GND  pwr
B19  IOB19
B20  IOB20
B21  GND  pwr
B22  IOB22
B23  IOB23
B24  GND  pwr
B25  IOB25
B26  IOB26
B27  GND  pwr
B28  IOB28
B29  IOB29
B30  GND  pwr
B31  IOB31
B32  IOB32
B33  GND  pwr
B34  VCC  pwr
C1  IOC1
C2  GND  pwr
C3  IOC3
C4  IOC4
C5  IOC5
C6  IOC6
C7  IOC7
C8  VCC  pwr
C9  IOC9
C10  VCC  pwr
C11  IOC11
C12  IOC12
C13  VCC  pwr
C14  IOC14
C15  IOC15
C16  IOC16
C17  IOC17
C18  IOC18
C19  IOC19
C20  IOC20
C21  IOC21
C22  VCC  pwr
C23  IOC23
C24  IOC24
C25  VCC  pwr
C26  IOC26
C27  IOC27
C28  IOC28
C29  IOC29
C30  IOC30
C31  IOC31
C32  VCC  pwr
C33  IOC33
C34  IOC34
D1  IOD1
D2  IOD2
D3  IOD3
D4  TEMPDIODEN  in
D5  VCC  pwr
D6  IOD6
D7  IOD7
D8  IOD8
D9  IOD9
D10  IOD10
D11  IOD11
D12  IOD12
D13  IOD13
D14  IOD14
D15  IOD15
D16  IOD16
D17  IOD17
D18  IOD18
D19  IOD19
D20  IOD20
D21  IOD21
D22  IOD22
D23  IOD23
D24  IOD24
D25  IOD25
D26  IOD26
D27  IOD27
D28  IOD28
D29  VCC  pwr
D30  IOD30
D31  IOD31
D32  NC1  pas
D33  IOD33
D34  IOD34
E1  IOE1
E2  IOE2
E3  IOE3
E4  IOE4
E5  TEMPDIODEP  in
E6  GND  pwr
E7  IOE7
E8  IOE8
E9  GND  pwr
E10  IOE10
E11  IOE11
E12  GND  pwr
E13  IOE13
E14  IOE14
E15  GND  pwr
E16  IOE16
E17  IOE17
E18  GND  pwr
E19  IOE19
E20  IOE20
E21  GND  pwr
E22  IOE22
E23  IOE23
E24  GND  pwr
E25  IOE25
E26  IOE26
E27  GND  pwr
E28  IOE28
E29  IOE29
E30  GND  pwr
E31  IOE31
E32  IOE32
E33  GND  pwr
E34  IOE34
F1  IOF1
F2  GND  pwr
F3  IOF3
F4  IOF4
F5  GND  pwr
F6  IOF6
F7  IOF7
F8  IOF8
F9  IOF9
F10  VCC  pwr
F11  IOF11
F12  IOF12
F13  IOF13
F14  IOF14
F15  IOF15
F16  IOF16
F17  VCC  pwr
F18  VCC  pwr
F19  IOF19
F20  IOF20
F21  IOF21
F22  IOF22
F23  IOF23
F24  IOF24
F25  IOF25
F26  IOF26
F27  IOF27
F28  IOF28
F29  IOF29
F30  TCK  in
F31  IOF31
F32  IOF32
F33  IOF33
F34  IOF34
G1  IOG1
G2  IOG2
G3  VCC  pwr
G4  IOG4
G5  IOG5
G6  VCC  pwr
G7  NC4  pas
G8  IOG8
G9  IOG9
G10  IOG10
G11  IOG11
G12  IOG12
G13  IOG13
G14  VCC  pwr
G16  IOG16
G17  VCC  pwr
G18  VCC  pwr
G20  IOG20
G21  IOG21
G22  VCC  pwr
G23  IOG23
G24  IOG24
G25  VCC  pwr
G26  IOG26
G27  IOG27
G28  TDI  in
G29  TDO  out
G30  IOG30
G31  IOG31
G32  VCC  pwr
G33  IOG33
G34  IOG34
H1  IOH1
H2  IOH2
H3  IOH3
H4  IOH4
H5  IOH5
H6  IOH6
H7  VCC  pwr
H8  VCC  pwr
H9  GND  pwr
H11  IOH11
H12  GND  pwr
H14  IOH14
H15  GND  pwr
H16  IOH16
H17  VCC  pwr
H18  GND  pwr
H19  VCC  pwr
H20  IOH20
H21  GND  pwr
H23  IOH23
H24  GND  pwr
H26  IOH26
H27  GND  pwr
H28  TMS  in
H29  VCC  pwr
H30  GND  pwr
H31  IOH31
H32  IOH32
H33  GND  pwr
H34  IOH34
J1  IOJ1
J2  GND  pwr
J3  IOJ3
J4  IOJ4
J5  GND  pwr
J6  IOJ6
J7  IOJ7
J8  GND  pwr
J9  MSEL1  in
J10  VCC  pwr
J11  IOJ11
J12  IOJ12
J13  VCC  pwr
J14  IOJ14
J15  IOJ15
J16  IOJ16
J17  VCC  pwr
J18  VCC  pwr
J19  IOJ19
J20  IOJ20
J21  IOJ21
J22  IOJ22
J23  VCC  pwr
J24  IOJ24
J25  IOJ25
J27  VCC  pwr
J28  TRST  in
J29  IOJ29
J30  IOJ30
J31  IOJ31
J32  IOJ32
J33  IOJ33
J34  IOJ34
K1  IOK1
K2  IOK2
K3  IOK3
K4  IOK4
K5  IOK5
K6  IOK6
K7  IOK7
K8  IOK8
K9  MSEL2  in
K10  MSEL0  in
K11  IOK11
K12  IOK12
K13  IOK13
K14  IOK14
K15  IOK15
K16  IOK16
K17  IOK17
K18  VCC  pwr
K19  IOK19
K20  IOK20
K21  IOK21
K22  IOK22
K23  IOK23
K24  IOK24
K25  IOK25
K26  NC8  pas
K27  IOK27
K28  IOK28
K29  IOK29
K30  IOK30
K31  IOK31
K32  IOK32
K33  IOK33
K34  IOK34
L1  IOL1
L2  IOL2
L3  VCC  pwr
L4  IOL4
L5  IOL5
L6  IOL6
L7  IOL7
L8  IOL8
L9  IOL9
L10  VCC  pwr
L11  NC6  pas
L12  GND  pwr
L13  IOL13
L14  IOL14
L15  GND  pwr
L16  IOL16
L17  IOL17
L18  GND  pwr
L19  IOL19
L20  IOL20
L21  GND  pwr
L22  IOL22
L23  IOL23
L24  GND  pwr
L25  NC7  pas
L26  VCC  pwr
L27  GND  pwr
L28  IOL28
L29  IOL29
L30  GND  pwr
L31  IOL31
L32  IOL32
L33  GND  pwr
L34  IOL34
M1  IOM1
M2  GND  pwr
M3  IOM3
M4  IOM4
M5  GND  pwr
M6  IOM6
M7  IOM7
M8  GND  pwr
M9  IOM9
M10  IOM10
M11  GND  pwr
M12  VCC  pwr
M13  IOM13
M14  VCC  pwr
M15  GND  pwr
M16  VCC  pwr
M17  GND  pwr
M18  VCC  pwr
M19  GND  pwr
M20  VCC  pwr
M21  GND  pwr
M22  VCC  pwr
M23  IOM23
M24  IOM24
M25  VCC  pwr
M26  IOM26
M27  IOM27
M28  IOM28
M29  IOM29
M30  IOM30
M31  IOM31
M32  VCC  pwr
M33  IOM33
M34  IOM34
N1  ION1
N2  ION2
N3  ION3
N4  ION4
N5  ION5
N6  ION6
N7  VCC  pwr
N8  ION8
N9  ION9
N10  ION10
N11  ION11
N12  GND  pwr
N13  VCC  pwr
N14  GND  pwr
N15  VCC  pwr
N16  GND  pwr
N17  VCC  pwr
N18  GND  pwr
N19  VCC  pwr
N20  GND  pwr
N21  VCC  pwr
N22  GND  pwr
N23  VCC  pwr
N24  ION24
N25  ION25
N26  ION26
N27  ION27
N28  VCC  pwr
N29  ION29
N30  ION30
N31  ION31
N32  ION32
N33  ION33
N34  ION34
P1  IOP1
P2  IOP2
P3  IOP3
P4  IOP4
P5  IOP5
P6  IOP6
P7  IOP7
P8  IOP8
P10  IOP10
P11  IOP11
P12  VCC  pwr
P13  GND  pwr
P14  VCC  pwr
P15  GND  pwr
P16  VCC  pwr
P17  GND  pwr
P18  VCC  pwr
P19  GND  pwr
P20  VCC  pwr
P21  GND  pwr
P22  VCC  pwr
P23  IOP23
P24  GND  pwr
P25  IOP25
P27  GND  pwr
P28  IOP28
P29  IOP29
P30  GND  pwr
P31  IOP31
P32  IOP32
P33  GND  pwr
P34  IOP34
R1  IOR1
R2  GND  pwr
R3  IOR3
R4  IOR4
R5  GND  pwr
R6  IOR6
R7  IOR7
R8  GND  pwr
R9  IOR9
R10  IOR10
R11  GND  pwr
R12  IOR12
R13  VCC  pwr
R14  GND  pwr
R15  VCC  pwr
R16  GND  pwr
R17  VCC  pwr
R18  GND  pwr
R19  VCC  pwr
R20  GND  pwr
R21  VCC  pwr
R22  GND  pwr
R23  VCC  pwr
R24  IOR24
R25  IOR25
R26  IOR26
R27  IOR27
R28  IOR28
R29  IOR29
R30  IOR30
R31  IOR31
R32  IOR32
R33  IOR33
R34  IOR34
T1  IOT1
T2  IOT2
T3  VCC  pwr
T4  IOT4
T5  IOT5
T6  VCC  pwr
T7  IOT7
T8  IOT8
T9  IOT9
T10  VCC  pwr
T11  IOT11
T12  VCC  pwr
T13  GND  pwr
T14  VCC  pwr
T15  GND  pwr
T16  VCC  pwr
T17  GND  pwr
T18  VCC  pwr
T19  GND  pwr
T20  VCC  pwr
T21  GND  pwr
T22  VCC  pwr
T23  IOT23
T24  IOT24
T25  IOT25
T26  IOT26
T27  IOT27
T28  IOT28
T29  IOT29
T30  IOT30
T31  VCC  pwr
T32  IOT32
T33  CLK1P  in
T34  CLK1N  in
U1  CLK10N  in
U2  CLK10P  in
U3  IOU3
U4  IOU4
U5  VCC  pwr
U6  IOU6
U7  VCC  pwr
U9  VCC  pwr
U10  IOU10
U11  IOU11
U12  GND  pwr
U13  VCC  pwr
U14  GND  pwr
U15  VCC  pwr
U16  GND  pwr
U17  VCC  pwr
U18  DNU  pas
U19  VCC  pwr
U20  GND  pwr
U21  VCC  pwr
U22  GND  pwr
U23  GND  pwr
U24  GND  pwr
U25  IOU25
U26  VCC  pwr
U27  GND  pwr
U28  VCC  pwr
U29  VCC  pwr
U30  GND  pwr
U31  IOU31
U32  IOU32
U33  GND  pwr
U34  VCC  pwr
V1  VCC  pwr
V2  GND  pwr
V3  IOV3
V4  IOV4
V5  GND  pwr
V6  VCC  pwr
V7  VCC  pwr
V8  GND  pwr
V9  VCC  pwr
V10  IOV10
V11  GND  pwr
V12  GND  pwr
V13  GND  pwr
V14  VCC  pwr
V15  GND  pwr
V16  VCC  pwr
V17  GND  pwr
V18  VCC  pwr
V19  GND  pwr
V20  VCC  pwr
V21  GND  pwr
V22  VCC  pwr
V23  GND  pwr
V24  IOV24
V25  IOV25
V26  VCC  pwr
V28  VCC  pwr
V29  IOV29
V30  VCC  pwr
V31  IOV31
V32  IOV32
V33  CLK3P  in
V34  CLK3N  in
W1  CLK8N  in
W2  CLK8P  in
W3  IOW3
W4  VCC  pwr
W5  IOW5
W6  IOW6
W7  IOW7
W8  IOW8
W9  IOW9
W10  IOW10
W11  IOW11
W12  IOW12
W13  VCC  pwr
W14  GND  pwr
W15  VCC  pwr
W16  GND  pwr
W17  VCC  pwr
W18  GND  pwr
W19  VCC  pwr
W20  GND  pwr
W21  VCC  pwr
W22  GND  pwr
W23  VCC  pwr
W24  IOW24
W25  VCC  pwr
W26  IOW26
W27  IOW27
W28  IOW28
W29  VCC  pwr
W30  IOW30
W31  IOW31
W32  VCC  pwr
W33  IOW33
W34  IOW34
Y1  IOY1
Y2  IOY2
Y3  IOY3
Y4  IOY4
Y5  IOY5
Y6  IOY6
Y7  IOY7
Y8  IOY8
Y9  IOY9
Y10  IOY10
Y11  IOY11
Y12  VCC  pwr
Y13  GND  pwr
Y14  VCC  pwr
Y15  GND  pwr
Y16  VCC  pwr
Y17  GND  pwr
Y18  VCC  pwr
Y19  GND  pwr
Y20  VCC  pwr
Y21  GND  pwr
Y22  VCC  pwr
Y23  IOY23
Y24  GND  pwr
Y25  IOY25
Y26  IOY26
Y27  GND  pwr
Y28  IOY28
Y29  IOY29
Y30  GND  pwr
Y31  IOY31
Y32  IOY32
Y33  GND  pwr
Y34  IOY34

## Footprint FBGA1152 (pad centres in mm)
1152-Pin FineLine Ball-Grid Array (FBGA), Option 1 - Flip Chip Auto generated by make-symbol-device-package-bsdl.ulp Rev. 29 Source: EP4SE360F35.bsd http://www.altera.com .. dspkg.pdf
smd 0.7 x 0.7: A2 -15.5,16.5; A3 -14.5,16.5; A4 -13.5,16.5; A5 -12.5,16.5; A6 -11.5,16.5; A7 -10.5,16.5; A8 -9.5,16.5; A9 -8.5,16.5; A10 -7.5,16.5; A11 -6.5,16.5; A12 -5.5,16.5; A13 -4.5,16.5; A14 -3.5,16.5; A15 -2.5,16.5; A16 -1.5,16.5; A17 -0.5,16.5; A18 0.5,16.5; A19 1.5,16.5; A20 2.5,16.5; A21 3.5,16.5; A22 4.5,16.5; A23 5.5,16.5; A24 6.5,16.5; A25 7.5,16.5; A26 8.5,16.5; A27 9.5,16.5; A28 10.5,16.5; A29 11.5,16.5; A30 12.5,16.5; A31 13.5,16.5; A32 14.5,16.5; A33 15.5,16.5; AA1 -16.5,-3.5; AA2 -15.5,-3.5; AA3 -14.5,-3.5; AA4 -13.5,-3.5; AA5 -12.5,-3.5; AA6 -11.5,-3.5; AA7 -10.5,-3.5; AA8 -9.5,-3.5; AA9 -8.5,-3.5; AA10 -7.5,-3.5; AA11 -6.5,-3.5; AA12 -5.5,-3.5; AA13 -4.5,-3.5; AA14 -3.5,-3.5; AA15 -2.5,-3.5; AA16 -1.5,-3.5; AA17 -0.5,-3.5; AA18 0.5,-3.5; AA19 1.5,-3.5; AA20 2.5,-3.5; AA21 3.5,-3.5; AA22 4.5,-3.5; AA23 5.5,-3.5; AA24 6.5,-3.5; AA25 7.5,-3.5; AA26 8.5,-3.5; AA27 9.5,-3.5; AA28 10.5,-3.5; AA29 11.5,-3.5; AA30 12.5,-3.5; AA31 13.5,-3.5; AA32 14.5,-3.5; AA33 15.5,-3.5; AA34 16.5,-3.5; AB1 -16.5,-4.5; AB2 -15.5,-4.5; AB3 -14.5,-4.5; AB4 -13.5,-4.5; AB5 -12.5,-4.5; AB6 -11.5,-4.5; AB7 -10.5,-4.5; AB8 -9.5,-4.5; AB9 -8.5,-4.5; AB10 -7.5,-4.5; AB11 -6.5,-4.5; AB12 -5.5,-4.5; AB13 -4.5,-4.5; AB14 -3.5,-4.5; AB15 -2.5,-4.5; AB16 -1.5,-4.5; AB17 -0.5,-4.5; AB18 0.5,-4.5; AB19 1.5,-4.5; AB20 2.5,-4.5; AB21 3.5,-4.5; AB22 4.5,-4.5; AB23 5.5,-4.5; AB24 6.5,-4.5; AB25 7.5,-4.5; AB26 8.5,-4.5; AB27 9.5,-4.5; AB28 10.5,-4.5; AB29 11.5,-4.5; AB30 12.5,-4.5; AB31 13.5,-4.5; AB32 14.5,-4.5; AB33 15.5,-4.5; AB34 16.5,-4.5; AC1 -16.5,-5.5; AC2 -15.5,-5.5; AC3 -14.5,-5.5; AC4 -13.5,-5.5; AC5 -12.5,-5.5; AC6 -11.5,-5.5; AC7 -10.5,-5.5; AC8 -9.5,-5.5; AC9 -8.5,-5.5; AC10 -7.5,-5.5; AC11 -6.5,-5.5; AC12 -5.5,-5.5; AC13 -4.5,-5.5; AC14 -3.5,-5.5; AC15 -2.5,-5.5; AC16 -1.5,-5.5; AC17 -0.5,-5.5; AC18 0.5,-5.5; AC19 1.5,-5.5; AC20 2.5,-5.5; AC21 3.5,-5.5; AC22 4.5,-5.5; AC23 5.5,-5.5; AC24 6.5,-5.5; AC25 7.5,-5.5; AC26 8.5,-5.5; AC27 9.5,-5.5; AC28 10.5,-5.5; AC29 11.5,-5.5; AC30 12.5,-5.5; AC31 13.5,-5.5; AC32 14.5,-5.5; AC33 15.5,-5.5; AC34 16.5,-5.5; AD1 -16.5,-6.5; AD2 -15.5,-6.5; AD3 -14.5,-6.5; AD4 -13.5,-6.5; AD5 -12.5,-6.5; AD6 -11.5,-6.5; AD7 -10.5,-6.5; AD8 -9.5,-6.5; AD9 -8.5,-6.5; AD10 -7.5,-6.5; AD11 -6.5,-6.5; AD12 -5.5,-6.5; AD13 -4.5,-6.5; AD14 -3.5,-6.5; AD15 -2.5,-6.5; AD16 -1.5,-6.5; AD17 -0.5,-6.5; AD18 0.5,-6.5; AD19 1.5,-6.5; AD20 2.5,-6.5; AD21 3.5,-6.5; AD22 4.5,-6.5; AD23 5.5,-6.5; AD24 6.5,-6.5; AD25 7.5,-6.5; AD26 8.5,-6.5; AD27 9.5,-6.5; AD28 10.5,-6.5; AD29 11.5,-6.5; AD30 12.5,-6.5; AD31 13.5,-6.5; AD32 14.5,-6.5; AD33 15.5,-6.5; AD34 16.5,-6.5; AE1 -16.5,-7.5; AE2 -15.5,-7.5; AE3 -14.5,-7.5; AE4 -13.5,-7.5; AE5 -12.5,-7.5; AE6 -11.5,-7.5; AE7 -10.5,-7.5; AE8 -9.5,-7.5; AE9 -8.5,-7.5; AE10 -7.5,-7.5; AE11 -6.5,-7.5; AE12 -5.5,-7.5; AE13 -4.5,-7.5; AE14 -3.5,-7.5; AE15 -2.5,-7.5; AE16 -1.5,-7.5; AE17 -0.5,-7.5; AE18 0.5,-7.5; AE19 1.5,-7.5; AE20 2.5,-7.5; AE21 3.5,-7.5; AE22 4.5,-7.5; AE23 5.5,-7.5; AE24 6.5,-7.5; AE25 7.5,-7.5; AE26 8.5,-7.5; AE27 9.5,-7.5; AE28 10.5,-7.5; AE29 11.5,-7.5; AE30 12.5,-7.5; AE31 13.5,-7.5; AE32 14.5,-7.5; AE33 15.5,-7.5; AE34 16.5,-7.5; AF1 -16.5,-8.5; AF2 -15.5,-8.5; AF3 -14.5,-8.5; AF4 -13.5,-8.5; AF5 -12.5,-8.5; AF6 -11.5,-8.5; AF7 -10.5,-8.5; AF8 -9.5,-8.5; AF9 -8.5,-8.5; AF10 -7.5,-8.5; AF11 -6.5,-8.5; AF12 -5.5,-8.5; AF13 -4.5,-8.5; AF14 -3.5,-8.5; AF15 -2.5,-8.5; AF16 -1.5,-8.5; AF17 -0.5,-8.5; AF18 0.5,-8.5; AF19 1.5,-8.5; AF20 2.5,-8.5; AF21 3.5,-8.5; AF22 4.5,-8.5; AF23 5.5,-8.5; AF24 6.5,-8.5; AF25 7.5,-8.5; AF26 8.5,-8.5; AF27 9.5,-8.5; AF28 10.5,-8.5; AF29 11.5,-8.5; AF30 12.5,-8.5; AF31 13.5,-8.5; AF32 14.5,-8.5; AF33 15.5,-8.5; AF34 16.5,-8.5; AG1 -16.5,-9.5; AG2 -15.5,-9.5; AG3 -14.5,-9.5; AG4 -13.5,-9.5; AG5 -12.5,-9.5; AG6 -11.5,-9.5; AG7 -10.5,-9.5; AG8 -9.5,-9.5; AG9 -8.5,-9.5; AG10 -7.5,-9.5; AG11 -6.5,-9.5; AG12 -5.5,-9.5; AG13 -4.5,-9.5; AG14 -3.5,-9.5; AG15 -2.5,-9.5; AG16 -1.5,-9.5; AG17 -0.5,-9.5; AG18 0.5,-9.5; AG19 1.5,-9.5; AG20 2.5,-9.5; AG21 3.5,-9.5; AG22 4.5,-9.5; AG23 5.5,-9.5; AG24 6.5,-9.5; AG25 7.5,-9.5; AG26 8.5,-9.5; AG27 9.5,-9.5; AG28 10.5,-9.5; AG29 11.5,-9.5; AG30 12.5,-9.5; AG31 13.5,-9.5; AG32 14.5,-9.5; AG33 15.5,-9.5; AG34 16.5,-9.5; AH1 -16.5,-10.5; AH2 -15.5,-10.5; AH3 -14.5,-10.5; AH4 -13.5,-10.5; AH5 -12.5,-10.5; AH6 -11.5,-10.5; AH7 -10.5,-10.5; AH8 -9.5,-10.5; AH9 -8.5,-10.5; AH10 -7.5,-10.5; AH11 -6.5,-10.5; AH12 -5.5,-10.5; AH13 -4.5,-10.5; AH14 -3.5,-10.5; AH15 -2.5,-10.5; AH16 -1.5,-10.5; AH17 -0.5,-10.5; AH18 0.5,-10.5; AH19 1.5,-10.5; AH20 2.5,-10.5; AH21 3.5,-10.5; AH22 4.5,-10.5; AH23 5.5,-10.5; AH24 6.5,-10.5; AH25 7.5,-10.5; AH26 8.5,-10.5; AH27 9.5,-10.5; AH28 10.5,-10.5; AH29 11.5,-10.5; AH30 12.5,-10.5; AH31 13.5,-10.5; AH32 14.5,-10.5; AH33 15.5,-10.5; AH34 16.5,-10.5; AJ1 -16.5,-11.5; AJ2 -15.5,-11.5; AJ3 -14.5,-11.5; AJ4 -13.5,-11.5; AJ5 -12.5,-11.5; AJ6 -11.5,-11.5; AJ7 -10.5,-11.5; AJ8 -9.5,-11.5; AJ9 -8.5,-11.5; AJ10 -7.5,-11.5; AJ11 -6.5,-11.5; AJ12 -5.5,-11.5; AJ13 -4.5,-11.5; AJ14 -3.5,-11.5; AJ15 -2.5,-11.5; AJ16 -1.5,-11.5; AJ17 -0.5,-11.5; AJ18 0.5,-11.5; AJ19 1.5,-11.5; AJ20 2.5,-11.5; AJ21 3.5,-11.5; AJ22 4.5,-11.5; AJ23 5.5,-11.5; AJ24 6.5,-11.5; AJ25 7.5,-11.5; AJ26 8.5,-11.5; AJ27 9.5,-11.5; AJ28 10.5,-11.5; AJ29 11.5,-11.5; AJ30 12.5,-11.5; AJ31 13.5,-11.5; AJ32 14.5,-11.5; AJ33 15.5,-11.5; AJ34 16.5,-11.5; AK1 -16.5,-12.5; AK2 -15.5,-12.5; AK3 -14.5,-12.5; AK4 -13.5,-12.5; AK5 -12.5,-12.5; AK6 -11.5,-12.5; AK7 -10.5,-12.5; AK8 -9.5,-12.5; AK9 -8.5,-12.5; AK10 -7.5,-12.5; AK11 -6.5,-12.5; AK12 -5.5,-12.5; AK13 -4.5,-12.5; AK14 -3.5,-12.5; AK15 -2.5,-12.5; AK16 -1.5,-12.5; AK17 -0.5,-12.5; AK18 0.5,-12.5; AK19 1.5,-12.5; AK20 2.5,-12.5; AK21 3.5,-12.5; AK22 4.5,-12.5; AK23 5.5,-12.5; AK24 6.5,-12.5; AK25 7.5,-12.5; AK26 8.5,-12.5; AK27 9.5,-12.5; AK28 10.5,-12.5; AK29 11.5,-12.5; AK30 12.5,-12.5; AK31 13.5,-12.5; AK32 14.5,-12.5; AK33 15.5,-12.5; AK34 16.5,-12.5; AL1 -16.5,-13.5; AL2 -15.5,-13.5; AL3 -14.5,-13.5; AL4 -13.5,-13.5; AL5 -12.5,-13.5; AL6 -11.5,-13.5; AL7 -10.5,-13.5; AL8 -9.5,-13.5; AL9 -8.5,-13.5; AL10 -7.5,-13.5; AL11 -6.5,-13.5; AL12 -5.5,-13.5; AL13 -4.5,-13.5; AL14 -3.5,-13.5; AL15 -2.5,-13.5; AL16 -1.5,-13.5; AL17 -0.5,-13.5; AL18 0.5,-13.5; AL19 1.5,-13.5; AL20 2.5,-13.5; AL21 3.5,-13.5; AL22 4.5,-13.5; AL23 5.5,-13.5; AL24 6.5,-13.5; AL25 7.5,-13.5; AL26 8.5,-13.5; AL27 9.5,-13.5; AL28 10.5,-13.5; AL29 11.5,-13.5; AL30 12.5,-13.5; AL31 13.5,-13.5; AL32 14.5,-13.5; AL33 15.5,-13.5; AL34 16.5,-13.5; AM1 -16.5,-14.5; AM2 -15.5,-14.5; AM3 -14.5,-14.5; AM4 -13.5,-14.5; AM5 -12.5,-14.5; AM6 -11.5,-14.5; AM7 -10.5,-14.5; AM8 -9.5,-14.5; AM9 -8.5,-14.5; AM10 -7.5,-14.5; AM11 -6.5,-14.5; AM12 -5.5,-14.5; AM13 -4.5,-14.5; AM14 -3.5,-14.5; AM15 -2.5,-14.5; AM16 -1.5,-14.5; AM17 -0.5,-14.5; AM18 0.5,-14.5; AM19 1.5,-14.5; AM20 2.5,-14.5; AM21 3.5,-14.5; AM22 4.5,-14.5; AM23 5.5,-14.5; AM24 6.5,-14.5; AM25 7.5,-14.5; AM26 8.5,-14.5; AM27 9.5,-14.5; AM28 10.5,-14.5; AM29 11.5,-14.5; AM30 12.5,-14.5; AM31 13.5,-14.5; AM32 14.5,-14.5; AM33 15.5,-14.5; AM34 16.5,-14.5; AN1 -16.5,-15.5; AN2 -15.5,-15.5; AN3 -14.5,-15.5; AN4 -13.5,-15.5; AN5 -12.5,-15.5; AN6 -11.5,-15.5; AN7 -10.5,-15.5; AN8 -9.5,-15.5; AN9 -8.5,-15.5; AN10 -7.5,-15.5; AN11 -6.5,-15.5; AN12 -5.5,-15.5; AN13 -4.5,-15.5; AN14 -3.5,-15.5; AN15 -2.5,-15.5; AN16 -1.5,-15.5; AN17 -0.5,-15.5; AN18 0.5,-15.5; AN19 1.5,-15.5; AN20 2.5,-15.5; AN21 3.5,-15.5; AN22 4.5,-15.5; AN23 5.5,-15.5; AN24 6.5,-15.5; AN25 7.5,-15.5; AN26 8.5,-15.5; AN27 9.5,-15.5; AN28 10.5,-15.5; AN29 11.5,-15.5; AN30 12.5,-15.5; AN31 13.5,-15.5; AN32 14.5,-15.5; AN33 15.5,-15.5; AN34 16.5,-15.5; AP2 -15.5,-16.5; AP3 -14.5,-16.5; AP4 -13.5,-16.5; AP5 -12.5,-16.5; AP6 -11.5,-16.5; AP7 -10.5,-16.5; AP8 -9.5,-16.5; AP9 -8.5,-16.5; AP10 -7.5,-16.5; AP11 -6.5,-16.5; AP12 -5.5,-16.5; AP13 -4.5,-16.5; AP14 -3.5,-16.5; AP15 -2.5,-16.5; AP16 -1.5,-16.5; AP17 -0.5,-16.5; AP18 0.5,-16.5; AP19 1.5,-16.5; AP20 2.5,-16.5; AP21 3.5,-16.5; AP22 4.5,-16.5; AP23 5.5,-16.5; AP24 6.5,-16.5; AP25 7.5,-16.5; AP26 8.5,-16.5; AP27 9.5,-16.5; AP28 10.5,-16.5; AP29 11.5,-16.5; AP30 12.5,-16.5; AP31 13.5,-16.5; AP32 14.5,-16.5; AP33 15.5,-16.5; B1 -16.5,15.5; B2 -15.5,15.5; B3 -14.5,15.5; B4 -13.5,15.5; B5 -12.5,15.5; B6 -11.5,15.5; B7 -10.5,15.5; B8 -9.5,15.5; B9 -8.5,15.5; B10 -7.5,15.5; B11 -6.5,15.5; B12 -5.5,15.5; B13 -4.5,15.5; B14 -3.5,15.5; B15 -2.5,15.5; B16 -1.5,15.5; B17 -0.5,15.5; B18 0.5,15.5; B19 1.5,15.5; B20 2.5,15.5; B21 3.5,15.5; B22 4.5,15.5; B23 5.5,15.5; B24 6.5,15.5; B25 7.5,15.5; B26 8.5,15.5; B27 9.5,15.5; B28 10.5,15.5; B29 11.5,15.5; B30 12.5,15.5; B31 13.5,15.5; B32 14.5,15.5; B33 15.5,15.5; B34 16.5,15.5; C1 -16.5,14.5; C2 -15.5,14.5; C3 -14.5,14.5; C4 -13.5,14.5; C5 -12.5,14.5; C6 -11.5,14.5; C7 -10.5,14.5; C8 -9.5,14.5; C9 -8.5,14.5; C10 -7.5,14.5; C11 -6.5,14.5; C12 -5.5,14.5; C13 -4.5,14.5; C14 -3.5,14.5; C15 -2.5,14.5; C16 -1.5,14.5; C17 -0.5,14.5; C18 0.5,14.5; C19 1.5,14.5; C20 2.5,14.5; C21 3.5,14.5; C22 4.5,14.5; C23 5.5,14.5; C24 6.5,14.5; C25 7.5,14.5; C26 8.5,14.5; C27 9.5,14.5; C28 10.5,14.5; C29 11.5,14.5; C30 12.5,14.5; C31 13.5,14.5; C32 14.5,14.5; C33 15.5,14.5; C34 16.5,14.5; D1 -16.5,13.5; D2 -15.5,13.5; D3 -14.5,13.5; D4 -13.5,13.5; D5 -12.5,13.5; D6 -11.5,13.5; D7 -10.5,13.5; D8 -9.5,13.5; D9 -8.5,13.5; D10 -7.5,13.5; D11 -6.5,13.5; D12 -5.5,13.5; D13 -4.5,13.5; D14 -3.5,13.5; D15 -2.5,13.5; D16 -1.5,13.5; D17 -0.5,13.5; D18 0.5,13.5; D19 1.5,13.5; D20 2.5,13.5; D21 3.5,13.5; D22 4.5,13.5; D23 5.5,13.5; D24 6.5,13.5; D25 7.5,13.5; D26 8.5,13.5; D27 9.5,13.5; D28 10.5,13.5; D29 11.5,13.5; D30 12.5,13.5; D31 13.5,13.5; D32 14.5,13.5; D33 15.5,13.5; D34 16.5,13.5; E1 -16.5,12.5; E2 -15.5,12.5; E3 -14.5,12.5; E4 -13.5,12.5; E5 -12.5,12.5; E6 -11.5,12.5; E7 -10.5,12.5; E8 -9.5,12.5; E9 -8.5,12.5; E10 -7.5,12.5; E11 -6.5,12.5; E12 -5.5,12.5; E13 -4.5,12.5; E14 -3.5,12.5; E15 -2.5,12.5; E16 -1.5,12.5; E17 -0.5,12.5; E18 0.5,12.5; E19 1.5,12.5; E20 2.5,12.5; E21 3.5,12.5; E22 4.5,12.5; E23 5.5,12.5; E24 6.5,12.5; E25 7.5,12.5; E26 8.5,12.5; E27 9.5,12.5; E28 10.5,12.5; E29 11.5,12.5; E30 12.5,12.5; E31 13.5,12.5; E32 14.5,12.5; E33 15.5,12.5; E34 16.5,12.5; F1 -16.5,11.5; F2 -15.5,11.5; F3 -14.5,11.5; F4 -13.5,11.5; F5 -12.5,11.5; F6 -11.5,11.5; F7 -10.5,11.5; F8 -9.5,11.5; F9 -8.5,11.5; F10 -7.5,11.5; F11 -6.5,11.5; F12 -5.5,11.5; F13 -4.5,11.5; F14 -3.5,11.5; F15 -2.5,11.5; F16 -1.5,11.5; F17 -0.5,11.5; F18 0.5,11.5; F19 1.5,11.5; F20 2.5,11.5; F21 3.5,11.5; F22 4.5,11.5; F23 5.5,11.5; F24 6.5,11.5; F25 7.5,11.5; F26 8.5,11.5; F27 9.5,11.5; F28 10.5,11.5; F29 11.5,11.5; F30 12.5,11.5; F31 13.5,11.5; F32 14.5,11.5; F33 15.5,11.5; F34 16.5,11.5; G1 -16.5,10.5; G2 -15.5,10.5; G3 -14.5,10.5; G4 -13.5,10.5; G5 -12.5,10.5; G6 -11.5,10.5; G7 -10.5,10.5; G8 -9.5,10.5; G9 -8.5,10.5; G10 -7.5,10.5; G11 -6.5,10.5; G12 -5.5,10.5; G13 -4.5,10.5; G14 -3.5,10.5; G15 -2.5,10.5; G16 -1.5,10.5; G17 -0.5,10.5; G18 0.5,10.5; G19 1.5,10.5; G20 2.5,10.5; G21 3.5,10.5; G22 4.5,10.5; G23 5.5,10.5; G24 6.5,10.5; G25 7.5,10.5; G26 8.5,10.5; G27 9.5,10.5; G28 10.5,10.5; G29 11.5,10.5; G30 12.5,10.5; G31 13.5,10.5; G32 14.5,10.5; G33 15.5,10.5; G34 16.5,10.5; H1 -16.5,9.5; H2 -15.5,9.5; H3 -14.5,9.5; H4 -13.5,9.5; H5 -12.5,9.5; H6 -11.5,9.5; H7 -10.5,9.5; H8 -9.5,9.5; H9 -8.5,9.5; H10 -7.5,9.5; H11 -6.5,9.5; H12 -5.5,9.5; H13 -4.5,9.5; H14 -3.5,9.5; H15 -2.5,9.5; H16 -1.5,9.5; H17 -0.5,9.5; H18 0.5,9.5; H19 1.5,9.5; H20 2.5,9.5; H21 3.5,9.5; H22 4.5,9.5; H23 5.5,9.5; H24 6.5,9.5; H25 7.5,9.5; H26 8.5,9.5; H27 9.5,9.5; H28 10.5,9.5; H29 11.5,9.5; H30 12.5,9.5; H31 13.5,9.5; H32 14.5,9.5; H33 15.5,9.5; H34 16.5,9.5; J1 -16.5,8.5; J2 -15.5,8.5; J3 -14.5,8.5; J4 -13.5,8.5; J5 -12.5,8.5; J6 -11.5,8.5; J7 -10.5,8.5; J8 -9.5,8.5; J9 -8.5,8.5; J10 -7.5,8.5; J11 -6.5,8.5; J12 -5.5,8.5; J13 -4.5,8.5; J14 -3.5,8.5; J15 -2.5,8.5; J16 -1.5,8.5; J17 -0.5,8.5; J18 0.5,8.5; J19 1.5,8.5; J20 2.5,8.5; J21 3.5,8.5; J22 4.5,8.5; J23 5.5,8.5; J24 6.5,8.5; J25 7.5,8.5; J26 8.5,8.5; J27 9.5,8.5; J28 10.5,8.5; J29 11.5,8.5; J30 12.5,8.5; J31 13.5,8.5; J32 14.5,8.5; J33 15.5,8.5; J34 16.5,8.5; K1 -16.5,7.5; K2 -15.5,7.5; K3 -14.5,7.5; K4 -13.5,7.5; K5 -12.5,7.5; K6 -11.5,7.5; K7 -10.5,7.5; K8 -9.5,7.5; K9 -8.5,7.5; K10 -7.5,7.5; K11 -6.5,7.5; K12 -5.5,7.5; K13 -4.5,7.5; K14 -3.5,7.5; K15 -2.5,7.5; K16 -1.5,7.5; K17 -0.5,7.5; K18 0.5,7.5; K19 1.5,7.5; K20 2.5,7.5; K21 3.5,7.5; K22 4.5,7.5; K23 5.5,7.5; K24 6.5,7.5; K25 7.5,7.5; K26 8.5,7.5; K27 9.5,7.5; K28 10.5,7.5; K29 11.5,7.5; K30 12.5,7.5; K31 13.5,7.5; K32 14.5,7.5; K33 15.5,7.5; K34 16.5,7.5; L1 -16.5,6.5; L2 -15.5,6.5; L3 -14.5,6.5; L4 -13.5,6.5; L5 -12.5,6.5; L6 -11.5,6.5; L7 -10.5,6.5; L8 -9.5,6.5; L9 -8.5,6.5; L10 -7.5,6.5; L11 -6.5,6.5; L12 -5.5,6.5; L13 -4.5,6.5; L14 -3.5,6.5; L15 -2.5,6.5; L16 -1.5,6.5; L17 -0.5,6.5; L18 0.5,6.5; L19 1.5,6.5; L20 2.5,6.5; L21 3.5,6.5; L22 4.5,6.5; L23 5.5,6.5; L24 6.5,6.5; L25 7.5,6.5; L26 8.5,6.5; L27 9.5,6.5; L28 10.5,6.5; L29 11.5,6.5; L30 12.5,6.5; L31 13.5,6.5; L32 14.5,6.5; L33 15.5,6.5; L34 16.5,6.5; M1 -16.5,5.5; M2 -15.5,5.5; M3 -14.5,5.5; M4 -13.5,5.5; M5 -12.5,5.5; M6 -11.5,5.5; M7 -10.5,5.5; M8 -9.5,5.5; M9 -8.5,5.5; M10 -7.5,5.5; M11 -6.5,5.5; M12 -5.5,5.5; M13 -4.5,5.5; M14 -3.5,5.5; M15 -2.5,5.5; M16 -1.5,5.5; M17 -0.5,5.5; M18 0.5,5.5; M19 1.5,5.5; M20 2.5,5.5; M21 3.5,5.5; M22 4.5,5.5; M23 5.5,5.5; M24 6.5,5.5; M25 7.5,5.5; M26 8.5,5.5; M27 9.5,5.5; M28 10.5,5.5; M29 11.5,5.5; M30 12.5,5.5; M31 13.5,5.5; M32 14.5,5.5; M33 15.5,5.5; M34 16.5,5.5; N1 -16.5,4.5; N2 -15.5,4.5; N3 -14.5,4.5; N4 -13.5,4.5; N5 -12.5,4.5; N6 -11.5,4.5; N7 -10.5,4.5; N8 -9.5,4.5; N9 -8.5,4.5; N10 -7.5,4.5; N11 -6.5,4.5; N12 -5.5,4.5; N13 -4.5,4.5; N14 -3.5,4.5; N15 -2.5,4.5; N16 -1.5,4.5; N17 -0.5,4.5; N18 0.5,4.5; N19 1.5,4.5; N20 2.5,4.5; N21 3.5,4.5; N22 4.5,4.5; N23 5.5,4.5; N24 6.5,4.5; N25 7.5,4.5; N26 8.5,4.5; N27 9.5,4.5; N28 10.5,4.5; N29 11.5,4.5; N30 12.5,4.5; N31 13.5,4.5; N32 14.5,4.5; N33 15.5,4.5; N34 16.5,4.5; P1 -16.5,3.5; P2 -15.5,3.5; P3 -14.5,3.5; P4 -13.5,3.5; P5 -12.5,3.5; P6 -11.5,3.5; P7 -10.5,3.5; P8 -9.5,3.5; P9 -8.5,3.5; P10 -7.5,3.5; P11 -6.5,3.5; P12 -5.5,3.5; P13 -4.5,3.5; P14 -3.5,3.5; P15 -2.5,3.5; P16 -1.5,3.5; P17 -0.5,3.5; P18 0.5,3.5; P19 1.5,3.5; P20 2.5,3.5; P21 3.5,3.5; P22 4.5,3.5; P23 5.5,3.5; P24 6.5,3.5; P25 7.5,3.5; P26 8.5,3.5; P27 9.5,3.5; P28 10.5,3.5; P29 11.5,3.5; P30 12.5,3.5; P31 13.5,3.5; P32 14.5,3.5; P33 15.5,3.5; P34 16.5,3.5; R1 -16.5,2.5; R2 -15.5,2.5; R3 -14.5,2.5; R4 -13.5,2.5; R5 -12.5,2.5; R6 -11.5,2.5; R7 -10.5,2.5; R8 -9.5,2.5; R9 -8.5,2.5; R10 -7.5,2.5; R11 -6.5,2.5; R12 -5.5,2.5; R13 -4.5,2.5; R14 -3.5,2.5; R15 -2.5,2.5; R16 -1.5,2.5; R17 -0.5,2.5; R18 0.5,2.5; R19 1.5,2.5; R20 2.5,2.5; R21 3.5,2.5; R22 4.5,2.5; R23 5.5,2.5; R24 6.5,2.5; R25 7.5,2.5; R26 8.5,2.5; R27 9.5,2.5; R28 10.5,2.5; R29 11.5,2.5; R30 12.5,2.5; R31 13.5,2.5; R32 14.5,2.5; R33 15.5,2.5; R34 16.5,2.5; T1 -16.5,1.5; T2 -15.5,1.5; T3 -14.5,1.5; T4 -13.5,1.5; T5 -12.5,1.5; T6 -11.5,1.5; T7 -10.5,1.5; T8 -9.5,1.5; T9 -8.5,1.5; T10 -7.5,1.5; T11 -6.5,1.5; T12 -5.5,1.5; T13 -4.5,1.5; T14 -3.5,1.5; T15 -2.5,1.5; T16 -1.5,1.5; T17 -0.5,1.5; T18 0.5,1.5; T19 1.5,1.5; T20 2.5,1.5; T21 3.5,1.5; T22 4.5,1.5; T23 5.5,1.5; T24 6.5,1.5; T25 7.5,1.5; T26 8.5,1.5; T27 9.5,1.5; T28 10.5,1.5; T29 11.5,1.5; T30 12.5,1.5; T31 13.5,1.5; T32 14.5,1.5; T33 15.5,1.5; T34 16.5,1.5; U1 -16.5,0.5; U2 -15.5,0.5; U3 -14.5,0.5; U4 -13.5,0.5; U5 -12.5,0.5; U6 -11.5,0.5; U7 -10.5,0.5; U8 -9.5,0.5; U9 -8.5,0.5; U10 -7.5,0.5; U11 -6.5,0.5; U12 -5.5,0.5; U13 -4.5,0.5; U14 -3.5,0.5; U15 -2.5,0.5; U16 -1.5,0.5; U17 -0.5,0.5; U18 0.5,0.5; U19 1.5,0.5; U20 2.5,0.5; U21 3.5,0.5; U22 4.5,0.5; U23 5.5,0.5; U24 6.5,0.5; U25 7.5,0.5; U26 8.5,0.5; U27 9.5,0.5; U28 10.5,0.5; U29 11.5,0.5; U30 12.5,0.5; U31 13.5,0.5; U32 14.5,0.5; U33 15.5,0.5; U34 16.5,0.5; V1 -16.5,-0.5; V2 -15.5,-0.5; V3 -14.5,-0.5; V4 -13.5,-0.5; V5 -12.5,-0.5; V6 -11.5,-0.5; V7 -10.5,-0.5; V8 -9.5,-0.5; V9 -8.5,-0.5; V10 -7.5,-0.5; V11 -6.5,-0.5; V12 -5.5,-0.5; V13 -4.5,-0.5; V14 -3.5,-0.5; V15 -2.5,-0.5; V16 -1.5,-0.5; V17 -0.5,-0.5; V18 0.5,-0.5; V19 1.5,-0.5; V20 2.5,-0.5; V21 3.5,-0.5; V22 4.5,-0.5; V23 5.5,-0.5; V24 6.5,-0.5; V25 7.5,-0.5; V26 8.5,-0.5; V27 9.5,-0.5; V28 10.5,-0.5; V29 11.5,-0.5; V30 12.5,-0.5; V31 13.5,-0.5; V32 14.5,-0.5; V33 15.5,-0.5; V34 16.5,-0.5; W1 -16.5,-1.5; W2 -15.5,-1.5; W3 -14.5,-1.5; W4 -13.5,-1.5; W5 -12.5,-1.5; W6 -11.5,-1.5; W7 -10.5,-1.5; W8 -9.5,-1.5; W9 -8.5,-1.5; W10 -7.5,-1.5; W11 -6.5,-1.5; W12 -5.5,-1.5; W13 -4.5,-1.5; W14 -3.5,-1.5; W15 -2.5,-1.5; W16 -1.5,-1.5; W17 -0.5,-1.5; W18 0.5,-1.5; W19 1.5,-1.5; W20 2.5,-1.5; W21 3.5,-1.5; W22 4.5,-1.5; W23 5.5,-1.5; W24 6.5,-1.5; W25 7.5,-1.5; W26 8.5,-1.5; W27 9.5,-1.5; W28 10.5,-1.5; W29 11.5,-1.5; W30 12.5,-1.5; W31 13.5,-1.5; W32 14.5,-1.5; W33 15.5,-1.5; W34 16.5,-1.5; Y1 -16.5,-2.5; Y2 -15.5,-2.5; Y3 -14.5,-2.5; Y4 -13.5,-2.5; Y5 -12.5,-2.5; Y6 -11.5,-2.5; Y7 -10.5,-2.5; Y8 -9.5,-2.5; Y9 -8.5,-2.5; Y10 -7.5,-2.5; Y11 -6.5,-2.5; Y12 -5.5,-2.5; Y13 -4.5,-2.5; Y14 -3.5,-2.5; Y15 -2.5,-2.5; Y16 -1.5,-2.5; Y17 -0.5,-2.5; Y18 0.5,-2.5; Y19 1.5,-2.5; Y20 2.5,-2.5; Y21 3.5,-2.5; Y22 4.5,-2.5; Y23 5.5,-2.5; Y24 6.5,-2.5; Y25 7.5,-2.5; Y26 8.5,-2.5; Y27 9.5,-2.5; Y28 10.5,-2.5; Y29 11.5,-2.5; Y30 12.5,-2.5; Y31 13.5,-2.5; Y32 14.5,-2.5; Y33 15.5,-2.5; Y34 16.5,-2.5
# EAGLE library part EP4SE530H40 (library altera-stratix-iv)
EP4SE530H40 Auto generated by make-symbol-device-package-bsdl.ulp Rev. 29 Source: EP4SE530H40.bsd

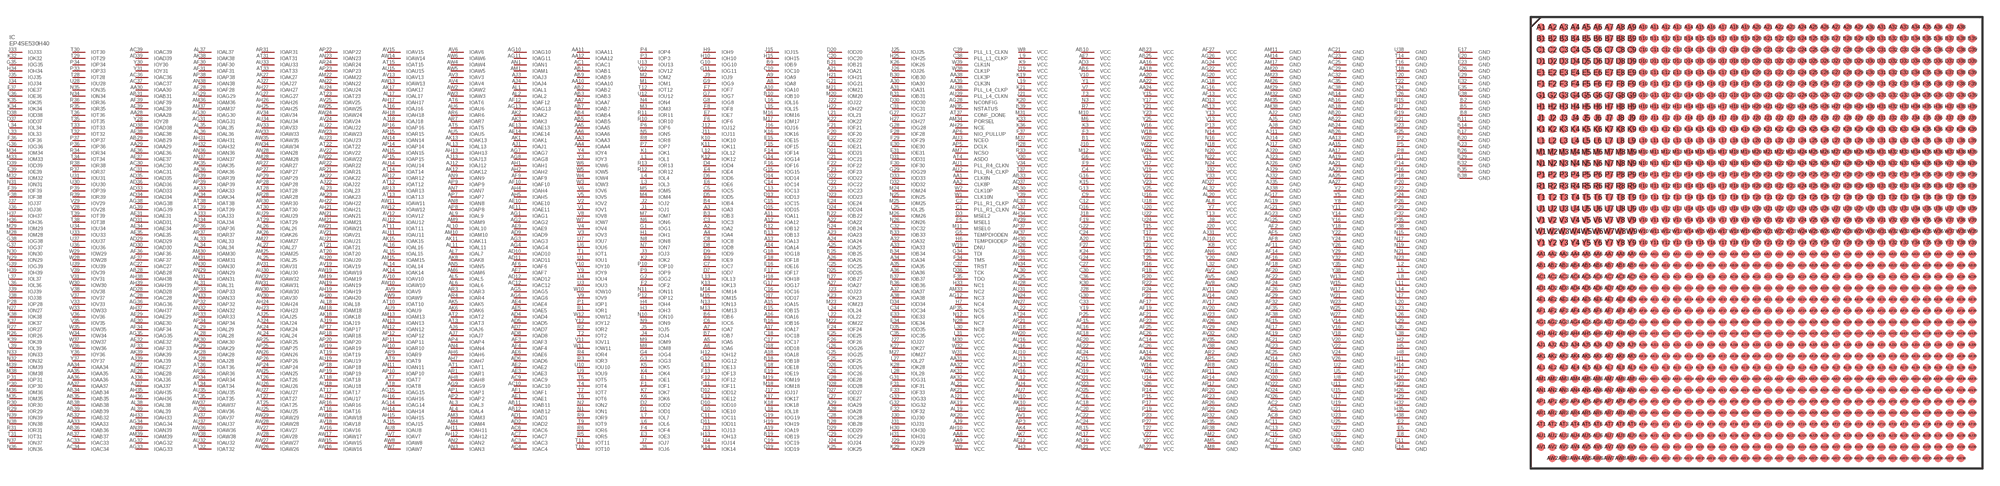
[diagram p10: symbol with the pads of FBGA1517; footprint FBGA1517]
Designator prefix IC

## EP4SE530H40 (MPN: EP4SE530H40C3N; OC_FARNELL: unknown; OC_NEWARK: 52R1739)  [FBGA1517]
A2  IOA2
A3  IOA3
A4  IOA4
A5  IOA5
A6  IOA6
A7  IOA7
A8  IOA8
A9  IOA9
A10  IOA10
A11  IOA11
A12  IOA12
A13  IOA13
A14  IOA14
A15  IOA15
A16  IOA16
A17  IOA17
A18  IOA18
A19  IOA19
A20  VCC  pwr
A21  IOA21
A22  IOA22
A23  IOA23
A24  IOA24
A25  IOA25
A26  IOA26
A27  IOA27
A28  IOA28
A29  IOA29
A30  IOA30
A31  IOA31
A32  IOA32
A33  IOA33
A34  IOA34
A35  IOA35
A36  IOA36
A37  IOA37
A38  IOA38
AA1  CLK8N  in
AA2  CLK8P  in
AA3  IOAA3
AA4  IOAA4
AA5  IOAA5
AA6  IOAA6
AA7  IOAA7
AA8  VCC  pwr
AA9  VCC  pwr
AA10  IOAA10
AA11  IOAA11
AA12  IOAA12
AA13  GND  pwr
AA14  VCC  pwr
AA15  GND  pwr
AA16  VCC  pwr
AA17  GND  pwr
AA18  VCC  pwr
AA19  GND  pwr
AA20  VCC  pwr
AA21  GND  pwr
AA22  VCC  pwr
AA23  GND  pwr
AA24  VCC  pwr
AA25  GND  pwr
AA26  VCC  pwr
AA27  GND  pwr
AA28  IOAA28
AA29  IOAA29
AA30  IOAA30
AA31  VCC  pwr
AA32  VCC  pwr
AA33  IOAA33
AA34  IOAA34
AA35  IOAA35
AA36  IOAA36
AA37  IOAA37
AA38  CLK3P  in
AA39  CLK3N  in
AB1  IOAB1
AB2  IOAB2
AB3  IOAB3
AB4  IOAB4
AB5  IOAB5
AB6  VCC  pwr
AB7  IOAB7
AB9  IOAB9
AB10  VCC  pwr
AB11  IOAB11
AB12  IOAB12
AB13  VCC  pwr
AB14  GND  pwr
AB15  VCC  pwr
AB16  GND  pwr
AB17  VCC  pwr
AB18  GND  pwr
AB19  VCC  pwr
AB20  GND  pwr
AB21  VCC  pwr
AB22  GND  pwr
AB23  VCC  pwr
AB24  GND  pwr
AB25  VCC  pwr
AB26  GND  pwr
AB27  VCC  pwr
AB28  IOAB28
AB29  IOAB29
AB30  VCC  pwr
AB31  IOAB31
AB32  IOAB32
AB33  VCC  pwr
AB34  IOAB34
AB35  IOAB35
AB36  IOAB36
AB37  IOAB37
AB38  IOAB38
AB39  IOAB39
AC1  IOAC1
AC2  GND  pwr
AC3  IOAC3
AC4  IOAC4
AC5  GND  pwr
AC6  IOAC6
AC7  IOAC7
AC8  GND  pwr
AC9  IOAC9
AC10  IOAC10
AC11  GND  pwr
AC12  IOAC12
AC13  GND  pwr
AC14  VCC  pwr
AC15  GND  pwr
AC16  VCC  pwr
AC17  GND  pwr
AC18  VCC  pwr
AC19  GND  pwr
AC20  VCC  pwr
AC21  GND  pwr
AC22  VCC  pwr
AC23  GND  pwr
AC24  VCC  pwr
AC25  GND  pwr
AC26  VCC  pwr
AC27  IOAC27
AC28  IOAC28
AC29  GND  pwr
AC30  IOAC30
AC31  IOAC31
AC32  GND  pwr
AC33  IOAC33
AC34  IOAC34
AC35  GND  pwr
AC36  IOAC36
AC37  IOAC37
AC38  GND  pwr
AC39  IOAC39
AD1  IOAD1
AD2  IOAD2
AD3  VCC  pwr
AD4  IOAD4
AD5  IOAD5
AD6  IOAD6
AD7  IOAD7
AD8  IOAD8
AD9  IOAD9
AD10  IOAD10
AD11  IOAD11
AD12  IOAD12
AD13  VCC  pwr
AD14  GND  pwr
AD15  VCC  pwr
AD16  GND  pwr
AD17  VCC  pwr
AD18  GND  pwr
AD19  VCC  pwr
AD20  GND  pwr
AD21  VCC  pwr
AD22  GND  pwr
AD23  VCC  pwr
AD24  GND  pwr
AD25  VCC  pwr
AD26  GND  pwr
AD27  VCC  pwr
AD28  IOAD28
AD29  IOAD29
AD30  IOAD30
AD31  IOAD31
AD33  IOAD33
AD34  IOAD34
AD35  IOAD35
AD36  IOAD36
AD37  VCC  pwr
AD38  IOAD38
AD39  IOAD39
AE1  IOAE1
AE2  IOAE2
AE3  IOAE3
AE4  IOAE4
AE5  IOAE5
AE6  IOAE6
AE7  VCC  pwr
AE9  IOAE9
AE10  IOAE10
AE11  IOAE11
AE12  VCC  pwr
AE13  IOAE13
AE14  IOAE14
AE15  GND  pwr
AE16  VCC  pwr
AE17  GND  pwr
AE18  VCC  pwr
AE19  GND  pwr
AE20  VCC  pwr
AE21  GND  pwr
AE22  VCC  pwr
AE23  GND  pwr
AE24  VCC  pwr
AE25  GND  pwr
AE26  VCC  pwr
AE27  IOAE27
AE28  IOAE28
AE29  IOAE29
AE30  IOAE30
AE31  IOAE31
AE32  IOAE32
AE33  VCC  pwr
AE34  IOAE34
AE35  IOAE35
AE36  IOAE36
AE37  IOAE37
AE38  IOAE38
AE39  IOAE39
AF1  IOAF1
AF2  GND  pwr
AF3  IOAF3
AF4  IOAF4
AF5  GND  pwr
AF6  IOAF6
AF7  IOAF7
AF8  GND  pwr
AF9  IOAF9
AF10  IOAF10
AF11  GND  pwr
AF12  IOAF12
AF13  VCC  pwr
AF14  GND  pwr
AF15  VCC  pwr
AF16  GND  pwr
AF17  VCC  pwr
AF18  GND  pwr
AF19  VCC  pwr
AF20  GND  pwr
AF21  VCC  pwr
AF22  GND  pwr
AF23  VCC  pwr
AF24  GND  pwr
AF25  VCC  pwr
AF26  GND  pwr
AF27  VCC  pwr
AF28  IOAF28
AF29  GND  pwr
AF30  IOAF30
AF31  IOAF31
AF32  GND  pwr
AF33  IOAF33
AF34  IOAF34
AF35  GND  pwr
AF36  IOAF36
AF37  IOAF37
AF38  GND  pwr
AF39  IOAF39
AG1  IOAG1
AG2  IOAG2
AG3  IOAG3
AG4  IOAG4
AG5  IOAG5
AG6  IOAG6
AG7  IOAG7
AG8  IOAG8
AG9  IOAG9
AG10  IOAG10
AG11  IOAG11
AG12  NC3  pas
AG13  IOAG13
AG14  IOAG14
AG15  IOAG15
AG16  VCC  pwr
AG17  GND  pwr
AG18  VCC  pwr
AG19  GND  pwr
AG20  VCC  pwr
AG21  GND  pwr
AG22  VCC  pwr
AG23  GND  pwr
AG24  VCC  pwr
AG25  GND  pwr
AG26  VCC  pwr
AG27  IOAG27
AG28  NCONFIG  in
AG29  IOAG29
AG30  IOAG30
AG31  IOAG31
AG32  IOAG32
AG33  IOAG33
AG34  IOAG34
AG35  IOAG35
AG36  IOAG36
AG37  VCC  pwr
AG38  IOAG38
AG39  IOAG39
AH1  IOAH1
AH2  IOAH2
AH3  VCC  pwr
AH4  IOAH4
AH5  IOAH5
AH6  IOAH6
AH7  IOAH7
AH8  IOAH8
AH9  VCC  pwr
AH10  VCC  pwr
AH11  IOAH11
AH12  IOAH12
AH13  IOAH13
AH14  IOAH14
AH15  IOAH15
AH16  IOAH16
AH17  IOAH17
AH18  IOAH18
AH19  IOAH19
AH20  IOAH20
AH21  IOAH21
AH22  IOAH22
AH23  IOAH23
AH24  IOAH24
AH25  IOAH25
AH26  IOAH26
AH27  IOAH27
AH28  VCC  pwr
AH29  NCE  in
AH30  VCC  pwr
AH31  IOAH31
AH32  IOAH32
AH33  IOAH33
AH34  VCC  pwr
AH35  IOAH35
AH36  IOAH36
AH37  IOAH37
AH38  IOAH38
AH39  IOAH39
AJ1  IOAJ1
AJ2  GND  pwr
AJ3  IOAJ3
AJ4  IOAJ4
AJ5  GND  pwr
AJ6  IOAJ6
AJ7  IOAJ7
AJ8  GND  pwr
AJ9  VCC  pwr
AJ10  VCC  pwr
AJ11  GND  pwr
AJ12  IOAJ12
AJ13  IOAJ13
AJ14  GND  pwr
AJ15  IOAJ15
AJ16  IOAJ16
AJ17  GND  pwr
AJ18  IOAJ18
AJ19  IOAJ19
AJ20  GND  pwr
AJ21  VCC  pwr
AJ22  IOAJ22
AJ23  GND  pwr
AJ24  IOAJ24
AJ25  IOAJ25
AJ26  GND  pwr
AJ27  IOAJ27
AJ28  IOAJ28
AJ29  GND  pwr
AJ31  VCC  pwr
AJ32  GND  pwr
AJ33  IOAJ33
AJ34  IOAJ34
AJ35  GND  pwr
AJ36  IOAJ36
AJ37  IOAJ37
AJ38  GND  pwr
AJ39  IOAJ39
AK1  IOAK1
AK2  IOAK2
AK3  IOAK3
AK4  VCC  pwr
AK5  IOAK5
AK6  IOAK6
AK7  VCC  pwr
AK8  IOAK8
AK10  VCC  pwr
AK11  IOAK11
AK12  IOAK12
AK13  IOAK13
AK14  IOAK14
AK15  IOAK15
AK16  VCC  pwr
AK17  IOAK17
AK18  IOAK18
AK19  VCC  pwr
AK20  VCC  pwr
AK21  VCC  pwr
AK22  IOAK22
AK23  IOAK23
AK24  IOAK24
AK25  VCC  pwr
AK26  IOAK26
AK27  IOAK27
AK28  IOAK28
AK29  IOAK29
AK30  IOAK30
AK31  VCC  pwr
AK32  VCC  pwr
AK33  IOAK33
AK34  IOAK34
AK35  IOAK35
AK36  IOAK36
AK37  VCC  pwr
AK38  IOAK38
AK39  IOAK39
AL1  IOAL1
AL2  IOAL2
AL3  IOAL3
AL4  IOAL4
AL5  IOAL5
AL6  IOAL6
AL7  IOAL7
AL8  VCC  pwr
AL9  IOAL9
AL10  IOAL10
AL11  IOAL11
AL12  VCC  pwr
AL13  IOAL13
AL14  IOAL14
AL15  IOAL15
AL16  IOAL16
AL17  IOAL17
AL18  IOAL18
AL19  VCC  pwr
AL20  VCC  pwr
AL21  VCC  pwr
AL22  VCC  pwr
AL23  IOAL23
AL24  IOAL24
AL25  IOAL25
AL26  IOAL26
AL27  IOAL27
AL28  IOAL28
AL29  IOAL29
AL30  VCC  pwr
AL31  IOAL31
AL32  VCC  pwr
AL33  IOAL33
AL34  IOAL34
AL35  IOAL35
AL36  IOAL36
AL37  IOAL37
AL38  IOAL38
AL39  IOAL39
AM1  IOAM1
AM2  GND  pwr
AM3  IOAM3
AM4  IOAM4
AM5  GND  pwr
AM6  IOAM6
AM7  NCSO  in
AM8  GND  pwr
AM9  IOAM9
AM10  IOAM10
AM11  GND  pwr
AM13  IOAM13
AM14  GND  pwr
AM15  IOAM15
AM17  GND  pwr
AM18  IOAM18
AM19  IOAM19
AM20  GND  pwr
AM21  IOAM21
AM22  IOAM22
AM23  GND  pwr
AM25  IOAM25
AM26  GND  pwr
AM27  IOAM27
AM28  IOAM28
AM29  GND  pwr
AM30  IOAM30
AM31  IOAM31
AM32  GND  pwr
AM33  NC2  pas
AM34  PORSEL  in
AM35  GND  pwr
AM36  IOAM36
AM37  IOAM37
AM38  GND  pwr
AM39  IOAM39
AN1  IOAN1
AN2  IOAN2
AN3  IOAN3
AN4  IOAN4
AN5  IOAN5
AN6  GND  pwr
AN7  IOAN7
AN8  IOAN8
AN9  IOAN9
AN10  VCC  pwr
AN11  IOAN11
AN12  IOAN12
AN13  IOAN13
AN14  IOAN14
AN15  IOAN15
AN16  VCC  pwr
AN18  VCC  pwr
AN19  IOAN19
AN21  IOAN21
AN22  IOAN22
AN23  IOAN23
AN24  VCC  pwr
AN25  IOAN25
AN26  IOAN26
AN27  VCC  pwr
AN28  IOAN28
AN29  IOAN29
AN30  IOAN30
AN31  IOAN31
AN32  IOAN32
AN33  IOAN33
AN34  VCC  pwr
AN35  NSTATUS  in
AN36  IOAN36
AN37  IOAN37
AN38  IOAN38
AN39  IOAN39
AP1  IOAP1
AP2  IOAP2
AP3  VCC  pwr
AP4  IOAP4
AP5  DCLK  in
AP6  NIO_PULLUP  in
AP7  IOAP7
AP8  IOAP8
AP9  IOAP9
AP10  IOAP10
AP11  IOAP11
AP12  IOAP12
AP13  VCC  pwr
AP14  IOAP14
AP15  IOAP15
AP16  IOAP16
AP17  IOAP17
AP18  IOAP18
AP19  IOAP19
AP20  IOAP20
AP21  VCC  pwr
AP22  IOAP22
AP23  IOAP23
AP24  IOAP24
AP25  IOAP25
AP26  IOAP26
AP27  IOAP27
AP28  IOAP28
AP29  IOAP29
AP31  VCC  pwr
AP32  IOAP32
AP33  IOAP33
AP34  IOAP34
AP35  NC5  pas
AP36  IOAP36
AP37  VCC  pwr
AP38  IOAP38
AP39  IOAP39
AR1  IOAR1
AR2  GND  pwr
AR3  IOAR3
AR4  IOAR4
AR5  GND  pwr
AR6  IOAR6
AR7  IOAR7
AR8  GND  pwr
AR9  IOAR9
AR10  IOAR10
AR11  GND  pwr
AR12  IOAR12
AR13  IOAR13
AR14  GND  pwr
AR15  IOAR15
AR16  IOAR16
AR17  GND  pwr
AR18  IOAR18
AR19  IOAR19
AR20  GND  pwr
AR21  IOAR21
AR22  IOAR22
AR23  GND  pwr
AR24  IOAR24
AR25  IOAR25
AR26  GND  pwr
AR27  IOAR27
AR28  IOAR28
AR29  GND  pwr
AR30  IOAR30
AR31  IOAR31
AR32  GND  pwr
AR33  IOAR33
AR34  IOAR34
AR35  GND  pwr
AR36  IOAR36
AR37  IOAR37
AR38  GND  pwr
AR39  IOAR39
AT1  IOAT1
AT2  IOAT2
AT3  IOAT3
AT4  ASDO  in
AT5  IOAT5
AT6  IOAT6
AT7  IOAT7
AT8  IOAT8
AT9  IOAT9
AT10  IOAT10
AT11  IOAT11
AT12  IOAT12
AT13  IOAT13
AT14  IOAT14
AT15  IOAT15
AT16  IOAT16
AT17  IOAT17
AT18  IOAT18
AT19  IOAT19
AT20  IOAT20
AT21  IOAT21
AT22  IOAT22
AT23  IOAT23
AT24  VCC  pwr
AT25  IOAT25
AT26  IOAT26
AT27  IOAT27
AT28  IOAT28
AT29  IOAT29
AT30  IOAT30
AT31  IOAT31
AT32  IOAT32
AT33  IOAT33
AT34  IOAT34
AT35  IOAT35
AT36  IOAT36
AT37  CONF_DONE  in
AT38  IOAT38
AT39  IOAT39
AU1  PLL_R4_CLKN  in
AU2  PLL_R4_CLKP  in
AU3  NCEO  in
AU4  VCC  pwr
AU5  IOAU5
AU6  IOAU6
AU7  VCC  pwr
AU8  IOAU8
AU9  IOAU9
AU10  VCC  pwr
AU11  IOAU11
AU12  IOAU12
AU13  VCC  pwr
AU14  IOAU14
AU15  IOAU15
AU16  VCC  pwr
AU17  IOAU17
AU18  IOAU18
AU19  IOAU19
AU20  IOAU20
AU21  IOAU21
AU22  IOAU22
AU23  IOAU23
AU24  IOAU24
AU25  IOAU25
AU26  IOAU26
AU27  IOAU27
AU28  VCC  pwr
AU29  IOAU29
AU30  IOAU30
AU31  VCC  pwr
AU32  IOAU32
AU33  IOAU33
AU34  IOAU34
AU35  IOAU35
AU36  VCC  pwr
AU37  IOAU37
AU38  PLL_L4_CLKP  in
AU39  PLL_L4_CLKN  in
AV1  VCC  pwr
AV2  GND  pwr
AV3  IOAV3
AV4  IOAV4
AV5  GND  pwr
AV6  IOAV6
AV7  IOAV7
AV8  GND  pwr
AV9  IOAV9
AV10  IOAV10
AV11  GND  pwr
AV12  IOAV12
AV13  IOAV13
AV14  GND  pwr
AV15  IOAV15
AV16  IOAV16
AV17  GND  pwr
AV18  IOAV18
AV19  IOAV19
AV20  GND  pwr
AV21  IOAV21
AV22  IOAV22
AV23  GND  pwr
AV24  IOAV24
AV25  IOAV25
AV26  GND  pwr
AV27  IOAV27
AV28  IOAV28
AV29  GND  pwr
AV30  IOAV30
AV31  IOAV31
AV32  GND  pwr
AV33  IOAV33
AV34  IOAV34
AV35  GND  pwr
AV36  IOAV36
AV37  IOAV37
AV38  GND  pwr
AV39  VCC  pwr
AW2  IOAW2
AW3  IOAW3
AW4  IOAW4
AW5  IOAW5
AW6  IOAW6
AW7  IOAW7
AW8  IOAW8
AW9  IOAW9
AW10  IOAW10
AW11  IOAW11
AW12  IOAW12
AW13  IOAW13
AW14  IOAW14
AW15  IOAW15
AW16  IOAW16
AW17  IOAW17
AW18  IOAW18
AW19  IOAW19
AW20  VCC  pwr
AW21  IOAW21
AW22  IOAW22
AW23  IOAW23
AW24  IOAW24
AW25  IOAW25
AW26  IOAW26
AW27  IOAW27
AW28  IOAW28
AW29  IOAW29
AW30  IOAW30
AW31  IOAW31
AW32  IOAW32
AW33  IOAW33
AW34  IOAW34
AW35  IOAW35
AW36  IOAW36
AW37  IOAW37
AW38  IOAW38
B1  VCC  pwr
B2  GND  pwr
B3  IOB3
B4  IOB4
B5  GND  pwr
B6  IOB6
B7  IOB7
B8  GND  pwr
B9  IOB9
B10  IOB10
B11  GND  pwr
B12  IOB12
B13  IOB13
B14  GND  pwr
B15  IOB15
B16  IOB16
B17  GND  pwr
B18  IOB18
B19  IOB19
B20  GND  pwr
B21  IOB21
B22  IOB22
B23  GND  pwr
B24  IOB24
B25  IOB25
B26  GND  pwr
B27  IOB27
B28  IOB28
B29  GND  pwr
B30  IOB30
B31  IOB31
B32  GND  pwr
B33  IOB33
B34  IOB34
B35  GND  pwr
B36  IOB36
B37  IOB37
B38  GND  pwr
B39  VCC  pwr
C1  PLL_R1_CLKN  in
C2  PLL_R1_CLKP  in
C3  IOC3
C4  VCC  pwr
C5  IOC5
C6  IOC6
C7  IOC7
C8  IOC8
C9  VCC  pwr
C10  IOC10
C11  IOC11
C12  VCC  pwr
C13  IOC13
C14  IOC14
C15  IOC15
C16  IOC16
C17  IOC17
C18  IOC18
C19  IOC19
C20  IOC20
C21  IOC21
C22  IOC22
C23  IOC23
C24  VCC  pwr
C25  IOC25
C26  IOC26
C27  VCC  pwr
C28  IOC28
C29  IOC29
C30  VCC  pwr
C31  IOC31
C32  IOC32
C33  VCC  pwr
C34  IOC34
C35  IOC35
C36  VCC  pwr
C37  TRST  in
C38  PLL_L1_CLKP  in
C39  PLL_L1_CLKN  in
D1  IOD1
D2  IOD2
D3  MSEL2  in
D4  IOD4
D5  IOD5
D6  IOD6
D7  IOD7
D8  IOD8
D9  IOD9
D10  IOD10
D11  IOD11
D12  IOD12
D13  IOD13
D14  IOD14
D15  IOD15
D16  VCC  pwr
D17  IOD17
D18  IOD18
D19  IOD19
D20  IOD20
D21  IOD21
D22  IOD22
D23  IOD23
D24  IOD24
D25  IOD25
D26  IOD26
D27  IOD27
D28  IOD28
D29  IOD29
D30  IOD30
D31  IOD31
D32  IOD32
D33  IOD33
D34  IOD34
D35  IOD35
D36  TCK  in
D37  IOD37
D38  IOD38
D39  IOD39
E1  IOE1
E2  GND  pwr
E3  IOE3
E4  IOE4
E5  GND  pwr
E6  IOE6
E7  IOE7
E8  GND  pwr
E9  IOE9
E10  IOE10
E11  GND  pwr
E12  IOE12
E13  IOE13
E14  GND  pwr
E15  IOE15
E16  IOE16
E17  GND  pwr
E18  IOE18
E19  IOE19
E20  GND  pwr
E21  IOE21
E22  IOE22
E23  GND  pwr
E24  IOE24
E25  IOE25
E26  GND  pwr
E27  IOE27
E28  IOE28
E29  GND  pwr
E30  IOE30
E31  IOE31
E32  GND  pwr
E33  IOE33
E34  IOE34
E35  GND  pwr
E36  IOE36
E37  IOE37
E38  GND  pwr
E39  IOE39
F1  IOF1
F2  IOF2
F3  VCC  pwr
F4  IOF4
F5  MSEL1  in
F6  IOF6
F7  IOF7
F8  IOF8
F9  VCC  pwr
F11  IOF11
F12  IOF12
F13  IOF13
F14  IOF14
F15  IOF15
F16  IOF16
F17  IOF17
F18  IOF18
F19  VCC  pwr
F20  IOF20
F21  IOF21
F22  IOF22
F23  IOF23
F24  IOF24
F25  IOF25
F26  IOF26
F27  VCC  pwr
F28  IOF28
F29  IOF29
F30  IOF30
F31  IOF31
F32  IOF32
F33  IOF33
F34  TMS  in
F35  TDO  out
F36  IOF36
F37  VCC  pwr
F38  IOF38
F39  IOF39
G1  IOG1
G2  IOG2
G3  IOG3
G4  IOG4
G5  TEMPDIODEN  pas
G6  VCC  pwr
G7  IOG7
G8  IOG8
G9  IOG9
G10  IOG10
G11  IOG11
G12  IOG12
G13  VCC  pwr
G14  IOG14
G15  IOG15
G16  VCC  pwr
G17  IOG17
G18  IOG18
G19  IOG19
G21  IOG21
G22  VCC  pwr
G24  VCC  pwr
G25  IOG25
G26  IOG26
G27  IOG27
G28  IOG28
G29  IOG29
G30  VCC  pwr
G31  IOG31
G32  IOG32
G33  IOG33
G34  TDI  in
G35  IOG35
G36  IOG36
G37  IOG37
G38  IOG38
G39  IOG39
H1  IOH1
H2  GND  pwr
H3  IOH3
H4  IOH4
H5  GND  pwr
H6  TEMPDIODEP  pas
H7  NC4  pas
H8  GND  pwr
H9  IOH9
H10  IOH10
H11  GND  pwr
H12  IOH12
H13  IOH13
H14  GND  pwr
H15  IOH15
H17  GND  pwr
H18  IOH18
H19  IOH19
H20  GND  pwr
H21  IOH21
H22  IOH22
H23  GND  pwr
H25  IOH25
H26  GND  pwr
H27  IOH27
H29  GND  pwr
H30  IOH30
H31  IOH31
H32  GND  pwr
H33  NC1  pas
H34  IOH34
H35  GND  pwr
H36  IOH36
H37  IOH37
H38  GND  pwr
H39  IOH39
J1  IOJ1
J2  IOJ2
J3  IOJ3
J4  IOJ4
J5  IOJ5
J6  IOJ6
J7  IOJ7
J8  VCC  pwr
J9  IOJ9
J10  VCC  pwr
J11  IOJ11
J12  IOJ12
J13  IOJ13
J14  IOJ14
J15  IOJ15
J16  IOJ16
J17  IOJ17
J18  VCC  pwr
J19  VCC  pwr
J20  VCC  pwr
J21  VCC  pwr
J22  IOJ22
J23  IOJ23
J24  IOJ24
J25  IOJ25
J26  IOJ26
J27  IOJ27
J28  VCC  pwr
J29  IOJ29
J30  IOJ30
J31  IOJ31
J32  VCC  pwr
J33  IOJ33
J34  IOJ34
J35  IOJ35
J36  IOJ36
J37  IOJ37
J38  IOJ38
J39  IOJ39
K1  IOK1
K2  IOK2
K3  VCC  pwr
K4  IOK4
K5  IOK5
K6  IOK6
K7  IOK7
K8  VCC  pwr
K9  VCC  pwr
K10  IOK10
K11  IOK11
K12  IOK12
K13  IOK13
K14  IOK14
K15  VCC  pwr
K16  IOK16
K17  IOK17
K18  IOK18
K19  VCC  pwr
K20  VCC  pwr
K21  VCC  pwr
K22  IOK22
K23  IOK23
K24  VCC  pwr
K25  IOK25
K26  IOK26
K27  IOK27
K28  IOK28
K29  IOK29
K30  VCC  pwr
K32  IOK32
K33  VCC  pwr
K34  IOK34
K35  IOK35
K36  VCC  pwr
K37  IOK37
K38  IOK38
K39  IOK39
L1  IOL1
L2  GND  pwr
L3  IOL3
L4  IOL4
L5  GND  pwr
L6  IOL6
L7  IOL7
L8  GND  pwr
L9  VCC  pwr
L11  GND  pwr
L12  IOL12
L13  IOL13
L14  GND  pwr
L15  IOL15
L16  IOL16
L17  GND  pwr
L18  IOL18
L19  VCC  pwr
L20  GND  pwr
L21  IOL21
L22  IOL22
L23  GND  pwr
L24  IOL24
L25  IOL25
L26  GND  pwr
L27  IOL27
L28  IOL28
L29  GND  pwr
L30  NC8  pas
L31  VCC  pwr
L32  GND  pwr
L33  IOL33
L34  IOL34
L35  GND  pwr
L36  IOL36
L37  IOL37
L38  GND  pwr
L39  IOL39
M1  IOM1
M2  IOM2
M3  IOM3
M4  IOM4
M5  IOM5
M6  VCC  pwr
M7  IOM7
M8  IOM8
M9  IOM9
M10  VCC  pwr
M11  MSEL0  in
M12  VCC  pwr
M13  IOM13
M14  IOM14
M15  IOM15
M16  IOM16
M17  IOM17
M18  IOM18
M19  IOM19
M20  IOM20
M21  IOM21
M22  IOM22
M23  IOM23
M24  IOM24
M25  IOM25
M26  IOM26
M27  IOM27
M28  IOM28
M29  IOM29
M30  VCC  pwr
M31  VCC  pwr
M32  IOM32
M33  IOM33
M34  IOM34
M35  IOM35
M36  IOM36
M37  VCC  pwr
M38  IOM38
M39  IOM39
N1  ION1
N2  ION2
N3  VCC  pwr
N4  ION4
N5  ION5
N6  ION6
N7  ION7
N8  ION8
N9  ION9
N10  ION10
N11  ION11
N12  NC6  pas
N13  ION13
N14  VCC  pwr
N15  GND  pwr
N16  VCC  pwr
N17  GND  pwr
N18  VCC  pwr
N19  GND  pwr
N20  VCC  pwr
N21  GND  pwr
N22  VCC  pwr
N23  GND  pwr
N24  VCC  pwr
N25  ION25
N26  ION26
N27  ION27
N28  NC7  pas
N29  ION29
N30  ION30
N31  ION31
N32  ION32
N33  ION33
N34  ION34
N35  ION35
N36  ION36
N37  ION37
N38  ION38
N39  ION39
P1  IOP1
P2  GND  pwr
P3  IOP3
P4  IOP4
P5  GND  pwr
P6  IOP6
P7  IOP7
P8  GND  pwr
P9  IOP9
P10  IOP10
P11  GND  pwr
P12  IOP12
P13  VCC  pwr
P14  GND  pwr
P15  VCC  pwr
P16  GND  pwr
P17  VCC  pwr
P18  GND  pwr
P19  VCC  pwr
P20  GND  pwr
P21  VCC  pwr
P22  GND  pwr
P23  VCC  pwr
P24  GND  pwr
P25  VCC  pwr
P26  GND  pwr
P27  VCC  pwr
P28  IOP28
P29  GND  pwr
P30  IOP30
P31  IOP31
P32  GND  pwr
P33  IOP33
P34  IOP34
P35  GND  pwr
P36  IOP36
P37  IOP37
P38  GND  pwr
P39  IOP39
R1  IOR1
R2  IOR2
R3  IOR3
R4  IOR4
R5  IOR5
R6  IOR6
R7  VCC  pwr
R8  IOR8
R9  IOR9
R10  IOR10
R11  IOR11
R12  IOR12
R13  IOR13
R14  VCC  pwr
R15  GND  pwr
R16  VCC  pwr
R17  GND  pwr
R18  VCC  pwr
R19  GND  pwr
R20  VCC  pwr
R21  GND  pwr
R22  VCC  pwr
R23  GND  pwr
R24  VCC  pwr
R25  GND  pwr
R26  IOR26
R27  IOR27
R28  VCC  pwr
R29  IOR29
R30  IOR30
R31  IOR31
R33  VCC  pwr
R34  IOR34
R35  IOR35
R36  IOR36
R37  IOR37
R38  IOR38
R39  IOR39
T1  IOT1
T2  IOT2
T3  VCC  pwr
T4  IOT4
T5  IOT5
T6  IOT6
T7  IOT7
T9  IOT9
T10  IOT10
T11  IOT11
T12  IOT12
T13  VCC  pwr
T14  GND  pwr
T15  VCC  pwr
T16  GND  pwr
T17  VCC  pwr
T18  GND  pwr
T19  VCC  pwr
T20  GND  pwr
T21  VCC  pwr
T22  GND  pwr
T23  VCC  pwr
T24  GND  pwr
T25  VCC  pwr
T26  GND  pwr
T27  VCC  pwr
T28  IOT28
T29  IOT29
T30  IOT30
T31  IOT31
T32  IOT32
T33  IOT33
T34  IOT34
T35  IOT35
T36  IOT36
T37  VCC  pwr
T38  IOT38
T39  IOT39
U1  IOU1
U2  GND  pwr
U3  IOU3
U4  IOU4
U5  GND  pwr
U6  IOU6
U7  IOU7
U8  GND  pwr
U9  IOU9
U10  IOU10
U11  GND  pwr
U12  IOU12
U13  IOU13
U14  VCC  pwr
U15  GND  pwr
U16  VCC  pwr
U17  GND  pwr
U18  VCC  pwr
U19  GND  pwr
U20  VCC  pwr
U21  GND  pwr
U22  VCC  pwr
U23  GND  pwr
U24  VCC  pwr
U25  GND  pwr
U26  VCC  pwr
U27  GND  pwr
U28  IOU28
U29  GND  pwr
U30  IOU30
U31  IOU31
U32  GND  pwr
U33  IOU33
U34  IOU34
U35  GND  pwr
U36  IOU36
U37  IOU37
U38  GND  pwr
U39  IOU39
V1  IOV1
V2  IOV2
V3  IOV3
V4  IOV4
V5  IOV5
V6  IOV6
V7  VCC  pwr
V8  IOV8
V9  IOV9
V10  VCC  pwr
V11  IOV11
V12  IOV12
V13  VCC  pwr
V14  GND  pwr
V15  VCC  pwr
V16  GND  pwr
V17  VCC  pwr
V18  GND  pwr
V19  VCC  pwr
V20  GND  pwr
V21  VCC  pwr
V22  GND  pwr
V23  VCC  pwr
V24  GND  pwr
V25  VCC  pwr
V26  GND  pwr
V27  VCC  pwr
V28  IOV28
V29  IOV29
V30  VCC  pwr
V31  IOV31
V33  IOV33
V34  VCC  pwr
V35  IOV35
V36  IOV36
V37  IOV37
V38  IOV38
V39  IOV39
W1  CLK10N  in
W2  CLK10P  in
W3  IOW3
W4  IOW4
W5  IOW5
W6  IOW6
W7  IOW7
W8  VCC  pwr
W9  VCC  pwr
W10  IOW10
W11  IOW11
W12  IOW12
W13  GND  pwr
W14  VCC  pwr
W15  GND  pwr
W16  VCC  pwr
W17  GND  pwr
W18  VCC  pwr
W19  DNU  pas
W20  VCC  pwr
W21  GND  pwr
W22  VCC  pwr
W23  GND  pwr
W24  VCC  pwr
W25  GND  pwr
W26  VCC  pwr
W27  GND  pwr
W28  IOW28
W29  IOW29
W30  IOW30
W31  VCC  pwr
W32  VCC  pwr
W33  IOW33
W34  IOW34
W35  IOW35
W36  IOW36
W37  IOW37
W38  CLK1P  in
W39  CLK1N  in
Y1  VCC  pwr
Y2  GND  pwr
Y3  IOY3
Y4  IOY4
Y5  GND  pwr
Y7  VCC  pwr
Y8  GND  pwr
Y9  IOY9
Y10  IOY10
Y11  GND  pwr
Y12  IOY12
Y13  VCC  pwr
Y14  GND  pwr
Y15  VCC  pwr
Y16  GND  pwr
Y17  VCC  pwr
Y18  GND  pwr
Y19  VCC  pwr
Y20  GND  pwr
Y21  VCC  pwr
Y22  GND  pwr
Y23  VCC  pwr
Y24  GND  pwr
Y25  VCC  pwr
Y26  GND  pwr
Y27  VCC  pwr
Y28  IOY28
Y29  GND  pwr
Y30  IOY30
Y31  IOY31
Y32  GND  pwr
Y33  VCC  pwr
Y35  GND  pwr
Y36  IOY36
Y37  IOY37
Y38  GND  pwr
Y39  VCC  pwr

## Footprint FBGA1517 (pad centres in mm)
1517-Pin FineLine Ball-Grid Array (FBGA), Option 1 ? Flip Chip Auto generated by make-symbol-device-package-bsdl.ulp Rev. 29 Source: EP4S40G2F40ES1.bsd http://www.altera.com .. dspkg.pdf
smd 0.7 x 0.7: A1 -19,19; A2 -18,19; A3 -17,19; A4 -16,19; A5 -15,19; A6 -14,19; A7 -13,19; A8 -12,19; A9 -11,19; A10 -10,19; A11 -9,19; A12 -8,19; A13 -7,19; A14 -6,19; A15 -5,19; A16 -4,19; A17 -3,19; A18 -2,19; A19 -1,19; A20 0,19; A21 1,19; A22 2,19; A23 3,19; A24 4,19; A25 5,19; A26 6,19; A27 7,19; A28 8,19; A29 9,19; A30 10,19; A31 11,19; A32 12,19; A33 13,19; A34 14,19; A35 15,19; A36 16,19; A37 17,19; A38 18,19; AA1 -19,-1; AA2 -18,-1; AA3 -17,-1; AA4 -16,-1; AA5 -15,-1; AA6 -14,-1; AA7 -13,-1; AA8 -12,-1; AA9 -11,-1; AA10 -10,-1; AA11 -9,-1; AA12 -8,-1; AA13 -7,-1; AA14 -6,-1; AA15 -5,-1; AA16 -4,-1; AA17 -3,-1; AA18 -2,-1; AA19 -1,-1; AA20 0,-1; AA21 1,-1; AA22 2,-1; AA23 3,-1; AA24 4,-1; AA25 5,-1; AA26 6,-1; AA27 7,-1; AA28 8,-1; AA29 9,-1; AA30 10,-1; AA31 11,-1; AA32 12,-1; AA33 13,-1; AA34 14,-1; AA35 15,-1; AA36 16,-1; AA37 17,-1; AA38 18,-1; AA39 19,-1; AB1 -19,-2; AB2 -18,-2; AB3 -17,-2; AB4 -16,-2; AB5 -15,-2; AB6 -14,-2; AB7 -13,-2; AB8 -12,-2; AB9 -11,-2; AB10 -10,-2; AB11 -9,-2; AB12 -8,-2; AB13 -7,-2; AB14 -6,-2; AB15 -5,-2; AB16 -4,-2; AB17 -3,-2; AB18 -2,-2; AB19 -1,-2; AB20 0,-2; AB21 1,-2; AB22 2,-2; AB23 3,-2; AB24 4,-2; AB25 5,-2; AB26 6,-2; AB27 7,-2; AB28 8,-2; AB29 9,-2; AB30 10,-2; AB31 11,-2; AB32 12,-2; AB33 13,-2; AB34 14,-2; AB35 15,-2; AB36 16,-2; AB37 17,-2; AB38 18,-2; AB39 19,-2; AC1 -19,-3; AC2 -18,-3; AC3 -17,-3; AC4 -16,-3; AC5 -15,-3; AC6 -14,-3; AC7 -13,-3; AC8 -12,-3; AC9 -11,-3; AC10 -10,-3; AC11 -9,-3; AC12 -8,-3; AC13 -7,-3; AC14 -6,-3; AC15 -5,-3; AC16 -4,-3; AC17 -3,-3; AC18 -2,-3; AC19 -1,-3; AC20 0,-3; AC21 1,-3; AC22 2,-3; AC23 3,-3; AC24 4,-3; AC25 5,-3; AC26 6,-3; AC27 7,-3; AC28 8,-3; AC29 9,-3; AC30 10,-3; AC31 11,-3; AC32 12,-3; AC33 13,-3; AC34 14,-3; AC35 15,-3; AC36 16,-3; AC37 17,-3; AC38 18,-3; AC39 19,-3; AD1 -19,-4; AD2 -18,-4; AD3 -17,-4; AD4 -16,-4; AD5 -15,-4; AD6 -14,-4; AD7 -13,-4; AD8 -12,-4; AD9 -11,-4; AD10 -10,-4; AD11 -9,-4; AD12 -8,-4; AD13 -7,-4; AD14 -6,-4; AD15 -5,-4; AD16 -4,-4; AD17 -3,-4; AD18 -2,-4; AD19 -1,-4; AD20 0,-4; AD21 1,-4; AD22 2,-4; AD23 3,-4; AD24 4,-4; AD25 5,-4; AD26 6,-4; AD27 7,-4; AD28 8,-4; AD29 9,-4; AD30 10,-4; AD31 11,-4; AD32 12,-4; AD33 13,-4; AD34 14,-4; AD35 15,-4; AD36 16,-4; AD37 17,-4; AD38 18,-4; AD39 19,-4; AE1 -19,-5; AE2 -18,-5; AE3 -17,-5; AE4 -16,-5; AE5 -15,-5; AE6 -14,-5; AE7 -13,-5; AE8 -12,-5; AE9 -11,-5; AE10 -10,-5; AE11 -9,-5; AE12 -8,-5; AE13 -7,-5; AE14 -6,-5; AE15 -5,-5; AE16 -4,-5; AE17 -3,-5; AE18 -2,-5; AE19 -1,-5; AE20 0,-5; AE21 1,-5; AE22 2,-5; AE23 3,-5; AE24 4,-5; AE25 5,-5; AE26 6,-5; AE27 7,-5; AE28 8,-5; AE29 9,-5; AE30 10,-5; AE31 11,-5; AE32 12,-5; AE33 13,-5; AE34 14,-5; AE35 15,-5; AE36 16,-5; AE37 17,-5; AE38 18,-5; AE39 19,-5; AF1 -19,-6; AF2 -18,-6; AF3 -17,-6; AF4 -16,-6; AF5 -15,-6; AF6 -14,-6; AF7 -13,-6; AF8 -12,-6; AF9 -11,-6; AF10 -10,-6; AF11 -9,-6; AF12 -8,-6; AF13 -7,-6; AF14 -6,-6; AF15 -5,-6; AF16 -4,-6; AF17 -3,-6; AF18 -2,-6; AF19 -1,-6; AF20 0,-6; AF21 1,-6; AF22 2,-6; AF23 3,-6; AF24 4,-6; AF25 5,-6; AF26 6,-6; AF27 7,-6; AF28 8,-6; AF29 9,-6; AF30 10,-6; AF31 11,-6; AF32 12,-6; AF33 13,-6; AF34 14,-6; AF35 15,-6; AF36 16,-6; AF37 17,-6; AF38 18,-6; AF39 19,-6; AG1 -19,-7; AG2 -18,-7; AG3 -17,-7; AG4 -16,-7; AG5 -15,-7; AG6 -14,-7; AG7 -13,-7; AG8 -12,-7; AG9 -11,-7; AG10 -10,-7; AG11 -9,-7; AG12 -8,-7; AG13 -7,-7; AG14 -6,-7; AG15 -5,-7; AG16 -4,-7; AG17 -3,-7; AG18 -2,-7; AG19 -1,-7; AG20 0,-7; AG21 1,-7; AG22 2,-7; AG23 3,-7; AG24 4,-7; AG25 5,-7; AG26 6,-7; AG27 7,-7; AG28 8,-7; AG29 9,-7; AG30 10,-7; AG31 11,-7; AG32 12,-7; AG33 13,-7; AG34 14,-7; AG35 15,-7; AG36 16,-7; AG37 17,-7; AG38 18,-7; AG39 19,-7; AH1 -19,-8; AH2 -18,-8; AH3 -17,-8; AH4 -16,-8; AH5 -15,-8; AH6 -14,-8; AH7 -13,-8; AH8 -12,-8; AH9 -11,-8; AH10 -10,-8; AH11 -9,-8; AH12 -8,-8; AH13 -7,-8; AH14 -6,-8; AH15 -5,-8; AH16 -4,-8; AH17 -3,-8; AH18 -2,-8; AH19 -1,-8; AH20 0,-8; AH21 1,-8; AH22 2,-8; AH23 3,-8; AH24 4,-8; AH25 5,-8; AH26 6,-8; AH27 7,-8; AH28 8,-8; AH29 9,-8; AH30 10,-8; AH31 11,-8; AH32 12,-8; AH33 13,-8; AH34 14,-8; AH35 15,-8; AH36 16,-8; AH37 17,-8; AH38 18,-8; AH39 19,-8; AJ1 -19,-9; AJ2 -18,-9; AJ3 -17,-9; AJ4 -16,-9; AJ5 -15,-9; AJ6 -14,-9; AJ7 -13,-9; AJ8 -12,-9; AJ9 -11,-9; AJ10 -10,-9; AJ11 -9,-9; AJ12 -8,-9; AJ13 -7,-9; AJ14 -6,-9; AJ15 -5,-9; AJ16 -4,-9; AJ17 -3,-9; AJ18 -2,-9; AJ19 -1,-9; AJ20 0,-9; AJ21 1,-9; AJ22 2,-9; AJ23 3,-9; AJ24 4,-9; AJ25 5,-9; AJ26 6,-9; AJ27 7,-9; AJ28 8,-9; AJ29 9,-9; AJ30 10,-9; AJ31 11,-9; AJ32 12,-9; AJ33 13,-9; AJ34 14,-9; AJ35 15,-9; AJ36 16,-9; AJ37 17,-9; AJ38 18,-9; AJ39 19,-9; AK1 -19,-10; AK2 -18,-10; AK3 -17,-10; AK4 -16,-10; AK5 -15,-10; AK6 -14,-10; AK7 -13,-10; AK8 -12,-10; AK9 -11,-10; AK10 -10,-10; AK11 -9,-10; AK12 -8,-10; AK13 -7,-10; AK14 -6,-10; AK15 -5,-10; AK16 -4,-10; AK17 -3,-10; AK18 -2,-10; AK19 -1,-10; AK20 0,-10; AK21 1,-10; AK22 2,-10; AK23 3,-10; AK24 4,-10; AK25 5,-10; AK26 6,-10; AK27 7,-10; AK28 8,-10; AK29 9,-10; AK30 10,-10; AK31 11,-10; AK32 12,-10; AK33 13,-10; AK34 14,-10; AK35 15,-10; AK36 16,-10; AK37 17,-10; AK38 18,-10; AK39 19,-10; AL1 -19,-11; AL2 -18,-11; AL3 -17,-11; AL4 -16,-11; AL5 -15,-11; AL6 -14,-11; AL7 -13,-11; AL8 -12,-11; AL9 -11,-11; AL10 -10,-11; AL11 -9,-11; AL12 -8,-11; AL13 -7,-11; AL14 -6,-11; AL15 -5,-11; AL16 -4,-11; AL17 -3,-11; AL18 -2,-11; AL19 -1,-11; AL20 0,-11; AL21 1,-11; AL22 2,-11; AL23 3,-11; AL24 4,-11; AL25 5,-11; AL26 6,-11; AL27 7,-11; AL28 8,-11; AL29 9,-11; AL30 10,-11; AL31 11,-11; AL32 12,-11; AL33 13,-11; AL34 14,-11; AL35 15,-11; AL36 16,-11; AL37 17,-11; AL38 18,-11; AL39 19,-11; AM1 -19,-12; AM2 -18,-12; AM3 -17,-12; AM4 -16,-12; AM5 -15,-12; AM6 -14,-12; AM7 -13,-12; AM8 -12,-12; AM9 -11,-12; AM10 -10,-12; AM11 -9,-12; AM12 -8,-12; AM13 -7,-12; AM14 -6,-12; AM15 -5,-12; AM16 -4,-12; AM17 -3,-12; AM18 -2,-12; AM19 -1,-12; AM20 0,-12; AM21 1,-12; AM22 2,-12; AM23 3,-12; AM24 4,-12; AM25 5,-12; AM26 6,-12; AM27 7,-12; AM28 8,-12; AM29 9,-12; AM30 10,-12; AM31 11,-12; AM32 12,-12; AM33 13,-12; AM34 14,-12; AM35 15,-12; AM36 16,-12; AM37 17,-12; AM38 18,-12; AM39 19,-12; AN1 -19,-13; AN2 -18,-13; AN3 -17,-13; AN4 -16,-13; AN5 -15,-13; AN6 -14,-13; AN7 -13,-13; AN8 -12,-13; AN9 -11,-13; AN10 -10,-13; AN11 -9,-13; AN12 -8,-13; AN13 -7,-13; AN14 -6,-13; AN15 -5,-13; AN16 -4,-13; AN17 -3,-13; AN18 -2,-13; AN19 -1,-13; AN20 0,-13; AN21 1,-13; AN22 2,-13; AN23 3,-13; AN24 4,-13; AN25 5,-13; AN26 6,-13; AN27 7,-13; AN28 8,-13; AN29 9,-13; AN30 10,-13; AN31 11,-13; AN32 12,-13; AN33 13,-13; AN34 14,-13; AN35 15,-13; AN36 16,-13; AN37 17,-13; AN38 18,-13; AN39 19,-13; AP1 -19,-14; AP2 -18,-14; AP3 -17,-14; AP4 -16,-14; AP5 -15,-14; AP6 -14,-14; AP7 -13,-14; AP8 -12,-14; AP9 -11,-14; AP10 -10,-14; AP11 -9,-14; AP12 -8,-14; AP13 -7,-14; AP14 -6,-14; AP15 -5,-14; AP16 -4,-14; AP17 -3,-14; AP18 -2,-14; AP19 -1,-14; AP20 0,-14; AP21 1,-14; AP22 2,-14; AP23 3,-14; AP24 4,-14; AP25 5,-14; AP26 6,-14; AP27 7,-14; AP28 8,-14; AP29 9,-14; AP30 10,-14; AP31 11,-14; AP32 12,-14; AP33 13,-14; AP34 14,-14; AP35 15,-14; AP36 16,-14; AP37 17,-14; AP38 18,-14; AP39 19,-14; AR1 -19,-15; AR2 -18,-15; AR3 -17,-15; AR4 -16,-15; AR5 -15,-15; AR6 -14,-15; AR7 -13,-15; AR8 -12,-15; AR9 -11,-15; AR10 -10,-15; AR11 -9,-15; AR12 -8,-15; AR13 -7,-15; AR14 -6,-15; AR15 -5,-15; AR16 -4,-15; AR17 -3,-15; AR18 -2,-15; AR19 -1,-15; AR20 0,-15; AR21 1,-15; AR22 2,-15; AR23 3,-15; AR24 4,-15; AR25 5,-15; AR26 6,-15; AR27 7,-15; AR28 8,-15; AR29 9,-15; AR30 10,-15; AR31 11,-15; AR32 12,-15; AR33 13,-15; AR34 14,-15; AR35 15,-15; AR36 16,-15; AR37 17,-15; AR38 18,-15; AR39 19,-15; AT1 -19,-16; AT2 -18,-16; AT3 -17,-16; AT4 -16,-16; AT5 -15,-16; AT6 -14,-16; AT7 -13,-16; AT8 -12,-16; AT9 -11,-16; AT10 -10,-16; AT11 -9,-16; AT12 -8,-16; AT13 -7,-16; AT14 -6,-16; AT15 -5,-16; AT16 -4,-16; AT17 -3,-16; AT18 -2,-16; AT19 -1,-16; AT20 0,-16; AT21 1,-16; AT22 2,-16; AT23 3,-16; AT24 4,-16; AT25 5,-16; AT26 6,-16; AT27 7,-16; AT28 8,-16; AT29 9,-16; AT30 10,-16; AT31 11,-16; AT32 12,-16; AT33 13,-16; AT34 14,-16; AT35 15,-16; AT36 16,-16; AT37 17,-16; AT38 18,-16; AT39 19,-16; AU1 -19,-17; AU2 -18,-17; AU3 -17,-17; AU4 -16,-17; AU5 -15,-17; AU6 -14,-17; AU7 -13,-17; AU8 -12,-17; AU9 -11,-17; AU10 -10,-17; AU11 -9,-17; AU12 -8,-17; AU13 -7,-17; AU14 -6,-17; AU15 -5,-17; AU16 -4,-17; AU17 -3,-17; AU18 -2,-17; AU19 -1,-17; AU20 0,-17; AU21 1,-17; AU22 2,-17; AU23 3,-17; AU24 4,-17; AU25 5,-17; AU26 6,-17; AU27 7,-17; AU28 8,-17; AU29 9,-17; AU30 10,-17; AU31 11,-17; AU32 12,-17; AU33 13,-17; AU34 14,-17; AU35 15,-17; AU36 16,-17; AU37 17,-17; AU38 18,-17; AU39 19,-17; AV1 -19,-18; AV2 -18,-18; AV3 -17,-18; AV4 -16,-18; AV5 -15,-18; AV6 -14,-18; AV7 -13,-18; AV8 -12,-18; AV9 -11,-18; AV10 -10,-18; AV11 -9,-18; AV12 -8,-18; AV13 -7,-18; AV14 -6,-18; AV15 -5,-18; AV16 -4,-18; AV17 -3,-18; AV18 -2,-18; AV19 -1,-18; AV20 0,-18; AV21 1,-18; AV22 2,-18; AV23 3,-18; AV24 4,-18; AV25 5,-18; AV26 6,-18; AV27 7,-18; AV28 8,-18; AV29 9,-18; AV30 10,-18; AV31 11,-18; AV32 12,-18; AV33 13,-18; AV34 14,-18; AV35 15,-18; AV36 16,-18; AV37 17,-18; AV38 18,-18; AV39 19,-18; AW2 -18,-19; AW3 -17,-19; AW4 -16,-19; AW5 -15,-19; AW6 -14,-19; AW7 -13,-19; AW8 -12,-19; AW9 -11,-19; AW10 -10,-19; AW11 -9,-19; AW12 -8,-19; AW13 -7,-19; AW14 -6,-19; AW15 -5,-19; AW16 -4,-19; AW17 -3,-19; AW18 -2,-19; AW19 -1,-19; AW20 0,-19; AW21 1,-19; AW22 2,-19; AW23 3,-19; AW24 4,-19; AW25 5,-19; AW26 6,-19; AW27 7,-19; AW28 8,-19; AW29 9,-19; AW30 10,-19; AW31 11,-19; AW32 12,-19; AW33 13,-19; AW34 14,-19; AW35 15,-19; AW36 16,-19; AW37 17,-19; AW38 18,-19; B1 -19,18; B2 -18,18; B3 -17,18; B4 -16,18; B5 -15,18; B6 -14,18; B7 -13,18; B8 -12,18; B9 -11,18; B10 -10,18; B11 -9,18; B12 -8,18; B13 -7,18; B14 -6,18; B15 -5,18; B16 -4,18; B17 -3,18; B18 -2,18; B19 -1,18; B20 0,18; B21 1,18; B22 2,18; B23 3,18; B24 4,18; B25 5,18; B26 6,18; B27 7,18; B28 8,18; B29 9,18; B30 10,18; B31 11,18; B32 12,18; B33 13,18; B34 14,18; B35 15,18; B36 16,18; B37 17,18; B38 18,18; B39 19,18; C1 -19,17; C2 -18,17; C3 -17,17; C4 -16,17; C5 -15,17; C6 -14,17; C7 -13,17; C8 -12,17; C9 -11,17; C10 -10,17; C11 -9,17; C12 -8,17; C13 -7,17; C14 -6,17; C15 -5,17; C16 -4,17; C17 -3,17; C18 -2,17; C19 -1,17; C20 0,17; C21 1,17; C22 2,17; C23 3,17; C24 4,17; C25 5,17; C26 6,17; C27 7,17; C28 8,17; C29 9,17; C30 10,17; C31 11,17; C32 12,17; C33 13,17; C34 14,17; C35 15,17; C36 16,17; C37 17,17; C38 18,17; C39 19,17; D1 -19,16; D2 -18,16; D3 -17,16; D4 -16,16; D5 -15,16; D6 -14,16; D7 -13,16; D8 -12,16; D9 -11,16; D10 -10,16; D11 -9,16; D12 -8,16; D13 -7,16; D14 -6,16; D15 -5,16; D16 -4,16; D17 -3,16; D18 -2,16; D19 -1,16; D20 0,16; D21 1,16; D22 2,16; D23 3,16; D24 4,16; D25 5,16; D26 6,16; D27 7,16; D28 8,16; D29 9,16; D30 10,16; D31 11,16; D32 12,16; D33 13,16; D34 14,16; D35 15,16; D36 16,16; D37 17,16; D38 18,16; D39 19,16; E1 -19,15; E2 -18,15; E3 -17,15; E4 -16,15; E5 -15,15; E6 -14,15; E7 -13,15; E8 -12,15; E9 -11,15; E10 -10,15; E11 -9,15; E12 -8,15; E13 -7,15; E14 -6,15; E15 -5,15; E16 -4,15; E17 -3,15; E18 -2,15; E19 -1,15; E20 0,15; E21 1,15; E22 2,15; E23 3,15; E24 4,15; E25 5,15; E26 6,15; E27 7,15; E28 8,15; E29 9,15; E30 10,15; E31 11,15; E32 12,15; E33 13,15; E34 14,15; E35 15,15; E36 16,15; E37 17,15; E38 18,15; E39 19,15; F1 -19,14; F2 -18,14; F3 -17,14; F4 -16,14; F5 -15,14; F6 -14,14; F7 -13,14; F8 -12,14; F9 -11,14; F10 -10,14; F11 -9,14; F12 -8,14; F13 -7,14; F14 -6,14; F15 -5,14; F16 -4,14; F17 -3,14; F18 -2,14; F19 -1,14; F20 0,14; F21 1,14; F22 2,14; F23 3,14; F24 4,14; F25 5,14; F26 6,14; F27 7,14; F28 8,14; F29 9,14; F30 10,14; F31 11,14; F32 12,14; F33 13,14; F34 14,14; F35 15,14; F36 16,14; F37 17,14; F38 18,14; F39 19,14; G1 -19,13; G2 -18,13; G3 -17,13; G4 -16,13; G5 -15,13; G6 -14,13; G7 -13,13; G8 -12,13; G9 -11,13; G10 -10,13; G11 -9,13; G12 -8,13; G13 -7,13; G14 -6,13; G15 -5,13; G16 -4,13; G17 -3,13; G18 -2,13; G19 -1,13; G20 0,13; G21 1,13; G22 2,13; G23 3,13; G24 4,13; G25 5,13; G26 6,13; G27 7,13; G28 8,13; G29 9,13; G30 10,13; G31 11,13; G32 12,13; G33 13,13; G34 14,13; G35 15,13; G36 16,13; G37 17,13; G38 18,13; G39 19,13; H1 -19,12; H2 -18,12; H3 -17,12; H4 -16,12; H5 -15,12; H6 -14,12; H7 -13,12; H8 -12,12; H9 -11,12; H10 -10,12; H11 -9,12; H12 -8,12; H13 -7,12; H14 -6,12; H15 -5,12; H16 -4,12; H17 -3,12; H18 -2,12; H19 -1,12; H20 0,12; H21 1,12; H22 2,12; H23 3,12; H24 4,12; H25 5,12; H26 6,12; H27 7,12; H28 8,12; H29 9,12; H30 10,12; H31 11,12; H32 12,12; H33 13,12; H34 14,12; H35 15,12; H36 16,12; H37 17,12; H38 18,12; H39 19,12; J1 -19,11; J2 -18,11; J3 -17,11; J4 -16,11; J5 -15,11; J6 -14,11; J7 -13,11; J8 -12,11; J9 -11,11; J10 -10,11; J11 -9,11; J12 -8,11; J13 -7,11; J14 -6,11; J15 -5,11; J16 -4,11; J17 -3,11; J18 -2,11; J19 -1,11; J20 0,11; J21 1,11; J22 2,11; J23 3,11; J24 4,11; J25 5,11; J26 6,11; J27 7,11; J28 8,11; J29 9,11; J30 10,11; J31 11,11; J32 12,11; J33 13,11; J34 14,11; J35 15,11; J36 16,11; J37 17,11; J38 18,11; J39 19,11; K1 -19,10; K2 -18,10; K3 -17,10; K4 -16,10; K5 -15,10; K6 -14,10; K7 -13,10; K8 -12,10; K9 -11,10; K10 -10,10; K11 -9,10; K12 -8,10; K13 -7,10; K14 -6,10; K15 -5,10; K16 -4,10; K17 -3,10; K18 -2,10; K19 -1,10; K20 0,10; K21 1,10; K22 2,10; K23 3,10; K24 4,10; K25 5,10; K26 6,10; K27 7,10; K28 8,10; K29 9,10; K30 10,10; K31 11,10; K32 12,10; K33 13,10; K34 14,10; K35 15,10; K36 16,10; K37 17,10; K38 18,10; K39 19,10; L1 -19,9; L2 -18,9; L3 -17,9; L4 -16,9; L5 -15,9; L6 -14,9; L7 -13,9; L8 -12,9; L9 -11,9; L10 -10,9; L11 -9,9; L12 -8,9; L13 -7,9; L14 -6,9; L15 -5,9; L16 -4,9; L17 -3,9; L18 -2,9; L19 -1,9; L20 0,9; L21 1,9; L22 2,9; L23 3,9; L24 4,9; L25 5,9; L26 6,9; L27 7,9; L28 8,9; L29 9,9; L30 10,9; L31 11,9; L32 12,9; L33 13,9; L34 14,9; L35 15,9; L36 16,9; L37 17,9; L38 18,9; L39 19,9; M1 -19,8; M2 -18,8; M3 -17,8; M4 -16,8; M5 -15,8; M6 -14,8; M7 -13,8; M8 -12,8; M9 -11,8; M10 -10,8; M11 -9,8; M12 -8,8; M13 -7,8; M14 -6,8; M15 -5,8; M16 -4,8; M17 -3,8; M18 -2,8; M19 -1,8; M20 0,8; M21 1,8; M22 2,8; M23 3,8; M24 4,8; M25 5,8; M26 6,8; M27 7,8; M28 8,8; M29 9,8; M30 10,8; M31 11,8; M32 12,8; M33 13,8; M34 14,8; M35 15,8; M36 16,8; M37 17,8; M38 18,8; M39 19,8; N1 -19,7; N2 -18,7; N3 -17,7; N4 -16,7; N5 -15,7; N6 -14,7; N7 -13,7; N8 -12,7; N9 -11,7; N10 -10,7; N11 -9,7; N12 -8,7; N13 -7,7; N14 -6,7; N15 -5,7; N16 -4,7; N17 -3,7; N18 -2,7; N19 -1,7; N20 0,7; N21 1,7; N22 2,7; N23 3,7; N24 4,7; N25 5,7; N26 6,7; N27 7,7; N28 8,7; N29 9,7; N30 10,7; N31 11,7; N32 12,7; N33 13,7; N34 14,7; N35 15,7; N36 16,7; N37 17,7; N38 18,7; N39 19,7; P1 -19,6; P2 -18,6; P3 -17,6; P4 -16,6; P5 -15,6; P6 -14,6; P7 -13,6; P8 -12,6; P9 -11,6; P10 -10,6; P11 -9,6; P12 -8,6; P13 -7,6; P14 -6,6; P15 -5,6; P16 -4,6; P17 -3,6; P18 -2,6; P19 -1,6; P20 0,6; P21 1,6; P22 2,6; P23 3,6; P24 4,6; P25 5,6; P26 6,6; P27 7,6; P28 8,6; P29 9,6; P30 10,6; P31 11,6; P32 12,6; P33 13,6; P34 14,6; P35 15,6; P36 16,6; P37 17,6; P38 18,6; P39 19,6; R1 -19,5; R2 -18,5; R3 -17,5; R4 -16,5; R5 -15,5; R6 -14,5; R7 -13,5; R8 -12,5; R9 -11,5; R10 -10,5; R11 -9,5; R12 -8,5; R13 -7,5; R14 -6,5; R15 -5,5; R16 -4,5; R17 -3,5; R18 -2,5; R19 -1,5; R20 0,5; R21 1,5; R22 2,5; R23 3,5; R24 4,5; R25 5,5; R26 6,5; R27 7,5; R28 8,5; R29 9,5; R30 10,5; R31 11,5; R32 12,5; R33 13,5; R34 14,5; R35 15,5; R36 16,5; R37 17,5; R38 18,5; R39 19,5; T1 -19,4; T2 -18,4; T3 -17,4; T4 -16,4; T5 -15,4; T6 -14,4; T7 -13,4; T8 -12,4; T9 -11,4; T10 -10,4; T11 -9,4; T12 -8,4; T13 -7,4; T14 -6,4; T15 -5,4; T16 -4,4; T17 -3,4; T18 -2,4; T19 -1,4; T20 0,4; T21 1,4; T22 2,4; T23 3,4; T24 4,4; T25 5,4; T26 6,4; T27 7,4; T28 8,4; T29 9,4; T30 10,4; T31 11,4; T32 12,4; T33 13,4; T34 14,4; T35 15,4; T36 16,4; T37 17,4; T38 18,4; T39 19,4; U1 -19,3; U2 -18,3; U3 -17,3; U4 -16,3; U5 -15,3; U6 -14,3; U7 -13,3; U8 -12,3; U9 -11,3; U10 -10,3; U11 -9,3; U12 -8,3; U13 -7,3; U14 -6,3; U15 -5,3; U16 -4,3; U17 -3,3; U18 -2,3; U19 -1,3; U20 0,3; U21 1,3; U22 2,3; U23 3,3; U24 4,3; U25 5,3; U26 6,3; U27 7,3; U28 8,3; U29 9,3; U30 10,3; U31 11,3; U32 12,3; U33 13,3; U34 14,3; U35 15,3; U36 16,3; U37 17,3; U38 18,3; U39 19,3; V1 -19,2; V2 -18,2; V3 -17,2; V4 -16,2; V5 -15,2; V6 -14,2; V7 -13,2; V8 -12,2; V9 -11,2; V10 -10,2; V11 -9,2; V12 -8,2; V13 -7,2; V14 -6,2; V15 -5,2; V16 -4,2; V17 -3,2; V18 -2,2; V19 -1,2; V20 0,2; V21 1,2; V22 2,2; V23 3,2; V24 4,2; V25 5,2; V26 6,2; V27 7,2; V28 8,2; V29 9,2; V30 10,2; V31 11,2; V32 12,2; V33 13,2; V34 14,2; V35 15,2; V36 16,2; V37 17,2; V38 18,2; V39 19,2; W1 -19,1; W2 -18,1; W3 -17,1; W4 -16,1; W5 -15,1; W6 -14,1; W7 -13,1; W8 -12,1; W9 -11,1; W10 -10,1; W11 -9,1; W12 -8,1; W13 -7,1; W14 -6,1; W15 -5,1; W16 -4,1; W17 -3,1; W18 -2,1; W19 -1,1; W20 0,1; W21 1,1; W22 2,1; W23 3,1; W24 4,1; W25 5,1; W26 6,1; W27 7,1; W28 8,1; W29 9,1; W30 10,1; W31 11,1; W32 12,1; W33 13,1; W34 14,1; W35 15,1; W36 16,1; W37 17,1; W38 18,1; W39 19,1; Y1 -19,0; Y2 -18,0; Y3 -17,0; Y4 -16,0; Y5 -15,0; Y6 -14,0; Y7 -13,0; Y8 -12,0; Y9 -11,0; Y10 -10,0; Y11 -9,0; Y12 -8,0; Y13 -7,0; Y14 -6,0; Y15 -5,0; Y16 -4,0; Y17 -3,0; Y18 -2,0; Y19 -1,0; Y20 0,0; Y21 1,0; Y22 2,0; Y23 3,0; Y24 4,0; Y25 5,0; Y26 6,0; Y27 7,0; Y28 8,0; Y29 9,0; Y30 10,0; Y31 11,0; Y32 12,0; Y33 13,0; Y34 14,0; Y35 15,0; Y36 16,0; Y37 17,0; Y38 18,0; Y39 19,0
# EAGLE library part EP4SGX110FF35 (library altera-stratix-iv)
EP4SGX110FF35 Auto generated by make-symbol-device-package-bsdl.ulp Rev. 29 Source: EP4SGX110FF35.bsd

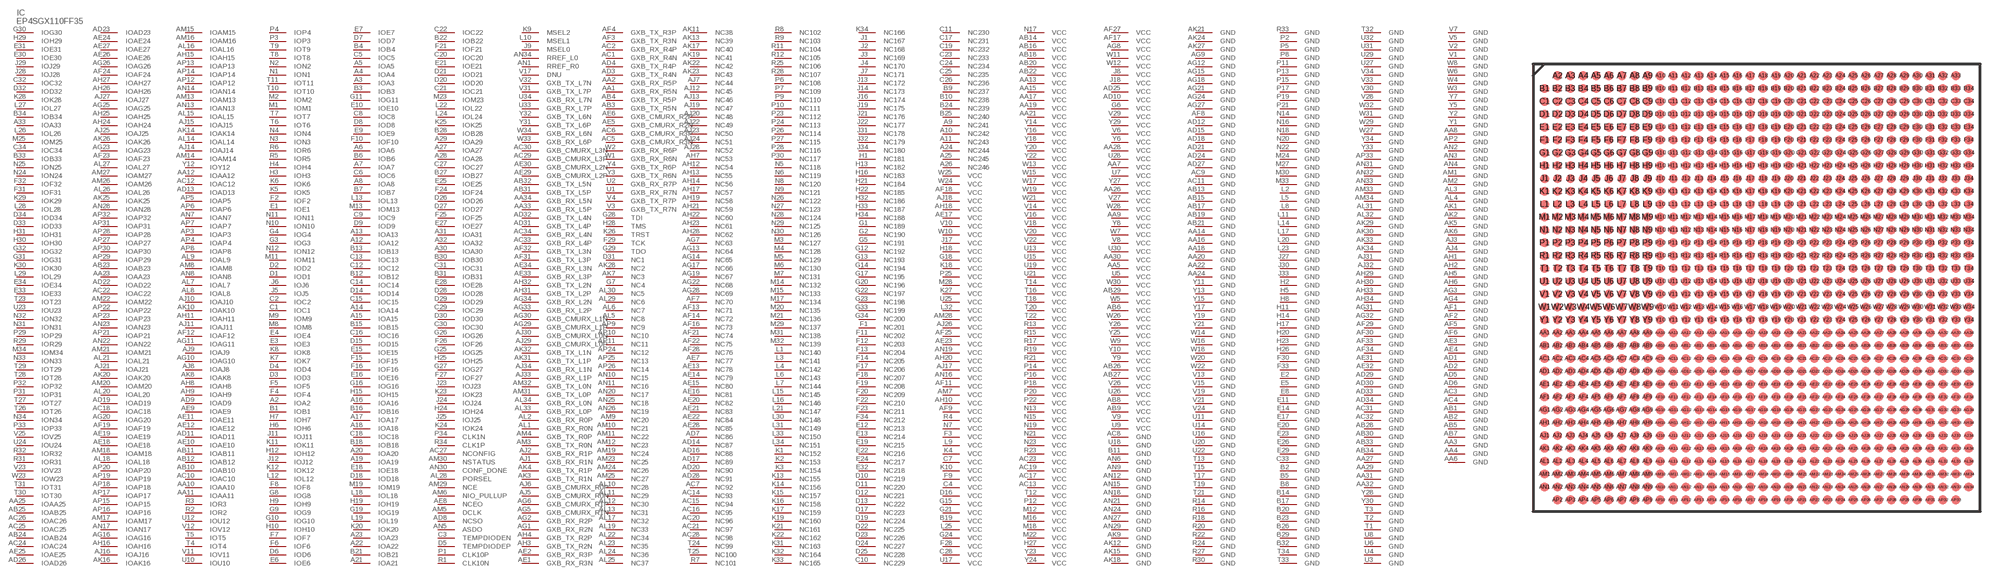
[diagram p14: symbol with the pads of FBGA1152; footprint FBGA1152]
Designator prefix IC

## EP4SGX110FF35 (MPN: EP4SGX110FF35C3N; OC_FARNELL: unknown; OC_NEWARK: 52R1762)  [FBGA1152]
A2  IOA2
A3  IOA3
A4  IOA4
A5  IOA5
A6  IOA6
A7  IOA7
A8  IOA8
A9  NC241  pas
A10  NC242  pas
A11  NC243  pas
A12  IOA12
A13  IOA13
A14  IOA14
A15  IOA15
A16  IOA16
A17  IOA17
A18  IOA18
A19  IOA19
A20  IOA20
A21  IOA21
A22  IOA22
A23  IOA23
A24  NC244  pas
A25  NC245  pas
A26  NC246  pas
A27  IOA27
A28  IOA28
A29  IOA29
A30  IOA30
A31  IOA31
A32  IOA32
A33  IOA33
AA1  GXB_RX_R5N  pas
AA2  GXB_RX_R5P  pas
AA3  GND  pwr
AA4  GND  pwr
AA5  VCC  pwr
AA6  GND  pwr
AA7  VCC  pwr
AA8  GND  pwr
AA9  VCC  pwr
AA10  IOAA10
AA11  IOAA11
AA12  IOAA12
AA13  VCC  pwr
AA14  GND  pwr
AA15  VCC  pwr
AA16  GND  pwr
AA17  VCC  pwr
AA18  GND  pwr
AA19  VCC  pwr
AA20  GND  pwr
AA21  VCC  pwr
AA22  GND  pwr
AA23  IOAA23
AA24  GND  pwr
AA25  IOAA25
AA26  VCC  pwr
AA27  GND  pwr
AA28  VCC  pwr
AA29  GND  pwr
AA30  VCC  pwr
AA31  GND  pwr
AA32  GND  pwr
AA33  GXB_RX_L5P  pas
AA34  GXB_RX_L5N  pas
AB1  GND  pwr
AB2  GND  pwr
AB3  GXB_TX_R5N  pas
AB4  GXB_TX_R5P  pas
AB5  GND  pwr
AB6  VCC  pwr
AB7  GND  pwr
AB8  VCC  pwr
AB9  VCC  pwr
AB10  IOAB10
AB11  IOAB11
AB12  IOAB12
AB13  GND  pwr
AB14  VCC  pwr
AB15  GND  pwr
AB16  VCC  pwr
AB17  GND  pwr
AB18  VCC  pwr
AB19  GND  pwr
AB20  VCC  pwr
AB21  GND  pwr
AB22  VCC  pwr
AB23  IOAB23
AB24  IOAB24
AB25  IOAB25
AB26  VCC  pwr
AB27  VCC  pwr
AB28  GND  pwr
AB29  VCC  pwr
AB30  GND  pwr
AB31  GXB_TX_L5P  pas
AB32  GXB_TX_L5N  pas
AB33  GND  pwr
AB34  GND  pwr
AC1  GXB_RX_R4N  pas
AC2  GXB_RX_R4P  pas
AC3  GND  pwr
AC4  GND  pwr
AC5  GXB_CMURX_R3N  pas
AC6  GXB_CMURX_R3P  pas
AC7  NC92  pas
AC8  GND  pwr
AC9  GND  pwr
AC10  IOAC10
AC11  GND  pwr
AC12  IOAC12
AC13  VCC  pwr
AC14  NC93  pas
AC15  NC94  pas
AC16  NC95  pas
AC17  VCC  pwr
AC18  IOAC18
AC19  VCC  pwr
AC20  NC96  pas
AC21  NC97  pas
AC22  IOAC22
AC23  VCC  pwr
AC24  IOAC24
AC25  IOAC25
AC26  IOAC26
AC27  NCONFIG  in
AC28  NC98  pas
AC29  GXB_CMURX_L3P  pas
AC30  GXB_CMURX_L3N  pas
AC31  GND  pwr
AC32  GND  pwr
AC33  GXB_RX_L4P  pas
AC34  GXB_RX_L4N  pas
AD1  GND  pwr
AD2  GND  pwr
AD3  GXB_TX_R4N  pas
AD4  GXB_TX_R4P  pas
AD5  GND  pwr
AD6  GND  pwr
AD7  NC86  pas
AD8  NCSO  in
AD9  IOAD9
AD10  VCC  pwr
AD11  IOAD11
AD12  GND  pwr
AD13  IOAD13
AD14  NC87  pas
AD15  GND  pwr
AD16  NC88  pas
AD17  NC89  pas
AD18  GND  pwr
AD19  IOAD19
AD20  NC90  pas
AD21  GND  pwr
AD22  IOAD22
AD23  IOAD23
AD24  GND  pwr
AD25  VCC  pwr
AD26  IOAD26
AD27  GND  pwr
AD28  NC91  pas
AD29  GND  pwr
AD30  GND  pwr
AD31  GXB_TX_L4P  pas
AD32  GXB_TX_L4N  pas
AD33  GND  pwr
AD34  GND  pwr
AE1  GXB_RX_R3N  pas
AE2  GXB_RX_R3P  pas
AE3  GND  pwr
AE4  GND  pwr
AE5  GXB_CMURX_R2N  pas
AE6  GXB_CMURX_R2P  pas
AE7  NC77  pas
AE8  NCEO  in
AE9  IOAE9
AE10  IOAE10
AE11  IOAE11
AE12  IOAE12
AE13  NC78  pas
AE14  NC79  pas
AE15  NC80  pas
AE16  NC81  pas
AE17  VCC  pwr
AE18  IOAE18
AE19  IOAE19
AE20  NC82  pas
AE21  NC83  pas
AE22  NC84  pas
AE23  VCC  pwr
AE24  IOAE24
AE25  IOAE25
AE26  IOAE26
AE27  IOAE27
AE28  NC85  pas
AE29  GXB_CMURX_L2P  pas
AE30  GXB_CMURX_L2N  pas
AE31  GND  pwr
AE32  GND  pwr
AE33  GXB_RX_L3P  pas
AE34  GXB_RX_L3N  pas
AF1  GND  pwr
AF2  GND  pwr
AF3  GXB_TX_R3N  pas
AF4  GXB_TX_R3P  pas
AF5  GND  pwr
AF6  GND  pwr
AF7  NC70  pas
AF8  GND  pwr
AF9  VCC  pwr
AF11  VCC  pwr
AF12  IOAF12
AF13  NC71  pas
AF14  NC72  pas
AF16  NC73  pas
AF17  VCC  pwr
AF18  VCC  pwr
AF19  IOAF19
AF21  NC74  pas
AF22  NC75  pas
AF23  IOAF23
AF24  IOAF24
AF25  VCC  pwr
AF27  VCC  pwr
AF28  NC76  pas
AF29  GND  pwr
AF30  GND  pwr
AF31  GXB_TX_L3P  pas
AF32  GXB_TX_L3N  pas
AF33  GND  pwr
AF34  GND  pwr
AG1  GXB_RX_R2N  pas
AG2  GXB_RX_R2P  pas
AG3  GND  pwr
AG4  GND  pwr
AG5  GXB_CMURX_R1N  pas
AG6  GXB_CMURX_R1P  pas
AG7  NC63  pas
AG8  VCC  pwr
AG9  GND  pwr
AG10  IOAG10
AG11  IOAG11
AG12  GND  pwr
AG13  NC64  pas
AG14  NC65  pas
AG15  GND  pwr
AG16  IOAG16
AG17  NC66  pas
AG18  GND  pwr
AG19  NC67  pas
AG20  IOAG20
AG21  GND  pwr
AG22  NC68  pas
AG23  IOAG23
AG24  GND  pwr
AG25  IOAG25
AG26  IOAG26
AG27  GND  pwr
AG28  NC69  pas
AG29  GXB_CMURX_L1P  pas
AG30  GXB_CMURX_L1N  pas
AG31  GND  pwr
AG32  GND  pwr
AG33  GXB_RX_L2P  pas
AG34  GXB_RX_L2N  pas
AH1  GND  pwr
AH2  GND  pwr
AH3  GXB_TX_R2N  pas
AH4  GXB_TX_R2P  pas
AH5  GND  pwr
AH6  GND  pwr
AH7  NC53  pas
AH8  IOAH8
AH9  IOAH9
AH10  VCC  pwr
AH11  IOAH11
AH12  NC54  pas
AH13  NC55  pas
AH14  NC56  pas
AH15  IOAH15
AH16  IOAH16
AH17  NC57  pas
AH18  VCC  pwr
AH19  NC58  pas
AH20  VCC  pwr
AH21  NC59  pas
AH22  NC60  pas
AH23  NC61  pas
AH24  IOAH24
AH25  IOAH25
AH26  IOAH26
AH27  IOAH27
AH28  NC62  pas
AH29  GND  pwr
AH30  GND  pwr
AH31  GXB_TX_L2P  pas
AH32  GXB_TX_L2N  pas
AH33  GND  pwr
AH34  GND  pwr
AJ1  GXB_RX_R1N  pas
AJ2  GXB_RX_R1P  pas
AJ3  GND  pwr
AJ4  GND  pwr
AJ5  GXB_CMURX_R0N  pas
AJ6  GXB_CMURX_R0P  pas
AJ7  NC44  pas
AJ8  IOAJ8
AJ9  IOAJ9
AJ10  IOAJ10
AJ11  IOAJ11
AJ12  NC45  pas
AJ13  NC46  pas
AJ14  IOAJ14
AJ15  IOAJ15
AJ16  IOAJ16
AJ17  VCC  pwr
AJ18  VCC  pwr
AJ19  NC47  pas
AJ20  NC48  pas
AJ21  IOAJ21
AJ22  NC49  pas
AJ23  NC50  pas
AJ24  NC51  pas
AJ25  IOAJ25
AJ26  VCC  pwr
AJ27  IOAJ27
AJ28  NC52  pas
AJ29  GXB_CMURX_L0P  pas
AJ30  GXB_CMURX_L0N  pas
AJ31  GND  pwr
AJ32  GND  pwr
AJ33  GXB_RX_L1P  pas
AJ34  GXB_RX_L1N  pas
AK1  GND  pwr
AK2  GND  pwr
AK3  GXB_TX_R1N  pas
AK4  GXB_TX_R1P  pas
AK5  GND  pwr
AK6  GND  pwr
AK7  NC3  pas
AK8  IOAK8
AK9  GND  pwr
AK10  IOAK10
AK11  NC38  pas
AK12  GND  pwr
AK13  NC39  pas
AK14  IOAK14
AK15  GND  pwr
AK16  IOAK16
AK17  NC40  pas
AK18  GND  pwr
AK19  NC41  pas
AK20  IOAK20
AK21  GND  pwr
AK22  NC42  pas
AK23  NC43  pas
AK24  GND  pwr
AK25  IOAK25
AK26  IOAK26
AK27  GND  pwr
AK28  NC2  pas
AK29  GND  pwr
AK30  GND  pwr
AK31  GXB_TX_L1P  pas
AK32  GXB_TX_L1N  pas
AK33  GND  pwr
AK34  GND  pwr
AL1  GXB_RX_R0N  pas
AL2  GXB_RX_R0P  pas
AL3  GND  pwr
AL4  GND  pwr
AL5  NC8  pas
AL6  NC7  pas
AL7  IOAL7
AL8  IOAL8
AL9  IOAL9
AL10  NC28  pas
AL11  NC29  pas
AL12  NC30  pas
AL13  NC31  pas
AL14  IOAL14
AL15  IOAL15
AL16  IOAL16
AL17  NC32  pas
AL18  IOAL18
AL19  NC33  pas
AL20  IOAL20
AL21  IOAL21
AL22  NC34  pas
AL23  NC35  pas
AL24  NC36  pas
AL25  NC37  pas
AL26  IOAL26
AL27  IOAL27
AL28  PORSEL  in
AL29  NC6  pas
AL30  NC5  pas
AL31  GND  pwr
AL32  GND  pwr
AL33  GXB_RX_L0P  pas
AL34  GXB_RX_L0N  pas
AM1  GND  pwr
AM2  GND  pwr
AM3  GXB_TX_R0N  pas
AM4  GXB_TX_R0P  pas
AM5  DCLK  in
AM6  NIO_PULLUP  in
AM7  VCC  pwr
AM8  IOAM8
AM9  NC20  pas
AM10  NC21  pas
AM11  NC22  pas
AM12  NC23  pas
AM13  IOAM13
AM14  IOAM14
AM15  IOAM15
AM16  IOAM16
AM17  IOAM17
AM18  IOAM18
AM19  NC24  pas
AM20  IOAM20
AM21  IOAM21
AM22  IOAM22
AM23  NC25  pas
AM24  NC26  pas
AM25  NC27  pas
AM26  IOAM26
AM27  IOAM27
AM28  VCC  pwr
AM29  NCE  in
AM30  NSTATUS  in
AM31  GXB_TX_L0P  pas
AM32  GXB_TX_L0N  pas
AM33  GND  pwr
AM34  GND  pwr
AN1  RREF_R0  pas
AN2  GND  pwr
AN3  GND  pwr
AN4  GND  pwr
AN5  ASDO  in
AN6  GND  pwr
AN7  IOAN7
AN8  IOAN8
AN9  GND  pwr
AN10  NC15  pas
AN11  NC16  pas
AN12  GND  pwr
AN13  IOAN13
AN14  IOAN14
AN15  GND  pwr
AN16  VCC  pwr
AN17  IOAN17
AN18  GND  pwr
AN19  VCC  pwr
AN20  NC17  pas
AN21  GND  pwr
AN22  IOAN22
AN23  IOAN23
AN24  GND  pwr
AN25  NC18  pas
AN26  NC19  pas
AN27  GND  pwr
AN28  IOAN28
AN29  GND  pwr
AN30  CONF_DONE  in
AN31  GND  pwr
AN32  GND  pwr
AN33  GND  pwr
AN34  RREF_L0  pas
AP2  GND  pwr
AP3  IOAP3
AP4  IOAP4
AP5  IOAP5
AP6  IOAP6
AP7  IOAP7
AP8  IOAP8
AP9  NC9  pas
AP10  NC10  pas
AP11  NC11  pas
AP12  IOAP12
AP13  IOAP13
AP14  IOAP14
AP15  IOAP15
AP16  IOAP16
AP17  IOAP17
AP18  IOAP18
AP19  IOAP19
AP20  IOAP20
AP21  IOAP21
AP22  IOAP22
AP23  IOAP23
AP24  NC12  pas
AP25  NC13  pas
AP26  NC14  pas
AP27  IOAP27
AP28  IOAP28
AP29  IOAP29
AP30  IOAP30
AP31  IOAP31
AP32  IOAP32
AP33  GND  pwr
B1  IOB1
B2  GND  pwr
B3  IOB3
B4  IOB4
B5  GND  pwr
B6  IOB6
B7  IOB7
B8  GND  pwr
B9  NC237  pas
B10  NC238  pas
B11  GND  pwr
B12  IOB12
B13  IOB13
B14  GND  pwr
B15  IOB15
B16  IOB16
B17  GND  pwr
B18  IOB18
B19  VCC  pwr
B20  GND  pwr
B21  IOB21
B22  IOB22
B23  GND  pwr
B24  NC239  pas
B25  NC240  pas
B26  GND  pwr
B27  IOB27
B28  IOB28
B29  GND  pwr
B30  IOB30
B31  IOB31
B32  GND  pwr
B33  IOB33
B34  IOB34
C1  IOC1
C2  IOC2
C3  TEMPDIODEN  in
C4  VCC  pwr
C5  IOC5
C6  IOC6
C7  VCC  pwr
C8  IOC8
C9  IOC9
C10  NC229  pas
C11  NC230  pas
C12  IOC12
C13  IOC13
C14  IOC14
C15  IOC15
C16  IOC16
C17  NC231  pas
C18  IOC18
C19  NC232  pas
C20  IOC20
C21  IOC21
C22  IOC22
C23  NC233  pas
C24  NC234  pas
C25  NC235  pas
C26  NC236  pas
C27  IOC27
C28  VCC  pwr
C29  IOC29
C30  IOC30
C31  IOC31
C32  IOC32
C33  GND  pwr
C34  IOC34
D1  IOD1
D2  IOD2
D3  IOD3
D4  IOD4
D5  TEMPDIODEP  in
D6  IOD6
D7  IOD7
D8  IOD8
D9  IOD9
D10  NC219  pas
D11  NC220  pas
D12  NC221  pas
D13  NC222  pas
D14  IOD14
D15  IOD15
D16  VCC  pwr
D17  NC223  pas
D18  IOD18
D19  NC224  pas
D20  IOD20
D21  IOD21
D22  NC225  pas
D23  NC226  pas
D24  NC227  pas
D25  NC228  pas
D26  IOD26
D27  IOD27
D28  IOD28
D29  IOD29
D30  IOD30
D31  NC1  pas
D32  IOD32
D33  IOD33
D34  IOD34
E1  IOE1
E2  GND  pwr
E3  IOE3
E4  IOE4
E5  GND  pwr
E6  IOE6
E7  IOE7
E8  GND  pwr
E9  IOE9
E10  IOE10
E11  GND  pwr
E12  NC213  pas
E13  NC214  pas
E14  GND  pwr
E15  IOE15
E16  IOE16
E17  GND  pwr
E18  IOE18
E19  NC215  pas
E20  GND  pwr
E21  IOE21
E22  NC216  pas
E23  GND  pwr
E24  NC217  pas
E25  IOE25
E26  GND  pwr
E27  IOE27
E28  IOE28
E29  GND  pwr
E30  IOE30
E31  IOE31
E32  NC218  pas
E33  IOE33
E34  IOE34
F1  NC201  pas
F2  IOF2
F3  VCC  pwr
F4  IOF4
F5  IOF5
F6  IOF6
F7  IOF7
F8  IOF8
F9  VCC  pwr
F10  IOF10
F11  NC202  pas
F12  NC203  pas
F13  NC204  pas
F14  NC205  pas
F15  IOF15
F16  IOF16
F17  NC206  pas
F18  NC207  pas
F19  NC208  pas
F20  NC209  pas
F21  IOF21
F22  NC210  pas
F23  NC211  pas
F24  IOF24
F25  IOF25
F26  IOF26
F27  IOF27
F28  VCC  pwr
F29  TCK  in
F30  GND  pwr
F31  IOF31
F32  IOF32
F33  GND  pwr
F34  NC212  pas
G1  NC189  pas
G2  NC190  pas
G3  IOG3
G4  IOG4
G5  NC191  pas
G6  VCC  pwr
G7  NC4  pas
G8  IOG8
G9  IOG9
G10  IOG10
G11  IOG11
G12  NC192  pas
G13  NC193  pas
G14  NC194  pas
G15  VCC  pwr
G16  IOG16
G17  NC195  pas
G18  VCC  pwr
G19  IOG19
G20  NC196  pas
G21  VCC  pwr
G22  NC197  pas
G23  NC198  pas
G24  VCC  pwr
G25  IOG25
G26  IOG26
G27  IOG27
G28  TDI  in
G29  TDO  out
G30  IOG30
G31  IOG31
G32  IOG32
G33  NC199  pas
G34  NC200  pas
H1  NC181  pas
H2  GND  pwr
H3  IOH3
H4  IOH4
H5  GND  pwr
H6  IOH6
H7  IOH7
H8  GND  pwr
H9  IOH9
H10  IOH10
H11  GND  pwr
H12  IOH12
H13  NC182  pas
H14  GND  pwr
H15  IOH15
H16  NC183  pas
H17  GND  pwr
H18  VCC  pwr
H19  IOH19
H20  GND  pwr
H21  NC184  pas
H22  NC185  pas
H23  GND  pwr
H24  IOH24
H25  IOH25
H26  GND  pwr
H27  VCC  pwr
H28  TMS  in
H29  IOH29
H30  IOH30
H31  IOH31
H32  NC186  pas
H33  NC187  pas
H34  NC188  pas
J1  NC167  pas
J2  NC168  pas
J3  NC169  pas
J4  NC170  pas
J5  IOJ5
J6  IOJ6
J7  NC171  pas
J8  VCC  pwr
J9  MSEL0  in
J11  IOJ11
J12  IOJ12
J13  NC172  pas
J14  NC173  pas
J16  NC174  pas
J17  VCC  pwr
J18  VCC  pwr
J19  NC175  pas
J21  NC176  pas
J22  NC177  pas
J23  IOJ23
J24  IOJ24
J25  IOJ25
J27  GND  pwr
J28  IOJ28
J29  IOJ29
J30  GND  pwr
J31  NC178  pas
J32  NC179  pas
J33  GND  pwr
J34  NC180  pas
K1  NC152  pas
K2  NC153  pas
K3  NC154  pas
K4  VCC  pwr
K5  IOK5
K6  IOK6
K7  IOK7
K8  IOK8
K9  MSEL2  in
K10  VCC  pwr
K11  IOK11
K12  IOK12
K13  NC155  pas
K14  NC156  pas
K15  NC157  pas
K16  NC158  pas
K17  NC159  pas
K18  VCC  pwr
K19  NC160  pas
K20  IOK20
K21  NC161  pas
K22  NC162  pas
K23  IOK23
K24  IOK24
K25  IOK25
K26  TRST  in
K27  VCC  pwr
K28  IOK28
K29  IOK29
K30  IOK30
K31  NC163  pas
K32  NC164  pas
K33  NC165  pas
K34  NC166  pas
L1  NC140  pas
L2  GND  pwr
L3  NC141  pas
L4  NC142  pas
L5  GND  pwr
L6  NC143  pas
L7  NC144  pas
L8  GND  pwr
L9  VCC  pwr
L10  MSEL1  in
L11  GND  pwr
L12  IOL12
L13  IOL13
L14  GND  pwr
L15  NC145  pas
L16  NC146  pas
L17  GND  pwr
L18  IOL18
L19  IOL19
L20  GND  pwr
L21  NC147  pas
L22  IOL22
L23  GND  pwr
L24  IOL24
L25  VCC  pwr
L26  IOL26
L27  IOL27
L28  IOL28
L29  IOL29
L30  NC148  pas
L31  NC149  pas
L32  VCC  pwr
L33  NC150  pas
L34  NC151  pas
M1  IOM1
M2  IOM2
M3  NC127  pas
M4  NC128  pas
M5  NC129  pas
M6  NC130  pas
M7  NC131  pas
M8  IOM8
M9  IOM9
M11  IOM11
M12  VCC  pwr
M13  IOM13
M14  NC132  pas
M15  NC133  pas
M16  VCC  pwr
M17  NC134  pas
M18  VCC  pwr
M19  IOM19
M20  NC135  pas
M21  NC136  pas
M22  VCC  pwr
M23  IOM23
M24  GND  pwr
M25  IOM25
M27  GND  pwr
M28  VCC  pwr
M29  NC137  pas
M30  GND  pwr
M31  NC138  pas
M32  NC139  pas
M33  GND  pwr
M34  IOM34
N1  ION1
N2  ION2
N3  ION3
N4  ION4
N5  NC118  pas
N6  NC119  pas
N7  VCC  pwr
N8  NC120  pas
N9  NC121  pas
N10  ION10
N11  ION11
N12  ION12
N13  VCC  pwr
N14  GND  pwr
N15  VCC  pwr
N16  GND  pwr
N17  VCC  pwr
N18  GND  pwr
N19  VCC  pwr
N20  GND  pwr
N21  VCC  pwr
N22  GND  pwr
N23  VCC  pwr
N24  ION24
N25  ION25
N26  NC122  pas
N27  NC123  pas
N28  NC124  pas
N29  NC125  pas
N30  NC126  pas
N31  ION31
N32  ION32
N33  ION33
N34  ION34
P1  CLK10P  in
P2  GND  pwr
P3  IOP3
P4  IOP4
P5  GND  pwr
P6  NC108  pas
P7  NC109  pas
P8  GND  pwr
P9  NC110  pas
P10  NC111  pas
P11  GND  pwr
P12  VCC  pwr
P13  GND  pwr
P14  VCC  pwr
P15  GND  pwr
P16  VCC  pwr
P17  GND  pwr
P18  VCC  pwr
P19  GND  pwr
P20  VCC  pwr
P21  GND  pwr
P22  VCC  pwr
P23  NC112  pas
P24  NC113  pas
P25  VCC  pwr
P26  NC114  pas
P27  NC115  pas
P28  NC116  pas
P29  IOP29
P30  NC117  pas
P31  IOP31
P32  IOP32
P33  IOP33
P34  CLK1N  in
R1  CLK10N  in
R2  IOR2
R3  IOR3
R4  VCC  pwr
R5  IOR5
R6  IOR6
R7  NC101  pas
R8  NC102  pas
R9  NC103  pas
R11  NC104  pas
R12  NC105  pas
R13  VCC  pwr
R14  GND  pwr
R15  VCC  pwr
R16  GND  pwr
R17  VCC  pwr
R18  GND  pwr
R19  VCC  pwr
R20  GND  pwr
R21  VCC  pwr
R22  GND  pwr
R23  VCC  pwr
R24  GND  pwr
R25  NC106  pas
R27  GND  pwr
R28  NC107  pas
R29  IOR29
R30  GND  pwr
R31  IOR31
R32  IOR32
R33  GND  pwr
R34  CLK1P  in
T1  GND  pwr
T2  GND  pwr
T3  GND  pwr
T4  IOT4
T5  IOT5
T6  IOT6
T7  IOT7
T8  IOT8
T9  IOT9
T10  IOT10
T11  IOT11
T12  VCC  pwr
T13  GND  pwr
T14  VCC  pwr
T15  GND  pwr
T16  VCC  pwr
T17  GND  pwr
T18  VCC  pwr
T19  GND  pwr
T20  VCC  pwr
T21  GND  pwr
T22  VCC  pwr
T23  IOT23
T24  NC99  pas
T25  NC100  pas
T26  IOT26
T27  IOT27
T28  IOT28
T29  IOT29
T30  IOT30
T31  IOT31
T32  GND  pwr
T33  GND  pwr
T34  GND  pwr
U1  GXB_RX_R7N  pas
U2  GXB_RX_R7P  pas
U3  GND  pwr
U4  GND  pwr
U5  VCC  pwr
U6  GND  pwr
U7  VCC  pwr
U8  GND  pwr
U9  VCC  pwr
U10  IOU10
U11  GND  pwr
U12  IOU12
U13  VCC  pwr
U14  GND  pwr
U15  VCC  pwr
U16  GND  pwr
U17  VCC  pwr
U18  GND  pwr
U19  VCC  pwr
U20  GND  pwr
U21  VCC  pwr
U22  GND  pwr
U23  IOU23
U24  IOU24
U25  VCC  pwr
U26  VCC  pwr
U27  GND  pwr
U28  VCC  pwr
U29  GND  pwr
U30  VCC  pwr
U31  GND  pwr
U32  GND  pwr
U33  GXB_RX_L7P  pas
U34  GXB_RX_L7N  pas
V1  GND  pwr
V2  GND  pwr
V3  GXB_TX_R7N  pas
V4  GXB_TX_R7P  pas
V5  GND  pwr
V6  VCC  pwr
V7  GND  pwr
V8  VCC  pwr
V9  VCC  pwr
V10  VCC  pwr
V11  IOV11
V12  IOV12
V13  GND  pwr
V14  VCC  pwr
V15  GND  pwr
V16  VCC  pwr
V17  DNU  pas
V18  VCC  pwr
V19  GND  pwr
V20  VCC  pwr
V21  GND  pwr
V22  VCC  pwr
V23  IOV23
V24  GND  pwr
V25  IOV25
V26  VCC  pwr
V27  VCC  pwr
V28  GND  pwr
V29  VCC  pwr
V30  GND  pwr
V31  GXB_TX_L7P  pas
V32  GXB_TX_L7N  pas
V33  GND  pwr
V34  GND  pwr
W1  GXB_RX_R6N  pas
W2  GXB_RX_R6P  pas
W3  GND  pwr
W4  GND  pwr
W5  VCC  pwr
W6  GND  pwr
W7  VCC  pwr
W8  GND  pwr
W9  VCC  pwr
W10  VCC  pwr
W11  VCC  pwr
W12  VCC  pwr
W13  VCC  pwr
W14  GND  pwr
W15  VCC  pwr
W16  GND  pwr
W17  VCC  pwr
W18  GND  pwr
W19  VCC  pwr
W20  GND  pwr
W21  VCC  pwr
W22  GND  pwr
W23  IOW23
W24  VCC  pwr
W25  VCC  pwr
W26  VCC  pwr
W27  GND  pwr
W28  VCC  pwr
W29  GND  pwr
W30  VCC  pwr
W31  GND  pwr
W32  GND  pwr
W33  GXB_RX_L6P  pas
W34  GXB_RX_L6N  pas
Y1  GND  pwr
Y2  GND  pwr
Y3  GXB_TX_R6N  pas
Y4  GXB_TX_R6P  pas
Y5  GND  pwr
Y6  VCC  pwr
Y7  GND  pwr
Y8  VCC  pwr
Y9  VCC  pwr
Y10  VCC  pwr
Y11  GND  pwr
Y12  IOY12
Y13  GND  pwr
Y14  VCC  pwr
Y15  GND  pwr
Y16  VCC  pwr
Y17  GND  pwr
Y18  VCC  pwr
Y19  GND  pwr
Y20  VCC  pwr
Y21  GND  pwr
Y22  VCC  pwr
Y23  VCC  pwr
Y24  VCC  pwr
Y25  VCC  pwr
Y26  VCC  pwr
Y27  VCC  pwr
Y28  GND  pwr
Y29  VCC  pwr
Y30  GND  pwr
Y31  GXB_TX_L6P  pas
Y32  GXB_TX_L6N  pas
Y33  GND  pwr
Y34  GND  pwr

## Footprint FBGA1152 (pad centres in mm)
1152-Pin FineLine Ball-Grid Array (FBGA), Option 1 - Flip Chip Auto generated by make-symbol-device-package-bsdl.ulp Rev. 29 Source: EP4SE360F35.bsd http://www.altera.com .. dspkg.pdf
smd 0.7 x 0.7: A2 -15.5,16.5; A3 -14.5,16.5; A4 -13.5,16.5; A5 -12.5,16.5; A6 -11.5,16.5; A7 -10.5,16.5; A8 -9.5,16.5; A9 -8.5,16.5; A10 -7.5,16.5; A11 -6.5,16.5; A12 -5.5,16.5; A13 -4.5,16.5; A14 -3.5,16.5; A15 -2.5,16.5; A16 -1.5,16.5; A17 -0.5,16.5; A18 0.5,16.5; A19 1.5,16.5; A20 2.5,16.5; A21 3.5,16.5; A22 4.5,16.5; A23 5.5,16.5; A24 6.5,16.5; A25 7.5,16.5; A26 8.5,16.5; A27 9.5,16.5; A28 10.5,16.5; A29 11.5,16.5; A30 12.5,16.5; A31 13.5,16.5; A32 14.5,16.5; A33 15.5,16.5; AA1 -16.5,-3.5; AA2 -15.5,-3.5; AA3 -14.5,-3.5; AA4 -13.5,-3.5; AA5 -12.5,-3.5; AA6 -11.5,-3.5; AA7 -10.5,-3.5; AA8 -9.5,-3.5; AA9 -8.5,-3.5; AA10 -7.5,-3.5; AA11 -6.5,-3.5; AA12 -5.5,-3.5; AA13 -4.5,-3.5; AA14 -3.5,-3.5; AA15 -2.5,-3.5; AA16 -1.5,-3.5; AA17 -0.5,-3.5; AA18 0.5,-3.5; AA19 1.5,-3.5; AA20 2.5,-3.5; AA21 3.5,-3.5; AA22 4.5,-3.5; AA23 5.5,-3.5; AA24 6.5,-3.5; AA25 7.5,-3.5; AA26 8.5,-3.5; AA27 9.5,-3.5; AA28 10.5,-3.5; AA29 11.5,-3.5; AA30 12.5,-3.5; AA31 13.5,-3.5; AA32 14.5,-3.5; AA33 15.5,-3.5; AA34 16.5,-3.5; AB1 -16.5,-4.5; AB2 -15.5,-4.5; AB3 -14.5,-4.5; AB4 -13.5,-4.5; AB5 -12.5,-4.5; AB6 -11.5,-4.5; AB7 -10.5,-4.5; AB8 -9.5,-4.5; AB9 -8.5,-4.5; AB10 -7.5,-4.5; AB11 -6.5,-4.5; AB12 -5.5,-4.5; AB13 -4.5,-4.5; AB14 -3.5,-4.5; AB15 -2.5,-4.5; AB16 -1.5,-4.5; AB17 -0.5,-4.5; AB18 0.5,-4.5; AB19 1.5,-4.5; AB20 2.5,-4.5; AB21 3.5,-4.5; AB22 4.5,-4.5; AB23 5.5,-4.5; AB24 6.5,-4.5; AB25 7.5,-4.5; AB26 8.5,-4.5; AB27 9.5,-4.5; AB28 10.5,-4.5; AB29 11.5,-4.5; AB30 12.5,-4.5; AB31 13.5,-4.5; AB32 14.5,-4.5; AB33 15.5,-4.5; AB34 16.5,-4.5; AC1 -16.5,-5.5; AC2 -15.5,-5.5; AC3 -14.5,-5.5; AC4 -13.5,-5.5; AC5 -12.5,-5.5; AC6 -11.5,-5.5; AC7 -10.5,-5.5; AC8 -9.5,-5.5; AC9 -8.5,-5.5; AC10 -7.5,-5.5; AC11 -6.5,-5.5; AC12 -5.5,-5.5; AC13 -4.5,-5.5; AC14 -3.5,-5.5; AC15 -2.5,-5.5; AC16 -1.5,-5.5; AC17 -0.5,-5.5; AC18 0.5,-5.5; AC19 1.5,-5.5; AC20 2.5,-5.5; AC21 3.5,-5.5; AC22 4.5,-5.5; AC23 5.5,-5.5; AC24 6.5,-5.5; AC25 7.5,-5.5; AC26 8.5,-5.5; AC27 9.5,-5.5; AC28 10.5,-5.5; AC29 11.5,-5.5; AC30 12.5,-5.5; AC31 13.5,-5.5; AC32 14.5,-5.5; AC33 15.5,-5.5; AC34 16.5,-5.5; AD1 -16.5,-6.5; AD2 -15.5,-6.5; AD3 -14.5,-6.5; AD4 -13.5,-6.5; AD5 -12.5,-6.5; AD6 -11.5,-6.5; AD7 -10.5,-6.5; AD8 -9.5,-6.5; AD9 -8.5,-6.5; AD10 -7.5,-6.5; AD11 -6.5,-6.5; AD12 -5.5,-6.5; AD13 -4.5,-6.5; AD14 -3.5,-6.5; AD15 -2.5,-6.5; AD16 -1.5,-6.5; AD17 -0.5,-6.5; AD18 0.5,-6.5; AD19 1.5,-6.5; AD20 2.5,-6.5; AD21 3.5,-6.5; AD22 4.5,-6.5; AD23 5.5,-6.5; AD24 6.5,-6.5; AD25 7.5,-6.5; AD26 8.5,-6.5; AD27 9.5,-6.5; AD28 10.5,-6.5; AD29 11.5,-6.5; AD30 12.5,-6.5; AD31 13.5,-6.5; AD32 14.5,-6.5; AD33 15.5,-6.5; AD34 16.5,-6.5; AE1 -16.5,-7.5; AE2 -15.5,-7.5; AE3 -14.5,-7.5; AE4 -13.5,-7.5; AE5 -12.5,-7.5; AE6 -11.5,-7.5; AE7 -10.5,-7.5; AE8 -9.5,-7.5; AE9 -8.5,-7.5; AE10 -7.5,-7.5; AE11 -6.5,-7.5; AE12 -5.5,-7.5; AE13 -4.5,-7.5; AE14 -3.5,-7.5; AE15 -2.5,-7.5; AE16 -1.5,-7.5; AE17 -0.5,-7.5; AE18 0.5,-7.5; AE19 1.5,-7.5; AE20 2.5,-7.5; AE21 3.5,-7.5; AE22 4.5,-7.5; AE23 5.5,-7.5; AE24 6.5,-7.5; AE25 7.5,-7.5; AE26 8.5,-7.5; AE27 9.5,-7.5; AE28 10.5,-7.5; AE29 11.5,-7.5; AE30 12.5,-7.5; AE31 13.5,-7.5; AE32 14.5,-7.5; AE33 15.5,-7.5; AE34 16.5,-7.5; AF1 -16.5,-8.5; AF2 -15.5,-8.5; AF3 -14.5,-8.5; AF4 -13.5,-8.5; AF5 -12.5,-8.5; AF6 -11.5,-8.5; AF7 -10.5,-8.5; AF8 -9.5,-8.5; AF9 -8.5,-8.5; AF10 -7.5,-8.5; AF11 -6.5,-8.5; AF12 -5.5,-8.5; AF13 -4.5,-8.5; AF14 -3.5,-8.5; AF15 -2.5,-8.5; AF16 -1.5,-8.5; AF17 -0.5,-8.5; AF18 0.5,-8.5; AF19 1.5,-8.5; AF20 2.5,-8.5; AF21 3.5,-8.5; AF22 4.5,-8.5; AF23 5.5,-8.5; AF24 6.5,-8.5; AF25 7.5,-8.5; AF26 8.5,-8.5; AF27 9.5,-8.5; AF28 10.5,-8.5; AF29 11.5,-8.5; AF30 12.5,-8.5; AF31 13.5,-8.5; AF32 14.5,-8.5; AF33 15.5,-8.5; AF34 16.5,-8.5; AG1 -16.5,-9.5; AG2 -15.5,-9.5; AG3 -14.5,-9.5; AG4 -13.5,-9.5; AG5 -12.5,-9.5; AG6 -11.5,-9.5; AG7 -10.5,-9.5; AG8 -9.5,-9.5; AG9 -8.5,-9.5; AG10 -7.5,-9.5; AG11 -6.5,-9.5; AG12 -5.5,-9.5; AG13 -4.5,-9.5; AG14 -3.5,-9.5; AG15 -2.5,-9.5; AG16 -1.5,-9.5; AG17 -0.5,-9.5; AG18 0.5,-9.5; AG19 1.5,-9.5; AG20 2.5,-9.5; AG21 3.5,-9.5; AG22 4.5,-9.5; AG23 5.5,-9.5; AG24 6.5,-9.5; AG25 7.5,-9.5; AG26 8.5,-9.5; AG27 9.5,-9.5; AG28 10.5,-9.5; AG29 11.5,-9.5; AG30 12.5,-9.5; AG31 13.5,-9.5; AG32 14.5,-9.5; AG33 15.5,-9.5; AG34 16.5,-9.5; AH1 -16.5,-10.5; AH2 -15.5,-10.5; AH3 -14.5,-10.5; AH4 -13.5,-10.5; AH5 -12.5,-10.5; AH6 -11.5,-10.5; AH7 -10.5,-10.5; AH8 -9.5,-10.5; AH9 -8.5,-10.5; AH10 -7.5,-10.5; AH11 -6.5,-10.5; AH12 -5.5,-10.5; AH13 -4.5,-10.5; AH14 -3.5,-10.5; AH15 -2.5,-10.5; AH16 -1.5,-10.5; AH17 -0.5,-10.5; AH18 0.5,-10.5; AH19 1.5,-10.5; AH20 2.5,-10.5; AH21 3.5,-10.5; AH22 4.5,-10.5; AH23 5.5,-10.5; AH24 6.5,-10.5; AH25 7.5,-10.5; AH26 8.5,-10.5; AH27 9.5,-10.5; AH28 10.5,-10.5; AH29 11.5,-10.5; AH30 12.5,-10.5; AH31 13.5,-10.5; AH32 14.5,-10.5; AH33 15.5,-10.5; AH34 16.5,-10.5; AJ1 -16.5,-11.5; AJ2 -15.5,-11.5; AJ3 -14.5,-11.5; AJ4 -13.5,-11.5; AJ5 -12.5,-11.5; AJ6 -11.5,-11.5; AJ7 -10.5,-11.5; AJ8 -9.5,-11.5; AJ9 -8.5,-11.5; AJ10 -7.5,-11.5; AJ11 -6.5,-11.5; AJ12 -5.5,-11.5; AJ13 -4.5,-11.5; AJ14 -3.5,-11.5; AJ15 -2.5,-11.5; AJ16 -1.5,-11.5; AJ17 -0.5,-11.5; AJ18 0.5,-11.5; AJ19 1.5,-11.5; AJ20 2.5,-11.5; AJ21 3.5,-11.5; AJ22 4.5,-11.5; AJ23 5.5,-11.5; AJ24 6.5,-11.5; AJ25 7.5,-11.5; AJ26 8.5,-11.5; AJ27 9.5,-11.5; AJ28 10.5,-11.5; AJ29 11.5,-11.5; AJ30 12.5,-11.5; AJ31 13.5,-11.5; AJ32 14.5,-11.5; AJ33 15.5,-11.5; AJ34 16.5,-11.5; AK1 -16.5,-12.5; AK2 -15.5,-12.5; AK3 -14.5,-12.5; AK4 -13.5,-12.5; AK5 -12.5,-12.5; AK6 -11.5,-12.5; AK7 -10.5,-12.5; AK8 -9.5,-12.5; AK9 -8.5,-12.5; AK10 -7.5,-12.5; AK11 -6.5,-12.5; AK12 -5.5,-12.5; AK13 -4.5,-12.5; AK14 -3.5,-12.5; AK15 -2.5,-12.5; AK16 -1.5,-12.5; AK17 -0.5,-12.5; AK18 0.5,-12.5; AK19 1.5,-12.5; AK20 2.5,-12.5; AK21 3.5,-12.5; AK22 4.5,-12.5; AK23 5.5,-12.5; AK24 6.5,-12.5; AK25 7.5,-12.5; AK26 8.5,-12.5; AK27 9.5,-12.5; AK28 10.5,-12.5; AK29 11.5,-12.5; AK30 12.5,-12.5; AK31 13.5,-12.5; AK32 14.5,-12.5; AK33 15.5,-12.5; AK34 16.5,-12.5; AL1 -16.5,-13.5; AL2 -15.5,-13.5; AL3 -14.5,-13.5; AL4 -13.5,-13.5; AL5 -12.5,-13.5; AL6 -11.5,-13.5; AL7 -10.5,-13.5; AL8 -9.5,-13.5; AL9 -8.5,-13.5; AL10 -7.5,-13.5; AL11 -6.5,-13.5; AL12 -5.5,-13.5; AL13 -4.5,-13.5; AL14 -3.5,-13.5; AL15 -2.5,-13.5; AL16 -1.5,-13.5; AL17 -0.5,-13.5; AL18 0.5,-13.5; AL19 1.5,-13.5; AL20 2.5,-13.5; AL21 3.5,-13.5; AL22 4.5,-13.5; AL23 5.5,-13.5; AL24 6.5,-13.5; AL25 7.5,-13.5; AL26 8.5,-13.5; AL27 9.5,-13.5; AL28 10.5,-13.5; AL29 11.5,-13.5; AL30 12.5,-13.5; AL31 13.5,-13.5; AL32 14.5,-13.5; AL33 15.5,-13.5; AL34 16.5,-13.5; AM1 -16.5,-14.5; AM2 -15.5,-14.5; AM3 -14.5,-14.5; AM4 -13.5,-14.5; AM5 -12.5,-14.5; AM6 -11.5,-14.5; AM7 -10.5,-14.5; AM8 -9.5,-14.5; AM9 -8.5,-14.5; AM10 -7.5,-14.5; AM11 -6.5,-14.5; AM12 -5.5,-14.5; AM13 -4.5,-14.5; AM14 -3.5,-14.5; AM15 -2.5,-14.5; AM16 -1.5,-14.5; AM17 -0.5,-14.5; AM18 0.5,-14.5; AM19 1.5,-14.5; AM20 2.5,-14.5; AM21 3.5,-14.5; AM22 4.5,-14.5; AM23 5.5,-14.5; AM24 6.5,-14.5; AM25 7.5,-14.5; AM26 8.5,-14.5; AM27 9.5,-14.5; AM28 10.5,-14.5; AM29 11.5,-14.5; AM30 12.5,-14.5; AM31 13.5,-14.5; AM32 14.5,-14.5; AM33 15.5,-14.5; AM34 16.5,-14.5; AN1 -16.5,-15.5; AN2 -15.5,-15.5; AN3 -14.5,-15.5; AN4 -13.5,-15.5; AN5 -12.5,-15.5; AN6 -11.5,-15.5; AN7 -10.5,-15.5; AN8 -9.5,-15.5; AN9 -8.5,-15.5; AN10 -7.5,-15.5; AN11 -6.5,-15.5; AN12 -5.5,-15.5; AN13 -4.5,-15.5; AN14 -3.5,-15.5; AN15 -2.5,-15.5; AN16 -1.5,-15.5; AN17 -0.5,-15.5; AN18 0.5,-15.5; AN19 1.5,-15.5; AN20 2.5,-15.5; AN21 3.5,-15.5; AN22 4.5,-15.5; AN23 5.5,-15.5; AN24 6.5,-15.5; AN25 7.5,-15.5; AN26 8.5,-15.5; AN27 9.5,-15.5; AN28 10.5,-15.5; AN29 11.5,-15.5; AN30 12.5,-15.5; AN31 13.5,-15.5; AN32 14.5,-15.5; AN33 15.5,-15.5; AN34 16.5,-15.5; AP2 -15.5,-16.5; AP3 -14.5,-16.5; AP4 -13.5,-16.5; AP5 -12.5,-16.5; AP6 -11.5,-16.5; AP7 -10.5,-16.5; AP8 -9.5,-16.5; AP9 -8.5,-16.5; AP10 -7.5,-16.5; AP11 -6.5,-16.5; AP12 -5.5,-16.5; AP13 -4.5,-16.5; AP14 -3.5,-16.5; AP15 -2.5,-16.5; AP16 -1.5,-16.5; AP17 -0.5,-16.5; AP18 0.5,-16.5; AP19 1.5,-16.5; AP20 2.5,-16.5; AP21 3.5,-16.5; AP22 4.5,-16.5; AP23 5.5,-16.5; AP24 6.5,-16.5; AP25 7.5,-16.5; AP26 8.5,-16.5; AP27 9.5,-16.5; AP28 10.5,-16.5; AP29 11.5,-16.5; AP30 12.5,-16.5; AP31 13.5,-16.5; AP32 14.5,-16.5; AP33 15.5,-16.5; B1 -16.5,15.5; B2 -15.5,15.5; B3 -14.5,15.5; B4 -13.5,15.5; B5 -12.5,15.5; B6 -11.5,15.5; B7 -10.5,15.5; B8 -9.5,15.5; B9 -8.5,15.5; B10 -7.5,15.5; B11 -6.5,15.5; B12 -5.5,15.5; B13 -4.5,15.5; B14 -3.5,15.5; B15 -2.5,15.5; B16 -1.5,15.5; B17 -0.5,15.5; B18 0.5,15.5; B19 1.5,15.5; B20 2.5,15.5; B21 3.5,15.5; B22 4.5,15.5; B23 5.5,15.5; B24 6.5,15.5; B25 7.5,15.5; B26 8.5,15.5; B27 9.5,15.5; B28 10.5,15.5; B29 11.5,15.5; B30 12.5,15.5; B31 13.5,15.5; B32 14.5,15.5; B33 15.5,15.5; B34 16.5,15.5; C1 -16.5,14.5; C2 -15.5,14.5; C3 -14.5,14.5; C4 -13.5,14.5; C5 -12.5,14.5; C6 -11.5,14.5; C7 -10.5,14.5; C8 -9.5,14.5; C9 -8.5,14.5; C10 -7.5,14.5; C11 -6.5,14.5; C12 -5.5,14.5; C13 -4.5,14.5; C14 -3.5,14.5; C15 -2.5,14.5; C16 -1.5,14.5; C17 -0.5,14.5; C18 0.5,14.5; C19 1.5,14.5; C20 2.5,14.5; C21 3.5,14.5; C22 4.5,14.5; C23 5.5,14.5; C24 6.5,14.5; C25 7.5,14.5; C26 8.5,14.5; C27 9.5,14.5; C28 10.5,14.5; C29 11.5,14.5; C30 12.5,14.5; C31 13.5,14.5; C32 14.5,14.5; C33 15.5,14.5; C34 16.5,14.5; D1 -16.5,13.5; D2 -15.5,13.5; D3 -14.5,13.5; D4 -13.5,13.5; D5 -12.5,13.5; D6 -11.5,13.5; D7 -10.5,13.5; D8 -9.5,13.5; D9 -8.5,13.5; D10 -7.5,13.5; D11 -6.5,13.5; D12 -5.5,13.5; D13 -4.5,13.5; D14 -3.5,13.5; D15 -2.5,13.5; D16 -1.5,13.5; D17 -0.5,13.5; D18 0.5,13.5; D19 1.5,13.5; D20 2.5,13.5; D21 3.5,13.5; D22 4.5,13.5; D23 5.5,13.5; D24 6.5,13.5; D25 7.5,13.5; D26 8.5,13.5; D27 9.5,13.5; D28 10.5,13.5; D29 11.5,13.5; D30 12.5,13.5; D31 13.5,13.5; D32 14.5,13.5; D33 15.5,13.5; D34 16.5,13.5; E1 -16.5,12.5; E2 -15.5,12.5; E3 -14.5,12.5; E4 -13.5,12.5; E5 -12.5,12.5; E6 -11.5,12.5; E7 -10.5,12.5; E8 -9.5,12.5; E9 -8.5,12.5; E10 -7.5,12.5; E11 -6.5,12.5; E12 -5.5,12.5; E13 -4.5,12.5; E14 -3.5,12.5; E15 -2.5,12.5; E16 -1.5,12.5; E17 -0.5,12.5; E18 0.5,12.5; E19 1.5,12.5; E20 2.5,12.5; E21 3.5,12.5; E22 4.5,12.5; E23 5.5,12.5; E24 6.5,12.5; E25 7.5,12.5; E26 8.5,12.5; E27 9.5,12.5; E28 10.5,12.5; E29 11.5,12.5; E30 12.5,12.5; E31 13.5,12.5; E32 14.5,12.5; E33 15.5,12.5; E34 16.5,12.5; F1 -16.5,11.5; F2 -15.5,11.5; F3 -14.5,11.5; F4 -13.5,11.5; F5 -12.5,11.5; F6 -11.5,11.5; F7 -10.5,11.5; F8 -9.5,11.5; F9 -8.5,11.5; F10 -7.5,11.5; F11 -6.5,11.5; F12 -5.5,11.5; F13 -4.5,11.5; F14 -3.5,11.5; F15 -2.5,11.5; F16 -1.5,11.5; F17 -0.5,11.5; F18 0.5,11.5; F19 1.5,11.5; F20 2.5,11.5; F21 3.5,11.5; F22 4.5,11.5; F23 5.5,11.5; F24 6.5,11.5; F25 7.5,11.5; F26 8.5,11.5; F27 9.5,11.5; F28 10.5,11.5; F29 11.5,11.5; F30 12.5,11.5; F31 13.5,11.5; F32 14.5,11.5; F33 15.5,11.5; F34 16.5,11.5; G1 -16.5,10.5; G2 -15.5,10.5; G3 -14.5,10.5; G4 -13.5,10.5; G5 -12.5,10.5; G6 -11.5,10.5; G7 -10.5,10.5; G8 -9.5,10.5; G9 -8.5,10.5; G10 -7.5,10.5; G11 -6.5,10.5; G12 -5.5,10.5; G13 -4.5,10.5; G14 -3.5,10.5; G15 -2.5,10.5; G16 -1.5,10.5; G17 -0.5,10.5; G18 0.5,10.5; G19 1.5,10.5; G20 2.5,10.5; G21 3.5,10.5; G22 4.5,10.5; G23 5.5,10.5; G24 6.5,10.5; G25 7.5,10.5; G26 8.5,10.5; G27 9.5,10.5; G28 10.5,10.5; G29 11.5,10.5; G30 12.5,10.5; G31 13.5,10.5; G32 14.5,10.5; G33 15.5,10.5; G34 16.5,10.5; H1 -16.5,9.5; H2 -15.5,9.5; H3 -14.5,9.5; H4 -13.5,9.5; H5 -12.5,9.5; H6 -11.5,9.5; H7 -10.5,9.5; H8 -9.5,9.5; H9 -8.5,9.5; H10 -7.5,9.5; H11 -6.5,9.5; H12 -5.5,9.5; H13 -4.5,9.5; H14 -3.5,9.5; H15 -2.5,9.5; H16 -1.5,9.5; H17 -0.5,9.5; H18 0.5,9.5; H19 1.5,9.5; H20 2.5,9.5; H21 3.5,9.5; H22 4.5,9.5; H23 5.5,9.5; H24 6.5,9.5; H25 7.5,9.5; H26 8.5,9.5; H27 9.5,9.5; H28 10.5,9.5; H29 11.5,9.5; H30 12.5,9.5; H31 13.5,9.5; H32 14.5,9.5; H33 15.5,9.5; H34 16.5,9.5; J1 -16.5,8.5; J2 -15.5,8.5; J3 -14.5,8.5; J4 -13.5,8.5; J5 -12.5,8.5; J6 -11.5,8.5; J7 -10.5,8.5; J8 -9.5,8.5; J9 -8.5,8.5; J10 -7.5,8.5; J11 -6.5,8.5; J12 -5.5,8.5; J13 -4.5,8.5; J14 -3.5,8.5; J15 -2.5,8.5; J16 -1.5,8.5; J17 -0.5,8.5; J18 0.5,8.5; J19 1.5,8.5; J20 2.5,8.5; J21 3.5,8.5; J22 4.5,8.5; J23 5.5,8.5; J24 6.5,8.5; J25 7.5,8.5; J26 8.5,8.5; J27 9.5,8.5; J28 10.5,8.5; J29 11.5,8.5; J30 12.5,8.5; J31 13.5,8.5; J32 14.5,8.5; J33 15.5,8.5; J34 16.5,8.5; K1 -16.5,7.5; K2 -15.5,7.5; K3 -14.5,7.5; K4 -13.5,7.5; K5 -12.5,7.5; K6 -11.5,7.5; K7 -10.5,7.5; K8 -9.5,7.5; K9 -8.5,7.5; K10 -7.5,7.5; K11 -6.5,7.5; K12 -5.5,7.5; K13 -4.5,7.5; K14 -3.5,7.5; K15 -2.5,7.5; K16 -1.5,7.5; K17 -0.5,7.5; K18 0.5,7.5; K19 1.5,7.5; K20 2.5,7.5; K21 3.5,7.5; K22 4.5,7.5; K23 5.5,7.5; K24 6.5,7.5; K25 7.5,7.5; K26 8.5,7.5; K27 9.5,7.5; K28 10.5,7.5; K29 11.5,7.5; K30 12.5,7.5; K31 13.5,7.5; K32 14.5,7.5; K33 15.5,7.5; K34 16.5,7.5; L1 -16.5,6.5; L2 -15.5,6.5; L3 -14.5,6.5; L4 -13.5,6.5; L5 -12.5,6.5; L6 -11.5,6.5; L7 -10.5,6.5; L8 -9.5,6.5; L9 -8.5,6.5; L10 -7.5,6.5; L11 -6.5,6.5; L12 -5.5,6.5; L13 -4.5,6.5; L14 -3.5,6.5; L15 -2.5,6.5; L16 -1.5,6.5; L17 -0.5,6.5; L18 0.5,6.5; L19 1.5,6.5; L20 2.5,6.5; L21 3.5,6.5; L22 4.5,6.5; L23 5.5,6.5; L24 6.5,6.5; L25 7.5,6.5; L26 8.5,6.5; L27 9.5,6.5; L28 10.5,6.5; L29 11.5,6.5; L30 12.5,6.5; L31 13.5,6.5; L32 14.5,6.5; L33 15.5,6.5; L34 16.5,6.5; M1 -16.5,5.5; M2 -15.5,5.5; M3 -14.5,5.5; M4 -13.5,5.5; M5 -12.5,5.5; M6 -11.5,5.5; M7 -10.5,5.5; M8 -9.5,5.5; M9 -8.5,5.5; M10 -7.5,5.5; M11 -6.5,5.5; M12 -5.5,5.5; M13 -4.5,5.5; M14 -3.5,5.5; M15 -2.5,5.5; M16 -1.5,5.5; M17 -0.5,5.5; M18 0.5,5.5; M19 1.5,5.5; M20 2.5,5.5; M21 3.5,5.5; M22 4.5,5.5; M23 5.5,5.5; M24 6.5,5.5; M25 7.5,5.5; M26 8.5,5.5; M27 9.5,5.5; M28 10.5,5.5; M29 11.5,5.5; M30 12.5,5.5; M31 13.5,5.5; M32 14.5,5.5; M33 15.5,5.5; M34 16.5,5.5; N1 -16.5,4.5; N2 -15.5,4.5; N3 -14.5,4.5; N4 -13.5,4.5; N5 -12.5,4.5; N6 -11.5,4.5; N7 -10.5,4.5; N8 -9.5,4.5; N9 -8.5,4.5; N10 -7.5,4.5; N11 -6.5,4.5; N12 -5.5,4.5; N13 -4.5,4.5; N14 -3.5,4.5; N15 -2.5,4.5; N16 -1.5,4.5; N17 -0.5,4.5; N18 0.5,4.5; N19 1.5,4.5; N20 2.5,4.5; N21 3.5,4.5; N22 4.5,4.5; N23 5.5,4.5; N24 6.5,4.5; N25 7.5,4.5; N26 8.5,4.5; N27 9.5,4.5; N28 10.5,4.5; N29 11.5,4.5; N30 12.5,4.5; N31 13.5,4.5; N32 14.5,4.5; N33 15.5,4.5; N34 16.5,4.5; P1 -16.5,3.5; P2 -15.5,3.5; P3 -14.5,3.5; P4 -13.5,3.5; P5 -12.5,3.5; P6 -11.5,3.5; P7 -10.5,3.5; P8 -9.5,3.5; P9 -8.5,3.5; P10 -7.5,3.5; P11 -6.5,3.5; P12 -5.5,3.5; P13 -4.5,3.5; P14 -3.5,3.5; P15 -2.5,3.5; P16 -1.5,3.5; P17 -0.5,3.5; P18 0.5,3.5; P19 1.5,3.5; P20 2.5,3.5; P21 3.5,3.5; P22 4.5,3.5; P23 5.5,3.5; P24 6.5,3.5; P25 7.5,3.5; P26 8.5,3.5; P27 9.5,3.5; P28 10.5,3.5; P29 11.5,3.5; P30 12.5,3.5; P31 13.5,3.5; P32 14.5,3.5; P33 15.5,3.5; P34 16.5,3.5; R1 -16.5,2.5; R2 -15.5,2.5; R3 -14.5,2.5; R4 -13.5,2.5; R5 -12.5,2.5; R6 -11.5,2.5; R7 -10.5,2.5; R8 -9.5,2.5; R9 -8.5,2.5; R10 -7.5,2.5; R11 -6.5,2.5; R12 -5.5,2.5; R13 -4.5,2.5; R14 -3.5,2.5; R15 -2.5,2.5; R16 -1.5,2.5; R17 -0.5,2.5; R18 0.5,2.5; R19 1.5,2.5; R20 2.5,2.5; R21 3.5,2.5; R22 4.5,2.5; R23 5.5,2.5; R24 6.5,2.5; R25 7.5,2.5; R26 8.5,2.5; R27 9.5,2.5; R28 10.5,2.5; R29 11.5,2.5; R30 12.5,2.5; R31 13.5,2.5; R32 14.5,2.5; R33 15.5,2.5; R34 16.5,2.5; T1 -16.5,1.5; T2 -15.5,1.5; T3 -14.5,1.5; T4 -13.5,1.5; T5 -12.5,1.5; T6 -11.5,1.5; T7 -10.5,1.5; T8 -9.5,1.5; T9 -8.5,1.5; T10 -7.5,1.5; T11 -6.5,1.5; T12 -5.5,1.5; T13 -4.5,1.5; T14 -3.5,1.5; T15 -2.5,1.5; T16 -1.5,1.5; T17 -0.5,1.5; T18 0.5,1.5; T19 1.5,1.5; T20 2.5,1.5; T21 3.5,1.5; T22 4.5,1.5; T23 5.5,1.5; T24 6.5,1.5; T25 7.5,1.5; T26 8.5,1.5; T27 9.5,1.5; T28 10.5,1.5; T29 11.5,1.5; T30 12.5,1.5; T31 13.5,1.5; T32 14.5,1.5; T33 15.5,1.5; T34 16.5,1.5; U1 -16.5,0.5; U2 -15.5,0.5; U3 -14.5,0.5; U4 -13.5,0.5; U5 -12.5,0.5; U6 -11.5,0.5; U7 -10.5,0.5; U8 -9.5,0.5; U9 -8.5,0.5; U10 -7.5,0.5; U11 -6.5,0.5; U12 -5.5,0.5; U13 -4.5,0.5; U14 -3.5,0.5; U15 -2.5,0.5; U16 -1.5,0.5; U17 -0.5,0.5; U18 0.5,0.5; U19 1.5,0.5; U20 2.5,0.5; U21 3.5,0.5; U22 4.5,0.5; U23 5.5,0.5; U24 6.5,0.5; U25 7.5,0.5; U26 8.5,0.5; U27 9.5,0.5; U28 10.5,0.5; U29 11.5,0.5; U30 12.5,0.5; U31 13.5,0.5; U32 14.5,0.5; U33 15.5,0.5; U34 16.5,0.5; V1 -16.5,-0.5; V2 -15.5,-0.5; V3 -14.5,-0.5; V4 -13.5,-0.5; V5 -12.5,-0.5; V6 -11.5,-0.5; V7 -10.5,-0.5; V8 -9.5,-0.5; V9 -8.5,-0.5; V10 -7.5,-0.5; V11 -6.5,-0.5; V12 -5.5,-0.5; V13 -4.5,-0.5; V14 -3.5,-0.5; V15 -2.5,-0.5; V16 -1.5,-0.5; V17 -0.5,-0.5; V18 0.5,-0.5; V19 1.5,-0.5; V20 2.5,-0.5; V21 3.5,-0.5; V22 4.5,-0.5; V23 5.5,-0.5; V24 6.5,-0.5; V25 7.5,-0.5; V26 8.5,-0.5; V27 9.5,-0.5; V28 10.5,-0.5; V29 11.5,-0.5; V30 12.5,-0.5; V31 13.5,-0.5; V32 14.5,-0.5; V33 15.5,-0.5; V34 16.5,-0.5; W1 -16.5,-1.5; W2 -15.5,-1.5; W3 -14.5,-1.5; W4 -13.5,-1.5; W5 -12.5,-1.5; W6 -11.5,-1.5; W7 -10.5,-1.5; W8 -9.5,-1.5; W9 -8.5,-1.5; W10 -7.5,-1.5; W11 -6.5,-1.5; W12 -5.5,-1.5; W13 -4.5,-1.5; W14 -3.5,-1.5; W15 -2.5,-1.5; W16 -1.5,-1.5; W17 -0.5,-1.5; W18 0.5,-1.5; W19 1.5,-1.5; W20 2.5,-1.5; W21 3.5,-1.5; W22 4.5,-1.5; W23 5.5,-1.5; W24 6.5,-1.5; W25 7.5,-1.5; W26 8.5,-1.5; W27 9.5,-1.5; W28 10.5,-1.5; W29 11.5,-1.5; W30 12.5,-1.5; W31 13.5,-1.5; W32 14.5,-1.5; W33 15.5,-1.5; W34 16.5,-1.5; Y1 -16.5,-2.5; Y2 -15.5,-2.5; Y3 -14.5,-2.5; Y4 -13.5,-2.5; Y5 -12.5,-2.5; Y6 -11.5,-2.5; Y7 -10.5,-2.5; Y8 -9.5,-2.5; Y9 -8.5,-2.5; Y10 -7.5,-2.5; Y11 -6.5,-2.5; Y12 -5.5,-2.5; Y13 -4.5,-2.5; Y14 -3.5,-2.5; Y15 -2.5,-2.5; Y16 -1.5,-2.5; Y17 -0.5,-2.5; Y18 0.5,-2.5; Y19 1.5,-2.5; Y20 2.5,-2.5; Y21 3.5,-2.5; Y22 4.5,-2.5; Y23 5.5,-2.5; Y24 6.5,-2.5; Y25 7.5,-2.5; Y26 8.5,-2.5; Y27 9.5,-2.5; Y28 10.5,-2.5; Y29 11.5,-2.5; Y30 12.5,-2.5; Y31 13.5,-2.5; Y32 14.5,-2.5; Y33 15.5,-2.5; Y34 16.5,-2.5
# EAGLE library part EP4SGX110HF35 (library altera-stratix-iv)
EP4SGX110HF35 Auto generated by make-symbol-device-package-bsdl.ulp Rev. 29 Source: EP4SGX110HF35.bsd

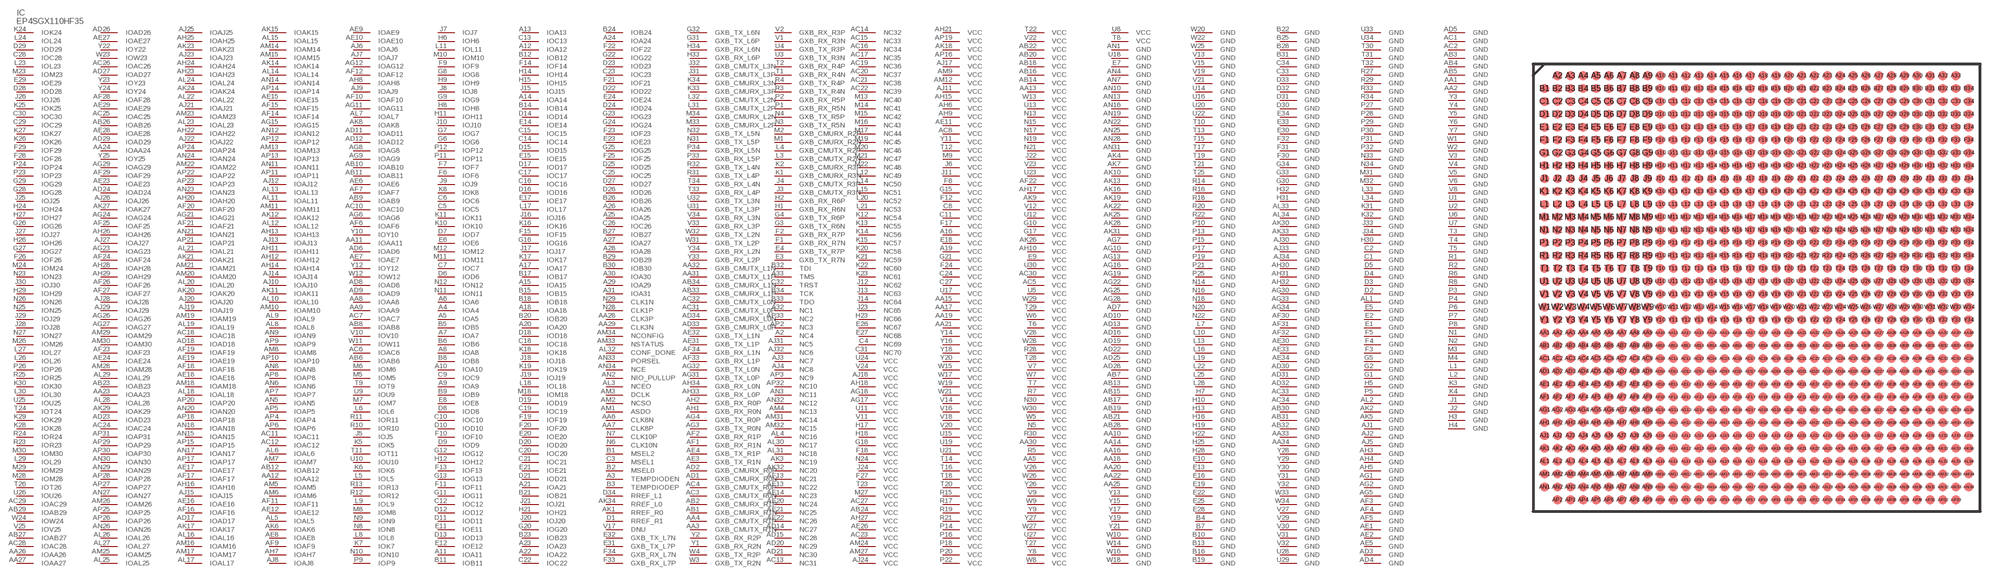
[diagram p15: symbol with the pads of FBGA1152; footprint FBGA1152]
Designator prefix IC

## EP4SGX110HF35 (MPN: EP4SGX110HF35C2N; OC_FARNELL: unknown; OC_NEWARK: 52R1770)  [FBGA1152]
A2  NC4  pas
A3  TEMPDIODEN  pas
A4  IOA4
A5  IOA5
A6  IOA6
A7  IOA7
A8  IOA8
A9  IOA9
A10  IOA10
A11  IOA11
A12  IOA12
A13  IOA13
A14  IOA14
A15  IOA15
A16  VCC  pwr
A17  IOA17
A18  IOA18
A19  VCC  pwr
A20  IOA20
A21  IOA21
A22  IOA22
A23  IOA23
A24  IOA24
A25  IOA25
A26  IOA26
A27  IOA27
A28  IOA28
A29  IOA29
A30  IOA30
A31  IOA31
A32  NC1  pas
A33  TMS  in
AA1  GND  pwr
AA2  GND  pwr
AA3  GXB_CMUTX_R1N  pas
AA4  GXB_CMUTX_R1P  pas
AA5  VCC  pwr
AA6  CLK8N  in
AA7  CLK8P  in
AA8  IOAA8
AA9  IOAA9
AA10  GND  pwr
AA11  IOAA11
AA12  IOAA12
AA13  VCC  pwr
AA14  GND  pwr
AA15  VCC  pwr
AA16  GND  pwr
AA17  VCC  pwr
AA18  GND  pwr
AA19  VCC  pwr
AA20  GND  pwr
AA21  VCC  pwr
AA22  GND  pwr
AA23  IOAA23
AA24  IOAA24
AA25  GND  pwr
AA26  IOAA26
AA27  IOAA27
AA28  CLK3P  in
AA29  CLK3N  in
AA30  VCC  pwr
AA31  GXB_CMUTX_L1P  pas
AA32  GXB_CMUTX_L1N  pas
AA33  GND  pwr
AA34  GND  pwr
AB1  GXB_CMURX_R1N  pas
AB2  GXB_CMURX_R1P  pas
AB3  GND  pwr
AB4  GND  pwr
AB5  GND  pwr
AB6  IOAB6
AB7  GND  pwr
AB8  IOAB8
AB9  IOAB9
AB10  IOAB10
AB11  IOAB11
AB12  IOAB12
AB13  GND  pwr
AB14  VCC  pwr
AB15  GND  pwr
AB16  VCC  pwr
AB17  GND  pwr
AB18  VCC  pwr
AB19  GND  pwr
AB20  VCC  pwr
AB21  GND  pwr
AB22  VCC  pwr
AB23  IOAB23
AB24  VCC  pwr
AB26  IOAB26
AB27  IOAB27
AB28  GND  pwr
AB29  IOAB29
AB30  GND  pwr
AB31  GND  pwr
AB32  GND  pwr
AB33  GXB_CMURX_L1P  pas
AB34  GXB_CMURX_L1N  pas
AC1  GND  pwr
AC2  GND  pwr
AC3  GXB_CMUTX_R0N  pas
AC4  GXB_CMUTX_R0P  pas
AC5  VCC  pwr
AC6  IOAC6
AC7  IOAC7
AC8  VCC  pwr
AC10  IOAC10
AC11  IOAC11
AC12  IOAC12
AC13  NC31  pas
AC14  NC32  pas
AC15  NC33  pas
AC16  NC34  pas
AC17  NC35  pas
AC18  IOAC18
AC19  NC36  pas
AC20  NC37  pas
AC21  NC38  pas
AC22  NC39  pas
AC23  VCC  pwr
AC24  IOAC24
AC25  IOAC25
AC26  IOAC26
AC27  VCC  pwr
AC28  IOAC28
AC29  IOAC29
AC30  VCC  pwr
AC31  GXB_CMUTX_L0P  pas
AC32  GXB_CMUTX_L0N  pas
AC33  GND  pwr
AC34  GND  pwr
AD1  GXB_CMURX_R0N  pas
AD2  GXB_CMURX_R0P  pas
AD3  GND  pwr
AD4  GND  pwr
AD5  GND  pwr
AD6  IOAD6
AD7  GND  pwr
AD8  IOAD8
AD9  IOAD9
AD10  GND  pwr
AD11  IOAD11
AD12  IOAD12
AD13  GND  pwr
AD14  NC27  pas
AD15  NC28  pas
AD16  GND  pwr
AD17  IOAD17
AD18  IOAD18
AD19  GND  pwr
AD20  NC29  pas
AD21  NC30  pas
AD22  GND  pwr
AD23  IOAD23
AD24  IOAD24
AD25  GND  pwr
AD26  IOAD26
AD27  IOAD27
AD28  GND  pwr
AD29  IOAD29
AD30  GND  pwr
AD31  GND  pwr
AD32  GND  pwr
AD33  GXB_CMURX_L0P  pas
AD34  GXB_CMURX_L0N  pas
AE1  GND  pwr
AE2  GND  pwr
AE3  GXB_TX_R1N  pas
AE4  GXB_TX_R1P  pas
AE5  GND  pwr
AE6  IOAE6
AE7  IOAE7
AE8  IOAE8
AE9  IOAE9
AE10  IOAE10
AE11  VCC  pwr
AE12  IOAE12
AE13  NC22  pas
AE14  NC23  pas
AE15  IOAE15
AE16  IOAE16
AE17  IOAE17
AE18  IOAE18
AE19  IOAE19
AE20  NC24  pas
AE21  NC25  pas
AE22  NC26  pas
AE23  IOAE23
AE24  IOAE24
AE26  VCC  pwr
AE27  IOAE27
AE28  IOAE28
AE29  IOAE29
AE30  GND  pwr
AE31  GXB_TX_L1P  pas
AE32  GXB_TX_L1N  pas
AE33  GND  pwr
AE34  GND  pwr
AF1  GXB_RX_R1N  pas
AF2  GXB_RX_R1P  pas
AF3  GND  pwr
AF4  GND  pwr
AF5  GND  pwr
AF6  IOAF6
AF7  IOAF7
AF9  IOAF9
AF10  IOAF10
AF11  IOAF11
AF12  IOAF12
AF13  NC21  pas
AF14  IOAF14
AF15  IOAF15
AF16  IOAF16
AF17  IOAF17
AF18  IOAF18
AF19  IOAF19
AF20  IOAF20
AF21  IOAF21
AF22  VCC  pwr
AF23  IOAF23
AF24  IOAF24
AF25  IOAF25
AF26  IOAF26
AF27  IOAF27
AF28  IOAF28
AF29  IOAF29
AF30  GND  pwr
AF31  GND  pwr
AF32  GND  pwr
AF33  GXB_RX_L1P  pas
AF34  GXB_RX_L1N  pas
AG1  GND  pwr
AG2  GND  pwr
AG3  GXB_TX_R0N  pas
AG4  GXB_TX_R0P  pas
AG5  GND  pwr
AG6  IOAG6
AG7  GND  pwr
AG8  IOAG8
AG9  IOAG9
AG10  GND  pwr
AG11  IOAG11
AG12  IOAG12
AG13  GND  pwr
AG15  IOAG15
AG16  GND  pwr
AG17  VCC  pwr
AG18  VCC  pwr
AG19  GND  pwr
AG21  IOAG21
AG22  GND  pwr
AG23  IOAG23
AG24  IOAG24
AG25  GND  pwr
AG26  IOAG26
AG27  IOAG27
AG28  GND  pwr
AG29  IOAG29
AG30  GND  pwr
AG31  GXB_TX_L0P  pas
AG32  GXB_TX_L0N  pas
AG33  GND  pwr
AG34  GND  pwr
AH1  GXB_RX_R0N  pas
AH2  GXB_RX_R0P  pas
AH3  GND  pwr
AH4  GND  pwr
AH5  GND  pwr
AH6  VCC  pwr
AH7  IOAH7
AH8  IOAH8
AH9  VCC  pwr
AH10  VCC  pwr
AH11  IOAH11
AH12  IOAH12
AH13  IOAH13
AH14  IOAH14
AH15  VCC  pwr
AH16  IOAH16
AH17  VCC  pwr
AH18  VCC  pwr
AH20  IOAH20
AH21  VCC  pwr
AH22  IOAH22
AH23  IOAH23
AH24  IOAH24
AH25  IOAH25
AH26  IOAH26
AH27  VCC  pwr
AH28  IOAH28
AH29  IOAH29
AH30  GND  pwr
AH31  GND  pwr
AH32  GND  pwr
AH33  GXB_RX_L0P  pas
AH34  GXB_RX_L0N  pas
AJ1  GND  pwr
AJ2  GND  pwr
AJ3  NC7  pas
AJ4  NC8  pas
AJ5  GND  pwr
AJ6  IOAJ6
AJ7  IOAJ7
AJ8  IOAJ8
AJ9  IOAJ9
AJ10  IOAJ10
AJ11  VCC  pwr
AJ12  IOAJ12
AJ13  IOAJ13
AJ14  IOAJ14
AJ15  IOAJ15
AJ17  VCC  pwr
AJ18  VCC  pwr
AJ19  IOAJ19
AJ20  IOAJ20
AJ21  IOAJ21
AJ22  IOAJ22
AJ23  IOAJ23
AJ24  VCC  pwr
AJ25  IOAJ25
AJ26  IOAJ26
AJ27  IOAJ27
AJ28  IOAJ28
AJ29  IOAJ29
AJ30  GND  pwr
AJ31  NC5  pas
AJ32  NC6  pas
AJ33  GND  pwr
AJ34  GND  pwr
AK1  RREF_R0  pas
AK2  GND  pwr
AK3  NC19  pas
AK4  GND  pwr
AK5  GND  pwr
AK6  IOAK6
AK7  GND  pwr
AK8  IOAK8
AK9  VCC  pwr
AK10  GND  pwr
AK11  IOAK11
AK12  IOAK12
AK13  GND  pwr
AK14  IOAK14
AK15  IOAK15
AK16  GND  pwr
AK17  IOAK17
AK18  VCC  pwr
AK19  GND  pwr
AK20  IOAK20
AK21  IOAK21
AK22  GND  pwr
AK23  IOAK23
AK24  IOAK24
AK25  GND  pwr
AK26  VCC  pwr
AK27  IOAK27
AK28  GND  pwr
AK29  IOAK29
AK30  GND  pwr
AK31  GND  pwr
AK32  NC20  pas
AK33  GND  pwr
AK34  RREF_L0  pas
AL1  GND  pwr
AL2  GND  pwr
AL3  NCEO  in
AL4  NC16  pas
AL5  IOAL5
AL6  IOAL6
AL7  IOAL7
AL8  IOAL8
AL9  IOAL9
AL10  IOAL10
AL11  IOAL11
AL12  IOAL12
AL13  IOAL13
AL14  IOAL14
AL15  IOAL15
AL16  IOAL16
AL17  IOAL17
AL18  IOAL18
AL19  IOAL19
AL20  IOAL20
AL21  IOAL21
AL22  IOAL22
AL23  IOAL23
AL24  IOAL24
AL25  IOAL25
AL26  IOAL26
AL27  IOAL27
AL28  IOAL28
AL29  IOAL29
AL30  NC17  pas
AL31  NC18  pas
AL32  CONF_DONE  in
AL33  GND  pwr
AL34  GND  pwr
AM1  ASDO  in
AM2  NCSO  in
AM3  DCLK  in
AM4  NC13  pas
AM5  IOAM5
AM6  IOAM6
AM7  IOAM7
AM8  IOAM8
AM9  VCC  pwr
AM10  IOAM10
AM11  IOAM11
AM12  VCC  pwr
AM13  IOAM13
AM14  IOAM14
AM15  IOAM15
AM16  IOAM16
AM17  IOAM17
AM18  IOAM18
AM19  IOAM19
AM20  IOAM20
AM21  IOAM21
AM22  IOAM22
AM23  IOAM23
AM24  VCC  pwr
AM25  IOAM25
AM26  IOAM26
AM27  VCC  pwr
AM28  IOAM28
AM29  IOAM29
AM30  IOAM30
AM31  NC14  pas
AM32  NC15  pas
AM33  NSTATUS  in
AM34  NCONFIG  in
AN1  GND  pwr
AN2  NIO_PULLUP  in
AN3  NC11  pas
AN4  GND  pwr
AN5  IOAN5
AN6  IOAN6
AN7  GND  pwr
AN8  IOAN8
AN9  IOAN9
AN10  GND  pwr
AN11  IOAN11
AN12  IOAN12
AN13  GND  pwr
AN14  IOAN14
AN15  IOAN15
AN16  GND  pwr
AN17  IOAN17
AN18  IOAN18
AN19  GND  pwr
AN20  IOAN20
AN21  IOAN21
AN22  GND  pwr
AN23  IOAN23
AN24  IOAN24
AN25  GND  pwr
AN26  IOAN26
AN27  IOAN27
AN28  GND  pwr
AN29  IOAN29
AN30  IOAN30
AN31  GND  pwr
AN32  NC12  pas
AN33  PORSEL  in
AN34  NCE  in
AP2  NC3  pas
AP3  NC9  pas
AP4  IOAP4
AP5  IOAP5
AP6  IOAP6
AP7  IOAP7
AP8  IOAP8
AP9  IOAP9
AP10  IOAP10
AP11  IOAP11
AP12  IOAP12
AP13  IOAP13
AP14  IOAP14
AP15  IOAP15
AP16  VCC  pwr
AP17  IOAP17
AP18  IOAP18
AP19  VCC  pwr
AP20  IOAP20
AP21  IOAP21
AP22  IOAP22
AP23  IOAP23
AP24  IOAP24
AP25  IOAP25
AP26  IOAP26
AP27  IOAP27
AP28  IOAP28
AP29  IOAP29
AP30  IOAP30
AP31  IOAP31
AP32  NC10  pas
AP33  NC2  pas
B1  MSEL2  in
B2  MSEL0  in
B3  TEMPDIODEP  pas
B4  GND  pwr
B5  IOB5
B6  IOB6
B7  GND  pwr
B8  IOB8
B9  IOB9
B10  GND  pwr
B11  IOB11
B12  IOB12
B13  GND  pwr
B14  IOB14
B15  IOB15
B16  GND  pwr
B17  IOB17
B18  IOB18
B19  GND  pwr
B20  IOB20
B21  IOB21
B22  GND  pwr
B23  IOB23
B24  IOB24
B25  GND  pwr
B26  IOB26
B27  IOB27
B28  GND  pwr
B29  IOB29
B30  IOB30
B31  GND  pwr
B32  TDI  in
B33  TDO  out
B34  TCK  in
C1  GND  pwr
C2  GND  pwr
C3  MSEL1  in
C4  NC69  pas
C5  IOC5
C6  IOC6
C7  IOC7
C8  VCC  pwr
C9  IOC9
C10  IOC10
C11  VCC  pwr
C12  IOC12
C13  IOC13
C14  IOC14
C15  IOC15
C16  IOC16
C17  IOC17
C18  IOC18
C19  IOC19
C20  IOC20
C21  IOC21
C22  IOC22
C23  IOC23
C24  VCC  pwr
C25  IOC25
C26  IOC26
C27  VCC  pwr
C28  IOC28
C29  IOC29
C30  IOC30
C31  NC70  pas
C32  TRST  in
C33  GND  pwr
C34  GND  pwr
D1  RREF_R1  pas
D2  GND  pwr
D3  GND  pwr
D4  GND  pwr
D5  GND  pwr
D6  IOD6
D7  IOD7
D8  IOD8
D9  IOD9
D10  IOD10
D11  IOD11
D12  IOD12
D13  IOD13
D14  IOD14
D15  IOD15
D16  IOD16
D17  IOD17
D18  IOD18
D19  IOD19
D20  IOD20
D21  IOD21
D22  IOD22
D23  IOD23
D24  IOD24
D25  IOD25
D26  IOD26
D27  IOD27
D28  IOD28
D29  IOD29
D30  GND  pwr
D31  GND  pwr
D32  GND  pwr
D33  GND  pwr
D34  RREF_L1  pas
E1  GND  pwr
E2  GND  pwr
E3  GXB_TX_R7N  pas
E4  GXB_TX_R7P  pas
E5  GND  pwr
E6  IOE6
E7  GND  pwr
E8  IOE8
E9  VCC  pwr
E10  GND  pwr
E11  IOE11
E12  IOE12
E13  GND  pwr
E14  IOE14
E15  IOE15
E16  GND  pwr
E17  IOE17
E18  VCC  pwr
E19  GND  pwr
E20  IOE20
E21  IOE21
E22  GND  pwr
E23  IOE23
E24  IOE24
E25  GND  pwr
E26  NC67  pas
E27  NC68  pas
E28  GND  pwr
E29  IOE29
E30  GND  pwr
E31  GXB_TX_L7P  pas
E32  GXB_TX_L7N  pas
E33  GND  pwr
E34  GND  pwr
F1  GXB_RX_R7N  pas
F2  GXB_RX_R7P  pas
F3  GND  pwr
F4  GND  pwr
F5  GND  pwr
F6  IOF6
F7  IOF7
F8  VCC  pwr
F9  IOF9
F10  IOF10
F11  IOF11
F12  VCC  pwr
F13  IOF13
F14  IOF14
F15  IOF15
F17  VCC  pwr
F18  VCC  pwr
F19  IOF19
F20  IOF20
F21  IOF21
F22  IOF22
F23  IOF23
F24  VCC  pwr
F25  IOF25
F26  IOF26
F27  VCC  pwr
F28  IOF28
F29  IOF29
F30  GND  pwr
F31  GND  pwr
F32  GND  pwr
F33  GXB_RX_L7P  pas
F34  GXB_RX_L7N  pas
G1  GND  pwr
G2  GND  pwr
G3  GXB_TX_R6N  pas
G4  GXB_TX_R6P  pas
G5  GND  pwr
G6  IOG6
G7  IOG7
G8  IOG8
G9  IOG9
G10  VCC  pwr
G11  IOG11
G12  IOG12
G13  IOG13
G15  VCC  pwr
G16  IOG16
G17  VCC  pwr
G18  VCC  pwr
G20  IOG20
G21  VCC  pwr
G22  IOG22
G23  IOG23
G24  IOG24
G25  IOG25
G26  IOG26
G27  IOG27
G28  IOG28
G29  IOG29
G30  GND  pwr
G31  GXB_TX_L6P  pas
G32  GXB_TX_L6N  pas
G33  GND  pwr
G34  GND  pwr
H1  GXB_RX_R6N  pas
H2  GXB_RX_R6P  pas
H3  GND  pwr
H4  GND  pwr
H5  GND  pwr
H6  IOH6
H7  GND  pwr
H8  IOH8
H9  IOH9
H10  GND  pwr
H11  IOH11
H12  IOH12
H13  GND  pwr
H14  IOH14
H15  IOH15
H16  GND  pwr
H17  VCC  pwr
H18  VCC  pwr
H19  GND  pwr
H21  IOH21
H22  GND  pwr
H23  NC66  pas
H24  IOH24
H25  GND  pwr
H26  IOH26
H27  IOH27
H28  GND  pwr
H29  IOH29
H30  GND  pwr
H31  GND  pwr
H32  GND  pwr
H33  GXB_RX_L6P  pas
H34  GXB_RX_L6N  pas
J1  GND  pwr
J2  GND  pwr
J3  GXB_CMUTX_R3N  pas
J4  GXB_CMUTX_R3P  pas
J5  IOJ5
J6  VCC  pwr
J7  IOJ7
J8  IOJ8
J9  IOJ9
J10  IOJ10
J11  VCC  pwr
J12  NC62  pas
J13  NC63  pas
J14  NC64  pas
J15  IOJ15
J16  IOJ16
J17  IOJ17
J18  IOJ18
J19  IOJ19
J20  IOJ20
J21  IOJ21
J22  VCC  pwr
J23  NC65  pas
J24  VCC  pwr
J25  IOJ25
J26  IOJ26
J27  IOJ27
J28  IOJ28
J29  IOJ29
J30  IOJ30
J31  GXB_CMUTX_L3P  pas
J32  GXB_CMUTX_L3N  pas
J33  GND  pwr
J34  GND  pwr
K1  GXB_CMURX_R3N  pas
K2  GXB_CMURX_R3P  pas
K3  GND  pwr
K4  GND  pwr
K5  IOK5
K6  IOK6
K7  IOK7
K8  IOK8
K10  IOK10
K11  IOK11
K12  NC54  pas
K13  NC55  pas
K14  NC56  pas
K15  NC57  pas
K16  IOK16
K17  IOK17
K18  IOK18
K19  IOK19
K20  NC58  pas
K21  NC59  pas
K22  NC60  pas
K23  NC61  pas
K24  IOK24
K25  IOK25
K26  IOK26
K27  IOK27
K28  IOK28
K29  IOK29
K30  IOK30
K31  GND  pwr
K32  GND  pwr
K33  GXB_CMURX_L3P  pas
K34  GXB_CMURX_L3N  pas
L1  GND  pwr
L2  GND  pwr
L3  GXB_CMUTX_R2N  pas
L4  GXB_CMUTX_R2P  pas
L5  IOL5
L6  IOL6
L7  GND  pwr
L8  IOL8
L9  IOL9
L10  GND  pwr
L11  IOL11
L12  NC49  pas
L13  GND  pwr
L14  NC50  pas
L15  NC51  pas
L16  GND  pwr
L17  IOL17
L18  IOL18
L19  GND  pwr
L20  NC52  pas
L21  NC53  pas
L22  GND  pwr
L23  IOL23
L24  IOL24
L25  GND  pwr
L26  IOL26
L27  IOL27
L28  GND  pwr
L29  IOL29
L30  IOL30
L31  GXB_CMUTX_L2P  pas
L32  GXB_CMUTX_L2N  pas
L33  GND  pwr
L34  GND  pwr
M1  GXB_CMURX_R2N  pas
M2  GXB_CMURX_R2P  pas
M3  GND  pwr
M4  GND  pwr
M5  IOM5
M6  IOM6
M7  IOM7
M8  IOM8
M9  VCC  pwr
M10  IOM10
M11  IOM11
M12  IOM12
M13  NC40  pas
M14  NC41  pas
M15  NC42  pas
M16  NC43  pas
M17  NC44  pas
M18  IOM18
M19  NC45  pas
M20  NC46  pas
M21  NC47  pas
M22  NC48  pas
M23  IOM23
M24  IOM24
M26  IOM26
M27  VCC  pwr
M28  IOM28
M29  IOM29
M30  IOM30
M31  GND  pwr
M32  GND  pwr
M33  GXB_CMURX_L2P  pas
M34  GXB_CMURX_L2N  pas
N1  GND  pwr
N2  GND  pwr
N3  GXB_TX_R5N  pas
N4  GXB_TX_R5P  pas
N5  VCC  pwr
N6  CLK10N  in
N7  CLK10P  in
N8  ION8
N9  ION9
N10  ION10
N11  ION11
N12  ION12
N13  VCC  pwr
N14  GND  pwr
N15  VCC  pwr
N16  GND  pwr
N17  VCC  pwr
N18  GND  pwr
N19  VCC  pwr
N20  GND  pwr
N21  VCC  pwr
N22  GND  pwr
N23  ION23
N24  VCC  pwr
N25  ION25
N26  ION26
N27  ION27
N28  CLK1P  in
N29  CLK1N  in
N30  VCC  pwr
N31  GXB_TX_L5P  pas
N32  GXB_TX_L5N  pas
N33  GND  pwr
N34  GND  pwr
P1  GXB_RX_R5N  pas
P2  GXB_RX_R5P  pas
P3  GND  pwr
P4  GND  pwr
P5  GND  pwr
P6  GND  pwr
P7  GND  pwr
P8  GND  pwr
P9  IOP9
P10  GND  pwr
P11  IOP11
P12  IOP12
P13  GND  pwr
P14  VCC  pwr
P15  GND  pwr
P16  VCC  pwr
P17  GND  pwr
P18  VCC  pwr
P19  GND  pwr
P20  VCC  pwr
P21  GND  pwr
P22  VCC  pwr
P23  IOP23
P24  IOP24
P25  GND  pwr
P26  IOP26
P27  GND  pwr
P28  GND  pwr
P29  GND  pwr
P30  GND  pwr
P31  GND  pwr
P32  GND  pwr
P33  GXB_RX_L5P  pas
P34  GXB_RX_L5N  pas
R1  GND  pwr
R2  GND  pwr
R3  GXB_TX_R4N  pas
R4  GXB_TX_R4P  pas
R5  VCC  pwr
R6  GND  pwr
R7  VCC  pwr
R8  GND  pwr
R10  IOR10
R11  IOR11
R12  IOR12
R13  IOR13
R14  GND  pwr
R15  VCC  pwr
R16  GND  pwr
R17  VCC  pwr
R18  GND  pwr
R19  VCC  pwr
R20  GND  pwr
R21  VCC  pwr
R22  GND  pwr
R23  IOR23
R24  IOR24
R25  IOR25
R27  GND  pwr
R28  VCC  pwr
R29  GND  pwr
R30  VCC  pwr
R31  GXB_TX_L4P  pas
R32  GXB_TX_L4N  pas
R33  GND  pwr
R34  GND  pwr
T1  GXB_RX_R4N  pas
T2  GXB_RX_R4P  pas
T3  GND  pwr
T4  GND  pwr
T5  GND  pwr
T6  VCC  pwr
T7  VCC  pwr
T8  VCC  pwr
T9  IOT9
T10  GND  pwr
T11  IOT11
T12  VCC  pwr
T13  GND  pwr
T14  VCC  pwr
T15  GND  pwr
T16  VCC  pwr
T17  GND  pwr
T18  VCC  pwr
T19  GND  pwr
T20  VCC  pwr
T21  GND  pwr
T22  VCC  pwr
T23  VCC  pwr
T24  IOT24
T25  GND  pwr
T26  IOT26
T27  VCC  pwr
T28  VCC  pwr
T29  VCC  pwr
T30  GND  pwr
T31  GND  pwr
T32  GND  pwr
T33  GXB_RX_L4P  pas
T34  GXB_RX_L4N  pas
U1  GND  pwr
U2  GND  pwr
U3  GXB_TX_R3N  pas
U4  GXB_TX_R3P  pas
U5  VCC  pwr
U6  GND  pwr
U7  GND  pwr
U8  VCC  pwr
U9  IOU9
U10  IOU10
U11  VCC  pwr
U12  VCC  pwr
U13  VCC  pwr
U14  GND  pwr
U15  VCC  pwr
U16  GND  pwr
U17  VCC  pwr
U18  GND  pwr
U19  VCC  pwr
U20  GND  pwr
U21  VCC  pwr
U22  GND  pwr
U23  VCC  pwr
U24  VCC  pwr
U25  IOU25
U26  IOU26
U27  VCC  pwr
U28  GND  pwr
U29  GND  pwr
U30  VCC  pwr
U31  GXB_TX_L3P  pas
U32  GXB_TX_L3N  pas
U33  GND  pwr
U34  GND  pwr
V1  GXB_RX_R3N  pas
V2  GXB_RX_R3P  pas
V3  GND  pwr
V4  GND  pwr
V5  GND  pwr
V6  GND  pwr
V7  VCC  pwr
V8  GND  pwr
V9  VCC  pwr
V10  IOV10
V11  VCC  pwr
V12  VCC  pwr
V13  GND  pwr
V14  VCC  pwr
V15  GND  pwr
V16  VCC  pwr
V17  DNU  pas
V18  VCC  pwr
V19  GND  pwr
V20  VCC  pwr
V21  GND  pwr
V22  VCC  pwr
V23  VCC  pwr
V24  VCC  pwr
V25  IOV25
V26  VCC  pwr
V27  GND  pwr
V28  VCC  pwr
V29  GND  pwr
V30  GND  pwr
V31  GND  pwr
V32  GND  pwr
V33  GXB_RX_L3P  pas
V34  GXB_RX_L3N  pas
W1  GND  pwr
W2  GND  pwr
W3  GXB_TX_R2N  pas
W4  GXB_TX_R2P  pas
W5  VCC  pwr
W6  VCC  pwr
W7  VCC  pwr
W8  VCC  pwr
W9  VCC  pwr
W10  GND  pwr
W11  IOW11
W12  IOW12
W13  VCC  pwr
W14  GND  pwr
W15  VCC  pwr
W16  GND  pwr
W17  VCC  pwr
W18  GND  pwr
W19  VCC  pwr
W20  GND  pwr
W21  VCC  pwr
W22  GND  pwr
W23  IOW23
W24  IOW24
W25  GND  pwr
W26  VCC  pwr
W27  VCC  pwr
W28  VCC  pwr
W29  VCC  pwr
W30  VCC  pwr
W31  GXB_TX_L2P  pas
W32  GXB_TX_L2N  pas
W33  GND  pwr
W34  GND  pwr
Y1  GXB_RX_R2N  pas
Y2  GXB_RX_R2P  pas
Y3  GND  pwr
Y4  GND  pwr
Y5  GND  pwr
Y6  GND  pwr
Y7  GND  pwr
Y8  VCC  pwr
Y9  VCC  pwr
Y10  IOY10
Y11  VCC  pwr
Y12  IOY12
Y13  GND  pwr
Y14  VCC  pwr
Y15  GND  pwr
Y16  VCC  pwr
Y17  GND  pwr
Y18  VCC  pwr
Y19  GND  pwr
Y20  VCC  pwr
Y21  GND  pwr
Y22  IOY22
Y23  IOY23
Y24  IOY24
Y25  IOY25
Y26  VCC  pwr
Y27  VCC  pwr
Y28  GND  pwr
Y29  GND  pwr
Y30  GND  pwr
Y31  GND  pwr
Y32  GND  pwr
Y33  GXB_RX_L2P  pas
Y34  GXB_RX_L2N  pas

## Footprint FBGA1152 (pad centres in mm)
1152-Pin FineLine Ball-Grid Array (FBGA), Option 1 - Flip Chip Auto generated by make-symbol-device-package-bsdl.ulp Rev. 29 Source: EP4SE360F35.bsd http://www.altera.com .. dspkg.pdf
smd 0.7 x 0.7: A2 -15.5,16.5; A3 -14.5,16.5; A4 -13.5,16.5; A5 -12.5,16.5; A6 -11.5,16.5; A7 -10.5,16.5; A8 -9.5,16.5; A9 -8.5,16.5; A10 -7.5,16.5; A11 -6.5,16.5; A12 -5.5,16.5; A13 -4.5,16.5; A14 -3.5,16.5; A15 -2.5,16.5; A16 -1.5,16.5; A17 -0.5,16.5; A18 0.5,16.5; A19 1.5,16.5; A20 2.5,16.5; A21 3.5,16.5; A22 4.5,16.5; A23 5.5,16.5; A24 6.5,16.5; A25 7.5,16.5; A26 8.5,16.5; A27 9.5,16.5; A28 10.5,16.5; A29 11.5,16.5; A30 12.5,16.5; A31 13.5,16.5; A32 14.5,16.5; A33 15.5,16.5; AA1 -16.5,-3.5; AA2 -15.5,-3.5; AA3 -14.5,-3.5; AA4 -13.5,-3.5; AA5 -12.5,-3.5; AA6 -11.5,-3.5; AA7 -10.5,-3.5; AA8 -9.5,-3.5; AA9 -8.5,-3.5; AA10 -7.5,-3.5; AA11 -6.5,-3.5; AA12 -5.5,-3.5; AA13 -4.5,-3.5; AA14 -3.5,-3.5; AA15 -2.5,-3.5; AA16 -1.5,-3.5; AA17 -0.5,-3.5; AA18 0.5,-3.5; AA19 1.5,-3.5; AA20 2.5,-3.5; AA21 3.5,-3.5; AA22 4.5,-3.5; AA23 5.5,-3.5; AA24 6.5,-3.5; AA25 7.5,-3.5; AA26 8.5,-3.5; AA27 9.5,-3.5; AA28 10.5,-3.5; AA29 11.5,-3.5; AA30 12.5,-3.5; AA31 13.5,-3.5; AA32 14.5,-3.5; AA33 15.5,-3.5; AA34 16.5,-3.5; AB1 -16.5,-4.5; AB2 -15.5,-4.5; AB3 -14.5,-4.5; AB4 -13.5,-4.5; AB5 -12.5,-4.5; AB6 -11.5,-4.5; AB7 -10.5,-4.5; AB8 -9.5,-4.5; AB9 -8.5,-4.5; AB10 -7.5,-4.5; AB11 -6.5,-4.5; AB12 -5.5,-4.5; AB13 -4.5,-4.5; AB14 -3.5,-4.5; AB15 -2.5,-4.5; AB16 -1.5,-4.5; AB17 -0.5,-4.5; AB18 0.5,-4.5; AB19 1.5,-4.5; AB20 2.5,-4.5; AB21 3.5,-4.5; AB22 4.5,-4.5; AB23 5.5,-4.5; AB24 6.5,-4.5; AB25 7.5,-4.5; AB26 8.5,-4.5; AB27 9.5,-4.5; AB28 10.5,-4.5; AB29 11.5,-4.5; AB30 12.5,-4.5; AB31 13.5,-4.5; AB32 14.5,-4.5; AB33 15.5,-4.5; AB34 16.5,-4.5; AC1 -16.5,-5.5; AC2 -15.5,-5.5; AC3 -14.5,-5.5; AC4 -13.5,-5.5; AC5 -12.5,-5.5; AC6 -11.5,-5.5; AC7 -10.5,-5.5; AC8 -9.5,-5.5; AC9 -8.5,-5.5; AC10 -7.5,-5.5; AC11 -6.5,-5.5; AC12 -5.5,-5.5; AC13 -4.5,-5.5; AC14 -3.5,-5.5; AC15 -2.5,-5.5; AC16 -1.5,-5.5; AC17 -0.5,-5.5; AC18 0.5,-5.5; AC19 1.5,-5.5; AC20 2.5,-5.5; AC21 3.5,-5.5; AC22 4.5,-5.5; AC23 5.5,-5.5; AC24 6.5,-5.5; AC25 7.5,-5.5; AC26 8.5,-5.5; AC27 9.5,-5.5; AC28 10.5,-5.5; AC29 11.5,-5.5; AC30 12.5,-5.5; AC31 13.5,-5.5; AC32 14.5,-5.5; AC33 15.5,-5.5; AC34 16.5,-5.5; AD1 -16.5,-6.5; AD2 -15.5,-6.5; AD3 -14.5,-6.5; AD4 -13.5,-6.5; AD5 -12.5,-6.5; AD6 -11.5,-6.5; AD7 -10.5,-6.5; AD8 -9.5,-6.5; AD9 -8.5,-6.5; AD10 -7.5,-6.5; AD11 -6.5,-6.5; AD12 -5.5,-6.5; AD13 -4.5,-6.5; AD14 -3.5,-6.5; AD15 -2.5,-6.5; AD16 -1.5,-6.5; AD17 -0.5,-6.5; AD18 0.5,-6.5; AD19 1.5,-6.5; AD20 2.5,-6.5; AD21 3.5,-6.5; AD22 4.5,-6.5; AD23 5.5,-6.5; AD24 6.5,-6.5; AD25 7.5,-6.5; AD26 8.5,-6.5; AD27 9.5,-6.5; AD28 10.5,-6.5; AD29 11.5,-6.5; AD30 12.5,-6.5; AD31 13.5,-6.5; AD32 14.5,-6.5; AD33 15.5,-6.5; AD34 16.5,-6.5; AE1 -16.5,-7.5; AE2 -15.5,-7.5; AE3 -14.5,-7.5; AE4 -13.5,-7.5; AE5 -12.5,-7.5; AE6 -11.5,-7.5; AE7 -10.5,-7.5; AE8 -9.5,-7.5; AE9 -8.5,-7.5; AE10 -7.5,-7.5; AE11 -6.5,-7.5; AE12 -5.5,-7.5; AE13 -4.5,-7.5; AE14 -3.5,-7.5; AE15 -2.5,-7.5; AE16 -1.5,-7.5; AE17 -0.5,-7.5; AE18 0.5,-7.5; AE19 1.5,-7.5; AE20 2.5,-7.5; AE21 3.5,-7.5; AE22 4.5,-7.5; AE23 5.5,-7.5; AE24 6.5,-7.5; AE25 7.5,-7.5; AE26 8.5,-7.5; AE27 9.5,-7.5; AE28 10.5,-7.5; AE29 11.5,-7.5; AE30 12.5,-7.5; AE31 13.5,-7.5; AE32 14.5,-7.5; AE33 15.5,-7.5; AE34 16.5,-7.5; AF1 -16.5,-8.5; AF2 -15.5,-8.5; AF3 -14.5,-8.5; AF4 -13.5,-8.5; AF5 -12.5,-8.5; AF6 -11.5,-8.5; AF7 -10.5,-8.5; AF8 -9.5,-8.5; AF9 -8.5,-8.5; AF10 -7.5,-8.5; AF11 -6.5,-8.5; AF12 -5.5,-8.5; AF13 -4.5,-8.5; AF14 -3.5,-8.5; AF15 -2.5,-8.5; AF16 -1.5,-8.5; AF17 -0.5,-8.5; AF18 0.5,-8.5; AF19 1.5,-8.5; AF20 2.5,-8.5; AF21 3.5,-8.5; AF22 4.5,-8.5; AF23 5.5,-8.5; AF24 6.5,-8.5; AF25 7.5,-8.5; AF26 8.5,-8.5; AF27 9.5,-8.5; AF28 10.5,-8.5; AF29 11.5,-8.5; AF30 12.5,-8.5; AF31 13.5,-8.5; AF32 14.5,-8.5; AF33 15.5,-8.5; AF34 16.5,-8.5; AG1 -16.5,-9.5; AG2 -15.5,-9.5; AG3 -14.5,-9.5; AG4 -13.5,-9.5; AG5 -12.5,-9.5; AG6 -11.5,-9.5; AG7 -10.5,-9.5; AG8 -9.5,-9.5; AG9 -8.5,-9.5; AG10 -7.5,-9.5; AG11 -6.5,-9.5; AG12 -5.5,-9.5; AG13 -4.5,-9.5; AG14 -3.5,-9.5; AG15 -2.5,-9.5; AG16 -1.5,-9.5; AG17 -0.5,-9.5; AG18 0.5,-9.5; AG19 1.5,-9.5; AG20 2.5,-9.5; AG21 3.5,-9.5; AG22 4.5,-9.5; AG23 5.5,-9.5; AG24 6.5,-9.5; AG25 7.5,-9.5; AG26 8.5,-9.5; AG27 9.5,-9.5; AG28 10.5,-9.5; AG29 11.5,-9.5; AG30 12.5,-9.5; AG31 13.5,-9.5; AG32 14.5,-9.5; AG33 15.5,-9.5; AG34 16.5,-9.5; AH1 -16.5,-10.5; AH2 -15.5,-10.5; AH3 -14.5,-10.5; AH4 -13.5,-10.5; AH5 -12.5,-10.5; AH6 -11.5,-10.5; AH7 -10.5,-10.5; AH8 -9.5,-10.5; AH9 -8.5,-10.5; AH10 -7.5,-10.5; AH11 -6.5,-10.5; AH12 -5.5,-10.5; AH13 -4.5,-10.5; AH14 -3.5,-10.5; AH15 -2.5,-10.5; AH16 -1.5,-10.5; AH17 -0.5,-10.5; AH18 0.5,-10.5; AH19 1.5,-10.5; AH20 2.5,-10.5; AH21 3.5,-10.5; AH22 4.5,-10.5; AH23 5.5,-10.5; AH24 6.5,-10.5; AH25 7.5,-10.5; AH26 8.5,-10.5; AH27 9.5,-10.5; AH28 10.5,-10.5; AH29 11.5,-10.5; AH30 12.5,-10.5; AH31 13.5,-10.5; AH32 14.5,-10.5; AH33 15.5,-10.5; AH34 16.5,-10.5; AJ1 -16.5,-11.5; AJ2 -15.5,-11.5; AJ3 -14.5,-11.5; AJ4 -13.5,-11.5; AJ5 -12.5,-11.5; AJ6 -11.5,-11.5; AJ7 -10.5,-11.5; AJ8 -9.5,-11.5; AJ9 -8.5,-11.5; AJ10 -7.5,-11.5; AJ11 -6.5,-11.5; AJ12 -5.5,-11.5; AJ13 -4.5,-11.5; AJ14 -3.5,-11.5; AJ15 -2.5,-11.5; AJ16 -1.5,-11.5; AJ17 -0.5,-11.5; AJ18 0.5,-11.5; AJ19 1.5,-11.5; AJ20 2.5,-11.5; AJ21 3.5,-11.5; AJ22 4.5,-11.5; AJ23 5.5,-11.5; AJ24 6.5,-11.5; AJ25 7.5,-11.5; AJ26 8.5,-11.5; AJ27 9.5,-11.5; AJ28 10.5,-11.5; AJ29 11.5,-11.5; AJ30 12.5,-11.5; AJ31 13.5,-11.5; AJ32 14.5,-11.5; AJ33 15.5,-11.5; AJ34 16.5,-11.5; AK1 -16.5,-12.5; AK2 -15.5,-12.5; AK3 -14.5,-12.5; AK4 -13.5,-12.5; AK5 -12.5,-12.5; AK6 -11.5,-12.5; AK7 -10.5,-12.5; AK8 -9.5,-12.5; AK9 -8.5,-12.5; AK10 -7.5,-12.5; AK11 -6.5,-12.5; AK12 -5.5,-12.5; AK13 -4.5,-12.5; AK14 -3.5,-12.5; AK15 -2.5,-12.5; AK16 -1.5,-12.5; AK17 -0.5,-12.5; AK18 0.5,-12.5; AK19 1.5,-12.5; AK20 2.5,-12.5; AK21 3.5,-12.5; AK22 4.5,-12.5; AK23 5.5,-12.5; AK24 6.5,-12.5; AK25 7.5,-12.5; AK26 8.5,-12.5; AK27 9.5,-12.5; AK28 10.5,-12.5; AK29 11.5,-12.5; AK30 12.5,-12.5; AK31 13.5,-12.5; AK32 14.5,-12.5; AK33 15.5,-12.5; AK34 16.5,-12.5; AL1 -16.5,-13.5; AL2 -15.5,-13.5; AL3 -14.5,-13.5; AL4 -13.5,-13.5; AL5 -12.5,-13.5; AL6 -11.5,-13.5; AL7 -10.5,-13.5; AL8 -9.5,-13.5; AL9 -8.5,-13.5; AL10 -7.5,-13.5; AL11 -6.5,-13.5; AL12 -5.5,-13.5; AL13 -4.5,-13.5; AL14 -3.5,-13.5; AL15 -2.5,-13.5; AL16 -1.5,-13.5; AL17 -0.5,-13.5; AL18 0.5,-13.5; AL19 1.5,-13.5; AL20 2.5,-13.5; AL21 3.5,-13.5; AL22 4.5,-13.5; AL23 5.5,-13.5; AL24 6.5,-13.5; AL25 7.5,-13.5; AL26 8.5,-13.5; AL27 9.5,-13.5; AL28 10.5,-13.5; AL29 11.5,-13.5; AL30 12.5,-13.5; AL31 13.5,-13.5; AL32 14.5,-13.5; AL33 15.5,-13.5; AL34 16.5,-13.5; AM1 -16.5,-14.5; AM2 -15.5,-14.5; AM3 -14.5,-14.5; AM4 -13.5,-14.5; AM5 -12.5,-14.5; AM6 -11.5,-14.5; AM7 -10.5,-14.5; AM8 -9.5,-14.5; AM9 -8.5,-14.5; AM10 -7.5,-14.5; AM11 -6.5,-14.5; AM12 -5.5,-14.5; AM13 -4.5,-14.5; AM14 -3.5,-14.5; AM15 -2.5,-14.5; AM16 -1.5,-14.5; AM17 -0.5,-14.5; AM18 0.5,-14.5; AM19 1.5,-14.5; AM20 2.5,-14.5; AM21 3.5,-14.5; AM22 4.5,-14.5; AM23 5.5,-14.5; AM24 6.5,-14.5; AM25 7.5,-14.5; AM26 8.5,-14.5; AM27 9.5,-14.5; AM28 10.5,-14.5; AM29 11.5,-14.5; AM30 12.5,-14.5; AM31 13.5,-14.5; AM32 14.5,-14.5; AM33 15.5,-14.5; AM34 16.5,-14.5; AN1 -16.5,-15.5; AN2 -15.5,-15.5; AN3 -14.5,-15.5; AN4 -13.5,-15.5; AN5 -12.5,-15.5; AN6 -11.5,-15.5; AN7 -10.5,-15.5; AN8 -9.5,-15.5; AN9 -8.5,-15.5; AN10 -7.5,-15.5; AN11 -6.5,-15.5; AN12 -5.5,-15.5; AN13 -4.5,-15.5; AN14 -3.5,-15.5; AN15 -2.5,-15.5; AN16 -1.5,-15.5; AN17 -0.5,-15.5; AN18 0.5,-15.5; AN19 1.5,-15.5; AN20 2.5,-15.5; AN21 3.5,-15.5; AN22 4.5,-15.5; AN23 5.5,-15.5; AN24 6.5,-15.5; AN25 7.5,-15.5; AN26 8.5,-15.5; AN27 9.5,-15.5; AN28 10.5,-15.5; AN29 11.5,-15.5; AN30 12.5,-15.5; AN31 13.5,-15.5; AN32 14.5,-15.5; AN33 15.5,-15.5; AN34 16.5,-15.5; AP2 -15.5,-16.5; AP3 -14.5,-16.5; AP4 -13.5,-16.5; AP5 -12.5,-16.5; AP6 -11.5,-16.5; AP7 -10.5,-16.5; AP8 -9.5,-16.5; AP9 -8.5,-16.5; AP10 -7.5,-16.5; AP11 -6.5,-16.5; AP12 -5.5,-16.5; AP13 -4.5,-16.5; AP14 -3.5,-16.5; AP15 -2.5,-16.5; AP16 -1.5,-16.5; AP17 -0.5,-16.5; AP18 0.5,-16.5; AP19 1.5,-16.5; AP20 2.5,-16.5; AP21 3.5,-16.5; AP22 4.5,-16.5; AP23 5.5,-16.5; AP24 6.5,-16.5; AP25 7.5,-16.5; AP26 8.5,-16.5; AP27 9.5,-16.5; AP28 10.5,-16.5; AP29 11.5,-16.5; AP30 12.5,-16.5; AP31 13.5,-16.5; AP32 14.5,-16.5; AP33 15.5,-16.5; B1 -16.5,15.5; B2 -15.5,15.5; B3 -14.5,15.5; B4 -13.5,15.5; B5 -12.5,15.5; B6 -11.5,15.5; B7 -10.5,15.5; B8 -9.5,15.5; B9 -8.5,15.5; B10 -7.5,15.5; B11 -6.5,15.5; B12 -5.5,15.5; B13 -4.5,15.5; B14 -3.5,15.5; B15 -2.5,15.5; B16 -1.5,15.5; B17 -0.5,15.5; B18 0.5,15.5; B19 1.5,15.5; B20 2.5,15.5; B21 3.5,15.5; B22 4.5,15.5; B23 5.5,15.5; B24 6.5,15.5; B25 7.5,15.5; B26 8.5,15.5; B27 9.5,15.5; B28 10.5,15.5; B29 11.5,15.5; B30 12.5,15.5; B31 13.5,15.5; B32 14.5,15.5; B33 15.5,15.5; B34 16.5,15.5; C1 -16.5,14.5; C2 -15.5,14.5; C3 -14.5,14.5; C4 -13.5,14.5; C5 -12.5,14.5; C6 -11.5,14.5; C7 -10.5,14.5; C8 -9.5,14.5; C9 -8.5,14.5; C10 -7.5,14.5; C11 -6.5,14.5; C12 -5.5,14.5; C13 -4.5,14.5; C14 -3.5,14.5; C15 -2.5,14.5; C16 -1.5,14.5; C17 -0.5,14.5; C18 0.5,14.5; C19 1.5,14.5; C20 2.5,14.5; C21 3.5,14.5; C22 4.5,14.5; C23 5.5,14.5; C24 6.5,14.5; C25 7.5,14.5; C26 8.5,14.5; C27 9.5,14.5; C28 10.5,14.5; C29 11.5,14.5; C30 12.5,14.5; C31 13.5,14.5; C32 14.5,14.5; C33 15.5,14.5; C34 16.5,14.5; D1 -16.5,13.5; D2 -15.5,13.5; D3 -14.5,13.5; D4 -13.5,13.5; D5 -12.5,13.5; D6 -11.5,13.5; D7 -10.5,13.5; D8 -9.5,13.5; D9 -8.5,13.5; D10 -7.5,13.5; D11 -6.5,13.5; D12 -5.5,13.5; D13 -4.5,13.5; D14 -3.5,13.5; D15 -2.5,13.5; D16 -1.5,13.5; D17 -0.5,13.5; D18 0.5,13.5; D19 1.5,13.5; D20 2.5,13.5; D21 3.5,13.5; D22 4.5,13.5; D23 5.5,13.5; D24 6.5,13.5; D25 7.5,13.5; D26 8.5,13.5; D27 9.5,13.5; D28 10.5,13.5; D29 11.5,13.5; D30 12.5,13.5; D31 13.5,13.5; D32 14.5,13.5; D33 15.5,13.5; D34 16.5,13.5; E1 -16.5,12.5; E2 -15.5,12.5; E3 -14.5,12.5; E4 -13.5,12.5; E5 -12.5,12.5; E6 -11.5,12.5; E7 -10.5,12.5; E8 -9.5,12.5; E9 -8.5,12.5; E10 -7.5,12.5; E11 -6.5,12.5; E12 -5.5,12.5; E13 -4.5,12.5; E14 -3.5,12.5; E15 -2.5,12.5; E16 -1.5,12.5; E17 -0.5,12.5; E18 0.5,12.5; E19 1.5,12.5; E20 2.5,12.5; E21 3.5,12.5; E22 4.5,12.5; E23 5.5,12.5; E24 6.5,12.5; E25 7.5,12.5; E26 8.5,12.5; E27 9.5,12.5; E28 10.5,12.5; E29 11.5,12.5; E30 12.5,12.5; E31 13.5,12.5; E32 14.5,12.5; E33 15.5,12.5; E34 16.5,12.5; F1 -16.5,11.5; F2 -15.5,11.5; F3 -14.5,11.5; F4 -13.5,11.5; F5 -12.5,11.5; F6 -11.5,11.5; F7 -10.5,11.5; F8 -9.5,11.5; F9 -8.5,11.5; F10 -7.5,11.5; F11 -6.5,11.5; F12 -5.5,11.5; F13 -4.5,11.5; F14 -3.5,11.5; F15 -2.5,11.5; F16 -1.5,11.5; F17 -0.5,11.5; F18 0.5,11.5; F19 1.5,11.5; F20 2.5,11.5; F21 3.5,11.5; F22 4.5,11.5; F23 5.5,11.5; F24 6.5,11.5; F25 7.5,11.5; F26 8.5,11.5; F27 9.5,11.5; F28 10.5,11.5; F29 11.5,11.5; F30 12.5,11.5; F31 13.5,11.5; F32 14.5,11.5; F33 15.5,11.5; F34 16.5,11.5; G1 -16.5,10.5; G2 -15.5,10.5; G3 -14.5,10.5; G4 -13.5,10.5; G5 -12.5,10.5; G6 -11.5,10.5; G7 -10.5,10.5; G8 -9.5,10.5; G9 -8.5,10.5; G10 -7.5,10.5; G11 -6.5,10.5; G12 -5.5,10.5; G13 -4.5,10.5; G14 -3.5,10.5; G15 -2.5,10.5; G16 -1.5,10.5; G17 -0.5,10.5; G18 0.5,10.5; G19 1.5,10.5; G20 2.5,10.5; G21 3.5,10.5; G22 4.5,10.5; G23 5.5,10.5; G24 6.5,10.5; G25 7.5,10.5; G26 8.5,10.5; G27 9.5,10.5; G28 10.5,10.5; G29 11.5,10.5; G30 12.5,10.5; G31 13.5,10.5; G32 14.5,10.5; G33 15.5,10.5; G34 16.5,10.5; H1 -16.5,9.5; H2 -15.5,9.5; H3 -14.5,9.5; H4 -13.5,9.5; H5 -12.5,9.5; H6 -11.5,9.5; H7 -10.5,9.5; H8 -9.5,9.5; H9 -8.5,9.5; H10 -7.5,9.5; H11 -6.5,9.5; H12 -5.5,9.5; H13 -4.5,9.5; H14 -3.5,9.5; H15 -2.5,9.5; H16 -1.5,9.5; H17 -0.5,9.5; H18 0.5,9.5; H19 1.5,9.5; H20 2.5,9.5; H21 3.5,9.5; H22 4.5,9.5; H23 5.5,9.5; H24 6.5,9.5; H25 7.5,9.5; H26 8.5,9.5; H27 9.5,9.5; H28 10.5,9.5; H29 11.5,9.5; H30 12.5,9.5; H31 13.5,9.5; H32 14.5,9.5; H33 15.5,9.5; H34 16.5,9.5; J1 -16.5,8.5; J2 -15.5,8.5; J3 -14.5,8.5; J4 -13.5,8.5; J5 -12.5,8.5; J6 -11.5,8.5; J7 -10.5,8.5; J8 -9.5,8.5; J9 -8.5,8.5; J10 -7.5,8.5; J11 -6.5,8.5; J12 -5.5,8.5; J13 -4.5,8.5; J14 -3.5,8.5; J15 -2.5,8.5; J16 -1.5,8.5; J17 -0.5,8.5; J18 0.5,8.5; J19 1.5,8.5; J20 2.5,8.5; J21 3.5,8.5; J22 4.5,8.5; J23 5.5,8.5; J24 6.5,8.5; J25 7.5,8.5; J26 8.5,8.5; J27 9.5,8.5; J28 10.5,8.5; J29 11.5,8.5; J30 12.5,8.5; J31 13.5,8.5; J32 14.5,8.5; J33 15.5,8.5; J34 16.5,8.5; K1 -16.5,7.5; K2 -15.5,7.5; K3 -14.5,7.5; K4 -13.5,7.5; K5 -12.5,7.5; K6 -11.5,7.5; K7 -10.5,7.5; K8 -9.5,7.5; K9 -8.5,7.5; K10 -7.5,7.5; K11 -6.5,7.5; K12 -5.5,7.5; K13 -4.5,7.5; K14 -3.5,7.5; K15 -2.5,7.5; K16 -1.5,7.5; K17 -0.5,7.5; K18 0.5,7.5; K19 1.5,7.5; K20 2.5,7.5; K21 3.5,7.5; K22 4.5,7.5; K23 5.5,7.5; K24 6.5,7.5; K25 7.5,7.5; K26 8.5,7.5; K27 9.5,7.5; K28 10.5,7.5; K29 11.5,7.5; K30 12.5,7.5; K31 13.5,7.5; K32 14.5,7.5; K33 15.5,7.5; K34 16.5,7.5; L1 -16.5,6.5; L2 -15.5,6.5; L3 -14.5,6.5; L4 -13.5,6.5; L5 -12.5,6.5; L6 -11.5,6.5; L7 -10.5,6.5; L8 -9.5,6.5; L9 -8.5,6.5; L10 -7.5,6.5; L11 -6.5,6.5; L12 -5.5,6.5; L13 -4.5,6.5; L14 -3.5,6.5; L15 -2.5,6.5; L16 -1.5,6.5; L17 -0.5,6.5; L18 0.5,6.5; L19 1.5,6.5; L20 2.5,6.5; L21 3.5,6.5; L22 4.5,6.5; L23 5.5,6.5; L24 6.5,6.5; L25 7.5,6.5; L26 8.5,6.5; L27 9.5,6.5; L28 10.5,6.5; L29 11.5,6.5; L30 12.5,6.5; L31 13.5,6.5; L32 14.5,6.5; L33 15.5,6.5; L34 16.5,6.5; M1 -16.5,5.5; M2 -15.5,5.5; M3 -14.5,5.5; M4 -13.5,5.5; M5 -12.5,5.5; M6 -11.5,5.5; M7 -10.5,5.5; M8 -9.5,5.5; M9 -8.5,5.5; M10 -7.5,5.5; M11 -6.5,5.5; M12 -5.5,5.5; M13 -4.5,5.5; M14 -3.5,5.5; M15 -2.5,5.5; M16 -1.5,5.5; M17 -0.5,5.5; M18 0.5,5.5; M19 1.5,5.5; M20 2.5,5.5; M21 3.5,5.5; M22 4.5,5.5; M23 5.5,5.5; M24 6.5,5.5; M25 7.5,5.5; M26 8.5,5.5; M27 9.5,5.5; M28 10.5,5.5; M29 11.5,5.5; M30 12.5,5.5; M31 13.5,5.5; M32 14.5,5.5; M33 15.5,5.5; M34 16.5,5.5; N1 -16.5,4.5; N2 -15.5,4.5; N3 -14.5,4.5; N4 -13.5,4.5; N5 -12.5,4.5; N6 -11.5,4.5; N7 -10.5,4.5; N8 -9.5,4.5; N9 -8.5,4.5; N10 -7.5,4.5; N11 -6.5,4.5; N12 -5.5,4.5; N13 -4.5,4.5; N14 -3.5,4.5; N15 -2.5,4.5; N16 -1.5,4.5; N17 -0.5,4.5; N18 0.5,4.5; N19 1.5,4.5; N20 2.5,4.5; N21 3.5,4.5; N22 4.5,4.5; N23 5.5,4.5; N24 6.5,4.5; N25 7.5,4.5; N26 8.5,4.5; N27 9.5,4.5; N28 10.5,4.5; N29 11.5,4.5; N30 12.5,4.5; N31 13.5,4.5; N32 14.5,4.5; N33 15.5,4.5; N34 16.5,4.5; P1 -16.5,3.5; P2 -15.5,3.5; P3 -14.5,3.5; P4 -13.5,3.5; P5 -12.5,3.5; P6 -11.5,3.5; P7 -10.5,3.5; P8 -9.5,3.5; P9 -8.5,3.5; P10 -7.5,3.5; P11 -6.5,3.5; P12 -5.5,3.5; P13 -4.5,3.5; P14 -3.5,3.5; P15 -2.5,3.5; P16 -1.5,3.5; P17 -0.5,3.5; P18 0.5,3.5; P19 1.5,3.5; P20 2.5,3.5; P21 3.5,3.5; P22 4.5,3.5; P23 5.5,3.5; P24 6.5,3.5; P25 7.5,3.5; P26 8.5,3.5; P27 9.5,3.5; P28 10.5,3.5; P29 11.5,3.5; P30 12.5,3.5; P31 13.5,3.5; P32 14.5,3.5; P33 15.5,3.5; P34 16.5,3.5; R1 -16.5,2.5; R2 -15.5,2.5; R3 -14.5,2.5; R4 -13.5,2.5; R5 -12.5,2.5; R6 -11.5,2.5; R7 -10.5,2.5; R8 -9.5,2.5; R9 -8.5,2.5; R10 -7.5,2.5; R11 -6.5,2.5; R12 -5.5,2.5; R13 -4.5,2.5; R14 -3.5,2.5; R15 -2.5,2.5; R16 -1.5,2.5; R17 -0.5,2.5; R18 0.5,2.5; R19 1.5,2.5; R20 2.5,2.5; R21 3.5,2.5; R22 4.5,2.5; R23 5.5,2.5; R24 6.5,2.5; R25 7.5,2.5; R26 8.5,2.5; R27 9.5,2.5; R28 10.5,2.5; R29 11.5,2.5; R30 12.5,2.5; R31 13.5,2.5; R32 14.5,2.5; R33 15.5,2.5; R34 16.5,2.5; T1 -16.5,1.5; T2 -15.5,1.5; T3 -14.5,1.5; T4 -13.5,1.5; T5 -12.5,1.5; T6 -11.5,1.5; T7 -10.5,1.5; T8 -9.5,1.5; T9 -8.5,1.5; T10 -7.5,1.5; T11 -6.5,1.5; T12 -5.5,1.5; T13 -4.5,1.5; T14 -3.5,1.5; T15 -2.5,1.5; T16 -1.5,1.5; T17 -0.5,1.5; T18 0.5,1.5; T19 1.5,1.5; T20 2.5,1.5; T21 3.5,1.5; T22 4.5,1.5; T23 5.5,1.5; T24 6.5,1.5; T25 7.5,1.5; T26 8.5,1.5; T27 9.5,1.5; T28 10.5,1.5; T29 11.5,1.5; T30 12.5,1.5; T31 13.5,1.5; T32 14.5,1.5; T33 15.5,1.5; T34 16.5,1.5; U1 -16.5,0.5; U2 -15.5,0.5; U3 -14.5,0.5; U4 -13.5,0.5; U5 -12.5,0.5; U6 -11.5,0.5; U7 -10.5,0.5; U8 -9.5,0.5; U9 -8.5,0.5; U10 -7.5,0.5; U11 -6.5,0.5; U12 -5.5,0.5; U13 -4.5,0.5; U14 -3.5,0.5; U15 -2.5,0.5; U16 -1.5,0.5; U17 -0.5,0.5; U18 0.5,0.5; U19 1.5,0.5; U20 2.5,0.5; U21 3.5,0.5; U22 4.5,0.5; U23 5.5,0.5; U24 6.5,0.5; U25 7.5,0.5; U26 8.5,0.5; U27 9.5,0.5; U28 10.5,0.5; U29 11.5,0.5; U30 12.5,0.5; U31 13.5,0.5; U32 14.5,0.5; U33 15.5,0.5; U34 16.5,0.5; V1 -16.5,-0.5; V2 -15.5,-0.5; V3 -14.5,-0.5; V4 -13.5,-0.5; V5 -12.5,-0.5; V6 -11.5,-0.5; V7 -10.5,-0.5; V8 -9.5,-0.5; V9 -8.5,-0.5; V10 -7.5,-0.5; V11 -6.5,-0.5; V12 -5.5,-0.5; V13 -4.5,-0.5; V14 -3.5,-0.5; V15 -2.5,-0.5; V16 -1.5,-0.5; V17 -0.5,-0.5; V18 0.5,-0.5; V19 1.5,-0.5; V20 2.5,-0.5; V21 3.5,-0.5; V22 4.5,-0.5; V23 5.5,-0.5; V24 6.5,-0.5; V25 7.5,-0.5; V26 8.5,-0.5; V27 9.5,-0.5; V28 10.5,-0.5; V29 11.5,-0.5; V30 12.5,-0.5; V31 13.5,-0.5; V32 14.5,-0.5; V33 15.5,-0.5; V34 16.5,-0.5; W1 -16.5,-1.5; W2 -15.5,-1.5; W3 -14.5,-1.5; W4 -13.5,-1.5; W5 -12.5,-1.5; W6 -11.5,-1.5; W7 -10.5,-1.5; W8 -9.5,-1.5; W9 -8.5,-1.5; W10 -7.5,-1.5; W11 -6.5,-1.5; W12 -5.5,-1.5; W13 -4.5,-1.5; W14 -3.5,-1.5; W15 -2.5,-1.5; W16 -1.5,-1.5; W17 -0.5,-1.5; W18 0.5,-1.5; W19 1.5,-1.5; W20 2.5,-1.5; W21 3.5,-1.5; W22 4.5,-1.5; W23 5.5,-1.5; W24 6.5,-1.5; W25 7.5,-1.5; W26 8.5,-1.5; W27 9.5,-1.5; W28 10.5,-1.5; W29 11.5,-1.5; W30 12.5,-1.5; W31 13.5,-1.5; W32 14.5,-1.5; W33 15.5,-1.5; W34 16.5,-1.5; Y1 -16.5,-2.5; Y2 -15.5,-2.5; Y3 -14.5,-2.5; Y4 -13.5,-2.5; Y5 -12.5,-2.5; Y6 -11.5,-2.5; Y7 -10.5,-2.5; Y8 -9.5,-2.5; Y9 -8.5,-2.5; Y10 -7.5,-2.5; Y11 -6.5,-2.5; Y12 -5.5,-2.5; Y13 -4.5,-2.5; Y14 -3.5,-2.5; Y15 -2.5,-2.5; Y16 -1.5,-2.5; Y17 -0.5,-2.5; Y18 0.5,-2.5; Y19 1.5,-2.5; Y20 2.5,-2.5; Y21 3.5,-2.5; Y22 4.5,-2.5; Y23 5.5,-2.5; Y24 6.5,-2.5; Y25 7.5,-2.5; Y26 8.5,-2.5; Y27 9.5,-2.5; Y28 10.5,-2.5; Y29 11.5,-2.5; Y30 12.5,-2.5; Y31 13.5,-2.5; Y32 14.5,-2.5; Y33 15.5,-2.5; Y34 16.5,-2.5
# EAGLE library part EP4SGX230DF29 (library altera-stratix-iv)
EP4SGX230DF29 Auto generated by make-symbol-device-package-bsdl.ulp Rev. 29 Source: EP4SGX230DF29.bsd

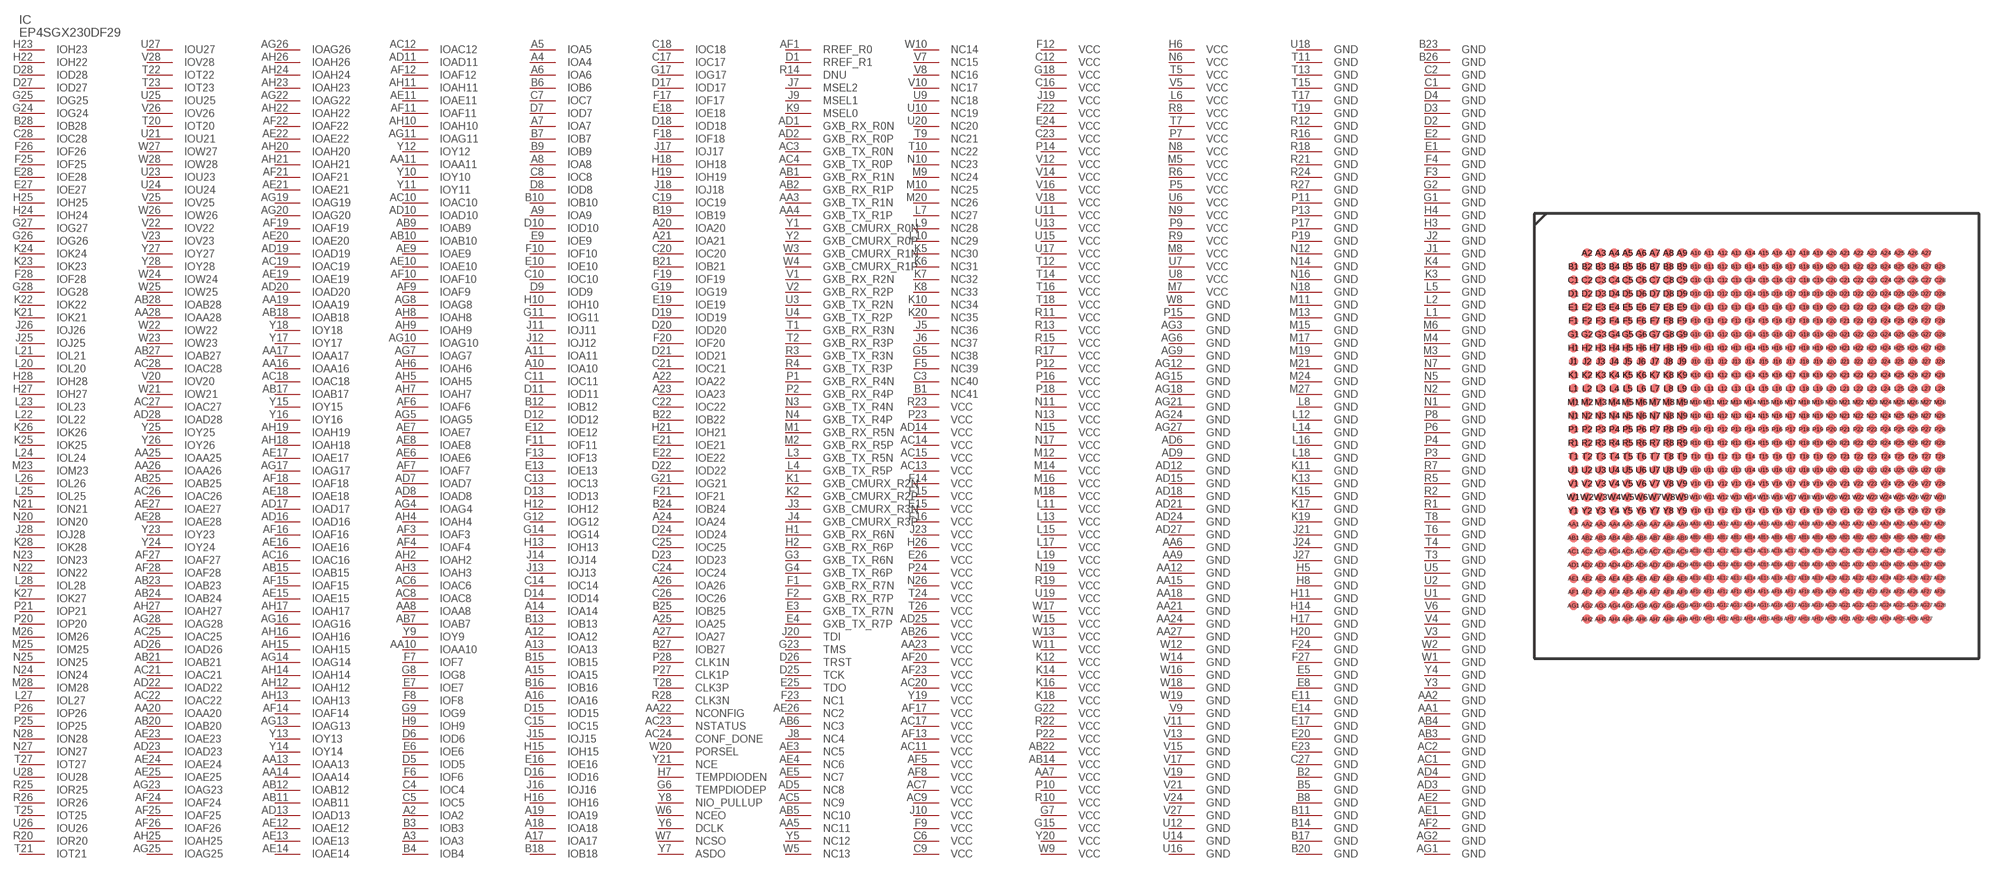
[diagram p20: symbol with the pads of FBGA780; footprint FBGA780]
Designator prefix IC

## EP4SGX230DF29 (MPN: EP4SGX230DF29C3N; OC_FARNELL: unknown; OC_NEWARK: 52R1825)  [FBGA780]
A2  IOA2
A3  IOA3
A4  IOA4
A5  IOA5
A6  IOA6
A7  IOA7
A8  IOA8
A9  IOA9
A10  IOA10
A11  IOA11
A12  IOA12
A13  IOA13
A14  IOA14
A15  IOA15
A16  IOA16
A17  IOA17
A18  IOA18
A19  IOA19
A20  IOA20
A21  IOA21
A22  IOA22
A23  IOA23
A24  IOA24
A25  IOA25
A26  IOA26
A27  IOA27
AA1  GND  pwr
AA2  GND  pwr
AA3  GXB_TX_R1N  pas
AA4  GXB_TX_R1P  pas
AA5  NC11  pas
AA6  GND  pwr
AA7  VCC  pwr
AA8  IOAA8
AA9  GND  pwr
AA10  IOAA10
AA11  IOAA11
AA12  GND  pwr
AA13  IOAA13
AA14  IOAA14
AA15  GND  pwr
AA16  IOAA16
AA17  IOAA17
AA18  GND  pwr
AA19  IOAA19
AA20  IOAA20
AA21  GND  pwr
AA22  NCONFIG  pas
AA23  VCC  pwr
AA24  GND  pwr
AA25  IOAA25
AA26  IOAA26
AA27  GND  pwr
AA28  IOAA28
AB1  GXB_RX_R1N  pas
AB2  GXB_RX_R1P  pas
AB3  GND  pwr
AB4  GND  pwr
AB5  NC10  pas
AB6  NC3  pas
AB7  IOAB7
AB9  IOAB9
AB10  IOAB10
AB11  IOAB11
AB12  IOAB12
AB14  VCC  pwr
AB15  IOAB15
AB17  IOAB17
AB18  IOAB18
AB20  IOAB20
AB21  IOAB21
AB22  VCC  pwr
AB23  IOAB23
AB24  IOAB24
AB25  IOAB25
AB26  VCC  pwr
AB27  IOAB27
AB28  IOAB28
AC1  GND  pwr
AC2  GND  pwr
AC3  GXB_TX_R0N  pas
AC4  GXB_TX_R0P  pas
AC5  NC9  pas
AC6  IOAC6
AC7  VCC  pwr
AC8  IOAC8
AC9  VCC  pwr
AC10  IOAC10
AC11  VCC  pwr
AC12  IOAC12
AC13  VCC  pwr
AC14  VCC  pwr
AC15  VCC  pwr
AC16  IOAC16
AC17  VCC  pwr
AC18  IOAC18
AC19  IOAC19
AC20  VCC  pwr
AC21  IOAC21
AC22  IOAC22
AC23  NSTATUS  pas
AC24  CONF_DONE  pas
AC25  IOAC25
AC26  IOAC26
AC27  IOAC27
AC28  IOAC28
AD1  GXB_RX_R0N  pas
AD2  GXB_RX_R0P  pas
AD3  GND  pwr
AD4  GND  pwr
AD5  NC8  pas
AD6  GND  pwr
AD7  IOAD7
AD8  IOAD8
AD9  GND  pwr
AD10  IOAD10
AD11  IOAD11
AD12  GND  pwr
AD13  IOAD13
AD14  VCC  pwr
AD15  GND  pwr
AD16  IOAD16
AD17  IOAD17
AD18  GND  pwr
AD19  IOAD19
AD20  IOAD20
AD21  GND  pwr
AD22  IOAD22
AD23  IOAD23
AD24  GND  pwr
AD25  VCC  pwr
AD26  IOAD26
AD27  GND  pwr
AD28  IOAD28
AE1  GND  pwr
AE2  GND  pwr
AE3  NC5  pas
AE4  NC6  pas
AE5  NC7  pas
AE6  IOAE6
AE7  IOAE7
AE8  IOAE8
AE9  IOAE9
AE10  IOAE10
AE11  IOAE11
AE12  IOAE12
AE13  IOAE13
AE14  IOAE14
AE15  IOAE15
AE16  IOAE16
AE17  IOAE17
AE18  IOAE18
AE19  IOAE19
AE20  IOAE20
AE21  IOAE21
AE22  IOAE22
AE23  IOAE23
AE24  IOAE24
AE25  IOAE25
AE26  NC2  pas
AE27  IOAE27
AE28  IOAE28
AF1  RREF_R0  pas
AF2  GND  pwr
AF3  IOAF3
AF4  IOAF4
AF5  VCC  pwr
AF6  IOAF6
AF7  IOAF7
AF8  VCC  pwr
AF9  IOAF9
AF10  IOAF10
AF11  IOAF11
AF12  IOAF12
AF13  VCC  pwr
AF14  IOAF14
AF15  IOAF15
AF16  IOAF16
AF17  VCC  pwr
AF18  IOAF18
AF19  IOAF19
AF20  VCC  pwr
AF21  IOAF21
AF22  IOAF22
AF23  VCC  pwr
AF24  IOAF24
AF25  IOAF25
AF26  IOAF26
AF27  IOAF27
AF28  IOAF28
AG1  GND  pwr
AG2  GND  pwr
AG3  GND  pwr
AG4  IOAG4
AG5  IOAG5
AG6  GND  pwr
AG7  IOAG7
AG8  IOAG8
AG9  GND  pwr
AG10  IOAG10
AG11  IOAG11
AG12  GND  pwr
AG13  IOAG13
AG14  IOAG14
AG15  GND  pwr
AG16  IOAG16
AG17  IOAG17
AG18  GND  pwr
AG19  IOAG19
AG20  IOAG20
AG21  GND  pwr
AG22  IOAG22
AG23  IOAG23
AG24  GND  pwr
AG25  IOAG25
AG26  IOAG26
AG27  GND  pwr
AG28  IOAG28
AH2  IOAH2
AH3  IOAH3
AH4  IOAH4
AH5  IOAH5
AH6  IOAH6
AH7  IOAH7
AH8  IOAH8
AH9  IOAH9
AH10  IOAH10
AH11  IOAH11
AH12  IOAH12
AH13  IOAH13
AH14  IOAH14
AH15  IOAH15
AH16  IOAH16
AH17  IOAH17
AH18  IOAH18
AH19  IOAH19
AH20  IOAH20
AH21  IOAH21
AH22  IOAH22
AH23  IOAH23
AH24  IOAH24
AH25  IOAH25
AH26  IOAH26
AH27  IOAH27
B1  NC41  pas
B2  GND  pwr
B3  IOB3
B4  IOB4
B5  GND  pwr
B6  IOB6
B7  IOB7
B8  GND  pwr
B9  IOB9
B10  IOB10
B11  GND  pwr
B12  IOB12
B13  IOB13
B14  GND  pwr
B15  IOB15
B16  IOB16
B17  GND  pwr
B18  IOB18
B19  IOB19
B20  GND  pwr
B21  IOB21
B22  IOB22
B23  GND  pwr
B24  IOB24
B25  IOB25
B26  GND  pwr
B27  IOB27
B28  IOB28
C1  GND  pwr
C2  GND  pwr
C3  NC40  pas
C4  IOC4
C5  IOC5
C6  VCC  pwr
C7  IOC7
C8  IOC8
C9  VCC  pwr
C10  IOC10
C11  IOC11
C12  VCC  pwr
C13  IOC13
C14  IOC14
C15  IOC15
C16  VCC  pwr
C17  IOC17
C18  IOC18
C19  IOC19
C20  IOC20
C21  IOC21
C22  IOC22
C23  VCC  pwr
C24  IOC24
C25  IOC25
C26  IOC26
C27  GND  pwr
C28  IOC28
D1  RREF_R1  pas
D2  GND  pwr
D3  GND  pwr
D4  GND  pwr
D5  IOD5
D6  IOD6
D7  IOD7
D8  IOD8
D9  IOD9
D10  IOD10
D11  IOD11
D12  IOD12
D13  IOD13
D14  IOD14
D15  IOD15
D16  IOD16
D17  IOD17
D18  IOD18
D19  IOD19
D20  IOD20
D21  IOD21
D22  IOD22
D23  IOD23
D24  IOD24
D25  TCK  in
D26  TRST  in
D27  IOD27
D28  IOD28
E1  GND  pwr
E2  GND  pwr
E3  GXB_TX_R7N  pas
E4  GXB_TX_R7P  pas
E5  GND  pwr
E6  IOE6
E7  IOE7
E8  GND  pwr
E9  IOE9
E10  IOE10
E11  GND  pwr
E12  IOE12
E13  IOE13
E14  GND  pwr
E15  VCC  pwr
E16  IOE16
E17  GND  pwr
E18  IOE18
E19  IOE19
E20  GND  pwr
E21  IOE21
E22  IOE22
E23  GND  pwr
E24  VCC  pwr
E25  TDO  out
E26  VCC  pwr
E27  IOE27
E28  IOE28
F1  GXB_RX_R7N  pas
F2  GXB_RX_R7P  pas
F3  GND  pwr
F4  GND  pwr
F5  NC39  pas
F6  IOF6
F7  IOF7
F8  IOF8
F9  VCC  pwr
F10  IOF10
F11  IOF11
F12  VCC  pwr
F13  IOF13
F14  VCC  pwr
F15  VCC  pwr
F16  VCC  pwr
F17  IOF17
F18  IOF18
F19  IOF19
F20  IOF20
F21  IOF21
F22  VCC  pwr
F23  NC1  pas
F24  GND  pwr
F25  IOF25
F26  IOF26
F27  GND  pwr
F28  IOF28
G1  GND  pwr
G2  GND  pwr
G3  GXB_TX_R6N  pas
G4  GXB_TX_R6P  pas
G5  NC38  pas
G6  TEMPDIODEP  pas
G7  VCC  pwr
G8  IOG8
G9  IOG9
G11  IOG11
G12  IOG12
G14  IOG14
G15  VCC  pwr
G17  IOG17
G18  VCC  pwr
G19  IOG19
G21  IOG21
G22  VCC  pwr
G23  TMS  in
G24  IOG24
G25  IOG25
G26  IOG26
G27  IOG27
G28  IOG28
H1  GXB_RX_R6N  pas
H2  GXB_RX_R6P  pas
H3  GND  pwr
H4  GND  pwr
H5  GND  pwr
H6  VCC  pwr
H7  TEMPDIODEN  pas
H8  GND  pwr
H9  IOH9
H10  IOH10
H11  GND  pwr
H12  IOH12
H13  IOH13
H14  GND  pwr
H15  IOH15
H16  IOH16
H17  GND  pwr
H18  IOH18
H19  IOH19
H20  GND  pwr
H21  IOH21
H22  IOH22
H23  IOH23
H24  IOH24
H25  IOH25
H26  VCC  pwr
H27  IOH27
H28  IOH28
J1  GND  pwr
J2  GND  pwr
J3  GXB_CMURX_R3N  pas
J4  GXB_CMURX_R3P  pas
J5  NC36  pas
J6  NC37  pas
J7  MSEL2  in
J8  NC4  pas
J9  MSEL1  in
J10  VCC  pwr
J11  IOJ11
J12  IOJ12
J13  IOJ13
J14  IOJ14
J15  IOJ15
J16  IOJ16
J17  IOJ17
J18  IOJ18
J19  VCC  pwr
J20  TDI  in
J21  GND  pwr
J23  VCC  pwr
J24  GND  pwr
J25  IOJ25
J26  IOJ26
J27  GND  pwr
J28  IOJ28
K1  GXB_CMURX_R2N  pas
K2  GXB_CMURX_R2P  pas
K3  GND  pwr
K4  GND  pwr
K5  NC30  pas
K6  NC31  pas
K7  NC32  pas
K8  NC33  pas
K9  MSEL0  in
K10  NC34  pas
K11  GND  pwr
K12  VCC  pwr
K13  GND  pwr
K14  VCC  pwr
K15  GND  pwr
K16  VCC  pwr
K17  GND  pwr
K18  VCC  pwr
K19  GND  pwr
K20  NC35  pas
K21  IOK21
K22  IOK22
K23  IOK23
K24  IOK24
K25  IOK25
K26  IOK26
K27  IOK27
K28  IOK28
L1  GND  pwr
L2  GND  pwr
L3  GXB_TX_R5N  pas
L4  GXB_TX_R5P  pas
L5  GND  pwr
L6  VCC  pwr
L7  NC27  pas
L8  GND  pwr
L9  NC28  pas
L10  NC29  pas
L11  VCC  pwr
L12  GND  pwr
L13  VCC  pwr
L14  GND  pwr
L15  VCC  pwr
L16  GND  pwr
L17  VCC  pwr
L18  GND  pwr
L19  VCC  pwr
L20  IOL20
L21  IOL21
L22  IOL22
L23  IOL23
L24  IOL24
L25  IOL25
L26  IOL26
L27  IOL27
L28  IOL28
M1  GXB_RX_R5N  pas
M2  GXB_RX_R5P  pas
M3  GND  pwr
M4  GND  pwr
M5  VCC  pwr
M6  GND  pwr
M7  VCC  pwr
M8  VCC  pwr
M9  NC24  pas
M10  NC25  pas
M11  GND  pwr
M12  VCC  pwr
M13  GND  pwr
M14  VCC  pwr
M15  GND  pwr
M16  VCC  pwr
M17  GND  pwr
M18  VCC  pwr
M19  GND  pwr
M20  NC26  pas
M21  GND  pwr
M23  IOM23
M24  GND  pwr
M25  IOM25
M26  IOM26
M27  GND  pwr
M28  IOM28
N1  GND  pwr
N2  GND  pwr
N3  GXB_TX_R4N  pas
N4  GXB_TX_R4P  pas
N5  GND  pwr
N6  VCC  pwr
N7  GND  pwr
N8  VCC  pwr
N9  VCC  pwr
N10  NC23  pas
N11  VCC  pwr
N12  GND  pwr
N13  VCC  pwr
N14  GND  pwr
N15  VCC  pwr
N16  GND  pwr
N17  VCC  pwr
N18  GND  pwr
N19  VCC  pwr
N20  ION20
N21  ION21
N22  ION22
N23  ION23
N24  ION24
N25  ION25
N26  VCC  pwr
N27  ION27
N28  ION28
P1  GXB_RX_R4N  pas
P2  GXB_RX_R4P  pas
P3  GND  pwr
P4  GND  pwr
P5  VCC  pwr
P6  GND  pwr
P7  VCC  pwr
P8  GND  pwr
P9  VCC  pwr
P10  VCC  pwr
P11  GND  pwr
P12  VCC  pwr
P13  GND  pwr
P14  VCC  pwr
P15  GND  pwr
P16  VCC  pwr
P17  GND  pwr
P18  VCC  pwr
P19  GND  pwr
P20  IOP20
P21  IOP21
P22  VCC  pwr
P23  VCC  pwr
P24  VCC  pwr
P25  IOP25
P26  IOP26
P27  CLK1P  pas
P28  CLK1N  pas
R1  GND  pwr
R2  GND  pwr
R3  GXB_TX_R3N  pas
R4  GXB_TX_R3P  pas
R5  GND  pwr
R6  VCC  pwr
R7  GND  pwr
R8  VCC  pwr
R9  VCC  pwr
R10  VCC  pwr
R11  VCC  pwr
R12  GND  pwr
R13  VCC  pwr
R14  DNU  pas
R15  VCC  pwr
R16  GND  pwr
R17  VCC  pwr
R18  GND  pwr
R19  VCC  pwr
R20  IOR20
R21  GND  pwr
R22  VCC  pwr
R23  VCC  pwr
R24  GND  pwr
R25  IOR25
R26  IOR26
R27  GND  pwr
R28  CLK3N  pas
T1  GXB_RX_R3N  pas
T2  GXB_RX_R3P  pas
T3  GND  pwr
T4  GND  pwr
T5  VCC  pwr
T6  GND  pwr
T7  VCC  pwr
T8  GND  pwr
T9  NC21  pas
T10  NC22  pas
T11  GND  pwr
T12  VCC  pwr
T13  GND  pwr
T14  VCC  pwr
T15  GND  pwr
T16  VCC  pwr
T17  GND  pwr
T18  VCC  pwr
T19  GND  pwr
T20  IOT20
T21  IOT21
T22  IOT22
T23  IOT23
T24  VCC  pwr
T25  IOT25
T26  VCC  pwr
T27  IOT27
T28  CLK3P  pas
U1  GND  pwr
U2  GND  pwr
U3  GXB_TX_R2N  pas
U4  GXB_TX_R2P  pas
U5  GND  pwr
U6  VCC  pwr
U7  VCC  pwr
U8  VCC  pwr
U9  NC18  pas
U10  NC19  pas
U11  VCC  pwr
U12  GND  pwr
U13  VCC  pwr
U14  GND  pwr
U15  VCC  pwr
U16  GND  pwr
U17  VCC  pwr
U18  GND  pwr
U19  VCC  pwr
U20  NC20  pas
U21  IOU21
U23  IOU23
U24  IOU24
U25  IOU25
U26  IOU26
U27  IOU27
U28  IOU28
V1  GXB_RX_R2N  pas
V2  GXB_RX_R2P  pas
V3  GND  pwr
V4  GND  pwr
V5  VCC  pwr
V6  GND  pwr
V7  NC15  pas
V8  NC16  pas
V9  GND  pwr
V10  NC17  pas
V11  GND  pwr
V12  VCC  pwr
V13  GND  pwr
V14  VCC  pwr
V15  GND  pwr
V16  VCC  pwr
V17  GND  pwr
V18  VCC  pwr
V19  GND  pwr
V20  IOV20
V21  GND  pwr
V22  IOV22
V23  IOV23
V24  GND  pwr
V25  IOV25
V26  IOV26
V27  GND  pwr
V28  IOV28
W1  GND  pwr
W2  GND  pwr
W3  GXB_CMURX_R1N  pas
W4  GXB_CMURX_R1P  pas
W5  NC13  pas
W6  NCEO  pas
W7  NCSO  pas
W8  GND  pwr
W9  VCC  pwr
W10  NC14  pas
W11  VCC  pwr
W12  GND  pwr
W13  VCC  pwr
W14  GND  pwr
W15  VCC  pwr
W16  GND  pwr
W17  VCC  pwr
W18  GND  pwr
W19  GND  pwr
W20  PORSEL  pas
W21  IOW21
W22  IOW22
W23  IOW23
W24  IOW24
W25  IOW25
W26  IOW26
W27  IOW27
W28  IOW28
Y1  GXB_CMURX_R0N  pas
Y2  GXB_CMURX_R0P  pas
Y3  GND  pwr
Y4  GND  pwr
Y5  NC12  pas
Y6  DCLK  pas
Y7  ASDO  pas
Y8  NIO_PULLUP  pas
Y9  IOY9
Y10  IOY10
Y11  IOY11
Y12  IOY12
Y13  IOY13
Y14  IOY14
Y15  IOY15
Y16  IOY16
Y17  IOY17
Y18  IOY18
Y19  VCC  pwr
Y20  VCC  pwr
Y21  NCE  pas
Y23  IOY23
Y24  IOY24
Y25  IOY25
Y26  IOY26
Y27  IOY27
Y28  IOY28

## Footprint FBGA780 (pad centres in mm)
780-Pin Hybrid FineLine Ball-Grid Array (HBGA) ? Flip Chip Auto generated by make-symbol-device-package-bsdl.ulp Rev. 29 Source: EP4SE230F29.bsd http://www.altera.com .. dspkg.pdf
smd 0.7 x 0.7: A2 -12.5,13.5; A3 -11.5,13.5; A4 -10.5,13.5; A5 -9.5,13.5; A6 -8.5,13.5; A7 -7.5,13.5; A8 -6.5,13.5; A9 -5.5,13.5; A10 -4.5,13.5; A11 -3.5,13.5; A12 -2.5,13.5; A13 -1.5,13.5; A14 -0.5,13.5; A15 0.5,13.5; A16 1.5,13.5; A17 2.5,13.5; A18 3.5,13.5; A19 4.5,13.5; A20 5.5,13.5; A21 6.5,13.5; A22 7.5,13.5; A23 8.5,13.5; A24 9.5,13.5; A25 10.5,13.5; A26 11.5,13.5; A27 12.5,13.5; AA1 -13.5,-6.5; AA2 -12.5,-6.5; AA3 -11.5,-6.5; AA4 -10.5,-6.5; AA5 -9.5,-6.5; AA6 -8.5,-6.5; AA7 -7.5,-6.5; AA8 -6.5,-6.5; AA9 -5.5,-6.5; AA10 -4.5,-6.5; AA11 -3.5,-6.5; AA12 -2.5,-6.5; AA13 -1.5,-6.5; AA14 -0.5,-6.5; AA15 0.5,-6.5; AA16 1.5,-6.5; AA17 2.5,-6.5; AA18 3.5,-6.5; AA19 4.5,-6.5; AA20 5.5,-6.5; AA21 6.5,-6.5; AA22 7.5,-6.5; AA23 8.5,-6.5; AA24 9.5,-6.5; AA25 10.5,-6.5; AA26 11.5,-6.5; AA27 12.5,-6.5; AA28 13.5,-6.5; AB1 -13.5,-7.5; AB2 -12.5,-7.5; AB3 -11.5,-7.5; AB4 -10.5,-7.5; AB5 -9.5,-7.5; AB6 -8.5,-7.5; AB7 -7.5,-7.5; AB8 -6.5,-7.5; AB9 -5.5,-7.5; AB10 -4.5,-7.5; AB11 -3.5,-7.5; AB12 -2.5,-7.5; AB13 -1.5,-7.5; AB14 -0.5,-7.5; AB15 0.5,-7.5; AB16 1.5,-7.5; AB17 2.5,-7.5; AB18 3.5,-7.5; AB19 4.5,-7.5; AB20 5.5,-7.5; AB21 6.5,-7.5; AB22 7.5,-7.5; AB23 8.5,-7.5; AB24 9.5,-7.5; AB25 10.5,-7.5; AB26 11.5,-7.5; AB27 12.5,-7.5; AB28 13.5,-7.5; AC1 -13.5,-8.5; AC2 -12.5,-8.5; AC3 -11.5,-8.5; AC4 -10.5,-8.5; AC5 -9.5,-8.5; AC6 -8.5,-8.5; AC7 -7.5,-8.5; AC8 -6.5,-8.5; AC9 -5.5,-8.5; AC10 -4.5,-8.5; AC11 -3.5,-8.5; AC12 -2.5,-8.5; AC13 -1.5,-8.5; AC14 -0.5,-8.5; AC15 0.5,-8.5; AC16 1.5,-8.5; AC17 2.5,-8.5; AC18 3.5,-8.5; AC19 4.5,-8.5; AC20 5.5,-8.5; AC21 6.5,-8.5; AC22 7.5,-8.5; AC23 8.5,-8.5; AC24 9.5,-8.5; AC25 10.5,-8.5; AC26 11.5,-8.5; AC27 12.5,-8.5; AC28 13.5,-8.5; AD1 -13.5,-9.5; AD2 -12.5,-9.5; AD3 -11.5,-9.5; AD4 -10.5,-9.5; AD5 -9.5,-9.5; AD6 -8.5,-9.5; AD7 -7.5,-9.5; AD8 -6.5,-9.5; AD9 -5.5,-9.5; AD10 -4.5,-9.5; AD11 -3.5,-9.5; AD12 -2.5,-9.5; AD13 -1.5,-9.5; AD14 -0.5,-9.5; AD15 0.5,-9.5; AD16 1.5,-9.5; AD17 2.5,-9.5; AD18 3.5,-9.5; AD19 4.5,-9.5; AD20 5.5,-9.5; AD21 6.5,-9.5; AD22 7.5,-9.5; AD23 8.5,-9.5; AD24 9.5,-9.5; AD25 10.5,-9.5; AD26 11.5,-9.5; AD27 12.5,-9.5; AD28 13.5,-9.5; AE1 -13.5,-10.5; AE2 -12.5,-10.5; AE3 -11.5,-10.5; AE4 -10.5,-10.5; AE5 -9.5,-10.5; AE6 -8.5,-10.5; AE7 -7.5,-10.5; AE8 -6.5,-10.5; AE9 -5.5,-10.5; AE10 -4.5,-10.5; AE11 -3.5,-10.5; AE12 -2.5,-10.5; AE13 -1.5,-10.5; AE14 -0.5,-10.5; AE15 0.5,-10.5; AE16 1.5,-10.5; AE17 2.5,-10.5; AE18 3.5,-10.5; AE19 4.5,-10.5; AE20 5.5,-10.5; AE21 6.5,-10.5; AE22 7.5,-10.5; AE23 8.5,-10.5; AE24 9.5,-10.5; AE25 10.5,-10.5; AE26 11.5,-10.5; AE27 12.5,-10.5; AE28 13.5,-10.5; AF1 -13.5,-11.5; AF2 -12.5,-11.5; AF3 -11.5,-11.5; AF4 -10.5,-11.5; AF5 -9.5,-11.5; AF6 -8.5,-11.5; AF7 -7.5,-11.5; AF8 -6.5,-11.5; AF9 -5.5,-11.5; AF10 -4.5,-11.5; AF11 -3.5,-11.5; AF12 -2.5,-11.5; AF13 -1.5,-11.5; AF14 -0.5,-11.5; AF15 0.5,-11.5; AF16 1.5,-11.5; AF17 2.5,-11.5; AF18 3.5,-11.5; AF19 4.5,-11.5; AF20 5.5,-11.5; AF21 6.5,-11.5; AF22 7.5,-11.5; AF23 8.5,-11.5; AF24 9.5,-11.5; AF25 10.5,-11.5; AF26 11.5,-11.5; AF27 12.5,-11.5; AF28 13.5,-11.5; AG1 -13.5,-12.5; AG2 -12.5,-12.5; AG3 -11.5,-12.5; AG4 -10.5,-12.5; AG5 -9.5,-12.5; AG6 -8.5,-12.5; AG7 -7.5,-12.5; AG8 -6.5,-12.5; AG9 -5.5,-12.5; AG10 -4.5,-12.5; AG11 -3.5,-12.5; AG12 -2.5,-12.5; AG13 -1.5,-12.5; AG14 -0.5,-12.5; AG15 0.5,-12.5; AG16 1.5,-12.5; AG17 2.5,-12.5; AG18 3.5,-12.5; AG19 4.5,-12.5; AG20 5.5,-12.5; AG21 6.5,-12.5; AG22 7.5,-12.5; AG23 8.5,-12.5; AG24 9.5,-12.5; AG25 10.5,-12.5; AG26 11.5,-12.5; AG27 12.5,-12.5; AG28 13.5,-12.5; AH2 -12.5,-13.5; AH3 -11.5,-13.5; AH4 -10.5,-13.5; AH5 -9.5,-13.5; AH6 -8.5,-13.5; AH7 -7.5,-13.5; AH8 -6.5,-13.5; AH9 -5.5,-13.5; AH10 -4.5,-13.5; AH11 -3.5,-13.5; AH12 -2.5,-13.5; AH13 -1.5,-13.5; AH14 -0.5,-13.5; AH15 0.5,-13.5; AH16 1.5,-13.5; AH17 2.5,-13.5; AH18 3.5,-13.5; AH19 4.5,-13.5; AH20 5.5,-13.5; AH21 6.5,-13.5; AH22 7.5,-13.5; AH23 8.5,-13.5; AH24 9.5,-13.5; AH25 10.5,-13.5; AH26 11.5,-13.5; AH27 12.5,-13.5; B1 -13.5,12.5; B2 -12.5,12.5; B3 -11.5,12.5; B4 -10.5,12.5; B5 -9.5,12.5; B6 -8.5,12.5; B7 -7.5,12.5; B8 -6.5,12.5; B9 -5.5,12.5; B10 -4.5,12.5; B11 -3.5,12.5; B12 -2.5,12.5; B13 -1.5,12.5; B14 -0.5,12.5; B15 0.5,12.5; B16 1.5,12.5; B17 2.5,12.5; B18 3.5,12.5; B19 4.5,12.5; B20 5.5,12.5; B21 6.5,12.5; B22 7.5,12.5; B23 8.5,12.5; B24 9.5,12.5; B25 10.5,12.5; B26 11.5,12.5; B27 12.5,12.5; B28 13.5,12.5; C1 -13.5,11.5; C2 -12.5,11.5; C3 -11.5,11.5; C4 -10.5,11.5; C5 -9.5,11.5; C6 -8.5,11.5; C7 -7.5,11.5; C8 -6.5,11.5; C9 -5.5,11.5; C10 -4.5,11.5; C11 -3.5,11.5; C12 -2.5,11.5; C13 -1.5,11.5; C14 -0.5,11.5; C15 0.5,11.5; C16 1.5,11.5; C17 2.5,11.5; C18 3.5,11.5; C19 4.5,11.5; C20 5.5,11.5; C21 6.5,11.5; C22 7.5,11.5; C23 8.5,11.5; C24 9.5,11.5; C25 10.5,11.5; C26 11.5,11.5; C27 12.5,11.5; C28 13.5,11.5; D1 -13.5,10.5; D2 -12.5,10.5; D3 -11.5,10.5; D4 -10.5,10.5; D5 -9.5,10.5; D6 -8.5,10.5; D7 -7.5,10.5; D8 -6.5,10.5; D9 -5.5,10.5; D10 -4.5,10.5; D11 -3.5,10.5; D12 -2.5,10.5; D13 -1.5,10.5; D14 -0.5,10.5; D15 0.5,10.5; D16 1.5,10.5; D17 2.5,10.5; D18 3.5,10.5; D19 4.5,10.5; D20 5.5,10.5; D21 6.5,10.5; D22 7.5,10.5; D23 8.5,10.5; D24 9.5,10.5; D25 10.5,10.5; D26 11.5,10.5; D27 12.5,10.5; D28 13.5,10.5; E1 -13.5,9.5; E2 -12.5,9.5; E3 -11.5,9.5; E4 -10.5,9.5; E5 -9.5,9.5; E6 -8.5,9.5; E7 -7.5,9.5; E8 -6.5,9.5; E9 -5.5,9.5; E10 -4.5,9.5; E11 -3.5,9.5; E12 -2.5,9.5; E13 -1.5,9.5; E14 -0.5,9.5; E15 0.5,9.5; E16 1.5,9.5; E17 2.5,9.5; E18 3.5,9.5; E19 4.5,9.5; E20 5.5,9.5; E21 6.5,9.5; E22 7.5,9.5; E23 8.5,9.5; E24 9.5,9.5; E25 10.5,9.5; E26 11.5,9.5; E27 12.5,9.5; E28 13.5,9.5; F1 -13.5,8.5; F2 -12.5,8.5; F3 -11.5,8.5; F4 -10.5,8.5; F5 -9.5,8.5; F6 -8.5,8.5; F7 -7.5,8.5; F8 -6.5,8.5; F9 -5.5,8.5; F10 -4.5,8.5; F11 -3.5,8.5; F12 -2.5,8.5; F13 -1.5,8.5; F14 -0.5,8.5; F15 0.5,8.5; F16 1.5,8.5; F17 2.5,8.5; F18 3.5,8.5; F19 4.5,8.5; F20 5.5,8.5; F21 6.5,8.5; F22 7.5,8.5; F23 8.5,8.5; F24 9.5,8.5; F25 10.5,8.5; F26 11.5,8.5; F27 12.5,8.5; F28 13.5,8.5; G1 -13.5,7.5; G2 -12.5,7.5; G3 -11.5,7.5; G4 -10.5,7.5; G5 -9.5,7.5; G6 -8.5,7.5; G7 -7.5,7.5; G8 -6.5,7.5; G9 -5.5,7.5; G10 -4.5,7.5; G11 -3.5,7.5; G12 -2.5,7.5; G13 -1.5,7.5; G14 -0.5,7.5; G15 0.5,7.5; G16 1.5,7.5; G17 2.5,7.5; G18 3.5,7.5; G19 4.5,7.5; G20 5.5,7.5; G21 6.5,7.5; G22 7.5,7.5; G23 8.5,7.5; G24 9.5,7.5; G25 10.5,7.5; G26 11.5,7.5; G27 12.5,7.5; G28 13.5,7.5; H1 -13.5,6.5; H2 -12.5,6.5; H3 -11.5,6.5; H4 -10.5,6.5; H5 -9.5,6.5; H6 -8.5,6.5; H7 -7.5,6.5; H8 -6.5,6.5; H9 -5.5,6.5; H10 -4.5,6.5; H11 -3.5,6.5; H12 -2.5,6.5; H13 -1.5,6.5; H14 -0.5,6.5; H15 0.5,6.5; H16 1.5,6.5; H17 2.5,6.5; H18 3.5,6.5; H19 4.5,6.5; H20 5.5,6.5; H21 6.5,6.5; H22 7.5,6.5; H23 8.5,6.5; H24 9.5,6.5; H25 10.5,6.5; H26 11.5,6.5; H27 12.5,6.5; H28 13.5,6.5; J1 -13.5,5.5; J2 -12.5,5.5; J3 -11.5,5.5; J4 -10.5,5.5; J5 -9.5,5.5; J6 -8.5,5.5; J7 -7.5,5.5; J8 -6.5,5.5; J9 -5.5,5.5; J10 -4.5,5.5; J11 -3.5,5.5; J12 -2.5,5.5; J13 -1.5,5.5; J14 -0.5,5.5; J15 0.5,5.5; J16 1.5,5.5; J17 2.5,5.5; J18 3.5,5.5; J19 4.5,5.5; J20 5.5,5.5; J21 6.5,5.5; J22 7.5,5.5; J23 8.5,5.5; J24 9.5,5.5; J25 10.5,5.5; J26 11.5,5.5; J27 12.5,5.5; J28 13.5,5.5; K1 -13.5,4.5; K2 -12.5,4.5; K3 -11.5,4.5; K4 -10.5,4.5; K5 -9.5,4.5; K6 -8.5,4.5; K7 -7.5,4.5; K8 -6.5,4.5; K9 -5.5,4.5; K10 -4.5,4.5; K11 -3.5,4.5; K12 -2.5,4.5; K13 -1.5,4.5; K14 -0.5,4.5; K15 0.5,4.5; K16 1.5,4.5; K17 2.5,4.5; K18 3.5,4.5; K19 4.5,4.5; K20 5.5,4.5; K21 6.5,4.5; K22 7.5,4.5; K23 8.5,4.5; K24 9.5,4.5; K25 10.5,4.5; K26 11.5,4.5; K27 12.5,4.5; K28 13.5,4.5; L1 -13.5,3.5; L2 -12.5,3.5; L3 -11.5,3.5; L4 -10.5,3.5; L5 -9.5,3.5; L6 -8.5,3.5; L7 -7.5,3.5; L8 -6.5,3.5; L9 -5.5,3.5; L10 -4.5,3.5; L11 -3.5,3.5; L12 -2.5,3.5; L13 -1.5,3.5; L14 -0.5,3.5; L15 0.5,3.5; L16 1.5,3.5; L17 2.5,3.5; L18 3.5,3.5; L19 4.5,3.5; L20 5.5,3.5; L21 6.5,3.5; L22 7.5,3.5; L23 8.5,3.5; L24 9.5,3.5; L25 10.5,3.5; L26 11.5,3.5; L27 12.5,3.5; L28 13.5,3.5; M1 -13.5,2.5; M2 -12.5,2.5; M3 -11.5,2.5; M4 -10.5,2.5; M5 -9.5,2.5; M6 -8.5,2.5; M7 -7.5,2.5; M8 -6.5,2.5; M9 -5.5,2.5; M10 -4.5,2.5; M11 -3.5,2.5; M12 -2.5,2.5; M13 -1.5,2.5; M14 -0.5,2.5; M15 0.5,2.5; M16 1.5,2.5; M17 2.5,2.5; M18 3.5,2.5; M19 4.5,2.5; M20 5.5,2.5; M21 6.5,2.5; M22 7.5,2.5; M23 8.5,2.5; M24 9.5,2.5; M25 10.5,2.5; M26 11.5,2.5; M27 12.5,2.5; M28 13.5,2.5; N1 -13.5,1.5; N2 -12.5,1.5; N3 -11.5,1.5; N4 -10.5,1.5; N5 -9.5,1.5; N6 -8.5,1.5; N7 -7.5,1.5; N8 -6.5,1.5; N9 -5.5,1.5; N10 -4.5,1.5; N11 -3.5,1.5; N12 -2.5,1.5; N13 -1.5,1.5; N14 -0.5,1.5; N15 0.5,1.5; N16 1.5,1.5; N17 2.5,1.5; N18 3.5,1.5; N19 4.5,1.5; N20 5.5,1.5; N21 6.5,1.5; N22 7.5,1.5; N23 8.5,1.5; N24 9.5,1.5; N25 10.5,1.5; N26 11.5,1.5; N27 12.5,1.5; N28 13.5,1.5; P1 -13.5,0.5; P2 -12.5,0.5; P3 -11.5,0.5; P4 -10.5,0.5; P5 -9.5,0.5; P6 -8.5,0.5; P7 -7.5,0.5; P8 -6.5,0.5; P9 -5.5,0.5; P10 -4.5,0.5; P11 -3.5,0.5; P12 -2.5,0.5; P13 -1.5,0.5; P14 -0.5,0.5; P15 0.5,0.5; P16 1.5,0.5; P17 2.5,0.5; P18 3.5,0.5; P19 4.5,0.5; P20 5.5,0.5; P21 6.5,0.5; P22 7.5,0.5; P23 8.5,0.5; P24 9.5,0.5; P25 10.5,0.5; P26 11.5,0.5; P27 12.5,0.5; P28 13.5,0.5; R1 -13.5,-0.5; R2 -12.5,-0.5; R3 -11.5,-0.5; R4 -10.5,-0.5; R5 -9.5,-0.5; R6 -8.5,-0.5; R7 -7.5,-0.5; R8 -6.5,-0.5; R9 -5.5,-0.5; R10 -4.5,-0.5; R11 -3.5,-0.5; R12 -2.5,-0.5; R13 -1.5,-0.5; R14 -0.5,-0.5; R15 0.5,-0.5; R16 1.5,-0.5; R17 2.5,-0.5; R18 3.5,-0.5; R19 4.5,-0.5; R20 5.5,-0.5; R21 6.5,-0.5; R22 7.5,-0.5; R23 8.5,-0.5; R24 9.5,-0.5; R25 10.5,-0.5; R26 11.5,-0.5; R27 12.5,-0.5; R28 13.5,-0.5; T1 -13.5,-1.5; T2 -12.5,-1.5; T3 -11.5,-1.5; T4 -10.5,-1.5; T5 -9.5,-1.5; T6 -8.5,-1.5; T7 -7.5,-1.5; T8 -6.5,-1.5; T9 -5.5,-1.5; T10 -4.5,-1.5; T11 -3.5,-1.5; T12 -2.5,-1.5; T13 -1.5,-1.5; T14 -0.5,-1.5; T15 0.5,-1.5; T16 1.5,-1.5; T17 2.5,-1.5; T18 3.5,-1.5; T19 4.5,-1.5; T20 5.5,-1.5; T21 6.5,-1.5; T22 7.5,-1.5; T23 8.5,-1.5; T24 9.5,-1.5; T25 10.5,-1.5; T26 11.5,-1.5; T27 12.5,-1.5; T28 13.5,-1.5; U1 -13.5,-2.5; U2 -12.5,-2.5; U3 -11.5,-2.5; U4 -10.5,-2.5; U5 -9.5,-2.5; U6 -8.5,-2.5; U7 -7.5,-2.5; U8 -6.5,-2.5; U9 -5.5,-2.5; U10 -4.5,-2.5; U11 -3.5,-2.5; U12 -2.5,-2.5; U13 -1.5,-2.5; U14 -0.5,-2.5; U15 0.5,-2.5; U16 1.5,-2.5; U17 2.5,-2.5; U18 3.5,-2.5; U19 4.5,-2.5; U20 5.5,-2.5; U21 6.5,-2.5; U22 7.5,-2.5; U23 8.5,-2.5; U24 9.5,-2.5; U25 10.5,-2.5; U26 11.5,-2.5; U27 12.5,-2.5; U28 13.5,-2.5; V1 -13.5,-3.5; V2 -12.5,-3.5; V3 -11.5,-3.5; V4 -10.5,-3.5; V5 -9.5,-3.5; V6 -8.5,-3.5; V7 -7.5,-3.5; V8 -6.5,-3.5; V9 -5.5,-3.5; V10 -4.5,-3.5; V11 -3.5,-3.5; V12 -2.5,-3.5; V13 -1.5,-3.5; V14 -0.5,-3.5; V15 0.5,-3.5; V16 1.5,-3.5; V17 2.5,-3.5; V18 3.5,-3.5; V19 4.5,-3.5; V20 5.5,-3.5; V21 6.5,-3.5; V22 7.5,-3.5; V23 8.5,-3.5; V24 9.5,-3.5; V25 10.5,-3.5; V26 11.5,-3.5; V27 12.5,-3.5; V28 13.5,-3.5; W1 -13.5,-4.5; W2 -12.5,-4.5; W3 -11.5,-4.5; W4 -10.5,-4.5; W5 -9.5,-4.5; W6 -8.5,-4.5; W7 -7.5,-4.5; W8 -6.5,-4.5; W9 -5.5,-4.5; W10 -4.5,-4.5; W11 -3.5,-4.5; W12 -2.5,-4.5; W13 -1.5,-4.5; W14 -0.5,-4.5; W15 0.5,-4.5; W16 1.5,-4.5; W17 2.5,-4.5; W18 3.5,-4.5; W19 4.5,-4.5; W20 5.5,-4.5; W21 6.5,-4.5; W22 7.5,-4.5; W23 8.5,-4.5; W24 9.5,-4.5; W25 10.5,-4.5; W26 11.5,-4.5; W27 12.5,-4.5; W28 13.5,-4.5; Y1 -13.5,-5.5; Y2 -12.5,-5.5; Y3 -11.5,-5.5; Y4 -10.5,-5.5; Y5 -9.5,-5.5; Y6 -8.5,-5.5; Y7 -7.5,-5.5; Y8 -6.5,-5.5; Y9 -5.5,-5.5; Y10 -4.5,-5.5; Y11 -3.5,-5.5; Y12 -2.5,-5.5; Y13 -1.5,-5.5; Y14 -0.5,-5.5; Y15 0.5,-5.5; Y16 1.5,-5.5; Y17 2.5,-5.5; Y18 3.5,-5.5; Y19 4.5,-5.5; Y20 5.5,-5.5; Y21 6.5,-5.5; Y22 7.5,-5.5; Y23 8.5,-5.5; Y24 9.5,-5.5; Y25 10.5,-5.5; Y26 11.5,-5.5; Y27 12.5,-5.5; Y28 13.5,-5.5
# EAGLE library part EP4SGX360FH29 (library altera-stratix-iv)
EP4SGX360FH29 edit this description Auto generated by make-symbol-device-package-bsdl.ulp Rev. 29 Source: EP4SGX360FH29.bsd

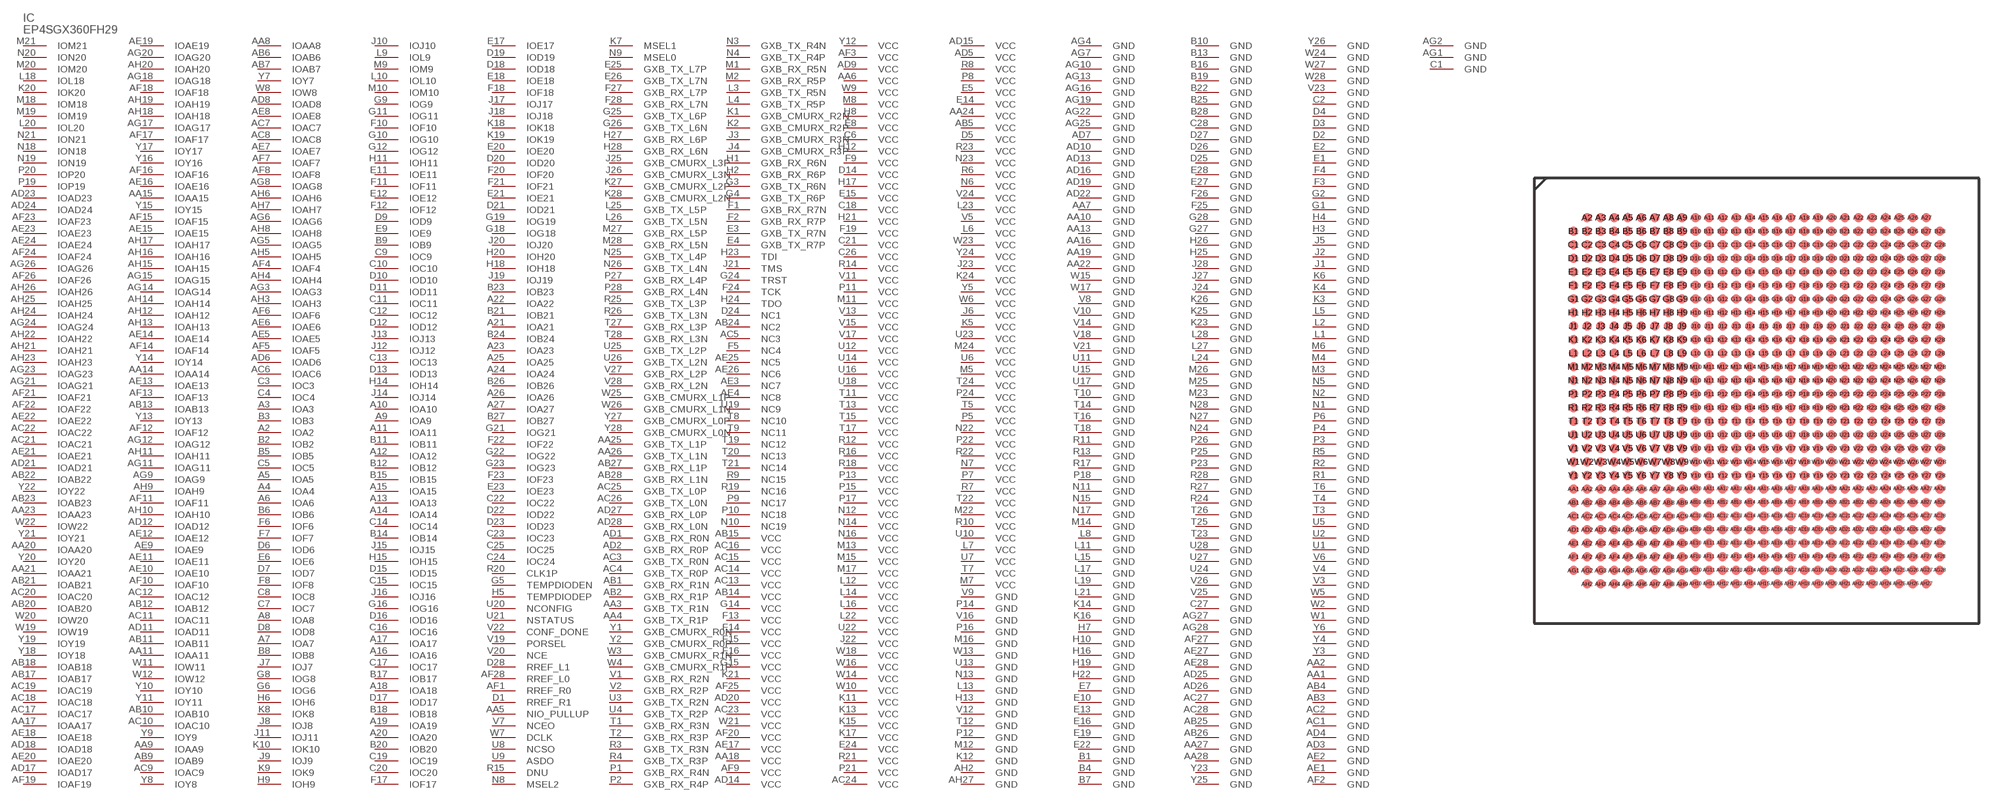
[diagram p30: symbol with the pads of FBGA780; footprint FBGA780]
Designator prefix IC

## EP4SGX360FH29 (MPN: EP4SGX360FH29C3N; OC_FARNELL: unknown; OC_NEWARK: 52R1955)  [FBGA780]
A2  IOA2
A3  IOA3
A4  IOA4
A5  IOA5
A6  IOA6
A7  IOA7
A8  IOA8
A9  IOA9
A10  IOA10
A11  IOA11
A12  IOA12
A13  IOA13
A14  IOA14
A15  IOA15
A16  IOA16
A17  IOA17
A18  IOA18
A19  IOA19
A20  IOA20
A21  IOA21
A22  IOA22
A23  IOA23
A24  IOA24
A25  IOA25
A26  IOA26
A27  IOA27
AA1  GND  pwr
AA2  GND  pwr
AA3  GXB_TX_R1N  pas
AA4  GXB_TX_R1P  pas
AA5  NIO_PULLUP  pas
AA6  VCC  pwr
AA7  GND  pwr
AA8  IOAA8
AA9  IOAA9
AA10  GND  pwr
AA11  IOAA11
AA13  GND  pwr
AA14  IOAA14
AA15  IOAA15
AA16  GND  pwr
AA17  IOAA17
AA18  VCC  pwr
AA19  GND  pwr
AA20  IOAA20
AA21  IOAA21
AA22  GND  pwr
AA23  IOAA23
AA24  VCC  pwr
AA25  GXB_TX_L1P  pas
AA26  GXB_TX_L1N  pas
AA27  GND  pwr
AA28  GND  pwr
AB1  GXB_RX_R1N  pas
AB2  GXB_RX_R1P  pas
AB3  GND  pwr
AB4  GND  pwr
AB5  VCC  pwr
AB6  IOAB6
AB7  IOAB7
AB9  IOAB9
AB10  IOAB10
AB11  IOAB11
AB12  IOAB12
AB13  IOAB13
AB14  VCC  pwr
AB15  VCC  pwr
AB17  IOAB17
AB18  IOAB18
AB20  IOAB20
AB21  IOAB21
AB22  IOAB22
AB23  IOAB23
AB24  NC2  pas
AB25  GND  pwr
AB26  GND  pwr
AB27  GXB_RX_L1P  pas
AB28  GXB_RX_L1N  pas
AC1  GND  pwr
AC2  GND  pwr
AC3  GXB_TX_R0N  pas
AC4  GXB_TX_R0P  pas
AC5  NC3  pas
AC6  IOAC6
AC7  IOAC7
AC8  IOAC8
AC9  IOAC9
AC10  IOAC10
AC11  IOAC11
AC12  IOAC12
AC13  VCC  pwr
AC14  VCC  pwr
AC15  VCC  pwr
AC16  VCC  pwr
AC17  IOAC17
AC18  IOAC18
AC19  IOAC19
AC20  IOAC20
AC21  IOAC21
AC22  IOAC22
AC23  VCC  pwr
AC24  VCC  pwr
AC25  GXB_TX_L0P  pas
AC26  GXB_TX_L0N  pas
AC27  GND  pwr
AC28  GND  pwr
AD1  GXB_RX_R0N  pas
AD2  GXB_RX_R0P  pas
AD3  GND  pwr
AD4  GND  pwr
AD5  VCC  pwr
AD6  IOAD6
AD7  GND  pwr
AD8  IOAD8
AD9  VCC  pwr
AD10  GND  pwr
AD11  IOAD11
AD12  IOAD12
AD13  GND  pwr
AD14  VCC  pwr
AD15  VCC  pwr
AD16  GND  pwr
AD17  IOAD17
AD18  IOAD18
AD19  GND  pwr
AD20  VCC  pwr
AD21  IOAD21
AD22  GND  pwr
AD23  IOAD23
AD24  IOAD24
AD25  GND  pwr
AD26  GND  pwr
AD27  GXB_RX_L0P  pas
AD28  GXB_RX_L0N  pas
AE1  GND  pwr
AE2  GND  pwr
AE3  NC7  pas
AE4  NC8  pas
AE5  IOAE5
AE6  IOAE6
AE7  IOAE7
AE8  IOAE8
AE9  IOAE9
AE10  IOAE10
AE11  IOAE11
AE12  IOAE12
AE13  IOAE13
AE14  IOAE14
AE15  IOAE15
AE16  IOAE16
AE17  VCC  pwr
AE18  IOAE18
AE19  IOAE19
AE20  IOAE20
AE21  IOAE21
AE22  IOAE22
AE23  IOAE23
AE24  IOAE24
AE25  NC5  pas
AE26  NC6  pas
AE27  GND  pwr
AE28  GND  pwr
AF1  RREF_R0  pas
AF2  GND  pwr
AF3  VCC  pwr
AF4  IOAF4
AF5  IOAF5
AF6  IOAF6
AF7  IOAF7
AF8  IOAF8
AF9  VCC  pwr
AF10  IOAF10
AF11  IOAF11
AF12  IOAF12
AF13  IOAF13
AF14  IOAF14
AF15  IOAF15
AF16  IOAF16
AF17  IOAF17
AF18  IOAF18
AF19  IOAF19
AF20  VCC  pwr
AF21  IOAF21
AF22  IOAF22
AF23  IOAF23
AF24  IOAF24
AF25  VCC  pwr
AF26  IOAF26
AF27  GND  pwr
AF28  RREF_L0  pas
AG1  GND  pwr
AG2  GND  pwr
AG3  IOAG3
AG4  GND  pwr
AG5  IOAG5
AG6  IOAG6
AG7  GND  pwr
AG8  IOAG8
AG9  IOAG9
AG10  GND  pwr
AG11  IOAG11
AG12  IOAG12
AG13  GND  pwr
AG14  IOAG14
AG15  IOAG15
AG16  GND  pwr
AG17  IOAG17
AG18  IOAG18
AG19  GND  pwr
AG20  IOAG20
AG21  IOAG21
AG22  GND  pwr
AG23  IOAG23
AG24  IOAG24
AG25  GND  pwr
AG26  IOAG26
AG27  GND  pwr
AG28  GND  pwr
AH2  GND  pwr
AH3  IOAH3
AH4  IOAH4
AH5  IOAH5
AH6  IOAH6
AH7  IOAH7
AH8  IOAH8
AH9  IOAH9
AH10  IOAH10
AH11  IOAH11
AH12  IOAH12
AH13  IOAH13
AH14  IOAH14
AH15  IOAH15
AH16  IOAH16
AH17  IOAH17
AH18  IOAH18
AH19  IOAH19
AH20  IOAH20
AH21  IOAH21
AH22  IOAH22
AH23  IOAH23
AH24  IOAH24
AH25  IOAH25
AH26  IOAH26
AH27  GND  pwr
B1  GND  pwr
B2  IOB2
B3  IOB3
B4  GND  pwr
B5  IOB5
B6  IOB6
B7  GND  pwr
B8  IOB8
B9  IOB9
B10  GND  pwr
B11  IOB11
B12  IOB12
B13  GND  pwr
B14  IOB14
B15  IOB15
B16  GND  pwr
B17  IOB17
B18  IOB18
B19  GND  pwr
B20  IOB20
B21  IOB21
B22  GND  pwr
B23  IOB23
B24  IOB24
B25  GND  pwr
B26  IOB26
B27  IOB27
B28  GND  pwr
C1  GND  pwr
C2  GND  pwr
C3  IOC3
C4  IOC4
C5  IOC5
C6  VCC  pwr
C7  IOC7
C8  IOC8
C9  IOC9
C10  IOC10
C11  IOC11
C12  IOC12
C13  IOC13
C14  IOC14
C15  IOC15
C16  IOC16
C17  IOC17
C18  VCC  pwr
C19  IOC19
C20  IOC20
C21  VCC  pwr
C22  IOC22
C23  IOC23
C24  IOC24
C25  IOC25
C26  VCC  pwr
C27  GND  pwr
C28  GND  pwr
D1  RREF_R1  pas
D2  GND  pwr
D3  GND  pwr
D4  GND  pwr
D5  VCC  pwr
D6  IOD6
D7  IOD7
D8  IOD8
D9  IOD9
D10  IOD10
D11  IOD11
D12  IOD12
D13  IOD13
D14  VCC  pwr
D15  IOD15
D16  IOD16
D17  IOD17
D18  IOD18
D19  IOD19
D20  IOD20
D21  IOD21
D22  IOD22
D23  IOD23
D24  NC1  pas
D25  GND  pwr
D26  GND  pwr
D27  GND  pwr
D28  RREF_L1  pas
E1  GND  pwr
E2  GND  pwr
E3  GXB_TX_R7N  pas
E4  GXB_TX_R7P  pas
E5  VCC  pwr
E6  IOE6
E7  GND  pwr
E8  VCC  pwr
E9  IOE9
E10  GND  pwr
E11  IOE11
E12  IOE12
E13  GND  pwr
E14  VCC  pwr
E15  VCC  pwr
E16  GND  pwr
E17  IOE17
E18  IOE18
E19  GND  pwr
E20  IOE20
E21  IOE21
E22  GND  pwr
E23  IOE23
E24  VCC  pwr
E25  GXB_TX_L7P  pas
E26  GXB_TX_L7N  pas
E27  GND  pwr
E28  GND  pwr
F1  GXB_RX_R7N  pas
F2  GXB_RX_R7P  pas
F3  GND  pwr
F4  GND  pwr
F5  NC4  pas
F6  IOF6
F7  IOF7
F8  IOF8
F9  VCC  pwr
F10  IOF10
F11  IOF11
F12  IOF12
F13  VCC  pwr
F14  VCC  pwr
F15  VCC  pwr
F16  VCC  pwr
F17  IOF17
F18  IOF18
F19  VCC  pwr
F20  IOF20
F21  IOF21
F22  IOF22
F23  IOF23
F24  TCK  in
F25  GND  pwr
F26  GND  pwr
F27  GXB_RX_L7P  pas
F28  GXB_RX_L7N  pas
G1  GND  pwr
G2  GND  pwr
G3  GXB_TX_R6N  pas
G4  GXB_TX_R6P  pas
G5  TEMPDIODEN  pas
G6  IOG6
G8  IOG8
G9  IOG9
G10  IOG10
G11  IOG11
G12  IOG12
G14  VCC  pwr
G15  VCC  pwr
G16  IOG16
G18  IOG18
G19  IOG19
G21  IOG21
G22  IOG22
G23  IOG23
G24  TRST  in
G25  GXB_TX_L6P  pas
G26  GXB_TX_L6N  pas
G27  GND  pwr
G28  GND  pwr
H1  GXB_RX_R6N  pas
H2  GXB_RX_R6P  pas
H3  GND  pwr
H4  GND  pwr
H5  TEMPDIODEP  pas
H6  IOH6
H7  GND  pwr
H8  VCC  pwr
H9  IOH9
H10  GND  pwr
H11  IOH11
H12  VCC  pwr
H13  GND  pwr
H14  IOH14
H15  IOH15
H16  GND  pwr
H17  VCC  pwr
H18  IOH18
H19  GND  pwr
H20  IOH20
H21  VCC  pwr
H22  GND  pwr
H23  TDI  in
H24  TDO  out
H25  GND  pwr
H26  GND  pwr
H27  GXB_RX_L6P  pas
H28  GXB_RX_L6N  pas
J1  GND  pwr
J2  GND  pwr
J3  GXB_CMURX_R3N  pas
J4  GXB_CMURX_R3P  pas
J5  GND  pwr
J6  VCC  pwr
J7  IOJ7
J8  IOJ8
J9  IOJ9
J10  IOJ10
J11  IOJ11
J12  IOJ12
J13  IOJ13
J14  IOJ14
J15  IOJ15
J16  IOJ16
J17  IOJ17
J18  IOJ18
J19  IOJ19
J20  IOJ20
J21  TMS  in
J22  VCC  pwr
J23  VCC  pwr
J24  GND  pwr
J25  GXB_CMURX_L3P  pas
J26  GXB_CMURX_L3N  pas
J27  GND  pwr
J28  GND  pwr
K1  GXB_CMURX_R2N  pas
K2  GXB_CMURX_R2P  pas
K3  GND  pwr
K4  GND  pwr
K5  VCC  pwr
K6  GND  pwr
K7  MSEL1  in
K8  IOK8
K9  IOK9
K10  IOK10
K11  VCC  pwr
K12  GND  pwr
K13  VCC  pwr
K14  GND  pwr
K15  VCC  pwr
K16  GND  pwr
K17  VCC  pwr
K18  IOK18
K19  IOK19
K20  IOK20
K21  VCC  pwr
K23  GND  pwr
K24  VCC  pwr
K25  GND  pwr
K26  GND  pwr
K27  GXB_CMURX_L2P  pas
K28  GXB_CMURX_L2N  pas
L1  GND  pwr
L2  GND  pwr
L3  GXB_TX_R5N  pas
L4  GXB_TX_R5P  pas
L5  GND  pwr
L6  VCC  pwr
L7  VCC  pwr
L8  GND  pwr
L9  IOL9
L10  IOL10
L11  GND  pwr
L12  VCC  pwr
L13  GND  pwr
L14  VCC  pwr
L15  GND  pwr
L16  VCC  pwr
L17  GND  pwr
L18  IOL18
L19  GND  pwr
L20  IOL20
L21  GND  pwr
L22  VCC  pwr
L23  VCC  pwr
L24  GND  pwr
L25  GXB_TX_L5P  pas
L26  GXB_TX_L5N  pas
L27  GND  pwr
L28  GND  pwr
M1  GXB_RX_R5N  pas
M2  GXB_RX_R5P  pas
M3  GND  pwr
M4  GND  pwr
M5  VCC  pwr
M6  GND  pwr
M7  VCC  pwr
M8  VCC  pwr
M9  IOM9
M10  IOM10
M11  VCC  pwr
M12  GND  pwr
M13  VCC  pwr
M14  GND  pwr
M15  VCC  pwr
M16  GND  pwr
M17  VCC  pwr
M18  IOM18
M19  IOM19
M20  IOM20
M21  IOM21
M22  VCC  pwr
M23  GND  pwr
M24  VCC  pwr
M25  GND  pwr
M26  GND  pwr
M27  GXB_RX_L5P  pas
M28  GXB_RX_L5N  pas
N1  GND  pwr
N2  GND  pwr
N3  GXB_TX_R4N  pas
N4  GXB_TX_R4P  pas
N5  GND  pwr
N6  VCC  pwr
N7  VCC  pwr
N8  MSEL2  in
N9  MSEL0  in
N10  NC19  pas
N11  GND  pwr
N12  VCC  pwr
N13  GND  pwr
N14  VCC  pwr
N15  GND  pwr
N16  VCC  pwr
N17  GND  pwr
N18  ION18
N19  ION19
N20  ION20
N21  ION21
N22  VCC  pwr
N23  VCC  pwr
N24  GND  pwr
N25  GXB_TX_L4P  pas
N26  GXB_TX_L4N  pas
N27  GND  pwr
N28  GND  pwr
P1  GXB_RX_R4N  pas
P2  GXB_RX_R4P  pas
P3  GND  pwr
P4  GND  pwr
P5  VCC  pwr
P6  GND  pwr
P7  VCC  pwr
P8  VCC  pwr
P9  NC17  pas
P10  NC18  pas
P11  VCC  pwr
P12  GND  pwr
P13  VCC  pwr
P14  GND  pwr
P15  VCC  pwr
P16  GND  pwr
P17  VCC  pwr
P18  GND  pwr
P19  IOP19
P20  IOP20
P21  VCC  pwr
P22  VCC  pwr
P23  GND  pwr
P24  VCC  pwr
P25  GND  pwr
P26  GND  pwr
P27  GXB_RX_L4P  pas
P28  GXB_RX_L4N  pas
R1  GND  pwr
R2  GND  pwr
R3  GXB_TX_R3N  pas
R4  GXB_TX_R3P  pas
R5  GND  pwr
R6  VCC  pwr
R7  VCC  pwr
R8  VCC  pwr
R9  NC15  pas
R10  VCC  pwr
R11  GND  pwr
R12  VCC  pwr
R13  GND  pwr
R14  VCC  pwr
R15  DNU  pas
R16  VCC  pwr
R17  GND  pwr
R18  VCC  pwr
R19  NC16  pas
R20  CLK1P  pas
R21  VCC  pwr
R22  VCC  pwr
R23  VCC  pwr
R24  GND  pwr
R25  GXB_TX_L3P  pas
R26  GXB_TX_L3N  pas
R27  GND  pwr
R28  GND  pwr
T1  GXB_RX_R3N  pas
T2  GXB_RX_R3P  pas
T3  GND  pwr
T4  GND  pwr
T5  VCC  pwr
T6  GND  pwr
T7  VCC  pwr
T8  NC10  pas
T9  NC11  pas
T10  GND  pwr
T11  VCC  pwr
T12  GND  pwr
T13  VCC  pwr
T14  GND  pwr
T15  VCC  pwr
T16  GND  pwr
T17  VCC  pwr
T18  GND  pwr
T19  NC12  pas
T20  NC13  pas
T21  NC14  pas
T22  VCC  pwr
T23  GND  pwr
T24  VCC  pwr
T25  GND  pwr
T26  GND  pwr
T27  GXB_RX_L3P  pas
T28  GXB_RX_L3N  pas
U1  GND  pwr
U2  GND  pwr
U3  GXB_TX_R2N  pas
U4  GXB_TX_R2P  pas
U5  GND  pwr
U6  VCC  pwr
U7  VCC  pwr
U8  NCSO  pas
U9  ASDO  pas
U10  VCC  pwr
U11  GND  pwr
U12  VCC  pwr
U13  GND  pwr
U14  VCC  pwr
U15  GND  pwr
U16  VCC  pwr
U17  GND  pwr
U18  VCC  pwr
U19  NC9  pas
U20  NCONFIG  pas
U21  NSTATUS  pas
U22  VCC  pwr
U23  VCC  pwr
U24  GND  pwr
U25  GXB_TX_L2P  pas
U26  GXB_TX_L2N  pas
U27  GND  pwr
U28  GND  pwr
V1  GXB_RX_R2N  pas
V2  GXB_RX_R2P  pas
V3  GND  pwr
V4  GND  pwr
V5  VCC  pwr
V6  GND  pwr
V7  NCEO  pas
V8  GND  pwr
V9  GND  pwr
V10  GND  pwr
V11  VCC  pwr
V12  GND  pwr
V13  VCC  pwr
V14  GND  pwr
V15  VCC  pwr
V16  GND  pwr
V17  VCC  pwr
V18  GND  pwr
V19  PORSEL  pas
V20  NCE  pas
V21  GND  pwr
V22  CONF_DONE  pas
V23  GND  pwr
V24  VCC  pwr
V25  GND  pwr
V26  GND  pwr
V27  GXB_RX_L2P  pas
V28  GXB_RX_L2N  pas
W1  GND  pwr
W2  GND  pwr
W3  GXB_CMURX_R1N  pas
W4  GXB_CMURX_R1P  pas
W5  GND  pwr
W6  VCC  pwr
W7  DCLK  pas
W8  IOW8
W9  VCC  pwr
W10  VCC  pwr
W11  IOW11
W12  IOW12
W13  GND  pwr
W14  VCC  pwr
W15  GND  pwr
W16  VCC  pwr
W17  GND  pwr
W18  VCC  pwr
W19  IOW19
W20  IOW20
W21  VCC  pwr
W22  IOW22
W23  VCC  pwr
W24  GND  pwr
W25  GXB_CMURX_L1P  pas
W26  GXB_CMURX_L1N  pas
W27  GND  pwr
W28  GND  pwr
Y1  GXB_CMURX_R0N  pas
Y2  GXB_CMURX_R0P  pas
Y3  GND  pwr
Y4  GND  pwr
Y5  VCC  pwr
Y6  GND  pwr
Y7  IOY7
Y8  IOY8
Y9  IOY9
Y10  IOY10
Y11  IOY11
Y12  VCC  pwr
Y13  IOY13
Y14  IOY14
Y15  IOY15
Y16  IOY16
Y17  IOY17
Y18  IOY18
Y19  IOY19
Y20  IOY20
Y21  IOY21
Y22  IOY22
Y23  GND  pwr
Y24  VCC  pwr
Y25  GND  pwr
Y26  GND  pwr
Y27  GXB_CMURX_L0P  pas
Y28  GXB_CMURX_L0N  pas

## Footprint FBGA780 (pad centres in mm)
780-Pin Hybrid FineLine Ball-Grid Array (HBGA) ? Flip Chip Auto generated by make-symbol-device-package-bsdl.ulp Rev. 29 Source: EP4SE230F29.bsd http://www.altera.com .. dspkg.pdf
smd 0.7 x 0.7: A2 -12.5,13.5; A3 -11.5,13.5; A4 -10.5,13.5; A5 -9.5,13.5; A6 -8.5,13.5; A7 -7.5,13.5; A8 -6.5,13.5; A9 -5.5,13.5; A10 -4.5,13.5; A11 -3.5,13.5; A12 -2.5,13.5; A13 -1.5,13.5; A14 -0.5,13.5; A15 0.5,13.5; A16 1.5,13.5; A17 2.5,13.5; A18 3.5,13.5; A19 4.5,13.5; A20 5.5,13.5; A21 6.5,13.5; A22 7.5,13.5; A23 8.5,13.5; A24 9.5,13.5; A25 10.5,13.5; A26 11.5,13.5; A27 12.5,13.5; AA1 -13.5,-6.5; AA2 -12.5,-6.5; AA3 -11.5,-6.5; AA4 -10.5,-6.5; AA5 -9.5,-6.5; AA6 -8.5,-6.5; AA7 -7.5,-6.5; AA8 -6.5,-6.5; AA9 -5.5,-6.5; AA10 -4.5,-6.5; AA11 -3.5,-6.5; AA12 -2.5,-6.5; AA13 -1.5,-6.5; AA14 -0.5,-6.5; AA15 0.5,-6.5; AA16 1.5,-6.5; AA17 2.5,-6.5; AA18 3.5,-6.5; AA19 4.5,-6.5; AA20 5.5,-6.5; AA21 6.5,-6.5; AA22 7.5,-6.5; AA23 8.5,-6.5; AA24 9.5,-6.5; AA25 10.5,-6.5; AA26 11.5,-6.5; AA27 12.5,-6.5; AA28 13.5,-6.5; AB1 -13.5,-7.5; AB2 -12.5,-7.5; AB3 -11.5,-7.5; AB4 -10.5,-7.5; AB5 -9.5,-7.5; AB6 -8.5,-7.5; AB7 -7.5,-7.5; AB8 -6.5,-7.5; AB9 -5.5,-7.5; AB10 -4.5,-7.5; AB11 -3.5,-7.5; AB12 -2.5,-7.5; AB13 -1.5,-7.5; AB14 -0.5,-7.5; AB15 0.5,-7.5; AB16 1.5,-7.5; AB17 2.5,-7.5; AB18 3.5,-7.5; AB19 4.5,-7.5; AB20 5.5,-7.5; AB21 6.5,-7.5; AB22 7.5,-7.5; AB23 8.5,-7.5; AB24 9.5,-7.5; AB25 10.5,-7.5; AB26 11.5,-7.5; AB27 12.5,-7.5; AB28 13.5,-7.5; AC1 -13.5,-8.5; AC2 -12.5,-8.5; AC3 -11.5,-8.5; AC4 -10.5,-8.5; AC5 -9.5,-8.5; AC6 -8.5,-8.5; AC7 -7.5,-8.5; AC8 -6.5,-8.5; AC9 -5.5,-8.5; AC10 -4.5,-8.5; AC11 -3.5,-8.5; AC12 -2.5,-8.5; AC13 -1.5,-8.5; AC14 -0.5,-8.5; AC15 0.5,-8.5; AC16 1.5,-8.5; AC17 2.5,-8.5; AC18 3.5,-8.5; AC19 4.5,-8.5; AC20 5.5,-8.5; AC21 6.5,-8.5; AC22 7.5,-8.5; AC23 8.5,-8.5; AC24 9.5,-8.5; AC25 10.5,-8.5; AC26 11.5,-8.5; AC27 12.5,-8.5; AC28 13.5,-8.5; AD1 -13.5,-9.5; AD2 -12.5,-9.5; AD3 -11.5,-9.5; AD4 -10.5,-9.5; AD5 -9.5,-9.5; AD6 -8.5,-9.5; AD7 -7.5,-9.5; AD8 -6.5,-9.5; AD9 -5.5,-9.5; AD10 -4.5,-9.5; AD11 -3.5,-9.5; AD12 -2.5,-9.5; AD13 -1.5,-9.5; AD14 -0.5,-9.5; AD15 0.5,-9.5; AD16 1.5,-9.5; AD17 2.5,-9.5; AD18 3.5,-9.5; AD19 4.5,-9.5; AD20 5.5,-9.5; AD21 6.5,-9.5; AD22 7.5,-9.5; AD23 8.5,-9.5; AD24 9.5,-9.5; AD25 10.5,-9.5; AD26 11.5,-9.5; AD27 12.5,-9.5; AD28 13.5,-9.5; AE1 -13.5,-10.5; AE2 -12.5,-10.5; AE3 -11.5,-10.5; AE4 -10.5,-10.5; AE5 -9.5,-10.5; AE6 -8.5,-10.5; AE7 -7.5,-10.5; AE8 -6.5,-10.5; AE9 -5.5,-10.5; AE10 -4.5,-10.5; AE11 -3.5,-10.5; AE12 -2.5,-10.5; AE13 -1.5,-10.5; AE14 -0.5,-10.5; AE15 0.5,-10.5; AE16 1.5,-10.5; AE17 2.5,-10.5; AE18 3.5,-10.5; AE19 4.5,-10.5; AE20 5.5,-10.5; AE21 6.5,-10.5; AE22 7.5,-10.5; AE23 8.5,-10.5; AE24 9.5,-10.5; AE25 10.5,-10.5; AE26 11.5,-10.5; AE27 12.5,-10.5; AE28 13.5,-10.5; AF1 -13.5,-11.5; AF2 -12.5,-11.5; AF3 -11.5,-11.5; AF4 -10.5,-11.5; AF5 -9.5,-11.5; AF6 -8.5,-11.5; AF7 -7.5,-11.5; AF8 -6.5,-11.5; AF9 -5.5,-11.5; AF10 -4.5,-11.5; AF11 -3.5,-11.5; AF12 -2.5,-11.5; AF13 -1.5,-11.5; AF14 -0.5,-11.5; AF15 0.5,-11.5; AF16 1.5,-11.5; AF17 2.5,-11.5; AF18 3.5,-11.5; AF19 4.5,-11.5; AF20 5.5,-11.5; AF21 6.5,-11.5; AF22 7.5,-11.5; AF23 8.5,-11.5; AF24 9.5,-11.5; AF25 10.5,-11.5; AF26 11.5,-11.5; AF27 12.5,-11.5; AF28 13.5,-11.5; AG1 -13.5,-12.5; AG2 -12.5,-12.5; AG3 -11.5,-12.5; AG4 -10.5,-12.5; AG5 -9.5,-12.5; AG6 -8.5,-12.5; AG7 -7.5,-12.5; AG8 -6.5,-12.5; AG9 -5.5,-12.5; AG10 -4.5,-12.5; AG11 -3.5,-12.5; AG12 -2.5,-12.5; AG13 -1.5,-12.5; AG14 -0.5,-12.5; AG15 0.5,-12.5; AG16 1.5,-12.5; AG17 2.5,-12.5; AG18 3.5,-12.5; AG19 4.5,-12.5; AG20 5.5,-12.5; AG21 6.5,-12.5; AG22 7.5,-12.5; AG23 8.5,-12.5; AG24 9.5,-12.5; AG25 10.5,-12.5; AG26 11.5,-12.5; AG27 12.5,-12.5; AG28 13.5,-12.5; AH2 -12.5,-13.5; AH3 -11.5,-13.5; AH4 -10.5,-13.5; AH5 -9.5,-13.5; AH6 -8.5,-13.5; AH7 -7.5,-13.5; AH8 -6.5,-13.5; AH9 -5.5,-13.5; AH10 -4.5,-13.5; AH11 -3.5,-13.5; AH12 -2.5,-13.5; AH13 -1.5,-13.5; AH14 -0.5,-13.5; AH15 0.5,-13.5; AH16 1.5,-13.5; AH17 2.5,-13.5; AH18 3.5,-13.5; AH19 4.5,-13.5; AH20 5.5,-13.5; AH21 6.5,-13.5; AH22 7.5,-13.5; AH23 8.5,-13.5; AH24 9.5,-13.5; AH25 10.5,-13.5; AH26 11.5,-13.5; AH27 12.5,-13.5; B1 -13.5,12.5; B2 -12.5,12.5; B3 -11.5,12.5; B4 -10.5,12.5; B5 -9.5,12.5; B6 -8.5,12.5; B7 -7.5,12.5; B8 -6.5,12.5; B9 -5.5,12.5; B10 -4.5,12.5; B11 -3.5,12.5; B12 -2.5,12.5; B13 -1.5,12.5; B14 -0.5,12.5; B15 0.5,12.5; B16 1.5,12.5; B17 2.5,12.5; B18 3.5,12.5; B19 4.5,12.5; B20 5.5,12.5; B21 6.5,12.5; B22 7.5,12.5; B23 8.5,12.5; B24 9.5,12.5; B25 10.5,12.5; B26 11.5,12.5; B27 12.5,12.5; B28 13.5,12.5; C1 -13.5,11.5; C2 -12.5,11.5; C3 -11.5,11.5; C4 -10.5,11.5; C5 -9.5,11.5; C6 -8.5,11.5; C7 -7.5,11.5; C8 -6.5,11.5; C9 -5.5,11.5; C10 -4.5,11.5; C11 -3.5,11.5; C12 -2.5,11.5; C13 -1.5,11.5; C14 -0.5,11.5; C15 0.5,11.5; C16 1.5,11.5; C17 2.5,11.5; C18 3.5,11.5; C19 4.5,11.5; C20 5.5,11.5; C21 6.5,11.5; C22 7.5,11.5; C23 8.5,11.5; C24 9.5,11.5; C25 10.5,11.5; C26 11.5,11.5; C27 12.5,11.5; C28 13.5,11.5; D1 -13.5,10.5; D2 -12.5,10.5; D3 -11.5,10.5; D4 -10.5,10.5; D5 -9.5,10.5; D6 -8.5,10.5; D7 -7.5,10.5; D8 -6.5,10.5; D9 -5.5,10.5; D10 -4.5,10.5; D11 -3.5,10.5; D12 -2.5,10.5; D13 -1.5,10.5; D14 -0.5,10.5; D15 0.5,10.5; D16 1.5,10.5; D17 2.5,10.5; D18 3.5,10.5; D19 4.5,10.5; D20 5.5,10.5; D21 6.5,10.5; D22 7.5,10.5; D23 8.5,10.5; D24 9.5,10.5; D25 10.5,10.5; D26 11.5,10.5; D27 12.5,10.5; D28 13.5,10.5; E1 -13.5,9.5; E2 -12.5,9.5; E3 -11.5,9.5; E4 -10.5,9.5; E5 -9.5,9.5; E6 -8.5,9.5; E7 -7.5,9.5; E8 -6.5,9.5; E9 -5.5,9.5; E10 -4.5,9.5; E11 -3.5,9.5; E12 -2.5,9.5; E13 -1.5,9.5; E14 -0.5,9.5; E15 0.5,9.5; E16 1.5,9.5; E17 2.5,9.5; E18 3.5,9.5; E19 4.5,9.5; E20 5.5,9.5; E21 6.5,9.5; E22 7.5,9.5; E23 8.5,9.5; E24 9.5,9.5; E25 10.5,9.5; E26 11.5,9.5; E27 12.5,9.5; E28 13.5,9.5; F1 -13.5,8.5; F2 -12.5,8.5; F3 -11.5,8.5; F4 -10.5,8.5; F5 -9.5,8.5; F6 -8.5,8.5; F7 -7.5,8.5; F8 -6.5,8.5; F9 -5.5,8.5; F10 -4.5,8.5; F11 -3.5,8.5; F12 -2.5,8.5; F13 -1.5,8.5; F14 -0.5,8.5; F15 0.5,8.5; F16 1.5,8.5; F17 2.5,8.5; F18 3.5,8.5; F19 4.5,8.5; F20 5.5,8.5; F21 6.5,8.5; F22 7.5,8.5; F23 8.5,8.5; F24 9.5,8.5; F25 10.5,8.5; F26 11.5,8.5; F27 12.5,8.5; F28 13.5,8.5; G1 -13.5,7.5; G2 -12.5,7.5; G3 -11.5,7.5; G4 -10.5,7.5; G5 -9.5,7.5; G6 -8.5,7.5; G7 -7.5,7.5; G8 -6.5,7.5; G9 -5.5,7.5; G10 -4.5,7.5; G11 -3.5,7.5; G12 -2.5,7.5; G13 -1.5,7.5; G14 -0.5,7.5; G15 0.5,7.5; G16 1.5,7.5; G17 2.5,7.5; G18 3.5,7.5; G19 4.5,7.5; G20 5.5,7.5; G21 6.5,7.5; G22 7.5,7.5; G23 8.5,7.5; G24 9.5,7.5; G25 10.5,7.5; G26 11.5,7.5; G27 12.5,7.5; G28 13.5,7.5; H1 -13.5,6.5; H2 -12.5,6.5; H3 -11.5,6.5; H4 -10.5,6.5; H5 -9.5,6.5; H6 -8.5,6.5; H7 -7.5,6.5; H8 -6.5,6.5; H9 -5.5,6.5; H10 -4.5,6.5; H11 -3.5,6.5; H12 -2.5,6.5; H13 -1.5,6.5; H14 -0.5,6.5; H15 0.5,6.5; H16 1.5,6.5; H17 2.5,6.5; H18 3.5,6.5; H19 4.5,6.5; H20 5.5,6.5; H21 6.5,6.5; H22 7.5,6.5; H23 8.5,6.5; H24 9.5,6.5; H25 10.5,6.5; H26 11.5,6.5; H27 12.5,6.5; H28 13.5,6.5; J1 -13.5,5.5; J2 -12.5,5.5; J3 -11.5,5.5; J4 -10.5,5.5; J5 -9.5,5.5; J6 -8.5,5.5; J7 -7.5,5.5; J8 -6.5,5.5; J9 -5.5,5.5; J10 -4.5,5.5; J11 -3.5,5.5; J12 -2.5,5.5; J13 -1.5,5.5; J14 -0.5,5.5; J15 0.5,5.5; J16 1.5,5.5; J17 2.5,5.5; J18 3.5,5.5; J19 4.5,5.5; J20 5.5,5.5; J21 6.5,5.5; J22 7.5,5.5; J23 8.5,5.5; J24 9.5,5.5; J25 10.5,5.5; J26 11.5,5.5; J27 12.5,5.5; J28 13.5,5.5; K1 -13.5,4.5; K2 -12.5,4.5; K3 -11.5,4.5; K4 -10.5,4.5; K5 -9.5,4.5; K6 -8.5,4.5; K7 -7.5,4.5; K8 -6.5,4.5; K9 -5.5,4.5; K10 -4.5,4.5; K11 -3.5,4.5; K12 -2.5,4.5; K13 -1.5,4.5; K14 -0.5,4.5; K15 0.5,4.5; K16 1.5,4.5; K17 2.5,4.5; K18 3.5,4.5; K19 4.5,4.5; K20 5.5,4.5; K21 6.5,4.5; K22 7.5,4.5; K23 8.5,4.5; K24 9.5,4.5; K25 10.5,4.5; K26 11.5,4.5; K27 12.5,4.5; K28 13.5,4.5; L1 -13.5,3.5; L2 -12.5,3.5; L3 -11.5,3.5; L4 -10.5,3.5; L5 -9.5,3.5; L6 -8.5,3.5; L7 -7.5,3.5; L8 -6.5,3.5; L9 -5.5,3.5; L10 -4.5,3.5; L11 -3.5,3.5; L12 -2.5,3.5; L13 -1.5,3.5; L14 -0.5,3.5; L15 0.5,3.5; L16 1.5,3.5; L17 2.5,3.5; L18 3.5,3.5; L19 4.5,3.5; L20 5.5,3.5; L21 6.5,3.5; L22 7.5,3.5; L23 8.5,3.5; L24 9.5,3.5; L25 10.5,3.5; L26 11.5,3.5; L27 12.5,3.5; L28 13.5,3.5; M1 -13.5,2.5; M2 -12.5,2.5; M3 -11.5,2.5; M4 -10.5,2.5; M5 -9.5,2.5; M6 -8.5,2.5; M7 -7.5,2.5; M8 -6.5,2.5; M9 -5.5,2.5; M10 -4.5,2.5; M11 -3.5,2.5; M12 -2.5,2.5; M13 -1.5,2.5; M14 -0.5,2.5; M15 0.5,2.5; M16 1.5,2.5; M17 2.5,2.5; M18 3.5,2.5; M19 4.5,2.5; M20 5.5,2.5; M21 6.5,2.5; M22 7.5,2.5; M23 8.5,2.5; M24 9.5,2.5; M25 10.5,2.5; M26 11.5,2.5; M27 12.5,2.5; M28 13.5,2.5; N1 -13.5,1.5; N2 -12.5,1.5; N3 -11.5,1.5; N4 -10.5,1.5; N5 -9.5,1.5; N6 -8.5,1.5; N7 -7.5,1.5; N8 -6.5,1.5; N9 -5.5,1.5; N10 -4.5,1.5; N11 -3.5,1.5; N12 -2.5,1.5; N13 -1.5,1.5; N14 -0.5,1.5; N15 0.5,1.5; N16 1.5,1.5; N17 2.5,1.5; N18 3.5,1.5; N19 4.5,1.5; N20 5.5,1.5; N21 6.5,1.5; N22 7.5,1.5; N23 8.5,1.5; N24 9.5,1.5; N25 10.5,1.5; N26 11.5,1.5; N27 12.5,1.5; N28 13.5,1.5; P1 -13.5,0.5; P2 -12.5,0.5; P3 -11.5,0.5; P4 -10.5,0.5; P5 -9.5,0.5; P6 -8.5,0.5; P7 -7.5,0.5; P8 -6.5,0.5; P9 -5.5,0.5; P10 -4.5,0.5; P11 -3.5,0.5; P12 -2.5,0.5; P13 -1.5,0.5; P14 -0.5,0.5; P15 0.5,0.5; P16 1.5,0.5; P17 2.5,0.5; P18 3.5,0.5; P19 4.5,0.5; P20 5.5,0.5; P21 6.5,0.5; P22 7.5,0.5; P23 8.5,0.5; P24 9.5,0.5; P25 10.5,0.5; P26 11.5,0.5; P27 12.5,0.5; P28 13.5,0.5; R1 -13.5,-0.5; R2 -12.5,-0.5; R3 -11.5,-0.5; R4 -10.5,-0.5; R5 -9.5,-0.5; R6 -8.5,-0.5; R7 -7.5,-0.5; R8 -6.5,-0.5; R9 -5.5,-0.5; R10 -4.5,-0.5; R11 -3.5,-0.5; R12 -2.5,-0.5; R13 -1.5,-0.5; R14 -0.5,-0.5; R15 0.5,-0.5; R16 1.5,-0.5; R17 2.5,-0.5; R18 3.5,-0.5; R19 4.5,-0.5; R20 5.5,-0.5; R21 6.5,-0.5; R22 7.5,-0.5; R23 8.5,-0.5; R24 9.5,-0.5; R25 10.5,-0.5; R26 11.5,-0.5; R27 12.5,-0.5; R28 13.5,-0.5; T1 -13.5,-1.5; T2 -12.5,-1.5; T3 -11.5,-1.5; T4 -10.5,-1.5; T5 -9.5,-1.5; T6 -8.5,-1.5; T7 -7.5,-1.5; T8 -6.5,-1.5; T9 -5.5,-1.5; T10 -4.5,-1.5; T11 -3.5,-1.5; T12 -2.5,-1.5; T13 -1.5,-1.5; T14 -0.5,-1.5; T15 0.5,-1.5; T16 1.5,-1.5; T17 2.5,-1.5; T18 3.5,-1.5; T19 4.5,-1.5; T20 5.5,-1.5; T21 6.5,-1.5; T22 7.5,-1.5; T23 8.5,-1.5; T24 9.5,-1.5; T25 10.5,-1.5; T26 11.5,-1.5; T27 12.5,-1.5; T28 13.5,-1.5; U1 -13.5,-2.5; U2 -12.5,-2.5; U3 -11.5,-2.5; U4 -10.5,-2.5; U5 -9.5,-2.5; U6 -8.5,-2.5; U7 -7.5,-2.5; U8 -6.5,-2.5; U9 -5.5,-2.5; U10 -4.5,-2.5; U11 -3.5,-2.5; U12 -2.5,-2.5; U13 -1.5,-2.5; U14 -0.5,-2.5; U15 0.5,-2.5; U16 1.5,-2.5; U17 2.5,-2.5; U18 3.5,-2.5; U19 4.5,-2.5; U20 5.5,-2.5; U21 6.5,-2.5; U22 7.5,-2.5; U23 8.5,-2.5; U24 9.5,-2.5; U25 10.5,-2.5; U26 11.5,-2.5; U27 12.5,-2.5; U28 13.5,-2.5; V1 -13.5,-3.5; V2 -12.5,-3.5; V3 -11.5,-3.5; V4 -10.5,-3.5; V5 -9.5,-3.5; V6 -8.5,-3.5; V7 -7.5,-3.5; V8 -6.5,-3.5; V9 -5.5,-3.5; V10 -4.5,-3.5; V11 -3.5,-3.5; V12 -2.5,-3.5; V13 -1.5,-3.5; V14 -0.5,-3.5; V15 0.5,-3.5; V16 1.5,-3.5; V17 2.5,-3.5; V18 3.5,-3.5; V19 4.5,-3.5; V20 5.5,-3.5; V21 6.5,-3.5; V22 7.5,-3.5; V23 8.5,-3.5; V24 9.5,-3.5; V25 10.5,-3.5; V26 11.5,-3.5; V27 12.5,-3.5; V28 13.5,-3.5; W1 -13.5,-4.5; W2 -12.5,-4.5; W3 -11.5,-4.5; W4 -10.5,-4.5; W5 -9.5,-4.5; W6 -8.5,-4.5; W7 -7.5,-4.5; W8 -6.5,-4.5; W9 -5.5,-4.5; W10 -4.5,-4.5; W11 -3.5,-4.5; W12 -2.5,-4.5; W13 -1.5,-4.5; W14 -0.5,-4.5; W15 0.5,-4.5; W16 1.5,-4.5; W17 2.5,-4.5; W18 3.5,-4.5; W19 4.5,-4.5; W20 5.5,-4.5; W21 6.5,-4.5; W22 7.5,-4.5; W23 8.5,-4.5; W24 9.5,-4.5; W25 10.5,-4.5; W26 11.5,-4.5; W27 12.5,-4.5; W28 13.5,-4.5; Y1 -13.5,-5.5; Y2 -12.5,-5.5; Y3 -11.5,-5.5; Y4 -10.5,-5.5; Y5 -9.5,-5.5; Y6 -8.5,-5.5; Y7 -7.5,-5.5; Y8 -6.5,-5.5; Y9 -5.5,-5.5; Y10 -4.5,-5.5; Y11 -3.5,-5.5; Y12 -2.5,-5.5; Y13 -1.5,-5.5; Y14 -0.5,-5.5; Y15 0.5,-5.5; Y16 1.5,-5.5; Y17 2.5,-5.5; Y18 3.5,-5.5; Y19 4.5,-5.5; Y20 5.5,-5.5; Y21 6.5,-5.5; Y22 7.5,-5.5; Y23 8.5,-5.5; Y24 9.5,-5.5; Y25 10.5,-5.5; Y26 11.5,-5.5; Y27 12.5,-5.5; Y28 13.5,-5.5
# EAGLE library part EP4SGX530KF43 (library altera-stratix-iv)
EP4SGX530KF43 edit this description Auto generated by make-symbol-device-package-bsdl.ulp Rev. 30 Source: EP4SGX530KF43.bsd

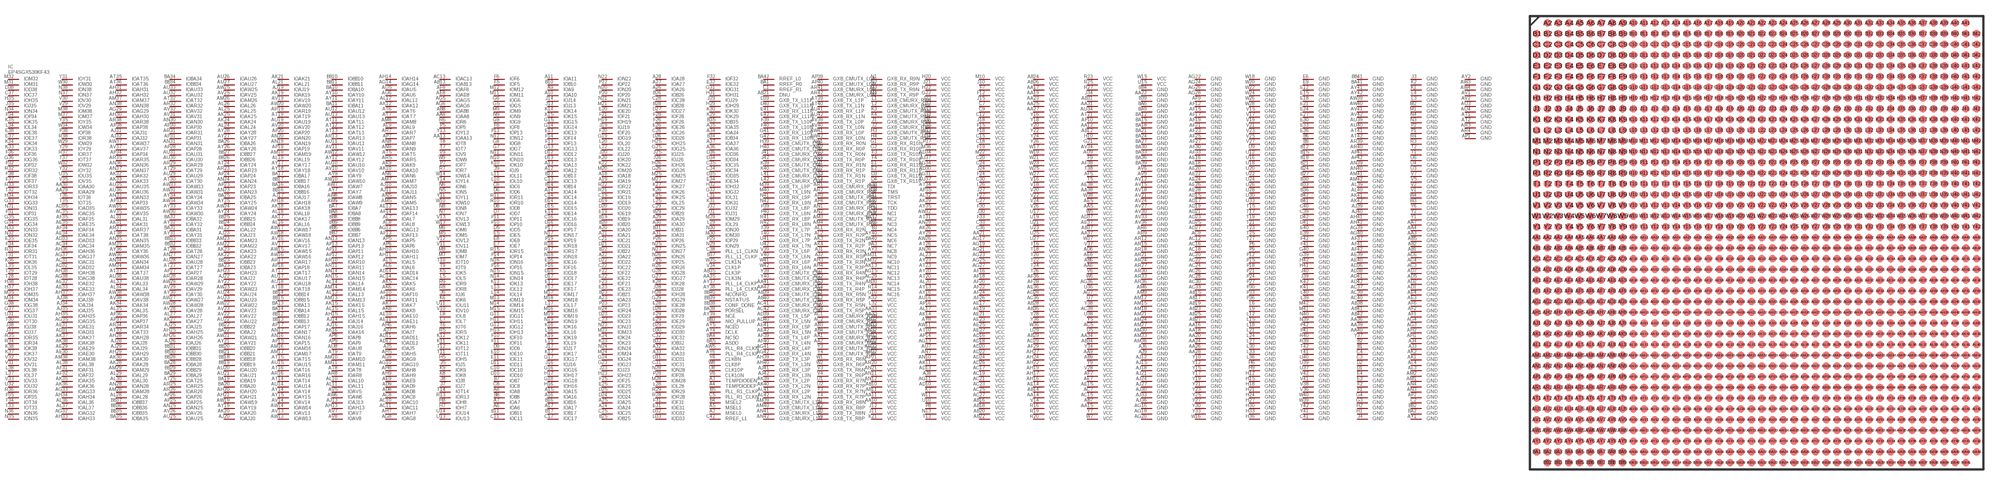
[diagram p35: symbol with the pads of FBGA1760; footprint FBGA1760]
Designator prefix IC

## EP4SGX530KF43 (MPN: EP4SGX530KF43C3N; OC_FARNELL: unknown; OC_NEWARK: 52R2020)  [FBGA1760]
A2  MSEL0  in
A3  TEMPDIODEN  in
A4  TEMPDIODEP  in
A5  MSEL1  in
A6  IOA6
A7  IOA7
A8  IOA8
A9  IOA9
A10  IOA10
A11  IOA11
A12  IOA12
A13  IOA13
A14  IOA14
A15  IOA15
A16  IOA16
A17  IOA17
A18  IOA18
A19  IOA19
A20  IOA20
A21  IOA21
A22  IOA22
A23  IOA23
A24  IOA24
A25  IOA25
A26  IOA26
A27  IOA27
A28  IOA28
A29  IOA29
A30  IOA30
A31  IOA31
A32  IOA32
A33  IOA33
A34  IOA34
A35  IOA35
A36  IOA36
A37  IOA37
A38  TDI  in
A39  NC1  pas
A40  TCK  in
A41  TRST  in
AA1  GXB_CMURX_R3N  pas
AA2  GXB_CMURX_R3P  pas
AA3  GND  pwr
AA4  GND  pwr
AA5  VCC  pwr
AA6  VCC  pwr
AA7  GND  pwr
AA8  IOAA8
AA9  VCC  pwr
AA10  VCC  pwr
AA11  VCC  pwr
AA12  VCC  pwr
AA13  IOAA13
AA14  VCC  pwr
AA15  VCC  pwr
AA16  GND  pwr
AA17  VCC  pwr
AA18  GND  pwr
AA19  VCC  pwr
AA20  GND  pwr
AA21  VCC  pwr
AA22  GND  pwr
AA23  VCC  pwr
AA24  GND  pwr
AA25  VCC  pwr
AA26  GND  pwr
AA27  VCC  pwr
AA28  GND  pwr
AA29  IOAA29
AA30  IOAA30
AA31  VCC  pwr
AA32  VCC  pwr
AA33  VCC  pwr
AA34  VCC  pwr
AA35  CLK3N  in
AA36  GND  pwr
AA37  VCC  pwr
AA38  VCC  pwr
AA39  GND  pwr
AA40  GND  pwr
AA41  GXB_CMURX_L3P  pas
AA42  GXB_CMURX_L3N  pas
AB1  GND  pwr
AB2  GND  pwr
AB3  GXB_CMUTX_R2N  pas
AB4  GXB_CMUTX_R2P  pas
AB5  GND  pwr
AB6  VCC  pwr
AB7  VCC  pwr
AB8  IOAB8
AB9  VCC  pwr
AB10  VCC  pwr
AB11  VCC  pwr
AB12  VCC  pwr
AB13  IOAB13
AB14  VCC  pwr
AB15  GND  pwr
AB16  VCC  pwr
AB17  GND  pwr
AB18  VCC  pwr
AB19  GND  pwr
AB20  VCC  pwr
AB21  DNU  pas
AB22  VCC  pwr
AB23  GND  pwr
AB24  VCC  pwr
AB25  GND  pwr
AB26  VCC  pwr
AB27  GND  pwr
AB28  VCC  pwr
AB29  VCC  pwr
AB30  NC14  pas
AB31  VCC  pwr
AB32  VCC  pwr
AB33  VCC  pwr
AB34  VCC  pwr
AB35  CLK3P  in
AB36  VCC  pwr
AB37  VCC  pwr
AB38  GND  pwr
AB39  GXB_CMUTX_L2P  pas
AB40  GXB_CMUTX_L2N  pas
AB41  GND  pwr
AB42  GND  pwr
AC1  GXB_CMURX_R2N  pas
AC2  GXB_CMURX_R2P  pas
AC3  GND  pwr
AC4  GND  pwr
AC5  VCC  pwr
AC6  GND  pwr
AC7  VCC  pwr
AC8  IOAC8
AC9  GND  pwr
AC10  IOAC10
AC11  IOAC11
AC12  GND  pwr
AC13  IOAC13
AC14  IOAC14
AC15  VCC  pwr
AC16  GND  pwr
AC17  VCC  pwr
AC18  GND  pwr
AC19  VCC  pwr
AC20  GND  pwr
AC21  VCC  pwr
AC22  GND  pwr
AC23  VCC  pwr
AC24  GND  pwr
AC25  VCC  pwr
AC26  GND  pwr
AC27  VCC  pwr
AC28  GND  pwr
AC29  NC13  pas
AC30  GND  pwr
AC31  IOAC31
AC33  GND  pwr
AC34  IOAC34
AC35  IOAC35
AC36  VCC  pwr
AC37  GND  pwr
AC38  VCC  pwr
AC39  GND  pwr
AC40  GND  pwr
AC41  GXB_CMURX_L2P  pas
AC42  GXB_CMURX_L2N  pas
AD1  GND  pwr
AD2  GND  pwr
AD3  GXB_TX_R5N  pas
AD4  GXB_TX_R5P  pas
AD5  GND  pwr
AD6  VCC  pwr
AD7  GND  pwr
AD8  IOAD8
AD9  IOAD9
AD10  VCC  pwr
AD11  IOAD11
AD12  IOAD12
AD13  VCC  pwr
AD14  IOAD14
AD15  GND  pwr
AD16  VCC  pwr
AD17  GND  pwr
AD18  VCC  pwr
AD19  GND  pwr
AD20  VCC  pwr
AD21  GND  pwr
AD22  VCC  pwr
AD23  GND  pwr
AD24  VCC  pwr
AD25  GND  pwr
AD26  VCC  pwr
AD27  GND  pwr
AD28  VCC  pwr
AD29  VCC  pwr
AD30  VCC  pwr
AD31  IOAD31
AD32  IOAD32
AD33  IOAD33
AD34  VCC  pwr
AD35  IOAD35
AD36  GND  pwr
AD37  VCC  pwr
AD38  GND  pwr
AD39  GXB_TX_L5P  pas
AD40  GXB_TX_L5N  pas
AD41  GND  pwr
AD42  GND  pwr
AE1  GXB_RX_R5N  pas
AE2  GXB_RX_R5P  pas
AE3  GND  pwr
AE4  GND  pwr
AE5  VCC  pwr
AE6  VCC  pwr
AE7  VCC  pwr
AE8  IOAE8
AE9  IOAE9
AE10  IOAE10
AE11  IOAE11
AE13  IOAE13
AE14  VCC  pwr
AE15  VCC  pwr
AE16  GND  pwr
AE17  VCC  pwr
AE18  GND  pwr
AE19  VCC  pwr
AE20  GND  pwr
AE21  VCC  pwr
AE22  GND  pwr
AE23  VCC  pwr
AE24  GND  pwr
AE25  VCC  pwr
AE26  GND  pwr
AE27  VCC  pwr
AE28  GND  pwr
AE29  IOAE29
AE30  IOAE30
AE31  IOAE31
AE32  IOAE32
AE33  IOAE33
AE34  IOAE34
AE35  IOAE35
AE36  VCC  pwr
AE37  VCC  pwr
AE38  VCC  pwr
AE39  GND  pwr
AE40  GND  pwr
AE41  GXB_RX_L5P  pas
AE42  GXB_RX_L5N  pas
AF1  GND  pwr
AF2  GND  pwr
AF3  GXB_TX_R4N  pas
AF4  GXB_TX_R4P  pas
AF5  VCC  pwr
AF6  GND  pwr
AF7  VCC  pwr
AF8  IOAF8
AF9  GND  pwr
AF10  IOAF10
AF11  IOAF11
AF12  GND  pwr
AF13  IOAF13
AF14  IOAF14
AF15  GND  pwr
AF16  VCC  pwr
AF17  GND  pwr
AF18  VCC  pwr
AF19  GND  pwr
AF20  VCC  pwr
AF21  GND  pwr
AF22  VCC  pwr
AF23  GND  pwr
AF24  VCC  pwr
AF25  GND  pwr
AF26  VCC  pwr
AF27  GND  pwr
AF28  VCC  pwr
AF29  VCC  pwr
AF30  GND  pwr
AF31  IOAF31
AF32  IOAF32
AF33  GND  pwr
AF34  IOAF34
AF35  IOAF35
AF36  VCC  pwr
AF37  GND  pwr
AF38  VCC  pwr
AF39  GXB_TX_L4P  pas
AF40  GXB_TX_L4N  pas
AF41  GND  pwr
AF42  GND  pwr
AG1  GXB_RX_R4N  pas
AG2  GXB_RX_R4P  pas
AG3  GND  pwr
AG4  GND  pwr
AG5  IOAG5
AG6  IOAG6
AG7  VCC  pwr
AG8  IOAG8
AG9  IOAG9
AG10  IOAG10
AG11  VCC  pwr
AG12  IOAG12
AG13  VCC  pwr
AG14  IOAG14
AG15  NC12  pas
AG16  GND  pwr
AG17  VCC  pwr
AG18  GND  pwr
AG19  VCC  pwr
AG20  GND  pwr
AG21  VCC  pwr
AG22  GND  pwr
AG23  VCC  pwr
AG24  GND  pwr
AG25  VCC  pwr
AG26  GND  pwr
AG27  VCC  pwr
AG28  GND  pwr
AG29  IOAG29
AG31  VCC  pwr
AG32  IOAG32
AG33  IOAG33
AG34  VCC  pwr
AG35  IOAG35
AG36  VCC  pwr
AG37  IOAG37
AG38  IOAG38
AG39  GND  pwr
AG40  GND  pwr
AG41  GXB_RX_L4P  pas
AG42  GXB_RX_L4N  pas
AH1  GND  pwr
AH2  GND  pwr
AH3  GXB_TX_R3N  pas
AH4  GXB_TX_R3P  pas
AH5  IOAH5
AH6  IOAH6
AH7  IOAH7
AH8  IOAH8
AH9  IOAH9
AH10  IOAH10
AH11  IOAH11
AH13  IOAH13
AH14  IOAH14
AH15  IOAH15
AH16  VCC  pwr
AH17  VCC  pwr
AH18  IOAH18
AH19  VCC  pwr
AH20  IOAH20
AH21  IOAH21
AH22  VCC  pwr
AH23  IOAH23
AH24  VCC  pwr
AH25  IOAH25
AH26  IOAH26
AH27  VCC  pwr
AH28  IOAH28
AH29  IOAH29
AH30  IOAH30
AH31  IOAH31
AH32  IOAH32
AH33  IOAH33
AH34  IOAH34
AH35  IOAH35
AH36  IOAH36
AH37  IOAH37
AH38  IOAH38
AH39  GXB_TX_L3P  pas
AH40  GXB_TX_L3N  pas
AH41  GND  pwr
AH42  GND  pwr
AJ1  GXB_RX_R3N  pas
AJ2  GXB_RX_R3P  pas
AJ3  GND  pwr
AJ4  GND  pwr
AJ5  IOAJ5
AJ6  GND  pwr
AJ7  IOAJ7
AJ8  VCC  pwr
AJ9  GND  pwr
AJ10  IOAJ10
AJ11  IOAJ11
AJ12  GND  pwr
AJ13  IOAJ13
AJ14  IOAJ14
AJ15  GND  pwr
AJ16  IOAJ16
AJ17  IOAJ17
AJ18  GND  pwr
AJ19  IOAJ19
AJ20  IOAJ20
AJ21  GND  pwr
AJ22  IOAJ22
AJ23  IOAJ23
AJ24  GND  pwr
AJ25  IOAJ25
AJ26  IOAJ26
AJ27  GND  pwr
AJ28  IOAJ28
AJ29  IOAJ29
AJ30  GND  pwr
AJ31  IOAJ31
AJ32  IOAJ32
AJ33  GND  pwr
AJ34  IOAJ34
AJ35  IOAJ35
AJ36  GND  pwr
AJ37  VCC  pwr
AJ38  IOAJ38
AJ39  GND  pwr
AJ40  GND  pwr
AJ41  GXB_RX_L3P  pas
AJ42  GXB_RX_L3N  pas
AK1  GND  pwr
AK2  GND  pwr
AK3  GXB_TX_R2N  pas
AK4  GXB_TX_R2P  pas
AK5  IOAK5
AK6  IOAK6
AK7  IOAK7
AK8  IOAK8
AK9  IOAK9
AK10  IOAK10
AK11  VCC  pwr
AK12  IOAK12
AK13  NC11  pas
AK14  VCC  pwr
AK15  IOAK15
AK16  IOAK16
AK17  IOAK17
AK18  IOAK18
AK19  IOAK19
AK20  IOAK20
AK21  IOAK21
AK22  IOAK22
AK23  IOAK23
AK24  IOAK24
AK25  IOAK25
AK26  VCC  pwr
AK27  IOAK27
AK28  IOAK28
AK29  VCC  pwr
AK30  IOAK30
AK31  IOAK31
AK32  IOAK32
AK33  IOAK33
AK34  IOAK34
AK35  IOAK35
AK36  IOAK36
AK37  IOAK37
AK38  IOAK38
AK39  GXB_TX_L2P  pas
AK40  GXB_TX_L2N  pas
AK41  GND  pwr
AK42  GND  pwr
AL1  GXB_RX_R2N  pas
AL2  GXB_RX_R2P  pas
AL3  GND  pwr
AL4  GND  pwr
AL5  IOAL5
AL6  IOAL6
AL7  IOAL7
AL8  IOAL8
AL9  IOAL9
AL10  IOAL10
AL11  IOAL11
AL12  IOAL12
AL13  IOAL13
AL14  IOAL14
AL15  IOAL15
AL16  IOAL16
AL17  VCC  pwr
AL18  IOAL18
AL19  IOAL19
AL20  VCC  pwr
AL21  IOAL21
AL22  IOAL22
AL23  VCC  pwr
AL24  IOAL24
AL25  IOAL25
AL26  IOAL26
AL27  IOAL27
AL28  IOAL28
AL29  IOAL29
AL30  IOAL30
AL31  IOAL31
AL32  VCC  pwr
AL33  IOAL33
AL34  IOAL34
AL35  IOAL35
AL36  IOAL36
AL37  IOAL37
AL38  IOAL38
AL39  GND  pwr
AL40  GND  pwr
AL41  GXB_RX_L2P  pas
AL42  GXB_RX_L2N  pas
AM1  GND  pwr
AM2  GND  pwr
AM3  GXB_CMUTX_R1N  pas
AM4  GXB_CMUTX_R1P  pas
AM5  IOAM5
AM6  GND  pwr
AM7  IOAM7
AM8  IOAM8
AM9  GND  pwr
AM10  IOAM10
AM11  IOAM11
AM12  GND  pwr
AM13  IOAM13
AM14  IOAM14
AM15  GND  pwr
AM16  IOAM16
AM17  IOAM17
AM18  GND  pwr
AM19  IOAM19
AM21  GND  pwr
AM22  IOAM22
AM23  IOAM23
AM24  GND  pwr
AM26  IOAM26
AM27  GND  pwr
AM28  IOAM28
AM29  IOAM29
AM30  GND  pwr
AM31  NC9  pas
AM32  NC10  pas
AM33  GND  pwr
AM34  IOAM34
AM35  IOAM35
AM36  GND  pwr
AM37  IOAM37
AM38  IOAM38
AM39  GXB_CMUTX_L1P  pas
AM40  GXB_CMUTX_L1N  pas
AM41  GND  pwr
AM42  GND  pwr
AN1  GXB_CMURX_R1N  pas
AN2  GXB_CMURX_R1P  pas
AN3  GND  pwr
AN4  GND  pwr
AN5  IOAN5
AN6  IOAN6
AN7  VCC  pwr
AN8  IOAN8
AN9  IOAN9
AN10  VCC  pwr
AN11  VCC  pwr
AN12  VCC  pwr
AN13  IOAN13
AN14  IOAN14
AN15  IOAN15
AN16  IOAN16
AN17  IOAN17
AN19  IOAN19
AN20  IOAN20
AN21  VCC  pwr
AN22  VCC  pwr
AN23  IOAN23
AN24  IOAN24
AN25  IOAN25
AN26  VCC  pwr
AN27  IOAN27
AN28  IOAN28
AN29  VCC  pwr
AN30  IOAN30
AN31  IOAN31
AN32  VCC  pwr
AN33  IOAN33
AN34  IOAN34
AN35  IOAN35
AN36  IOAN36
AN37  IOAN37
AN38  IOAN38
AN39  GND  pwr
AN40  GND  pwr
AN41  GXB_CMURX_L1P  pas
AN42  GXB_CMURX_L1N  pas
AP1  GND  pwr
AP2  GND  pwr
AP3  GXB_CMUTX_R0N  pas
AP4  GXB_CMUTX_R0P  pas
AP5  IOAP5
AP6  IOAP6
AP7  IOAP7
AP8  IOAP8
AP9  IOAP9
AP10  VCC  pwr
AP11  IOAP11
AP12  IOAP12
AP13  IOAP13
AP14  VCC  pwr
AP15  IOAP15
AP16  VCC  pwr
AP17  IOAP17
AP18  IOAP18
AP19  IOAP19
AP20  IOAP20
AP21  VCC  pwr
AP22  VCC  pwr
AP23  IOAP23
AP24  IOAP24
AP25  IOAP25
AP26  IOAP26
AP27  IOAP27
AP28  IOAP28
AP30  IOAP30
AP31  IOAP31
AP32  VCC  pwr
AP33  IOAP33
AP34  IOAP34
AP35  VCC  pwr
AP36  IOAP36
AP37  IOAP37
AP38  IOAP38
AP39  GXB_CMUTX_L0P  pas
AP40  GXB_CMUTX_L0N  pas
AP41  GND  pwr
AP42  GND  pwr
AR1  GXB_CMURX_R0N  pas
AR2  GXB_CMURX_R0P  pas
AR3  GND  pwr
AR4  GND  pwr
AR5  IOAR5
AR6  GND  pwr
AR7  IOAR7
AR8  IOAR8
AR9  GND  pwr
AR10  IOAR10
AR11  IOAR11
AR12  GND  pwr
AR13  IOAR13
AR15  GND  pwr
AR16  IOAR16
AR17  IOAR17
AR18  GND  pwr
AR19  IOAR19
AR20  VCC  pwr
AR21  GND  pwr
AR22  VCC  pwr
AR23  IOAR23
AR24  GND  pwr
AR25  IOAR25
AR26  IOAR26
AR27  GND  pwr
AR28  IOAR28
AR29  IOAR29
AR30  GND  pwr
AR31  IOAR31
AR32  IOAR32
AR33  GND  pwr
AR34  IOAR34
AR35  IOAR35
AR36  GND  pwr
AR37  IOAR37
AR38  IOAR38
AR39  GND  pwr
AR40  GND  pwr
AR41  GXB_CMURX_L0P  pas
AR42  GXB_CMURX_L0N  pas
AT1  GND  pwr
AT2  GND  pwr
AT3  GXB_TX_R1N  pas
AT4  GXB_TX_R1P  pas
AT5  IOAT5
AT6  IOAT6
AT7  IOAT7
AT8  IOAT8
AT9  IOAT9
AT10  VCC  pwr
AT11  IOAT11
AT12  IOAT12
AT13  IOAT13
AT14  IOAT14
AT15  IOAT15
AT16  IOAT16
AT17  IOAT17
AT18  IOAT18
AT19  IOAT19
AT20  VCC  pwr
AT21  VCC  pwr
AT23  VCC  pwr
AT24  IOAT24
AT25  IOAT25
AT26  VCC  pwr
AT27  IOAT27
AT28  IOAT28
AT29  IOAT29
AT30  IOAT30
AT31  VCC  pwr
AT32  IOAT32
AT33  IOAT33
AT34  VCC  pwr
AT35  IOAT35
AT36  IOAT36
AT37  IOAT37
AT38  IOAT38
AT39  GXB_TX_L1P  pas
AT40  GXB_TX_L1N  pas
AT41  GND  pwr
AT42  GND  pwr
AU1  GXB_RX_R1N  pas
AU2  GXB_RX_R1P  pas
AU3  GND  pwr
AU4  GND  pwr
AU5  IOAU5
AU6  IOAU6
AU7  VCC  pwr
AU8  IOAU8
AU9  VCC  pwr
AU10  IOAU10
AU11  IOAU11
AU12  IOAU12
AU13  IOAU13
AU14  IOAU14
AU15  IOAU15
AU16  VCC  pwr
AU17  IOAU17
AU18  IOAU18
AU19  IOAU19
AU20  IOAU20
AU21  IOAU21
AU22  IOAU22
AU23  IOAU23
AU24  IOAU24
AU25  IOAU25
AU26  IOAU26
AU27  IOAU27
AU28  IOAU28
AU29  IOAU29
AU30  IOAU30
AU31  IOAU31
AU32  IOAU32
AU33  IOAU33
AU34  VCC  pwr
AU35  IOAU35
AU36  IOAU36
AU37  VCC  pwr
AU38  IOAU38
AU39  GND  pwr
AU40  GND  pwr
AU41  GXB_RX_L1P  pas
AU42  GXB_RX_L1N  pas
AV1  GND  pwr
AV2  GND  pwr
AV3  GXB_TX_R0N  pas
AV4  GXB_TX_R0P  pas
AV5  IOAV5
AV6  GND  pwr
AV7  IOAV7
AV8  IOAV8
AV9  GND  pwr
AV10  IOAV10
AV11  IOAV11
AV12  GND  pwr
AV13  IOAV13
AV14  IOAV14
AV15  GND  pwr
AV16  IOAV16
AV17  IOAV17
AV18  GND  pwr
AV19  IOAV19
AV20  IOAV20
AV21  GND  pwr
AV22  IOAV22
AV23  IOAV23
AV24  GND  pwr
AV25  IOAV25
AV26  IOAV26
AV27  GND  pwr
AV28  IOAV28
AV29  IOAV29
AV30  GND  pwr
AV31  IOAV31
AV32  IOAV32
AV33  GND  pwr
AV34  VCC  pwr
AV35  IOAV35
AV36  GND  pwr
AV37  IOAV37
AV38  IOAV38
AV39  GXB_TX_L0P  pas
AV40  GXB_TX_L0N  pas
AV41  GND  pwr
AV42  GND  pwr
AW1  GXB_RX_R0N  pas
AW2  GXB_RX_R0P  pas
AW3  GND  pwr
AW4  GND  pwr
AW5  PLL_R4_CLKN  in
AW6  IOAW6
AW7  IOAW7
AW8  IOAW8
AW9  IOAW9
AW10  IOAW10
AW11  VCC  pwr
AW12  IOAW12
AW13  IOAW13
AW14  IOAW14
AW15  IOAW15
AW16  IOAW16
AW17  IOAW17
AW18  IOAW18
AW19  IOAW19
AW20  IOAW20
AW21  IOAW21
AW22  IOAW22
AW23  IOAW23
AW24  IOAW24
AW25  IOAW25
AW26  VCC  pwr
AW27  IOAW27
AW28  IOAW28
AW29  IOAW29
AW30  IOAW30
AW31  IOAW31
AW32  VCC  pwr
AW33  IOAW33
AW34  IOAW34
AW35  IOAW35
AW36  IOAW36
AW37  IOAW37
AW38  IOAW38
AW39  GND  pwr
AW40  GND  pwr
AW41  GXB_RX_L0P  pas
AW42  GXB_RX_L0N  pas
AY1  GND  pwr
AY2  GND  pwr
AY3  NC8  pas
AY4  DCLK  in
AY5  NCEO  in
AY6  PLL_R4_CLKP  in
AY7  IOAY7
AY8  VCC  pwr
AY9  IOAY9
AY10  IOAY10
AY11  IOAY11
AY12  IOAY12
AY13  VCC  pwr
AY14  IOAY14
AY15  IOAY15
AY16  VCC  pwr
AY17  IOAY17
AY18  IOAY18
AY19  IOAY19
AY20  VCC  pwr
AY21  IOAY21
AY22  IOAY22
AY23  VCC  pwr
AY24  IOAY24
AY25  IOAY25
AY26  IOAY26
AY27  IOAY27
AY28  IOAY28
AY29  VCC  pwr
AY30  IOAY30
AY31  IOAY31
AY32  IOAY32
AY33  IOAY33
AY34  IOAY34
AY35  VCC  pwr
AY36  IOAY36
AY37  PLL_L4_CLKP  in
AY38  PLL_L4_CLKN  in
AY39  NCE  in
AY40  NC5  pas
AY41  GND  pwr
AY42  GND  pwr
B1  GND  pwr
B2  GND  pwr
B3  NC4  pas
B4  MSEL2  in
B5  PLL_R1_CLKP  in
B6  GND  pwr
B7  IOB7
B8  IOB8
B9  GND  pwr
B10  IOB10
B11  IOB11
B12  GND  pwr
B13  IOB13
B14  IOB14
B15  GND  pwr
B16  IOB16
B17  IOB17
B18  GND  pwr
B19  IOB19
B20  IOB20
B21  GND  pwr
B22  IOB22
B23  IOB23
B24  GND  pwr
B25  IOB25
B26  IOB26
B27  GND  pwr
B28  IOB28
B29  IOB29
B30  GND  pwr
B31  IOB31
B32  IOB32
B33  GND  pwr
B34  IOB34
B35  IOB35
B36  GND  pwr
B37  PLL_L1_CLKP  in
B38  TMS  in
B39  GND  pwr
B40  TDO  out
B41  GND  pwr
B42  GND  pwr
BA1  RREF_R0  pas
BA2  GND  pwr
BA3  NC7  pas
BA4  NCSO  in
BA5  ASDO  in
BA6  GND  pwr
BA7  IOBA7
BA8  IOBA8
BA9  GND  pwr
BA10  IOBA10
BA11  IOBA11
BA12  GND  pwr
BA13  IOBA13
BA14  IOBA14
BA15  GND  pwr
BA16  IOBA16
BA17  IOBA17
BA18  GND  pwr
BA19  IOBA19
BA20  IOBA20
BA21  GND  pwr
BA22  IOBA22
BA23  IOBA23
BA24  GND  pwr
BA25  IOBA25
BA26  IOBA26
BA27  GND  pwr
BA28  IOBA28
BA29  IOBA29
BA30  GND  pwr
BA31  IOBA31
BA32  IOBA32
BA33  GND  pwr
BA34  IOBA34
BA35  IOBA35
BA36  GND  pwr
BA37  NC2  pas
BA38  PORSEL  in
BA39  GND  pwr
BA40  NC6  pas
BA41  GND  pwr
BA42  RREF_L0  pas
BB2  GND  pwr
BB3  NIO_PULLUP  in
BB4  GND  pwr
BB5  NC3  pas
BB6  IOBB6
BB7  IOBB7
BB8  IOBB8
BB9  IOBB9
BB10  IOBB10
BB11  IOBB11
BB12  IOBB12
BB13  IOBB13
BB14  IOBB14
BB15  IOBB15
BB16  IOBB16
BB17  IOBB17
BB18  IOBB18
BB19  IOBB19
BB20  IOBB20
BB21  IOBB21
BB22  IOBB22
BB23  IOBB23
BB24  IOBB24
BB25  IOBB25
BB26  IOBB26
BB27  IOBB27
BB28  IOBB28
BB29  IOBB29
BB30  IOBB30
BB31  IOBB31
BB32  IOBB32
BB33  IOBB33
BB34  IOBB34
BB35  IOBB35
BB36  IOBB36
BB37  IOBB37
BB38  CONF_DONE  in
BB39  NSTATUS  in
BB40  NCONFIG  in
BB41  GND  pwr
C1  RREF_R1  pas
C2  GND  pwr
C3  GND  pwr
C4  GND  pwr
C5  PLL_R1_CLKN  in
C6  IOC6
C7  VCC  pwr
C8  IOC8
C9  VCC  pwr
C10  IOC10
C11  IOC11
C12  VCC  pwr
C13  IOC13
C14  IOC14
C15  VCC  pwr
C16  IOC16
C17  IOC17
C18  VCC  pwr
C19  IOC19
C20  VCC  pwr
C21  IOC21
C22  IOC22
C23  IOC23
C24  VCC  pwr
C25  IOC25
C26  IOC26
C27  VCC  pwr
C28  IOC28
C29  IOC29
C30  VCC  pwr
C31  IOC31
C32  IOC32
C33  VCC  pwr
C34  IOC34
C35  IOC35
C36  VCC  pwr
C37  IOC37
C38  PLL_L1_CLKN  in
C39  GND  pwr
C40  GND  pwr
C41  GND  pwr
C42  RREF_L1  pas
D1  GND  pwr
D2  GND  pwr
D3  GXB_TX_R11N  pas
D4  GXB_TX_R11P  pas
D5  IOD5
D6  IOD6
D7  IOD7
D8  IOD8
D9  IOD9
D10  IOD10
D11  IOD11
D12  IOD12
D13  IOD13
D14  IOD14
D15  IOD15
D16  IOD16
D17  IOD17
D18  IOD18
D19  IOD19
D20  IOD20
D21  IOD21
D22  IOD22
D23  IOD23
D24  IOD24
D25  IOD25
D26  IOD26
D27  IOD27
D28  IOD28
D29  IOD29
D30  IOD30
D31  IOD31
D32  IOD32
D33  IOD33
D34  IOD34
D35  IOD35
D36  IOD36
D37  VCC  pwr
D38  IOD38
D39  GXB_TX_L11P  pas
D40  GXB_TX_L11N  pas
D41  GND  pwr
D42  GND  pwr
E1  GXB_RX_R11N  pas
E2  GXB_RX_R11P  pas
E3  GND  pwr
E4  GND  pwr
E5  IOE5
E6  GND  pwr
E7  IOE7
E8  IOE8
E9  GND  pwr
E10  IOE10
E11  IOE11
E12  GND  pwr
E13  IOE13
E14  IOE14
E15  GND  pwr
E16  IOE16
E17  IOE17
E18  GND  pwr
E19  IOE19
E20  IOE20
E21  GND  pwr
E22  IOE22
E23  IOE23
E24  GND  pwr
E25  IOE25
E26  IOE26
E27  GND  pwr
E28  IOE28
E29  IOE29
E30  GND  pwr
E31  IOE31
E32  IOE32
E33  GND  pwr
E34  IOE34
E35  IOE35
E36  GND  pwr
E37  IOE37
E38  IOE38
E39  GND  pwr
E40  GND  pwr
E41  GXB_RX_L11P  pas
E42  GXB_RX_L11N  pas
F1  GND  pwr
F2  GND  pwr
F3  GXB_TX_R10N  pas
F4  GXB_TX_R10P  pas
F5  IOF5
F6  IOF6
F7  VCC  pwr
F8  IOF8
F9  VCC  pwr
F10  IOF10
F11  IOF11
F12  VCC  pwr
F13  IOF13
F14  IOF14
F15  VCC  pwr
F16  IOF16
F17  IOF17
F18  VCC  pwr
F19  VCC  pwr
F20  IOF20
F21  IOF21
F22  IOF22
F23  IOF23
F24  VCC  pwr
F25  IOF25
F26  IOF26
F27  VCC  pwr
F28  IOF28
F29  IOF29
F30  VCC  pwr
F31  IOF31
F32  IOF32
F33  VCC  pwr
F34  IOF34
F35  VCC  pwr
F36  IOF36
F37  IOF37
F38  IOF38
F39  GXB_TX_L10P  pas
F40  GXB_TX_L10N  pas
F41  GND  pwr
F42  GND  pwr
G1  GXB_RX_R10N  pas
G2  GXB_RX_R10P  pas
G3  GND  pwr
G4  GND  pwr
G5  IOG5
G6  IOG6
G7  IOG7
G8  IOG8
G9  IOG9
G10  NC16  pas
G11  IOG11
G12  IOG12
G13  IOG13
G14  IOG14
G15  IOG15
G16  IOG16
G17  IOG17
G18  IOG18
G19  IOG19
G21  VCC  pwr
G22  VCC  pwr
G23  IOG23
G24  IOG24
G25  IOG25
G26  IOG26
G27  IOG27
G28  IOG28
G29  IOG29
G31  IOG31
G32  IOG32
G33  IOG33
G34  IOG34
G35  IOG35
G36  IOG36
G37  IOG37
G38  IOG38
G39  GND  pwr
G40  GND  pwr
G41  GXB_RX_L10P  pas
G42  GXB_RX_L10N  pas
H1  GND  pwr
H2  GND  pwr
H3  GXB_CMUTX_R5N  pas
H4  GXB_CMUTX_R5P  pas
H5  IOH5
H6  GND  pwr
H7  IOH7
H8  IOH8
H9  GND  pwr
H10  VCC  pwr
H11  IOH11
H12  GND  pwr
H13  IOH13
H15  GND  pwr
H16  IOH16
H17  IOH17
H18  GND  pwr
H19  IOH19
H20  VCC  pwr
H21  GND  pwr
H22  VCC  pwr
H23  IOH23
H24  GND  pwr
H25  IOH25
H26  IOH26
H27  GND  pwr
H28  IOH28
H29  IOH29
H30  GND  pwr
H31  IOH31
H32  IOH32
H33  GND  pwr
H34  IOH34
H35  IOH35
H36  GND  pwr
H37  IOH37
H38  IOH38
H39  GXB_CMUTX_L5P  pas
H40  GXB_CMUTX_L5N  pas
H41  GND  pwr
H42  GND  pwr
J1  GXB_CMURX_R5N  pas
J2  GXB_CMURX_R5P  pas
J3  GND  pwr
J4  GND  pwr
J5  IOJ5
J6  IOJ6
J7  IOJ7
J8  IOJ8
J9  IOJ9
J10  VCC  pwr
J11  VCC  pwr
J12  VCC  pwr
J13  IOJ13
J14  IOJ14
J15  VCC  pwr
J16  IOJ16
J17  IOJ17
J18  VCC  pwr
J19  IOJ19
J20  IOJ20
J21  VCC  pwr
J22  VCC  pwr
J23  IOJ23
J24  VCC  pwr
J25  IOJ25
J26  IOJ26
J27  VCC  pwr
J28  IOJ28
J29  IOJ29
J30  VCC  pwr
J31  IOJ31
J32  IOJ32
J33  VCC  pwr
J34  VCC  pwr
J35  IOJ35
J36  VCC  pwr
J37  IOJ37
J38  IOJ38
J39  GND  pwr
J40  GND  pwr
J41  GXB_CMURX_L5P  pas
J42  GXB_CMURX_L5N  pas
K1  GND  pwr
K2  GND  pwr
K3  GXB_CMUTX_R4N  pas
K4  GXB_CMUTX_R4P  pas
K5  IOK5
K6  IOK6
K7  VCC  pwr
K8  IOK8
K9  IOK9
K10  IOK10
K11  IOK11
K12  IOK12
K13  IOK13
K14  IOK14
K15  IOK15
K16  IOK16
K17  IOK17
K19  IOK19
K20  IOK20
K21  VCC  pwr
K22  IOK22
K23  IOK23
K24  IOK24
K25  IOK25
K26  IOK26
K27  IOK27
K28  IOK28
K29  IOK29
K30  IOK30
K31  IOK31
K32  VCC  pwr
K33  IOK33
K34  IOK34
K35  IOK35
K36  IOK36
K37  IOK37
K38  IOK38
K39  GXB_CMUTX_L4P  pas
K40  GXB_CMUTX_L4N  pas
K41  GND  pwr
K42  GND  pwr
L1  GXB_CMURX_R4N  pas
L2  GXB_CMURX_R4P  pas
L3  GND  pwr
L4  GND  pwr
L5  IOL5
L6  GND  pwr
L7  IOL7
L8  IOL8
L9  GND  pwr
L10  IOL10
L11  IOL11
L12  GND  pwr
L13  IOL13
L14  IOL14
L15  GND  pwr
L16  IOL16
L17  IOL17
L18  GND  pwr
L19  IOL19
L20  IOL20
L21  GND  pwr
L22  IOL22
L24  GND  pwr
L25  IOL25
L26  VCC  pwr
L27  GND  pwr
L28  IOL28
L29  IOL29
L30  GND  pwr
L31  IOL31
L32  VCC  pwr
L33  GND  pwr
L34  IOL34
L35  IOL35
L36  GND  pwr
L37  IOL37
L38  IOL38
L39  GND  pwr
L40  GND  pwr
L41  GXB_CMURX_L4P  pas
L42  GXB_CMURX_L4N  pas
M1  GND  pwr
M2  GND  pwr
M3  GXB_TX_R9N  pas
M4  GXB_TX_R9P  pas
M5  IOM5
M6  IOM6
M7  IOM7
M8  IOM8
M9  IOM9
M10  VCC  pwr
M11  IOM11
M12  IOM12
M13  IOM13
M14  IOM14
M15  IOM15
M16  IOM16
M17  IOM17
M18  IOM18
M19  IOM19
M20  IOM20
M21  IOM21
M22  VCC  pwr
M23  IOM23
M24  IOM24
M25  IOM25
M27  IOM27
M28  IOM28
M29  IOM29
M30  IOM30
M31  IOM31
M32  IOM32
M33  VCC  pwr
M34  IOM34
M35  IOM35
M36  VCC  pwr
M37  IOM37
M38  IOM38
M39  GXB_TX_L9P  pas
M40  GXB_TX_L9N  pas
M41  GND  pwr
M42  GND  pwr
N1  GXB_RX_R9N  pas
N2  GXB_RX_R9P  pas
N3  GND  pwr
N4  GND  pwr
N5  ION5
N6  ION6
N7  ION7
N8  ION8
N9  ION9
N10  ION10
N11  ION11
N12  ION12
N13  VCC  pwr
N14  ION14
N15  ION15
N16  ION16
N17  ION17
N18  ION18
N19  ION19
N20  ION20
N21  ION21
N22  ION22
N23  ION23
N24  ION24
N25  ION25
N26  ION26
N27  ION27
N28  ION28
N29  ION29
N30  ION30
N31  ION31
N32  ION32
N33  ION33
N34  ION34
N35  ION35
N36  ION36
N37  ION37
N38  ION38
N39  GND  pwr
N40  GND  pwr
N41  GXB_RX_L9P  pas
N42  GXB_RX_L9N  pas
P1  GND  pwr
P2  GND  pwr
P3  GXB_TX_R8N  pas
P4  GXB_TX_R8P  pas
P5  IOP5
P6  GND  pwr
P7  IOP7
P8  VCC  pwr
P9  GND  pwr
P10  IOP10
P11  IOP11
P12  GND  pwr
P13  IOP13
P14  IOP14
P15  GND  pwr
P16  IOP16
P17  IOP17
P18  GND  pwr
P19  IOP19
P20  IOP20
P21  GND  pwr
P22  IOP22
P23  IOP23
P24  GND  pwr
P25  IOP25
P26  IOP26
P27  GND  pwr
P28  IOP28
P29  IOP29
P30  GND  pwr
P31  IOP31
P32  IOP32
P33  GND  pwr
P34  IOP34
P35  IOP35
P36  GND  pwr
P37  VCC  pwr
P38  IOP38
P39  GXB_TX_L8P  pas
P40  GXB_TX_L8N  pas
P41  GND  pwr
P42  GND  pwr
R1  GXB_RX_R8N  pas
R2  GXB_RX_R8P  pas
R3  GND  pwr
R4  GND  pwr
R5  IOR5
R6  IOR6
R7  IOR7
R8  IOR8
R9  IOR9
R10  IOR10
R11  IOR11
R13  IOR13
R14  NC15  pas
R15  IOR15
R16  VCC  pwr
R17  IOR17
R18  IOR18
R19  VCC  pwr
R20  VCC  pwr
R21  IOR21
R22  IOR22
R23  VCC  pwr
R24  IOR24
R25  VCC  pwr
R26  IOR26
R27  VCC  pwr
R28  IOR28
R29  IOR29
R31  IOR31
R32  IOR32
R33  IOR33
R34  IOR34
R35  IOR35
R36  IOR36
R37  IOR37
R38  IOR38
R39  GND  pwr
R40  GND  pwr
R41  GXB_RX_L8P  pas
R42  GXB_RX_L8N  pas
T1  GND  pwr
T2  GND  pwr
T3  GXB_TX_R7N  pas
T4  GXB_TX_R7P  pas
T5  VCC  pwr
T6  IOT6
T7  IOT7
T8  IOT8
T9  IOT9
T10  IOT10
T11  IOT11
T12  IOT12
T13  VCC  pwr
T14  IOT14
T15  GND  pwr
T16  VCC  pwr
T17  GND  pwr
T18  VCC  pwr
T19  GND  pwr
T20  VCC  pwr
T21  GND  pwr
T22  VCC  pwr
T23  GND  pwr
T24  VCC  pwr
T25  GND  pwr
T26  VCC  pwr
T27  GND  pwr
T28  IOT28
T29  IOT29
T30  IOT30
T31  IOT31
T32  IOT32
T33  IOT33
T34  IOT34
T35  IOT35
T36  IOT36
T37  IOT37
T38  VCC  pwr
T39  GXB_TX_L7P  pas
T40  GXB_TX_L7N  pas
T41  GND  pwr
T42  GND  pwr
U1  GXB_RX_R7N  pas
U2  GXB_RX_R7P  pas
U3  GND  pwr
U4  GND  pwr
U5  VCC  pwr
U6  GND  pwr
U7  VCC  pwr
U8  CLK10P  in
U9  GND  pwr
U10  VCC  pwr
U11  IOU11
U12  GND  pwr
U13  IOU13
U14  IOU14
U15  VCC  pwr
U16  GND  pwr
U17  VCC  pwr
U18  GND  pwr
U19  VCC  pwr
U20  GND  pwr
U21  VCC  pwr
U22  GND  pwr
U23  VCC  pwr
U24  GND  pwr
U25  VCC  pwr
U26  GND  pwr
U27  VCC  pwr
U28  GND  pwr
U29  VCC  pwr
U30  GND  pwr
U31  IOU31
U32  IOU32
U33  GND  pwr
U34  VCC  pwr
U35  IOU35
U36  VCC  pwr
U37  GND  pwr
U38  VCC  pwr
U39  GND  pwr
U40  GND  pwr
U41  GXB_RX_L7P  pas
U42  GXB_RX_L7N  pas
V1  GND  pwr
V2  GND  pwr
V3  GXB_TX_R6N  pas
V4  GXB_TX_R6P  pas
V5  GND  pwr
V6  VCC  pwr
V7  GND  pwr
V8  CLK10N  in
V9  IOV9
V10  IOV10
V11  IOV11
V12  IOV12
V13  IOV13
V14  VCC  pwr
V15  GND  pwr
V16  VCC  pwr
V17  GND  pwr
V18  VCC  pwr
V19  GND  pwr
V20  VCC  pwr
V21  GND  pwr
V22  VCC  pwr
V23  GND  pwr
V24  VCC  pwr
V25  GND  pwr
V26  VCC  pwr
V27  GND  pwr
V28  VCC  pwr
V29  IOV29
V30  IOV30
V31  IOV31
V32  IOV32
V33  IOV33
V34  CLK1P  in
V35  IOV35
V36  GND  pwr
V37  VCC  pwr
V38  GND  pwr
V39  GXB_TX_L6P  pas
V40  GXB_TX_L6N  pas
V41  GND  pwr
V42  GND  pwr
W1  GXB_RX_R6N  pas
W2  GXB_RX_R6P  pas
W3  GND  pwr
W4  GND  pwr
W5  VCC  pwr
W6  VCC  pwr
W7  VCC  pwr
W8  CLK8P  in
W9  IOW9
W10  IOW10
W11  VCC  pwr
W13  IOW13
W14  IOW14
W15  VCC  pwr
W16  GND  pwr
W17  VCC  pwr
W18  GND  pwr
W19  VCC  pwr
W20  GND  pwr
W21  VCC  pwr
W22  GND  pwr
W23  VCC  pwr
W24  GND  pwr
W25  VCC  pwr
W26  GND  pwr
W27  VCC  pwr
W28  GND  pwr
W29  IOW29
W30  IOW30
W32  IOW32
W33  VCC  pwr
W34  IOW34
W35  CLK1N  in
W36  VCC  pwr
W37  VCC  pwr
W38  VCC  pwr
W39  GND  pwr
W40  GND  pwr
W41  GXB_RX_L6P  pas
W42  GXB_RX_L6N  pas
Y1  GND  pwr
Y2  GND  pwr
Y3  GXB_CMUTX_R3N  pas
Y4  GXB_CMUTX_R3P  pas
Y5  VCC  pwr
Y6  GND  pwr
Y7  VCC  pwr
Y8  CLK8N  in
Y9  VCC  pwr
Y10  GND  pwr
Y11  IOY11
Y12  GND  pwr
Y13  IOY13
Y14  IOY14
Y15  GND  pwr
Y16  VCC  pwr
Y17  GND  pwr
Y18  VCC  pwr
Y19  GND  pwr
Y20  VCC  pwr
Y21  GND  pwr
Y22  VCC  pwr
Y23  GND  pwr
Y24  VCC  pwr
Y25  GND  pwr
Y26  VCC  pwr
Y27  GND  pwr
Y28  VCC  pwr
Y29  IOY29
Y30  GND  pwr
Y31  IOY31
Y32  IOY32
Y33  GND  pwr
Y34  VCC  pwr
Y35  IOY35
Y36  VCC  pwr
Y37  GND  pwr
Y38  VCC  pwr
Y39  GXB_CMUTX_L3P  pas
Y40  GXB_CMUTX_L3N  pas
Y41  GND  pwr
Y42  GND  pwr

## Footprint FBGA1760 (pad centres in mm)
1760-Pin FineLine Ball-Grid Array (FBGA) - Flip Chip Auto generated by make-symbol-device-package-bsdl.ulp Rev. 29 Source: EP4SE530F43.bsd http://www.altera.com .. dspkg.pdf
smd 0.7 x 0.7: A2 -19.5,20.5; A3 -18.5,20.5; A4 -17.5,20.5; A5 -16.5,20.5; A6 -15.5,20.5; A7 -14.5,20.5; A8 -13.5,20.5; A9 -12.5,20.5; A10 -11.5,20.5; A11 -10.5,20.5; A12 -9.5,20.5; A13 -8.5,20.5; A14 -7.5,20.5; A15 -6.5,20.5; A16 -5.5,20.5; A17 -4.5,20.5; A18 -3.5,20.5; A19 -2.5,20.5; A20 -1.5,20.5; A21 -0.5,20.5; A22 0.5,20.5; A23 1.5,20.5; A24 2.5,20.5; A25 3.5,20.5; A26 4.5,20.5; A27 5.5,20.5; A28 6.5,20.5; A29 7.5,20.5; A30 8.5,20.5; A31 9.5,20.5; A32 10.5,20.5; A33 11.5,20.5; A34 12.5,20.5; A35 13.5,20.5; A36 14.5,20.5; A37 15.5,20.5; A38 16.5,20.5; A39 17.5,20.5; A40 18.5,20.5; A41 19.5,20.5; AA1 -20.5,0.5; AA2 -19.5,0.5; AA3 -18.5,0.5; AA4 -17.5,0.5; AA5 -16.5,0.5; AA6 -15.5,0.5; AA7 -14.5,0.5; AA8 -13.5,0.5; AA9 -12.5,0.5; AA10 -11.5,0.5; AA11 -10.5,0.5; AA12 -9.5,0.5; AA13 -8.5,0.5; AA14 -7.5,0.5; AA15 -6.5,0.5; AA16 -5.5,0.5; AA17 -4.5,0.5; AA18 -3.5,0.5; AA19 -2.5,0.5; AA20 -1.5,0.5; AA21 -0.5,0.5; AA22 0.5,0.5; AA23 1.5,0.5; AA24 2.5,0.5; AA25 3.5,0.5; AA26 4.5,0.5; AA27 5.5,0.5; AA28 6.5,0.5; AA29 7.5,0.5; AA30 8.5,0.5; AA31 9.5,0.5; AA32 10.5,0.5; AA33 11.5,0.5; AA34 12.5,0.5; AA35 13.5,0.5; AA36 14.5,0.5; AA37 15.5,0.5; AA38 16.5,0.5; AA39 17.5,0.5; AA40 18.5,0.5; AA41 19.5,0.5; AA42 20.5,0.5; AB1 -20.5,-0.5; AB2 -19.5,-0.5; AB3 -18.5,-0.5; AB4 -17.5,-0.5; AB5 -16.5,-0.5; AB6 -15.5,-0.5; AB7 -14.5,-0.5; AB8 -13.5,-0.5; AB9 -12.5,-0.5; AB10 -11.5,-0.5; AB11 -10.5,-0.5; AB12 -9.5,-0.5; AB13 -8.5,-0.5; AB14 -7.5,-0.5; AB15 -6.5,-0.5; AB16 -5.5,-0.5; AB17 -4.5,-0.5; AB18 -3.5,-0.5; AB19 -2.5,-0.5; AB20 -1.5,-0.5; AB21 -0.5,-0.5; AB22 0.5,-0.5; AB23 1.5,-0.5; AB24 2.5,-0.5; AB25 3.5,-0.5; AB26 4.5,-0.5; AB27 5.5,-0.5; AB28 6.5,-0.5; AB29 7.5,-0.5; AB30 8.5,-0.5; AB31 9.5,-0.5; AB32 10.5,-0.5; AB33 11.5,-0.5; AB34 12.5,-0.5; AB35 13.5,-0.5; AB36 14.5,-0.5; AB37 15.5,-0.5; AB38 16.5,-0.5; AB39 17.5,-0.5; AB40 18.5,-0.5; AB41 19.5,-0.5; AB42 20.5,-0.5; AC1 -20.5,-1.5; AC2 -19.5,-1.5; AC3 -18.5,-1.5; AC4 -17.5,-1.5; AC5 -16.5,-1.5; AC6 -15.5,-1.5; AC7 -14.5,-1.5; AC8 -13.5,-1.5; AC9 -12.5,-1.5; AC10 -11.5,-1.5; AC11 -10.5,-1.5; AC12 -9.5,-1.5; AC13 -8.5,-1.5; AC14 -7.5,-1.5; AC15 -6.5,-1.5; AC16 -5.5,-1.5; AC17 -4.5,-1.5; AC18 -3.5,-1.5; AC19 -2.5,-1.5; AC20 -1.5,-1.5; AC21 -0.5,-1.5; AC22 0.5,-1.5; AC23 1.5,-1.5; AC24 2.5,-1.5; AC25 3.5,-1.5; AC26 4.5,-1.5; AC27 5.5,-1.5; AC28 6.5,-1.5; AC29 7.5,-1.5; AC30 8.5,-1.5; AC31 9.5,-1.5; AC32 10.5,-1.5; AC33 11.5,-1.5; AC34 12.5,-1.5; AC35 13.5,-1.5; AC36 14.5,-1.5; AC37 15.5,-1.5; AC38 16.5,-1.5; AC39 17.5,-1.5; AC40 18.5,-1.5; AC41 19.5,-1.5; AC42 20.5,-1.5; AD1 -20.5,-2.5; AD2 -19.5,-2.5; AD3 -18.5,-2.5; AD4 -17.5,-2.5; AD5 -16.5,-2.5; AD6 -15.5,-2.5; AD7 -14.5,-2.5; AD8 -13.5,-2.5; AD9 -12.5,-2.5; AD10 -11.5,-2.5; AD11 -10.5,-2.5; AD12 -9.5,-2.5; AD13 -8.5,-2.5; AD14 -7.5,-2.5; AD15 -6.5,-2.5; AD16 -5.5,-2.5; AD17 -4.5,-2.5; AD18 -3.5,-2.5; AD19 -2.5,-2.5; AD20 -1.5,-2.5; AD21 -0.5,-2.5; AD22 0.5,-2.5; AD23 1.5,-2.5; AD24 2.5,-2.5; AD25 3.5,-2.5; AD26 4.5,-2.5; AD27 5.5,-2.5; AD28 6.5,-2.5; AD29 7.5,-2.5; AD30 8.5,-2.5; AD31 9.5,-2.5; AD32 10.5,-2.5; AD33 11.5,-2.5; AD34 12.5,-2.5; AD35 13.5,-2.5; AD36 14.5,-2.5; AD37 15.5,-2.5; AD38 16.5,-2.5; AD39 17.5,-2.5; AD40 18.5,-2.5; AD41 19.5,-2.5; AD42 20.5,-2.5; AE1 -20.5,-3.5; AE2 -19.5,-3.5; AE3 -18.5,-3.5; AE4 -17.5,-3.5; AE5 -16.5,-3.5; AE6 -15.5,-3.5; AE7 -14.5,-3.5; AE8 -13.5,-3.5; AE9 -12.5,-3.5; AE10 -11.5,-3.5; AE11 -10.5,-3.5; AE12 -9.5,-3.5; AE13 -8.5,-3.5; AE14 -7.5,-3.5; AE15 -6.5,-3.5; AE16 -5.5,-3.5; AE17 -4.5,-3.5; AE18 -3.5,-3.5; AE19 -2.5,-3.5; AE20 -1.5,-3.5; AE21 -0.5,-3.5; AE22 0.5,-3.5; AE23 1.5,-3.5; AE24 2.5,-3.5; AE25 3.5,-3.5; AE26 4.5,-3.5; AE27 5.5,-3.5; AE28 6.5,-3.5; AE29 7.5,-3.5; AE30 8.5,-3.5; AE31 9.5,-3.5; AE32 10.5,-3.5; AE33 11.5,-3.5; AE34 12.5,-3.5; AE35 13.5,-3.5; AE36 14.5,-3.5; AE37 15.5,-3.5; AE38 16.5,-3.5; AE39 17.5,-3.5; AE40 18.5,-3.5; AE41 19.5,-3.5; AE42 20.5,-3.5; AF1 -20.5,-4.5; AF2 -19.5,-4.5; AF3 -18.5,-4.5; AF4 -17.5,-4.5; AF5 -16.5,-4.5; AF6 -15.5,-4.5; AF7 -14.5,-4.5; AF8 -13.5,-4.5; AF9 -12.5,-4.5; AF10 -11.5,-4.5; AF11 -10.5,-4.5; AF12 -9.5,-4.5; AF13 -8.5,-4.5; AF14 -7.5,-4.5; AF15 -6.5,-4.5; AF16 -5.5,-4.5; AF17 -4.5,-4.5; AF18 -3.5,-4.5; AF19 -2.5,-4.5; AF20 -1.5,-4.5; AF21 -0.5,-4.5; AF22 0.5,-4.5; AF23 1.5,-4.5; AF24 2.5,-4.5; AF25 3.5,-4.5; AF26 4.5,-4.5; AF27 5.5,-4.5; AF28 6.5,-4.5; AF29 7.5,-4.5; AF30 8.5,-4.5; AF31 9.5,-4.5; AF32 10.5,-4.5; AF33 11.5,-4.5; AF34 12.5,-4.5; AF35 13.5,-4.5; AF36 14.5,-4.5; AF37 15.5,-4.5; AF38 16.5,-4.5; AF39 17.5,-4.5; AF40 18.5,-4.5; AF41 19.5,-4.5; AF42 20.5,-4.5; AG1 -20.5,-5.5; AG2 -19.5,-5.5; AG3 -18.5,-5.5; AG4 -17.5,-5.5; AG5 -16.5,-5.5; AG6 -15.5,-5.5; AG7 -14.5,-5.5; AG8 -13.5,-5.5; AG9 -12.5,-5.5; AG10 -11.5,-5.5; AG11 -10.5,-5.5; AG12 -9.5,-5.5; AG13 -8.5,-5.5; AG14 -7.5,-5.5; AG15 -6.5,-5.5; AG16 -5.5,-5.5; AG17 -4.5,-5.5; AG18 -3.5,-5.5; AG19 -2.5,-5.5; AG20 -1.5,-5.5; AG21 -0.5,-5.5; AG22 0.5,-5.5; AG23 1.5,-5.5; AG24 2.5,-5.5; AG25 3.5,-5.5; AG26 4.5,-5.5; AG27 5.5,-5.5; AG28 6.5,-5.5; AG29 7.5,-5.5; AG30 8.5,-5.5; AG31 9.5,-5.5; AG32 10.5,-5.5; AG33 11.5,-5.5; AG34 12.5,-5.5; AG35 13.5,-5.5; AG36 14.5,-5.5; AG37 15.5,-5.5; AG38 16.5,-5.5; AG39 17.5,-5.5; AG40 18.5,-5.5; AG41 19.5,-5.5; AG42 20.5,-5.5; AH1 -20.5,-6.5; AH2 -19.5,-6.5; AH3 -18.5,-6.5; AH4 -17.5,-6.5; AH5 -16.5,-6.5; AH6 -15.5,-6.5; AH7 -14.5,-6.5; AH8 -13.5,-6.5; AH9 -12.5,-6.5; AH10 -11.5,-6.5; AH11 -10.5,-6.5; AH12 -9.5,-6.5; AH13 -8.5,-6.5; AH14 -7.5,-6.5; AH15 -6.5,-6.5; AH16 -5.5,-6.5; AH17 -4.5,-6.5; AH18 -3.5,-6.5; AH19 -2.5,-6.5; AH20 -1.5,-6.5; AH21 -0.5,-6.5; AH22 0.5,-6.5; AH23 1.5,-6.5; AH24 2.5,-6.5; AH25 3.5,-6.5; AH26 4.5,-6.5; AH27 5.5,-6.5; AH28 6.5,-6.5; AH29 7.5,-6.5; AH30 8.5,-6.5; AH31 9.5,-6.5; AH32 10.5,-6.5; AH33 11.5,-6.5; AH34 12.5,-6.5; AH35 13.5,-6.5; AH36 14.5,-6.5; AH37 15.5,-6.5; AH38 16.5,-6.5; AH39 17.5,-6.5; AH40 18.5,-6.5; AH41 19.5,-6.5; AH42 20.5,-6.5; AJ1 -20.5,-7.5; AJ2 -19.5,-7.5; AJ3 -18.5,-7.5; AJ4 -17.5,-7.5; AJ5 -16.5,-7.5; AJ6 -15.5,-7.5; AJ7 -14.5,-7.5; AJ8 -13.5,-7.5; AJ9 -12.5,-7.5; AJ10 -11.5,-7.5; AJ11 -10.5,-7.5; AJ12 -9.5,-7.5; AJ13 -8.5,-7.5; AJ14 -7.5,-7.5; AJ15 -6.5,-7.5; AJ16 -5.5,-7.5; AJ17 -4.5,-7.5; AJ18 -3.5,-7.5; AJ19 -2.5,-7.5; AJ20 -1.5,-7.5; AJ21 -0.5,-7.5; AJ22 0.5,-7.5; AJ23 1.5,-7.5; AJ24 2.5,-7.5; AJ25 3.5,-7.5; AJ26 4.5,-7.5; AJ27 5.5,-7.5; AJ28 6.5,-7.5; AJ29 7.5,-7.5; AJ30 8.5,-7.5; AJ31 9.5,-7.5; AJ32 10.5,-7.5; AJ33 11.5,-7.5; AJ34 12.5,-7.5; AJ35 13.5,-7.5; AJ36 14.5,-7.5; AJ37 15.5,-7.5; AJ38 16.5,-7.5; AJ39 17.5,-7.5; AJ40 18.5,-7.5; AJ41 19.5,-7.5; AJ42 20.5,-7.5; AK1 -20.5,-8.5; AK2 -19.5,-8.5; AK3 -18.5,-8.5; AK4 -17.5,-8.5; AK5 -16.5,-8.5; AK6 -15.5,-8.5; AK7 -14.5,-8.5; AK8 -13.5,-8.5; AK9 -12.5,-8.5; AK10 -11.5,-8.5; AK11 -10.5,-8.5; AK12 -9.5,-8.5; AK13 -8.5,-8.5; AK14 -7.5,-8.5; AK15 -6.5,-8.5; AK16 -5.5,-8.5; AK17 -4.5,-8.5; AK18 -3.5,-8.5; AK19 -2.5,-8.5; AK20 -1.5,-8.5; AK21 -0.5,-8.5; AK22 0.5,-8.5; AK23 1.5,-8.5; AK24 2.5,-8.5; AK25 3.5,-8.5; AK26 4.5,-8.5; AK27 5.5,-8.5; AK28 6.5,-8.5; AK29 7.5,-8.5; AK30 8.5,-8.5; AK31 9.5,-8.5; AK32 10.5,-8.5; AK33 11.5,-8.5; AK34 12.5,-8.5; AK35 13.5,-8.5; AK36 14.5,-8.5; AK37 15.5,-8.5; AK38 16.5,-8.5; AK39 17.5,-8.5; AK40 18.5,-8.5; AK41 19.5,-8.5; AK42 20.5,-8.5; AL1 -20.5,-9.5; AL2 -19.5,-9.5; AL3 -18.5,-9.5; AL4 -17.5,-9.5; AL5 -16.5,-9.5; AL6 -15.5,-9.5; AL7 -14.5,-9.5; AL8 -13.5,-9.5; AL9 -12.5,-9.5; AL10 -11.5,-9.5; AL11 -10.5,-9.5; AL12 -9.5,-9.5; AL13 -8.5,-9.5; AL14 -7.5,-9.5; AL15 -6.5,-9.5; AL16 -5.5,-9.5; AL17 -4.5,-9.5; AL18 -3.5,-9.5; AL19 -2.5,-9.5; AL20 -1.5,-9.5; AL21 -0.5,-9.5; AL22 0.5,-9.5; AL23 1.5,-9.5; AL24 2.5,-9.5; AL25 3.5,-9.5; AL26 4.5,-9.5; AL27 5.5,-9.5; AL28 6.5,-9.5; AL29 7.5,-9.5; AL30 8.5,-9.5; AL31 9.5,-9.5; AL32 10.5,-9.5; AL33 11.5,-9.5; AL34 12.5,-9.5; AL35 13.5,-9.5; AL36 14.5,-9.5; AL37 15.5,-9.5; AL38 16.5,-9.5; AL39 17.5,-9.5; AL40 18.5,-9.5; AL41 19.5,-9.5; AL42 20.5,-9.5; AM1 -20.5,-10.5; AM2 -19.5,-10.5; AM3 -18.5,-10.5; AM4 -17.5,-10.5; AM5 -16.5,-10.5; AM6 -15.5,-10.5; AM7 -14.5,-10.5; AM8 -13.5,-10.5; AM9 -12.5,-10.5; AM10 -11.5,-10.5; AM11 -10.5,-10.5; AM12 -9.5,-10.5; AM13 -8.5,-10.5; AM14 -7.5,-10.5; AM15 -6.5,-10.5; AM16 -5.5,-10.5; AM17 -4.5,-10.5; AM18 -3.5,-10.5; AM19 -2.5,-10.5; AM20 -1.5,-10.5; AM21 -0.5,-10.5; AM22 0.5,-10.5; AM23 1.5,-10.5; AM24 2.5,-10.5; AM25 3.5,-10.5; AM26 4.5,-10.5; AM27 5.5,-10.5; AM28 6.5,-10.5; AM29 7.5,-10.5; AM30 8.5,-10.5; AM31 9.5,-10.5; AM32 10.5,-10.5; AM33 11.5,-10.5; AM34 12.5,-10.5; AM35 13.5,-10.5; AM36 14.5,-10.5; AM37 15.5,-10.5; AM38 16.5,-10.5; AM39 17.5,-10.5; AM40 18.5,-10.5; AM41 19.5,-10.5; AM42 20.5,-10.5; AN1 -20.5,-11.5; AN2 -19.5,-11.5; AN3 -18.5,-11.5; AN4 -17.5,-11.5; AN5 -16.5,-11.5; AN6 -15.5,-11.5; AN7 -14.5,-11.5; AN8 -13.5,-11.5; AN9 -12.5,-11.5; AN10 -11.5,-11.5; AN11 -10.5,-11.5; AN12 -9.5,-11.5; AN13 -8.5,-11.5; AN14 -7.5,-11.5; AN15 -6.5,-11.5; AN16 -5.5,-11.5; AN17 -4.5,-11.5; AN18 -3.5,-11.5; AN19 -2.5,-11.5; AN20 -1.5,-11.5; AN21 -0.5,-11.5; AN22 0.5,-11.5; AN23 1.5,-11.5; AN24 2.5,-11.5; AN25 3.5,-11.5; AN26 4.5,-11.5; AN27 5.5,-11.5; AN28 6.5,-11.5; AN29 7.5,-11.5; AN30 8.5,-11.5; AN31 9.5,-11.5; AN32 10.5,-11.5; AN33 11.5,-11.5; AN34 12.5,-11.5; AN35 13.5,-11.5; AN36 14.5,-11.5; AN37 15.5,-11.5; AN38 16.5,-11.5; AN39 17.5,-11.5; AN40 18.5,-11.5; AN41 19.5,-11.5; AN42 20.5,-11.5; AP1 -20.5,-12.5; AP2 -19.5,-12.5; AP3 -18.5,-12.5; AP4 -17.5,-12.5; AP5 -16.5,-12.5; AP6 -15.5,-12.5; AP7 -14.5,-12.5; AP8 -13.5,-12.5; AP9 -12.5,-12.5; AP10 -11.5,-12.5; AP11 -10.5,-12.5; AP12 -9.5,-12.5; AP13 -8.5,-12.5; AP14 -7.5,-12.5; AP15 -6.5,-12.5; AP16 -5.5,-12.5; AP17 -4.5,-12.5; AP18 -3.5,-12.5; AP19 -2.5,-12.5; AP20 -1.5,-12.5; AP21 -0.5,-12.5; AP22 0.5,-12.5; AP23 1.5,-12.5; AP24 2.5,-12.5; AP25 3.5,-12.5; AP26 4.5,-12.5; AP27 5.5,-12.5; AP28 6.5,-12.5; AP29 7.5,-12.5; AP30 8.5,-12.5; AP31 9.5,-12.5; AP32 10.5,-12.5; AP33 11.5,-12.5; AP34 12.5,-12.5; AP35 13.5,-12.5; AP36 14.5,-12.5; AP37 15.5,-12.5; AP38 16.5,-12.5; AP39 17.5,-12.5; AP40 18.5,-12.5; AP41 19.5,-12.5; AP42 20.5,-12.5; AR1 -20.5,-13.5; AR2 -19.5,-13.5; AR3 -18.5,-13.5; AR4 -17.5,-13.5; AR5 -16.5,-13.5; AR6 -15.5,-13.5; AR7 -14.5,-13.5; AR8 -13.5,-13.5; AR9 -12.5,-13.5; AR10 -11.5,-13.5; AR11 -10.5,-13.5; AR12 -9.5,-13.5; AR13 -8.5,-13.5; AR14 -7.5,-13.5; AR15 -6.5,-13.5; AR16 -5.5,-13.5; AR17 -4.5,-13.5; AR18 -3.5,-13.5; AR19 -2.5,-13.5; AR20 -1.5,-13.5; AR21 -0.5,-13.5; AR22 0.5,-13.5; AR23 1.5,-13.5; AR24 2.5,-13.5; AR25 3.5,-13.5; AR26 4.5,-13.5; AR27 5.5,-13.5; AR28 6.5,-13.5; AR29 7.5,-13.5; AR30 8.5,-13.5; AR31 9.5,-13.5; AR32 10.5,-13.5; AR33 11.5,-13.5; AR34 12.5,-13.5; AR35 13.5,-13.5; AR36 14.5,-13.5; AR37 15.5,-13.5; AR38 16.5,-13.5; AR39 17.5,-13.5; AR40 18.5,-13.5; AR41 19.5,-13.5; AR42 20.5,-13.5; AT1 -20.5,-14.5; AT2 -19.5,-14.5; AT3 -18.5,-14.5; AT4 -17.5,-14.5; AT5 -16.5,-14.5; AT6 -15.5,-14.5; AT7 -14.5,-14.5; AT8 -13.5,-14.5; AT9 -12.5,-14.5; AT10 -11.5,-14.5; AT11 -10.5,-14.5; AT12 -9.5,-14.5; AT13 -8.5,-14.5; AT14 -7.5,-14.5; AT15 -6.5,-14.5; AT16 -5.5,-14.5; AT17 -4.5,-14.5; AT18 -3.5,-14.5; AT19 -2.5,-14.5; AT20 -1.5,-14.5; AT21 -0.5,-14.5; AT22 0.5,-14.5; AT23 1.5,-14.5; AT24 2.5,-14.5; AT25 3.5,-14.5; AT26 4.5,-14.5; AT27 5.5,-14.5; AT28 6.5,-14.5; AT29 7.5,-14.5; AT30 8.5,-14.5; AT31 9.5,-14.5; AT32 10.5,-14.5; AT33 11.5,-14.5; AT34 12.5,-14.5; AT35 13.5,-14.5; AT36 14.5,-14.5; AT37 15.5,-14.5; AT38 16.5,-14.5; AT39 17.5,-14.5; AT40 18.5,-14.5; AT41 19.5,-14.5; AT42 20.5,-14.5; AU1 -20.5,-15.5; AU2 -19.5,-15.5; AU3 -18.5,-15.5; AU4 -17.5,-15.5; AU5 -16.5,-15.5; AU6 -15.5,-15.5; AU7 -14.5,-15.5; AU8 -13.5,-15.5; AU9 -12.5,-15.5; AU10 -11.5,-15.5; AU11 -10.5,-15.5; AU12 -9.5,-15.5; AU13 -8.5,-15.5; AU14 -7.5,-15.5; AU15 -6.5,-15.5; AU16 -5.5,-15.5; AU17 -4.5,-15.5; AU18 -3.5,-15.5; AU19 -2.5,-15.5; AU20 -1.5,-15.5; AU21 -0.5,-15.5; AU22 0.5,-15.5; AU23 1.5,-15.5; AU24 2.5,-15.5; AU25 3.5,-15.5; AU26 4.5,-15.5; AU27 5.5,-15.5; AU28 6.5,-15.5; AU29 7.5,-15.5; AU30 8.5,-15.5; AU31 9.5,-15.5; AU32 10.5,-15.5; AU33 11.5,-15.5; AU34 12.5,-15.5; AU35 13.5,-15.5; AU36 14.5,-15.5; AU37 15.5,-15.5; AU38 16.5,-15.5; AU39 17.5,-15.5; AU40 18.5,-15.5; AU41 19.5,-15.5; AU42 20.5,-15.5; AV1 -20.5,-16.5; AV2 -19.5,-16.5; AV3 -18.5,-16.5; AV4 -17.5,-16.5; AV5 -16.5,-16.5; AV6 -15.5,-16.5; AV7 -14.5,-16.5; AV8 -13.5,-16.5; AV9 -12.5,-16.5; AV10 -11.5,-16.5; AV11 -10.5,-16.5; AV12 -9.5,-16.5; AV13 -8.5,-16.5; AV14 -7.5,-16.5; AV15 -6.5,-16.5; AV16 -5.5,-16.5; AV17 -4.5,-16.5; AV18 -3.5,-16.5; AV19 -2.5,-16.5; AV20 -1.5,-16.5; AV21 -0.5,-16.5; AV22 0.5,-16.5; AV23 1.5,-16.5; AV24 2.5,-16.5; AV25 3.5,-16.5; AV26 4.5,-16.5; AV27 5.5,-16.5; AV28 6.5,-16.5; AV29 7.5,-16.5; AV30 8.5,-16.5; AV31 9.5,-16.5; AV32 10.5,-16.5; AV33 11.5,-16.5; AV34 12.5,-16.5; AV35 13.5,-16.5; AV36 14.5,-16.5; AV37 15.5,-16.5; AV38 16.5,-16.5; AV39 17.5,-16.5; AV40 18.5,-16.5; AV41 19.5,-16.5; AV42 20.5,-16.5; AW1 -20.5,-17.5; AW2 -19.5,-17.5; AW3 -18.5,-17.5; AW4 -17.5,-17.5; AW5 -16.5,-17.5; AW6 -15.5,-17.5; AW7 -14.5,-17.5; AW8 -13.5,-17.5; AW9 -12.5,-17.5; AW10 -11.5,-17.5; AW11 -10.5,-17.5; AW12 -9.5,-17.5; AW13 -8.5,-17.5; AW14 -7.5,-17.5; AW15 -6.5,-17.5; AW16 -5.5,-17.5; AW17 -4.5,-17.5; AW18 -3.5,-17.5; AW19 -2.5,-17.5; AW20 -1.5,-17.5; AW21 -0.5,-17.5; AW22 0.5,-17.5; AW23 1.5,-17.5; AW24 2.5,-17.5; AW25 3.5,-17.5; AW26 4.5,-17.5; AW27 5.5,-17.5; AW28 6.5,-17.5; AW29 7.5,-17.5; AW30 8.5,-17.5; AW31 9.5,-17.5; AW32 10.5,-17.5; AW33 11.5,-17.5; AW34 12.5,-17.5; AW35 13.5,-17.5; AW36 14.5,-17.5; AW37 15.5,-17.5; AW38 16.5,-17.5; AW39 17.5,-17.5; AW40 18.5,-17.5; AW41 19.5,-17.5; AW42 20.5,-17.5; AY1 -20.5,-18.5; AY2 -19.5,-18.5; AY3 -18.5,-18.5; AY4 -17.5,-18.5; AY5 -16.5,-18.5; AY6 -15.5,-18.5; AY7 -14.5,-18.5; AY8 -13.5,-18.5; AY9 -12.5,-18.5; AY10 -11.5,-18.5; AY11 -10.5,-18.5; AY12 -9.5,-18.5; AY13 -8.5,-18.5; AY14 -7.5,-18.5; AY15 -6.5,-18.5; AY16 -5.5,-18.5; AY17 -4.5,-18.5; AY18 -3.5,-18.5; AY19 -2.5,-18.5; AY20 -1.5,-18.5; AY21 -0.5,-18.5; AY22 0.5,-18.5; AY23 1.5,-18.5; AY24 2.5,-18.5; AY25 3.5,-18.5; AY26 4.5,-18.5; AY27 5.5,-18.5; AY28 6.5,-18.5; AY29 7.5,-18.5; AY30 8.5,-18.5; AY31 9.5,-18.5; AY32 10.5,-18.5; AY33 11.5,-18.5; AY34 12.5,-18.5; AY35 13.5,-18.5; AY36 14.5,-18.5; AY37 15.5,-18.5; AY38 16.5,-18.5; AY39 17.5,-18.5; AY40 18.5,-18.5; AY41 19.5,-18.5; AY42 20.5,-18.5; B1 -20.5,19.5; B2 -19.5,19.5; B3 -18.5,19.5; B4 -17.5,19.5; B5 -16.5,19.5; B6 -15.5,19.5; B7 -14.5,19.5; B8 -13.5,19.5; B9 -12.5,19.5; B10 -11.5,19.5; B11 -10.5,19.5; B12 -9.5,19.5; B13 -8.5,19.5; B14 -7.5,19.5; B15 -6.5,19.5; B16 -5.5,19.5; B17 -4.5,19.5; B18 -3.5,19.5; B19 -2.5,19.5; B20 -1.5,19.5; B21 -0.5,19.5; B22 0.5,19.5; B23 1.5,19.5; B24 2.5,19.5; B25 3.5,19.5; B26 4.5,19.5; B27 5.5,19.5; B28 6.5,19.5; B29 7.5,19.5; B30 8.5,19.5; B31 9.5,19.5; B32 10.5,19.5; B33 11.5,19.5; B34 12.5,19.5; B35 13.5,19.5; B36 14.5,19.5; B37 15.5,19.5; B38 16.5,19.5; B39 17.5,19.5; B40 18.5,19.5; B41 19.5,19.5; B42 20.5,19.5; BA1 -20.5,-19.5; BA2 -19.5,-19.5; BA3 -18.5,-19.5; BA4 -17.5,-19.5; BA5 -16.5,-19.5; BA6 -15.5,-19.5; BA7 -14.5,-19.5; BA8 -13.5,-19.5; BA9 -12.5,-19.5; BA10 -11.5,-19.5; BA11 -10.5,-19.5; BA12 -9.5,-19.5; BA13 -8.5,-19.5; BA14 -7.5,-19.5; BA15 -6.5,-19.5; BA16 -5.5,-19.5; BA17 -4.5,-19.5; BA18 -3.5,-19.5; BA19 -2.5,-19.5; BA20 -1.5,-19.5; BA21 -0.5,-19.5; BA22 0.5,-19.5; BA23 1.5,-19.5; BA24 2.5,-19.5; BA25 3.5,-19.5; BA26 4.5,-19.5; BA27 5.5,-19.5; BA28 6.5,-19.5; BA29 7.5,-19.5; BA30 8.5,-19.5; BA31 9.5,-19.5; BA32 10.5,-19.5; BA33 11.5,-19.5; BA34 12.5,-19.5; BA35 13.5,-19.5; BA36 14.5,-19.5; BA37 15.5,-19.5; BA38 16.5,-19.5; BA39 17.5,-19.5; BA40 18.5,-19.5; BA41 19.5,-19.5; BA42 20.5,-19.5; BB2 -19.5,-20.5; BB3 -18.5,-20.5; BB4 -17.5,-20.5; BB5 -16.5,-20.5; BB6 -15.5,-20.5; BB7 -14.5,-20.5; BB8 -13.5,-20.5; BB9 -12.5,-20.5; BB10 -11.5,-20.5; BB11 -10.5,-20.5; BB12 -9.5,-20.5; BB13 -8.5,-20.5; BB14 -7.5,-20.5; BB15 -6.5,-20.5; BB16 -5.5,-20.5; BB17 -4.5,-20.5; BB18 -3.5,-20.5; BB19 -2.5,-20.5; BB20 -1.5,-20.5; BB21 -0.5,-20.5; BB22 0.5,-20.5; BB23 1.5,-20.5; BB24 2.5,-20.5; BB25 3.5,-20.5; BB26 4.5,-20.5; BB27 5.5,-20.5; BB28 6.5,-20.5; BB29 7.5,-20.5; BB30 8.5,-20.5; BB31 9.5,-20.5; BB32 10.5,-20.5; BB33 11.5,-20.5; BB34 12.5,-20.5; BB35 13.5,-20.5; BB36 14.5,-20.5; BB37 15.5,-20.5; BB38 16.5,-20.5; BB39 17.5,-20.5; BB40 18.5,-20.5; BB41 19.5,-20.5; C1 -20.5,18.5; C2 -19.5,18.5; C3 -18.5,18.5; C4 -17.5,18.5; C5 -16.5,18.5; C6 -15.5,18.5; C7 -14.5,18.5; C8 -13.5,18.5; C9 -12.5,18.5; C10 -11.5,18.5; C11 -10.5,18.5; C12 -9.5,18.5; C13 -8.5,18.5; C14 -7.5,18.5; C15 -6.5,18.5; C16 -5.5,18.5; C17 -4.5,18.5; C18 -3.5,18.5; C19 -2.5,18.5; C20 -1.5,18.5; C21 -0.5,18.5; C22 0.5,18.5; C23 1.5,18.5; C24 2.5,18.5; C25 3.5,18.5; C26 4.5,18.5; C27 5.5,18.5; C28 6.5,18.5; C29 7.5,18.5; C30 8.5,18.5; C31 9.5,18.5; C32 10.5,18.5; C33 11.5,18.5; C34 12.5,18.5; C35 13.5,18.5; C36 14.5,18.5; C37 15.5,18.5; C38 16.5,18.5; C39 17.5,18.5; C40 18.5,18.5; C41 19.5,18.5; C42 20.5,18.5; D1 -20.5,17.5; D2 -19.5,17.5; D3 -18.5,17.5; D4 -17.5,17.5; D5 -16.5,17.5; D6 -15.5,17.5; D7 -14.5,17.5; D8 -13.5,17.5; D9 -12.5,17.5; D10 -11.5,17.5; D11 -10.5,17.5; D12 -9.5,17.5; D13 -8.5,17.5; D14 -7.5,17.5; D15 -6.5,17.5; D16 -5.5,17.5; D17 -4.5,17.5; D18 -3.5,17.5; D19 -2.5,17.5; D20 -1.5,17.5; D21 -0.5,17.5; D22 0.5,17.5; D23 1.5,17.5; D24 2.5,17.5; D25 3.5,17.5; D26 4.5,17.5; D27 5.5,17.5; D28 6.5,17.5; D29 7.5,17.5; D30 8.5,17.5; D31 9.5,17.5; D32 10.5,17.5; D33 11.5,17.5; D34 12.5,17.5; D35 13.5,17.5; D36 14.5,17.5; D37 15.5,17.5; D38 16.5,17.5; D39 17.5,17.5; D40 18.5,17.5; D41 19.5,17.5; D42 20.5,17.5; E1 -20.5,16.5; E2 -19.5,16.5; E3 -18.5,16.5; E4 -17.5,16.5; E5 -16.5,16.5; E6 -15.5,16.5; E7 -14.5,16.5; E8 -13.5,16.5; E9 -12.5,16.5; E10 -11.5,16.5; E11 -10.5,16.5; E12 -9.5,16.5; E13 -8.5,16.5; E14 -7.5,16.5; E15 -6.5,16.5; E16 -5.5,16.5; E17 -4.5,16.5; E18 -3.5,16.5; E19 -2.5,16.5; E20 -1.5,16.5; E21 -0.5,16.5; E22 0.5,16.5; E23 1.5,16.5; E24 2.5,16.5; E25 3.5,16.5; E26 4.5,16.5; E27 5.5,16.5; E28 6.5,16.5; E29 7.5,16.5; E30 8.5,16.5; E31 9.5,16.5; E32 10.5,16.5; E33 11.5,16.5; E34 12.5,16.5; E35 13.5,16.5; E36 14.5,16.5; E37 15.5,16.5; E38 16.5,16.5; E39 17.5,16.5; E40 18.5,16.5; E41 19.5,16.5; E42 20.5,16.5; F1 -20.5,15.5; F2 -19.5,15.5; F3 -18.5,15.5; F4 -17.5,15.5; F5 -16.5,15.5; F6 -15.5,15.5; F7 -14.5,15.5; F8 -13.5,15.5; F9 -12.5,15.5; F10 -11.5,15.5; F11 -10.5,15.5; F12 -9.5,15.5; F13 -8.5,15.5; F14 -7.5,15.5; F15 -6.5,15.5; F16 -5.5,15.5; F17 -4.5,15.5; F18 -3.5,15.5; F19 -2.5,15.5; F20 -1.5,15.5; F21 -0.5,15.5; F22 0.5,15.5; F23 1.5,15.5; F24 2.5,15.5; F25 3.5,15.5; F26 4.5,15.5; F27 5.5,15.5; F28 6.5,15.5; F29 7.5,15.5; F30 8.5,15.5; F31 9.5,15.5; F32 10.5,15.5; F33 11.5,15.5; F34 12.5,15.5; F35 13.5,15.5; F36 14.5,15.5; F37 15.5,15.5; F38 16.5,15.5; F39 17.5,15.5; F40 18.5,15.5; F41 19.5,15.5; F42 20.5,15.5; G1 -20.5,14.5; G2 -19.5,14.5; G3 -18.5,14.5; G4 -17.5,14.5; G5 -16.5,14.5; G6 -15.5,14.5; G7 -14.5,14.5; G8 -13.5,14.5; G9 -12.5,14.5; G10 -11.5,14.5; G11 -10.5,14.5; G12 -9.5,14.5; G13 -8.5,14.5; G14 -7.5,14.5; G15 -6.5,14.5; G16 -5.5,14.5; G17 -4.5,14.5; G18 -3.5,14.5; G19 -2.5,14.5; G20 -1.5,14.5; G21 -0.5,14.5; G22 0.5,14.5; G23 1.5,14.5; G24 2.5,14.5; G25 3.5,14.5; G26 4.5,14.5; G27 5.5,14.5; G28 6.5,14.5; G29 7.5,14.5; G30 8.5,14.5; G31 9.5,14.5; G32 10.5,14.5; G33 11.5,14.5; G34 12.5,14.5; G35 13.5,14.5; G36 14.5,14.5; G37 15.5,14.5; G38 16.5,14.5; G39 17.5,14.5; G40 18.5,14.5; G41 19.5,14.5; G42 20.5,14.5; H1 -20.5,13.5; H2 -19.5,13.5; H3 -18.5,13.5; H4 -17.5,13.5; H5 -16.5,13.5; H6 -15.5,13.5; H7 -14.5,13.5; H8 -13.5,13.5; H9 -12.5,13.5; H10 -11.5,13.5; H11 -10.5,13.5; H12 -9.5,13.5; H13 -8.5,13.5; H14 -7.5,13.5; H15 -6.5,13.5; H16 -5.5,13.5; H17 -4.5,13.5; H18 -3.5,13.5; H19 -2.5,13.5; H20 -1.5,13.5; H21 -0.5,13.5; H22 0.5,13.5; H23 1.5,13.5; H24 2.5,13.5; H25 3.5,13.5; H26 4.5,13.5; H27 5.5,13.5; H28 6.5,13.5; H29 7.5,13.5; H30 8.5,13.5; H31 9.5,13.5; H32 10.5,13.5; H33 11.5,13.5; H34 12.5,13.5; H35 13.5,13.5; H36 14.5,13.5; H37 15.5,13.5; H38 16.5,13.5; H39 17.5,13.5; H40 18.5,13.5; H41 19.5,13.5; H42 20.5,13.5; J1 -20.5,12.5; J2 -19.5,12.5; J3 -18.5,12.5; J4 -17.5,12.5; J5 -16.5,12.5; J6 -15.5,12.5; J7 -14.5,12.5; J8 -13.5,12.5; J9 -12.5,12.5; J10 -11.5,12.5; J11 -10.5,12.5; J12 -9.5,12.5; J13 -8.5,12.5; J14 -7.5,12.5; J15 -6.5,12.5; J16 -5.5,12.5; J17 -4.5,12.5; J18 -3.5,12.5; J19 -2.5,12.5; J20 -1.5,12.5; J21 -0.5,12.5; J22 0.5,12.5; J23 1.5,12.5; J24 2.5,12.5; J25 3.5,12.5; J26 4.5,12.5; J27 5.5,12.5; J28 6.5,12.5; J29 7.5,12.5; J30 8.5,12.5; J31 9.5,12.5; J32 10.5,12.5; J33 11.5,12.5; J34 12.5,12.5; J35 13.5,12.5; J36 14.5,12.5; J37 15.5,12.5; J38 16.5,12.5; J39 17.5,12.5; J40 18.5,12.5; J41 19.5,12.5; J42 20.5,12.5; K1 -20.5,11.5; K2 -19.5,11.5; K3 -18.5,11.5; K4 -17.5,11.5; K5 -16.5,11.5; K6 -15.5,11.5; K7 -14.5,11.5; K8 -13.5,11.5; K9 -12.5,11.5; K10 -11.5,11.5; K11 -10.5,11.5; K12 -9.5,11.5; K13 -8.5,11.5; K14 -7.5,11.5; K15 -6.5,11.5; K16 -5.5,11.5; K17 -4.5,11.5; K18 -3.5,11.5; K19 -2.5,11.5; K20 -1.5,11.5; K21 -0.5,11.5; K22 0.5,11.5; K23 1.5,11.5; K24 2.5,11.5; K25 3.5,11.5; K26 4.5,11.5; K27 5.5,11.5; K28 6.5,11.5; K29 7.5,11.5; K30 8.5,11.5; K31 9.5,11.5; K32 10.5,11.5; K33 11.5,11.5; K34 12.5,11.5; K35 13.5,11.5; K36 14.5,11.5; K37 15.5,11.5; K38 16.5,11.5; K39 17.5,11.5; K40 18.5,11.5; K41 19.5,11.5; K42 20.5,11.5; L1 -20.5,10.5; L2 -19.5,10.5; L3 -18.5,10.5; L4 -17.5,10.5; L5 -16.5,10.5; L6 -15.5,10.5; L7 -14.5,10.5; L8 -13.5,10.5; L9 -12.5,10.5; L10 -11.5,10.5; L11 -10.5,10.5; L12 -9.5,10.5; L13 -8.5,10.5; L14 -7.5,10.5; L15 -6.5,10.5; L16 -5.5,10.5; L17 -4.5,10.5; L18 -3.5,10.5; L19 -2.5,10.5; L20 -1.5,10.5; L21 -0.5,10.5; L22 0.5,10.5; L23 1.5,10.5; L24 2.5,10.5; L25 3.5,10.5; L26 4.5,10.5; L27 5.5,10.5; L28 6.5,10.5; L29 7.5,10.5; L30 8.5,10.5; L31 9.5,10.5; L32 10.5,10.5; L33 11.5,10.5; L34 12.5,10.5; L35 13.5,10.5; L36 14.5,10.5; L37 15.5,10.5; L38 16.5,10.5; L39 17.5,10.5; L40 18.5,10.5; L41 19.5,10.5; L42 20.5,10.5; M1 -20.5,9.5; M2 -19.5,9.5; M3 -18.5,9.5; M4 -17.5,9.5; M5 -16.5,9.5; M6 -15.5,9.5; M7 -14.5,9.5; M8 -13.5,9.5; M9 -12.5,9.5; M10 -11.5,9.5; M11 -10.5,9.5; M12 -9.5,9.5; M13 -8.5,9.5; M14 -7.5,9.5; M15 -6.5,9.5; M16 -5.5,9.5; M17 -4.5,9.5; M18 -3.5,9.5; M19 -2.5,9.5; M20 -1.5,9.5; M21 -0.5,9.5; M22 0.5,9.5; M23 1.5,9.5; M24 2.5,9.5; M25 3.5,9.5; M26 4.5,9.5; M27 5.5,9.5; M28 6.5,9.5; M29 7.5,9.5; M30 8.5,9.5; M31 9.5,9.5; M32 10.5,9.5; M33 11.5,9.5; M34 12.5,9.5; M35 13.5,9.5; M36 14.5,9.5; M37 15.5,9.5; M38 16.5,9.5; M39 17.5,9.5; M40 18.5,9.5; M41 19.5,9.5; M42 20.5,9.5; N1 -20.5,8.5; N2 -19.5,8.5; N3 -18.5,8.5; N4 -17.5,8.5; N5 -16.5,8.5; N6 -15.5,8.5; N7 -14.5,8.5; N8 -13.5,8.5; N9 -12.5,8.5; N10 -11.5,8.5; N11 -10.5,8.5; N12 -9.5,8.5; N13 -8.5,8.5; N14 -7.5,8.5; N15 -6.5,8.5; N16 -5.5,8.5; N17 -4.5,8.5; N18 -3.5,8.5; N19 -2.5,8.5; N20 -1.5,8.5; N21 -0.5,8.5; N22 0.5,8.5; N23 1.5,8.5; N24 2.5,8.5; N25 3.5,8.5; N26 4.5,8.5; N27 5.5,8.5; N28 6.5,8.5; N29 7.5,8.5; N30 8.5,8.5; N31 9.5,8.5; N32 10.5,8.5; N33 11.5,8.5; N34 12.5,8.5; N35 13.5,8.5; N36 14.5,8.5; N37 15.5,8.5; N38 16.5,8.5; N39 17.5,8.5; N40 18.5,8.5; N41 19.5,8.5; N42 20.5,8.5; P1 -20.5,7.5; P2 -19.5,7.5; P3 -18.5,7.5; P4 -17.5,7.5; P5 -16.5,7.5; P6 -15.5,7.5; P7 -14.5,7.5; P8 -13.5,7.5; P9 -12.5,7.5; P10 -11.5,7.5; P11 -10.5,7.5; P12 -9.5,7.5; P13 -8.5,7.5; P14 -7.5,7.5; P15 -6.5,7.5; P16 -5.5,7.5; P17 -4.5,7.5; P18 -3.5,7.5; P19 -2.5,7.5; P20 -1.5,7.5; P21 -0.5,7.5; P22 0.5,7.5; P23 1.5,7.5; P24 2.5,7.5; P25 3.5,7.5; P26 4.5,7.5; P27 5.5,7.5; P28 6.5,7.5; P29 7.5,7.5; P30 8.5,7.5; P31 9.5,7.5; P32 10.5,7.5; P33 11.5,7.5; P34 12.5,7.5; P35 13.5,7.5; P36 14.5,7.5; P37 15.5,7.5; P38 16.5,7.5; P39 17.5,7.5; P40 18.5,7.5; P41 19.5,7.5; P42 20.5,7.5; R1 -20.5,6.5; R2 -19.5,6.5; R3 -18.5,6.5; R4 -17.5,6.5; R5 -16.5,6.5; R6 -15.5,6.5; R7 -14.5,6.5; R8 -13.5,6.5; R9 -12.5,6.5; R10 -11.5,6.5; R11 -10.5,6.5; R12 -9.5,6.5; R13 -8.5,6.5; R14 -7.5,6.5; R15 -6.5,6.5; R16 -5.5,6.5; R17 -4.5,6.5; R18 -3.5,6.5; R19 -2.5,6.5; R20 -1.5,6.5; R21 -0.5,6.5; R22 0.5,6.5; R23 1.5,6.5; R24 2.5,6.5; R25 3.5,6.5; R26 4.5,6.5; R27 5.5,6.5; R28 6.5,6.5; R29 7.5,6.5; R30 8.5,6.5; R31 9.5,6.5; R32 10.5,6.5; R33 11.5,6.5; R34 12.5,6.5; R35 13.5,6.5; R36 14.5,6.5; R37 15.5,6.5; R38 16.5,6.5; R39 17.5,6.5; R40 18.5,6.5; R41 19.5,6.5; R42 20.5,6.5; T1 -20.5,5.5; T2 -19.5,5.5; T3 -18.5,5.5; T4 -17.5,5.5; T5 -16.5,5.5; T6 -15.5,5.5; T7 -14.5,5.5; T8 -13.5,5.5; T9 -12.5,5.5; T10 -11.5,5.5; T11 -10.5,5.5; T12 -9.5,5.5; T13 -8.5,5.5; T14 -7.5,5.5; T15 -6.5,5.5; T16 -5.5,5.5; T17 -4.5,5.5; T18 -3.5,5.5; T19 -2.5,5.5; T20 -1.5,5.5; T21 -0.5,5.5; T22 0.5,5.5; T23 1.5,5.5; T24 2.5,5.5; T25 3.5,5.5; T26 4.5,5.5; T27 5.5,5.5; T28 6.5,5.5; T29 7.5,5.5; T30 8.5,5.5; T31 9.5,5.5; T32 10.5,5.5; T33 11.5,5.5; T34 12.5,5.5; T35 13.5,5.5; T36 14.5,5.5; T37 15.5,5.5; T38 16.5,5.5; T39 17.5,5.5; T40 18.5,5.5; T41 19.5,5.5; T42 20.5,5.5; U1 -20.5,4.5; U2 -19.5,4.5; U3 -18.5,4.5; U4 -17.5,4.5; U5 -16.5,4.5; U6 -15.5,4.5; U7 -14.5,4.5; U8 -13.5,4.5; U9 -12.5,4.5; U10 -11.5,4.5; U11 -10.5,4.5; U12 -9.5,4.5; U13 -8.5,4.5; U14 -7.5,4.5; U15 -6.5,4.5; U16 -5.5,4.5; U17 -4.5,4.5; U18 -3.5,4.5; U19 -2.5,4.5; U20 -1.5,4.5; U21 -0.5,4.5; U22 0.5,4.5; U23 1.5,4.5; U24 2.5,4.5; U25 3.5,4.5; U26 4.5,4.5; U27 5.5,4.5; U28 6.5,4.5; U29 7.5,4.5; U30 8.5,4.5; U31 9.5,4.5; U32 10.5,4.5; U33 11.5,4.5; U34 12.5,4.5; U35 13.5,4.5; U36 14.5,4.5; U37 15.5,4.5; U38 16.5,4.5; U39 17.5,4.5; U40 18.5,4.5; U41 19.5,4.5; U42 20.5,4.5; V1 -20.5,3.5; V2 -19.5,3.5; V3 -18.5,3.5; V4 -17.5,3.5; V5 -16.5,3.5; V6 -15.5,3.5; V7 -14.5,3.5; V8 -13.5,3.5; V9 -12.5,3.5; V10 -11.5,3.5; V11 -10.5,3.5; V12 -9.5,3.5; V13 -8.5,3.5; V14 -7.5,3.5; V15 -6.5,3.5; V16 -5.5,3.5; V17 -4.5,3.5; V18 -3.5,3.5; V19 -2.5,3.5; V20 -1.5,3.5; V21 -0.5,3.5; V22 0.5,3.5; V23 1.5,3.5; V24 2.5,3.5; V25 3.5,3.5; V26 4.5,3.5; V27 5.5,3.5; V28 6.5,3.5; V29 7.5,3.5; V30 8.5,3.5; V31 9.5,3.5; V32 10.5,3.5; V33 11.5,3.5; V34 12.5,3.5; V35 13.5,3.5; V36 14.5,3.5; V37 15.5,3.5; V38 16.5,3.5; V39 17.5,3.5; V40 18.5,3.5; V41 19.5,3.5; V42 20.5,3.5; W1 -20.5,2.5; W2 -19.5,2.5; W3 -18.5,2.5; W4 -17.5,2.5; W5 -16.5,2.5; W6 -15.5,2.5; W7 -14.5,2.5; W8 -13.5,2.5; W9 -12.5,2.5; W10 -11.5,2.5; W11 -10.5,2.5; W12 -9.5,2.5; W13 -8.5,2.5; W14 -7.5,2.5; W15 -6.5,2.5; W16 -5.5,2.5; W17 -4.5,2.5; W18 -3.5,2.5; W19 -2.5,2.5; W20 -1.5,2.5; W21 -0.5,2.5; W22 0.5,2.5; W23 1.5,2.5; W24 2.5,2.5; W25 3.5,2.5; W26 4.5,2.5; W27 5.5,2.5; W28 6.5,2.5; W29 7.5,2.5; W30 8.5,2.5; W31 9.5,2.5; W32 10.5,2.5; W33 11.5,2.5; W34 12.5,2.5; W35 13.5,2.5; W36 14.5,2.5; W37 15.5,2.5; W38 16.5,2.5; W39 17.5,2.5; W40 18.5,2.5; W41 19.5,2.5; W42 20.5,2.5; Y1 -20.5,1.5; Y2 -19.5,1.5; Y3 -18.5,1.5; Y4 -17.5,1.5; Y5 -16.5,1.5; Y6 -15.5,1.5; Y7 -14.5,1.5; Y8 -13.5,1.5; Y9 -12.5,1.5; Y10 -11.5,1.5; Y11 -10.5,1.5; Y12 -9.5,1.5; Y13 -8.5,1.5; Y14 -7.5,1.5; Y15 -6.5,1.5; Y16 -5.5,1.5; Y17 -4.5,1.5; Y18 -3.5,1.5; Y19 -2.5,1.5; Y20 -1.5,1.5; Y21 -0.5,1.5; Y22 0.5,1.5; Y23 1.5,1.5; Y24 2.5,1.5; Y25 3.5,1.5; Y26 4.5,1.5; Y27 5.5,1.5; Y28 6.5,1.5; Y29 7.5,1.5; Y30 8.5,1.5; Y31 9.5,1.5; Y32 10.5,1.5; Y33 11.5,1.5; Y34 12.5,1.5; Y35 13.5,1.5; Y36 14.5,1.5; Y37 15.5,1.5; Y38 16.5,1.5; Y39 17.5,1.5; Y40 18.5,1.5; Y41 19.5,1.5; Y42 20.5,1.5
